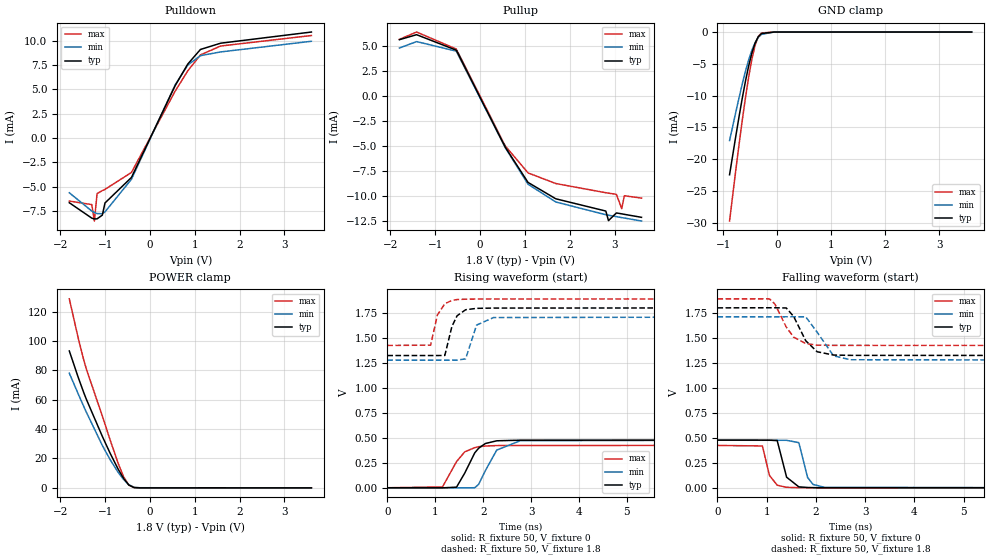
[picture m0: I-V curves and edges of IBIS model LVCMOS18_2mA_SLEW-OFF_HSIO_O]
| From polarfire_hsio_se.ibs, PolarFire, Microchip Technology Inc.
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|   Model LVCMOS18_2mA_SLEW-OFF_HSIO_O
[Model]   LVCMOS18_2mA_SLEW-OFF_HSIO_O
Model_type   Output
Polarity   Non-Inverting
Enable   Active-High
Vmeas =   0.9
Cref =   5p
Rref =   1M
|   typ   min   max
C_comp_pullup   1.335e-12   1.335e-12   1.380e-12
C_comp_pulldown  1.335e-12   1.335e-12   1.380e-12
[Temperature Range]  25C   100C   -40C
[Voltage Range]  1.8   1.71   1.89
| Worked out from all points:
|   slope of the pulldown table from 0 to 0.27 V, typ, clamps not added: 99.7 ohm
|   slope of the pullup table from 0 to 0.27 V, typ, clamps not added: 106 ohm
|   GND clamp passes 1 mA (typ) near -0.37 V on its own axis
|   POWER clamp passes 1 mA (typ) near -0.43 V on its own axis
|   rising waveform, R_fixture 50, V_fixture 0: 20-80 % time 313ps typ, 317ps min, 308ps max; typ from 0 V to 0.477 V
|   rising waveform, R_fixture 50, V_fixture 1.8: 20-80 % time 169ps typ, 176ps min, 162ps max; typ from 1.32 V to 1.8 V
|   falling waveform, R_fixture 50, V_fixture 0: 20-80 % time 145ps typ, 151ps min, 133ps max; typ from 0.477 V to 0 V
|   falling waveform, R_fixture 50, V_fixture 1.8: 20-80 % time 319ps typ, 303ps min, 311ps max; typ from 1.8 V to 1.32 V
[GND Clamp]
| Voltage   I(typ)   I(min)   I(max)
-885.9mV  -22.44mA   -17.06mA   -29.71mA
-767.8mV  -16.25mA   -12.52mA   -21.53mA
-708.7mV  -13.24mA   -10.28mA   -17.6mA
-649.7mV  -10.37mA   -8.138mA   -13.83mA
-590.6mV  -7.705mA   -6.148mA   -10.3mA
-531.6mV  -5.322mA   -4.371mA   -7.074mA
-472.5mV  -3.308mA   -2.865mA   -4.286mA
-413.4mV  -1.757mA   -1.684mA   -2.101mA
-354.4mV  -739.5uA   -855.1uA   -713.7uA
-295.3mV  -232.3uA   -363.2uA   -148.3uA
-59.06mV  -489.8nA   -2.616uA   -234.3nA
3.6V      0A         0A         0A
[POWER Clamp]
| Voltage   I(typ)   I(min)   I(max)
-1.8V     93.16mA    78.01mA    128.6mA
-1.595V   74.64mA    63.48mA    101.1mA
-1.477V   64.73mA    55.33mA    86.9mA
-1.417V   60.07mA    51.32mA    80.62mA
-1.063V   35.01mA    28.82mA    48.82mA
-885.9mV  23.32mA    19.01mA    32.31mA
-708.7mV  12.62mA    10.48mA    16.53mA
-590.6mV  6.476mA    5.751mA    7.626mA
-472.5mV  1.932mA    2.149mA    1.873mA
-354.4mV  154uA      351.2uA    209.6uA
-236.2mV  4.969uA    79.11uA    52.63uA
3.6V      0A         0A         0A
[Pullup]
| Voltage   I(typ)   I(min)   I(max)
-1.8V     5.675mA    4.838mA    5.71mA
-1.417V   6.176mA    5.485mA    6.443mA
-531.6mV  4.619mA    4.521mA    4.733mA
562.5mV   -5.136mA   -5.176mA   -5.006mA
1.069V    -8.657mA   -8.838mA   -7.701mA
1.688V    -10.3mA    -10.62mA   -8.767mA
2.804V    -11.53mA   -11.9mA    -9.691mA
2.863V    -12.49mA   -11.95mA   -9.732mA
3.04V     -11.72mA   -12.09mA   -9.855mA
3.158V    -11.81mA   -12.19mA   -11.29mA
3.217V    -11.86mA   -12.23mA   -9.994mA
3.6V      -12.16mA   -12.53mA   -10.23mA
[Pulldown]
| Voltage   I(typ)   I(min)   I(max)
-1.8V     -6.666mA   -5.639mA   -6.495mA
-1.299V   -8.251mA   -7.52mA    -6.857mA
-1.24V    -8.335mA   -7.673mA   -8.549mA
-1.181V   -8.326mA   -7.787mA   -5.727mA
-1.063V   -7.941mA   -7.79mA    -5.412mA
-1.004V   -6.69mA    -7.608mA   -5.288mA
-413.4mV  -4.058mA   -4.243mA   -3.547mA
562.5mV   5.408mA    5.494mA    4.84mA
843.8mV   7.63mA     7.525mA    6.932mA
1.125V    9.124mA    8.486mA    8.564mA
1.575V    9.769mA    8.87mA     9.478mA
3.6V      10.92mA    9.969mA    10.56mA
[Ramp]
dV/dt_r   0.286369/0.313004n  0.285848/0.317021n  0.254387/0.307782n
dV/dt_f   0.285972/0.318969n  0.259822/0.302939n  0.279803/0.310814n
R_load = 50
[Rising Waveform]
R_fixture = 50
V_fixture = 0
V_fixture_min = 0
V_fixture_max = 0
| Time   V(typ)   V(min)   V(max)
0s        3.09uV     3.497uV    6.32uV
1.152ns   -646.7uV   -643.3uV   8.588mV
1.444ns   5.878mV    -807.3uV   261.4mV
1.617ns   147.8mV    -904.4uV   359.8mV
1.825ns   349.4mV    452.6uV    401.6mV
1.906ns   395.7mV    34.22mV    410.8mV
2.046ns   442.7mV    170.9mV    417.5mV
2.284ns   469.9mV    377.5mV    422.1mV
2.779ns   476mV      471.3mV    423.2mV
10ns      477.3mV    476.4mV    424mV
[Rising Waveform]
R_fixture = 50
V_fixture = 1.8
V_fixture_min = 1.71
V_fixture_max = 1.89
| Time   V(typ)   V(min)   V(max)
0s        1.323V     1.277V     1.424V
904ps     1.323V     1.277V     1.427V
1.045ns   1.323V     1.277V     1.729V
1.2ns     1.324V     1.277V     1.841V
1.348ns   1.614V     1.277V     1.875V
1.456ns   1.721V     1.277V     1.883V
1.634ns   1.781V     1.29V      1.887V
1.863ns   1.795V     1.628V     1.888V
2.218ns   1.798V     1.703V     1.889V
10ns      1.8V       1.71V      1.89V
[Falling Waveform]
R_fixture = 50
V_fixture = 0
V_fixture_min = 0
V_fixture_max = 0
| Time   V(typ)   V(min)   V(max)
0s        477.3mV    476.4mV    424mV
913ps     476.9mV    475.8mV    418.9mV
1.057ns   476.8mV    475.7mV    123.5mV
1.214ns   472.7mV    475.6mV    26.48mV
1.405ns   106.4mV    475.5mV    5.314mV
1.653ns   10.03mV    452.1mV    1.813mV
1.832ns   3.488mV    103mV      904.7uV
1.942ns   2.057mV    34.14mV    804.2uV
2.177ns   1.116mV    5.153mV    781uV
10ns      4.458uV    5.254uV    6.631uV
[Falling Waveform]
R_fixture = 50
V_fixture = 1.8
V_fixture_min = 1.71
V_fixture_max = 1.89
| Time   V(typ)   V(min)   V(max)
0s        1.8V       1.71V      1.89V
1.056ns   1.801V     1.71V      1.89V
1.166ns   1.801V     1.71V      1.839V
1.398ns   1.799V     1.711V     1.608V
1.548ns   1.714V     1.711V     1.507V
1.794ns   1.471V     1.71V      1.443V
2.026ns   1.361V     1.556V     1.427V
2.36ns    1.328V     1.32V      1.425V
2.705ns   1.325V     1.281V     1.425V
10ns      1.323V     1.277V     1.424V
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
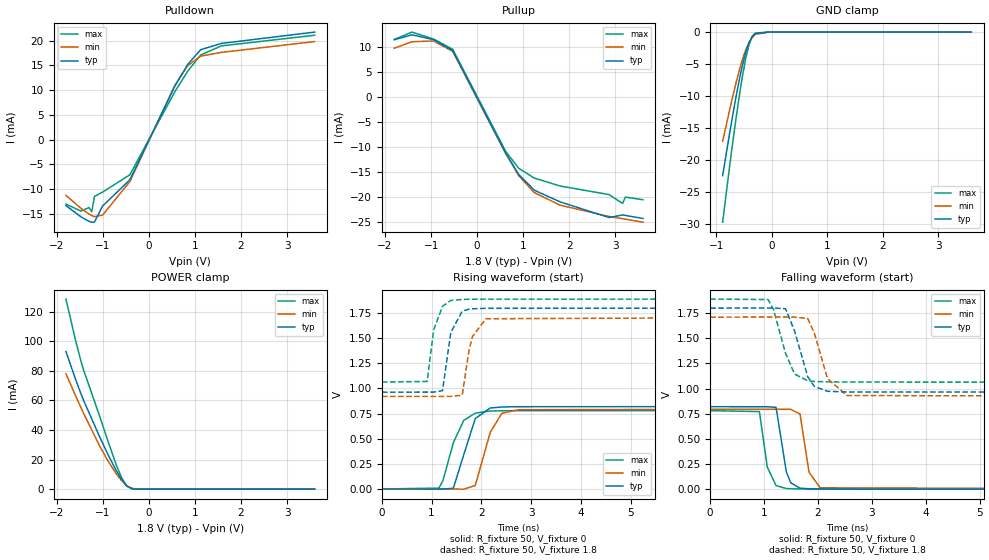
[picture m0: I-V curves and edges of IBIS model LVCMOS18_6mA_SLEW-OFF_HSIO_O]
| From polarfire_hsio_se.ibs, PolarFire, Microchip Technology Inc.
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|   Model LVCMOS18_6mA_SLEW-OFF_HSIO_O
[Model]   LVCMOS18_6mA_SLEW-OFF_HSIO_O
Model_type   Output
Polarity   Non-Inverting
Enable   Active-High
Vmeas =   0.9
Cref =   5p
Rref =   1M
|   typ   min   max
C_comp_pullup   1.335e-12   1.335e-12   1.380e-12
C_comp_pulldown  1.335e-12   1.335e-12   1.380e-12
[Temperature Range]  25C   100C   -40C
[Voltage Range]  1.8   1.71   1.89
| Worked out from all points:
|   slope of the pulldown table from 0 to 0.27 V, typ, clamps not added: 50 ohm
|   slope of the pullup table from 0 to 0.27 V, typ, clamps not added: 53.2 ohm
|   GND clamp passes 1 mA (typ) near -0.37 V on its own axis
|   POWER clamp passes 1 mA (typ) near -0.43 V on its own axis
|   rising waveform, R_fixture 50, V_fixture 0: 20-80 % time 275ps typ, 273ps min, 299ps max; typ from 0 V to 0.82 V
|   rising waveform, R_fixture 50, V_fixture 1.8: 20-80 % time 170ps typ, 177ps min, 165ps max; typ from 0.964 V to 1.8 V
|   falling waveform, R_fixture 50, V_fixture 0: 20-80 % time 139ps typ, 140ps min, 132ps max; typ from 0.82 V to 0 V
|   falling waveform, R_fixture 50, V_fixture 1.8: 20-80 % time 262ps typ, 265ps min, 271ps max; typ from 1.8 V to 0.964 V
[GND Clamp]
| Voltage   I(typ)   I(min)   I(max)
-885.9mV  -22.44mA   -17.06mA   -29.71mA
-767.8mV  -16.25mA   -12.52mA   -21.53mA
-708.7mV  -13.24mA   -10.28mA   -17.6mA
-649.7mV  -10.37mA   -8.138mA   -13.83mA
-590.6mV  -7.705mA   -6.148mA   -10.3mA
-531.6mV  -5.322mA   -4.371mA   -7.074mA
-472.5mV  -3.308mA   -2.865mA   -4.286mA
-413.4mV  -1.757mA   -1.684mA   -2.101mA
-354.4mV  -739.5uA   -855.1uA   -713.7uA
-295.3mV  -232.3uA   -363.2uA   -148.3uA
-59.06mV  -489.8nA   -2.616uA   -234.3nA
3.6V      0A         0A         0A
[POWER Clamp]
| Voltage   I(typ)   I(min)   I(max)
-1.8V     93.11mA    78.02mA    128.6mA
-1.595V   74.64mA    63.48mA    101.1mA
-1.477V   64.73mA    55.33mA    86.9mA
-1.417V   60.07mA    51.32mA    80.62mA
-1.063V   35.01mA    28.82mA    48.84mA
-885.9mV  23.32mA    19.01mA    32.31mA
-708.7mV  12.62mA    10.48mA    16.53mA
-590.6mV  6.476mA    5.751mA    7.626mA
-472.5mV  1.932mA    2.149mA    1.873mA
-354.4mV  154uA      469.9uA    209.6uA
-236.2mV  4.969uA    79.11uA    56.46uA
3.6V      0A         0A         0A
[Pullup]
| Voltage   I(typ)   I(min)   I(max)
-1.8V     11.37mA    9.67mA     11.42mA
-1.417V   12.35mA    10.97mA    12.89mA
-945mV    11.37mA    11.12mA    11.5mA
-531.6mV  9.235mA    9.041mA    9.465mA
618.8mV   -11.21mA   -11.31mA   -10.87mA
900mV     -15.45mA   -15.68mA   -14.23mA
1.238V    -18.6mA    -19.08mA   -16.19mA
1.8V      -20.94mA   -21.6mA    -17.78mA
2.863V    -24.06mA   -23.85mA   -19.49mA
3.158V    -23.55mA   -24.3mA    -21.25mA
3.217V    -23.64mA   -24.39mA   -19.99mA
3.6V      -24.24mA   -24.99mA   -20.52mA
[Pulldown]
| Voltage   I(typ)   I(min)   I(max)
-1.8V     -13.31mA   -11.25mA   -13mA
-1.477V   -15.56mA   -13.84mA   -14.41mA
-1.299V   -16.49mA   -15.02mA   -13.7mA
-1.24V    -16.66mA   -15.32mA   -14.55mA
-1.181V   -16.64mA   -15.55mA   -11.45mA
-1.004V   -13.38mA   -15.21mA   -10.58mA
-413.4mV  -8.105mA   -8.474mA   -7.089mA
562.5mV   10.79mA    10.96mA    9.671mA
843.8mV   15.22mA    15mA       13.85mA
1.125V    18.19mA    16.89mA    17.12mA
1.575V    19.46mA    17.65mA    18.96mA
3.6V      21.75mA    19.83mA    21.11mA
[Ramp]
dV/dt_r   0.492094/0.274729n  0.476674/0.272538n  0.468329/0.298524n
dV/dt_f   0.501814/0.262317n  0.473087/0.265403n  0.495773/0.27099n
R_load = 50
[Rising Waveform]
R_fixture = 50
V_fixture = 0
V_fixture_min = 0
V_fixture_max = 0
| Time   V(typ)   V(min)   V(max)
0s        2.644uV    2.881uV    5.267uV
1.146ns   -898.3uV   -670.8uV   8.607mV
1.229ns   -1.012mV   -719.5uV   84.63mV
1.438ns   7.438mV    -842.4uV   461.4mV
1.647ns   341.6mV    -1.898mV   682.9mV
1.878ns   701mV      34.49mV    754.4mV
2.178ns   805.9mV    561.5mV    775.8mV
2.412ns   815.7mV    753.4mV    778.5mV
2.75ns    818.8mV    789.1mV    779.5mV
10ns      820.2mV    794.5mV    780.6mV
[Rising Waveform]
R_fixture = 50
V_fixture = 1.8
V_fixture_min = 1.71
V_fixture_max = 1.89
| Time   V(typ)   V(min)   V(max)
0s        963.6mV    921.5mV    1.064V
910ps     964.1mV    921.4mV    1.07V
1.043ns   964.1mV    921.4mV    1.585V
1.22ns    978.5mV    921.4mV    1.818V
1.385ns   1.556V     921.4mV    1.876V
1.616ns   1.77V      932.9mV    1.886V
1.754ns   1.79V      1.386V     1.888V
1.82ns    1.793V     1.515V     1.888V
2.091ns   1.798V     1.694V     1.889V
10ns      1.8V       1.71V      1.89V
[Falling Waveform]
R_fixture = 50
V_fixture = 0
V_fixture_min = 0
V_fixture_max = 0
| Time   V(typ)   V(min)   V(max)
0s        820.2mV    794.5mV    780.6mV
913ps     819.5mV    794.1mV    771.1mV
1.06ns    819.4mV    794mV      218.8mV
1.222ns   813.6mV    793.9mV    35.61mV
1.413ns   172.3mV    793.9mV    6.375mV
1.494ns   63.29mV    793.8mV    4.187mV
1.667ns   9.845mV    747.2mV    2.101mV
1.833ns   4.288mV    169.4mV    1.487mV
2.039ns   1.889mV    13.54mV    970.2uV
10ns      4.001uV    4.73uV     5.853uV
[Falling Waveform]
R_fixture = 50
V_fixture = 1.8
V_fixture_min = 1.71
V_fixture_max = 1.89
| Time   V(typ)   V(min)   V(max)
0s        1.8V       1.71V      1.89V
1.075ns   1.801V     1.711V     1.885V
1.173ns   1.801V     1.711V     1.788V
1.397ns   1.794V     1.711V     1.352V
1.565ns   1.574V     1.711V     1.145V
1.81ns    1.117V     1.696V     1.077V
1.931ns   1.022V     1.553V     1.071V
2.176ns   972.7mV    1.099V     1.067V
2.537ns   966.2mV    931mV      1.065V
10ns      963.6mV    921.5mV    1.064V
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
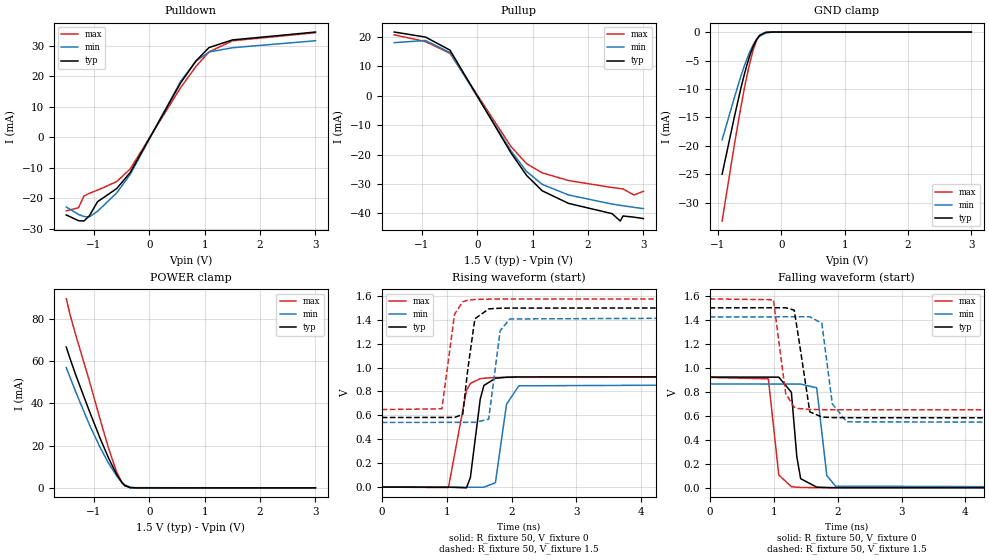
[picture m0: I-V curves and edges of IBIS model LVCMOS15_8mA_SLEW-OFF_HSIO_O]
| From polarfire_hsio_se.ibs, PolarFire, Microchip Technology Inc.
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|   Model LVCMOS15_8mA_SLEW-OFF_HSIO_O
[Model]   LVCMOS15_8mA_SLEW-OFF_HSIO_O
Model_type   Output
Polarity   Non-Inverting
Enable   Active-High
Vmeas =   0.75
Cref =   5p
Rref =   1M
|   typ   min   max
C_comp_pullup   1.335e-12   1.335e-12   1.380e-12
C_comp_pulldown  1.335e-12   1.335e-12   1.380e-12
[Temperature Range]  25C   100C   -40C
[Voltage Range]  1.5   1.425   1.575
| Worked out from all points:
|   slope of the pulldown table from 0 to 0.225 V, typ, clamps not added: 30.1 ohm
|   slope of the pullup table from 0 to 0.225 V, typ, clamps not added: 30.2 ohm
|   GND clamp passes 1 mA (typ) near -0.37 V on its own axis
|   POWER clamp passes 1 mA (typ) near -0.43 V on its own axis
|   rising waveform, R_fixture 50, V_fixture 0: 20-80 % time 126ps typ, 128ps min, 156ps max; typ from 0 V to 0.923 V
|   rising waveform, R_fixture 50, V_fixture 1.5: 20-80 % time 110ps typ, 110ps min, 122ps max; typ from 0.582 V to 1.5 V
|   falling waveform, R_fixture 50, V_fixture 0: 20-80 % time 91.1ps typ, 91.1ps min, 90.3ps max; typ from 0.923 V to 0 V
|   falling waveform, R_fixture 50, V_fixture 1.5: 20-80 % time 112ps typ, 119ps min, 114ps max; typ from 1.5 V to 0.582 V
[GND Clamp]
| Voltage   I(typ)   I(min)   I(max)
-935.2mV  -24.96mA   -18.92mA   -33.17mA
-738.3mV  -14.72mA   -11.38mA   -19.54mA
-639.8mV  -9.903mA   -7.788mA   -13.22mA
-590.6mV  -7.7mA     -6.143mA   -10.29mA
-541.4mV  -5.692mA   -4.645mA   -7.577mA
-492.2mV  -3.93mA    -3.33mA    -5.153mA
-443mV    -2.467mA   -2.229mA   -3.103mA
-393.7mV  -1.355mA   -1.366mA   -1.54mA
-344.5mV  -621.9uA   -750.5uA   -567.2uA
-246.1mV  -72.57uA   -154.2uA   -30.93uA
-147.7mV  -5.325uA   -20.63uA   -1.146uA
3V        0A         0A         0A
[POWER Clamp]
| Voltage   I(typ)   I(min)   I(max)
-1.5V     66.64mA    56.9mA     89.46mA
-1.427V   60.81mA    51.96mA    81.57mA
-1.329V   53.43mA    45.4mA     72.34mA
-1.083V   36.31mA    29.95mA    50.59mA
-885.9mV  23.26mA    18.98mA    32.15mA
-738.3mV  14.22mA    11.74mA    18.91mA
-590.6mV  6.331mA    5.649mA    7.47mA
-492.2mV  2.418mA    2.54mA     2.302mA
-443mV    1.134mA    1.422mA    896.4uA
-344.5mV  93.53uA    323uA      39.71uA
-246.1mV  3.484uA    76.21uA    1.361uA
3V        0A         0A         0A
[Pullup]
| Voltage   I(typ)   I(min)   I(max)
-1.5V     21.63mA    18.02mA    20.68mA
-935.2mV  19.92mA    18.75mA    18.37mA
-492.2mV  15.48mA    14.66mA    14.41mA
609.4mV   -19.45mA   -18.72mA   -17.29mA
890.6mV   -27.08mA   -25.75mA   -23.1mA
1.172V    -32.3mA    -30.13mA   -26.2mA
1.648V    -36.59mA   -33.73mA   -28.83mA
2.435V    -40.08mA   -36.83mA   -31.2mA
2.583V    -42.58mA   -37.25mA   -31.56mA
2.632V    -40.87mA   -37.39mA   -31.68mA
2.829V    -41.27mA   -37.93mA   -33.74mA
3V        -41.75mA   -38.38mA   -32.49mA
[Pulldown]
| Voltage   I(typ)   I(min)   I(max)
-1.5V     -25.45mA   -22.84mA   -24.12mA
-1.28V    -27.33mA   -25.27mA   -23.09mA
-1.181V   -27.44mA   -25.97mA   -19.25mA
-1.083V   -25.71mA   -26.08mA   -18.35mA
-935.2mV  -21.11mA   -24.24mA   -17.32mA
-590.6mV  -16.81mA   -18.24mA   -14.53mA
-344.5mV  -11.51mA   -12.11mA   -10.34mA
562.5mV   17.79mA    18.29mA    16.26mA
843.8mV   25.11mA    25.06mA    23.29mA
1.078V    29.46mA    28mA       28.04mA
1.5V      31.96mA    29.4mA     31.68mA
3V        34.55mA    31.69mA    34.33mA
[Ramp]
dV/dt_r   0.554086/0.1257n  0.51933/0.127747n  0.551931/0.156382n
dV/dt_f   0.550552/0.11238n  0.53034/0.11946n  0.55563/0.114456n
R_load = 50
[Rising Waveform]
R_fixture = 50
V_fixture = 0
V_fixture_min = 0
V_fixture_max = 0
| Time   V(typ)   V(min)   V(max)
0s        1.606uV    1.724uV    2.5uV
1.028ns   -809.7uV   -623.3uV   -4.196mV
1.305ns   -6.307mV   -791.7uV   807.4mV
1.366ns   79.83mV    -828.8uV   867.6mV
1.518ns   736.5mV    -921.2uV   907mV
1.574ns   850mV      -955.3uV   911mV
1.752ns   910.5mV    36.92mV    917.3mV
1.923ns   919.6mV    693.1mV    918.3mV
2.112ns   921.8mV    847.4mV    918.7mV
10ns      923.5mV    865.6mV    919.9mV
[Rising Waveform]
R_fixture = 50
V_fixture = 1.5
V_fixture_min = 1.425
V_fixture_max = 1.575
| Time   V(typ)   V(min)   V(max)
0s        582.4mV    541.1mV    648.9mV
927ps     582.9mV    541.5mV    655.1mV
1.122ns   583mV      541.6mV    1.446V
1.248ns   608.4mV    541.7mV    1.551V
1.326ns   985.1mV    541.7mV    1.564V
1.435ns   1.408V     541.8mV    1.57V
1.648ns   1.491V     567.8mV    1.573V
1.825ns   1.497V     1.309V     1.574V
1.975ns   1.498V     1.407V     1.574V
10ns      1.5V       1.425V     1.575V
[Falling Waveform]
R_fixture = 50
V_fixture = 0
V_fixture_min = 0
V_fixture_max = 0
| Time   V(typ)   V(min)   V(max)
0s        923.5mV    865.6mV    919.9mV
918ps     922.7mV    865.1mV    908.7mV
1.081ns   922.6mV    865mV      107.1mV
1.278ns   796.4mV    864.9mV    9.661mV
1.363ns   258.9mV    864.8mV    5.426mV
1.423ns   76.42mV    864.8mV    3.85mV
1.674ns   5.918mV    833.7mV    1.636mV
1.832ns   2.659mV    102.1mV    1.21mV
1.969ns   1.693mV    14mV       972.4uV
10ns      2.565uV    2.947uV    3.271uV
[Falling Waveform]
R_fixture = 50
V_fixture = 1.5
V_fixture_min = 1.425
V_fixture_max = 1.575
| Time   V(typ)   V(min)   V(max)
0s        1.5V       1.425V     1.575V
997ps     1.501V     1.425V     1.568V
1.188ns   1.501V     1.426V     787.1mV
1.322ns   1.481V     1.426V     671.7mV
1.388ns   1.261V     1.426V     661.4mV
1.566ns   633.2mV    1.426V     653.1mV
1.754ns   590.3mV    1.372V     651.6mV
1.918ns   585.7mV    699.7mV    650.8mV
2.143ns   584.5mV    550.2mV    650.1mV
10ns      582.4mV    541.1mV    648.9mV
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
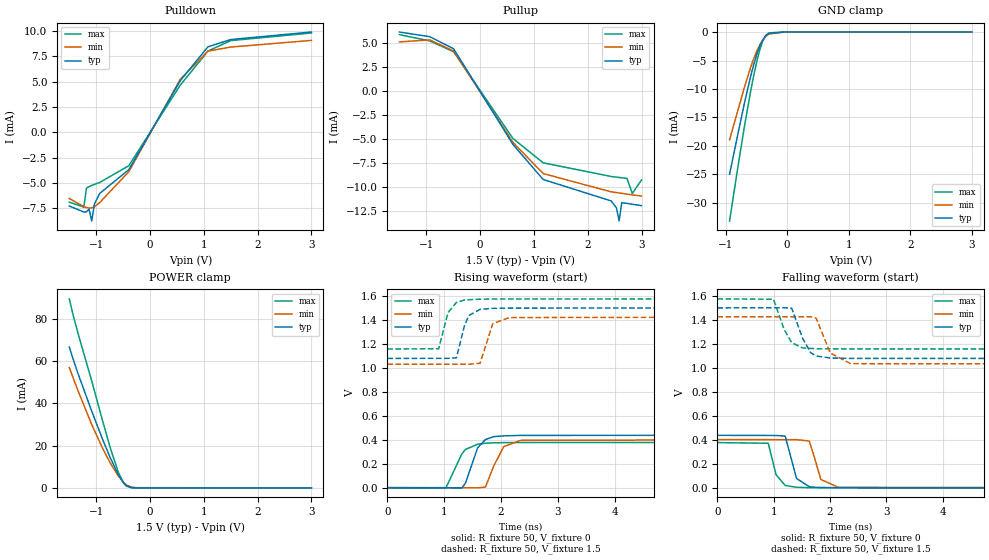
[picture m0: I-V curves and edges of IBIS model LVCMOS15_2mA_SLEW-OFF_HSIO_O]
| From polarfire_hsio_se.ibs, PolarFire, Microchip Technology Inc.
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|   Model LVCMOS15_2mA_SLEW-OFF_HSIO_O
[Model]   LVCMOS15_2mA_SLEW-OFF_HSIO_O
Model_type   Output
Polarity   Non-Inverting
Enable   Active-High
Vmeas =   0.75
Cref =   5p
Rref =   1M
|   typ   min   max
C_comp_pullup   1.335e-12   1.335e-12   1.380e-12
C_comp_pulldown  1.335e-12   1.335e-12   1.380e-12
[Temperature Range]  25C   100C   -40C
[Voltage Range]  1.5   1.425   1.575
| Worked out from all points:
|   slope of the pulldown table from 0 to 0.225 V, typ, clamps not added: 105 ohm
|   slope of the pullup table from 0 to 0.225 V, typ, clamps not added: 106 ohm
|   GND clamp passes 1 mA (typ) near -0.37 V on its own axis
|   POWER clamp passes 1 mA (typ) near -0.43 V on its own axis
|   rising waveform, R_fixture 50, V_fixture 0: 20-80 % time 207ps typ, 211ps min, 223ps max; typ from 0 V to 0.438 V
|   rising waveform, R_fixture 50, V_fixture 1.5: 20-80 % time 141ps typ, 143ps min, 142ps max; typ from 1.08 V to 1.5 V
|   falling waveform, R_fixture 50, V_fixture 0: 20-80 % time 127ps typ, 135ps min, 115ps max; typ from 0.438 V to 0 V
|   falling waveform, R_fixture 50, V_fixture 1.5: 20-80 % time 195ps typ, 206ps min, 191ps max; typ from 1.5 V to 1.08 V
[GND Clamp]
| Voltage   I(typ)   I(min)   I(max)
-935.2mV  -24.96mA   -18.92mA   -33.17mA
-787.5mV  -17.27mA   -13.27mA   -22.86mA
-689.1mV  -12.26mA   -9.546mA   -16.31mA
-590.6mV  -7.7mA     -6.143mA   -10.29mA
-541.4mV  -5.692mA   -4.645mA   -7.577mA
-492.2mV  -3.93mA    -3.33mA    -5.153mA
-443mV    -2.467mA   -2.229mA   -3.103mA
-393.7mV  -1.355mA   -1.366mA   -1.54mA
-344.5mV  -621.9uA   -750.5uA   -567.2uA
-295.3mV  -232uA     -362.9uA   -147.8uA
-49.22mV  -334.5nA   -1.943uA   -112.6nA
3V        0A         0A         0A
[POWER Clamp]
| Voltage   I(typ)   I(min)   I(max)
-1.5V     66.64mA    56.9mA     89.46mA
-1.427V   60.81mA    51.96mA    81.57mA
-1.329V   53.43mA    45.4mA     72.34mA
-1.083V   36.31mA    29.95mA    50.59mA
-885.9mV  23.26mA    18.98mA    32.15mA
-738.3mV  14.22mA    11.74mA    18.91mA
-590.6mV  6.331mA    5.649mA    7.47mA
-492.2mV  2.418mA    2.54mA     2.302mA
-443mV    1.134mA    1.422mA    896.4uA
-344.5mV  93.53uA    323uA      39.71uA
-246.1mV  3.484uA    76.21uA    1.361uA
3V        0A         0A         0A
[Pullup]
| Voltage   I(typ)   I(min)   I(max)
-1.5V     6.18mA     5.149mA    5.908mA
-935.2mV  5.694mA    5.357mA    5.249mA
-492.2mV  4.426mA    4.189mA    4.12mA
609.4mV   -5.56mA    -5.352mA   -4.942mA
1.172V    -9.231mA   -8.611mA   -7.489mA
2.435V    -11.47mA   -10.52mA   -8.914mA
2.534V    -12.19mA   -10.6mA    -8.983mA
2.583V    -13.57mA   -10.64mA   -9.017mA
2.632V    -11.66mA   -10.68mA   -9.051mA
2.73V     -11.73mA   -10.76mA   -9.119mA
2.829V    -11.82mA   -10.84mA   -10.69mA
3V        -11.96mA   -10.96mA   -9.281mA
[Pulldown]
| Voltage   I(typ)   I(min)   I(max)
-1.5V     -7.275mA   -6.528mA   -6.891mA
-1.23V    -7.866mA   -7.338mA   -7.385mA
-1.181V   -7.85mA    -7.425mA   -5.506mA
-1.132V   -7.585mA   -7.471mA   -5.363mA
-1.083V   -8.754mA   -7.457mA   -5.246mA
-1.034V   -7.088mA   -7.358mA   -5.143mA
-935.2mV  -6.034mA   -6.933mA   -4.952mA
-393.7mV  -3.684mA   -3.888mA   -3.295mA
562.5mV   5.099mA    5.238mA    4.655mA
1.078V    8.442mA    8.014mA    8.023mA
1.5V      9.156mA    8.415mA    9.05mA
3V        9.898mA    9.072mA    9.804mA
[Ramp]
dV/dt_r   0.262503/0.206641n  0.241393/0.211397n  0.22635/0.222743n
dV/dt_f   0.253149/0.195296n  0.23726/0.206113n  0.250884/0.191459n
R_load = 50
[Rising Waveform]
R_fixture = 50
V_fixture = 0
V_fixture_min = 0
V_fixture_max = 0
| Time   V(typ)   V(min)   V(max)
0s        1.828uV    2.241uV    2.956uV
1.032ns   -823.9uV   -448.1uV   21.93uV
1.314ns   -1.271mV   -571.2uV   284.6mV
1.376ns   39.81mV    -598.2uV   319.2mV
1.588ns   332.5mV    -690.7uV   362.3mV
1.725ns   401.6mV    4.507mV    371.1mV
1.87ns    425.8mV    179.5mV    374.3mV
2.046ns   432.3mV    342mV      375.9mV
2.342ns   436.2mV    395mV      376.7mV
10ns      437.5mV    402.3mV    377.3mV
[Rising Waveform]
R_fixture = 50
V_fixture = 1.5
V_fixture_min = 1.425
V_fixture_max = 1.575
| Time   V(typ)   V(min)   V(max)
0s        1.078V     1.03V      1.157V
903ps     1.079V     1.03V      1.159V
1.067ns   1.079V     1.03V      1.46V
1.216ns   1.083V     1.03V      1.546V
1.354ns   1.347V     1.03V      1.565V
1.432ns   1.436V     1.03V      1.568V
1.631ns   1.487V     1.038V     1.572V
1.855ns   1.496V     1.368V     1.574V
2.146ns   1.498V     1.419V     1.574V
10ns      1.5V       1.425V     1.575V
[Falling Waveform]
R_fixture = 50
V_fixture = 0
V_fixture_min = 0
V_fixture_max = 0
| Time   V(typ)   V(min)   V(max)
0s        437.5mV    402.3mV    377.2mV
902ps     436.7mV    401.9mV    371.6mV
1.04ns    436.6mV    401.8mV    109.5mV
1.203ns   431.2mV    401.8mV    19.88mV
1.404ns   78.46mV    401.7mV    4.632mV
1.63ns    9.522mV    390.2mV    1.655mV
1.72ns    4.849mV    256.8mV    1.184mV
1.835ns   3.018mV    70.03mV    767.1uV
2.146ns   1.086mV    4.334mV    738uV
10ns      3.065uV    3.216uV    2.098uV
[Falling Waveform]
R_fixture = 50
V_fixture = 1.5
V_fixture_min = 1.425
V_fixture_max = 1.575
| Time   V(typ)   V(min)   V(max)
0s        1.5V       1.425V     1.575V
995ps     1.501V     1.426V     1.572V
1.184ns   1.501V     1.426V     1.32V
1.318ns   1.497V     1.426V     1.21V
1.513ns   1.245V     1.426V     1.166V
1.654ns   1.127V     1.426V     1.162V
1.752ns   1.099V     1.414V     1.159V
2.003ns   1.082V     1.124V     1.158V
2.364ns   1.079V     1.035V     1.158V
10ns      1.078V     1.03V      1.157V
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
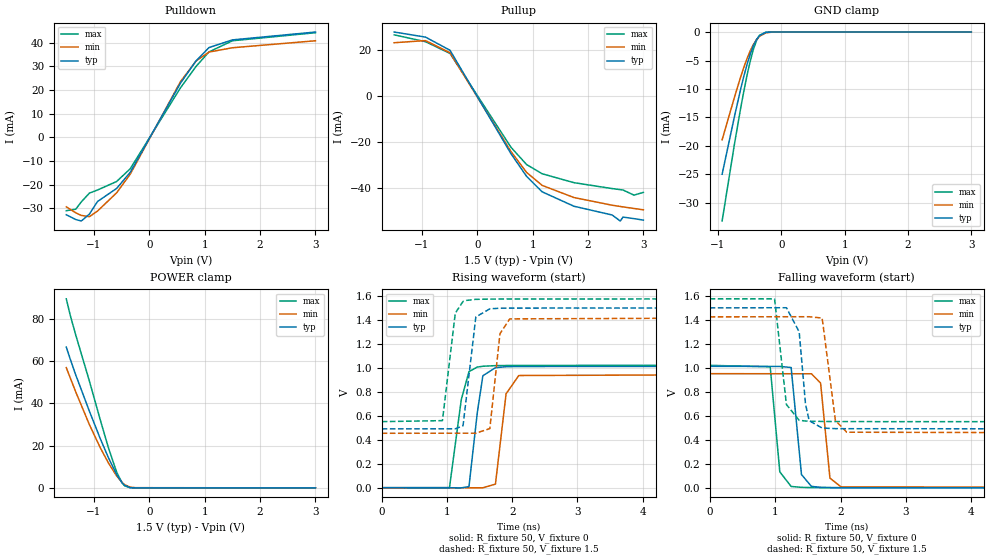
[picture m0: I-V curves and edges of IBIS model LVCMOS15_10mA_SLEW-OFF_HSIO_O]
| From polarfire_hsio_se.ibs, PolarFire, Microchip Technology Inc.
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|   Model LVCMOS15_10mA_SLEW-OFF_HSIO_O
[Model]   LVCMOS15_10mA_SLEW-OFF_HSIO_O
Model_type   Output
Polarity   Non-Inverting
Enable   Active-High
Vmeas =   0.75
Cref =   5p
Rref =   1M
|   typ   min   max
C_comp_pullup   1.335e-12   1.335e-12   1.380e-12
C_comp_pulldown  1.335e-12   1.335e-12   1.380e-12
[Temperature Range]  25C   100C   -40C
[Voltage Range]  1.5   1.425   1.575
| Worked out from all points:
|   slope of the pulldown table from 0 to 0.225 V, typ, clamps not added: 23.5 ohm
|   slope of the pullup table from 0 to 0.225 V, typ, clamps not added: 23.5 ohm
|   GND clamp passes 1 mA (typ) near -0.37 V on its own axis
|   POWER clamp passes 1 mA (typ) near -0.43 V on its own axis
|   rising waveform, R_fixture 50, V_fixture 0: 20-80 % time 110ps typ, 113ps min, 136ps max; typ from 0 V to 1.01 V
|   rising waveform, R_fixture 50, V_fixture 1.5: 20-80 % time 108ps typ, 102ps min, 118ps max; typ from 0.491 V to 1.5 V
|   falling waveform, R_fixture 50, V_fixture 0: 20-80 % time 79.6ps typ, 83.8ps min, 85.1ps max; typ from 1.01 V to 0 V
|   falling waveform, R_fixture 50, V_fixture 1.5: 20-80 % time 97.7ps typ, 105ps min, 101ps max; typ from 1.5 V to 0.491 V
[GND Clamp]
| Voltage   I(typ)   I(min)   I(max)
-935.2mV  -24.96mA   -18.92mA   -33.17mA
-738.3mV  -14.72mA   -11.38mA   -19.54mA
-639.8mV  -9.903mA   -7.788mA   -13.22mA
-590.6mV  -7.7mA     -6.143mA   -10.29mA
-541.4mV  -5.692mA   -4.645mA   -7.577mA
-492.2mV  -3.93mA    -3.33mA    -5.153mA
-443mV    -2.467mA   -2.229mA   -3.103mA
-393.7mV  -1.355mA   -1.366mA   -1.54mA
-344.5mV  -621.9uA   -750.5uA   -567.2uA
-246.1mV  -72.57uA   -154.2uA   -30.93uA
-147.7mV  -5.325uA   -20.63uA   -1.146uA
3V        0A         0A         0A
[POWER Clamp]
| Voltage   I(typ)   I(min)   I(max)
-1.5V     66.64mA    56.9mA     89.46mA
-1.427V   60.81mA    51.96mA    81.57mA
-1.329V   53.43mA    45.4mA     72.34mA
-1.083V   36.31mA    29.95mA    50.59mA
-885.9mV  23.26mA    18.98mA    32.15mA
-738.3mV  14.22mA    11.74mA    18.91mA
-590.6mV  6.331mA    5.649mA    7.47mA
-492.2mV  2.418mA    2.54mA     2.302mA
-443mV    1.134mA    1.422mA    896.4uA
-344.5mV  93.53uA    323uA      39.71uA
-246.1mV  3.484uA    76.21uA    1.361uA
3V        0A         0A         0A
[Pullup]
| Voltage   I(typ)   I(min)   I(max)
-1.5V     27.81mA    23.17mA    26.59mA
-935.2mV  25.61mA    24.1mA     23.62mA
-492.2mV  19.9mA     18.84mA    18.53mA
609.4mV   -25mA      -24.07mA   -22.22mA
890.6mV   -34.81mA   -33.11mA   -29.69mA
1.172V    -41.53mA   -38.74mA   -33.69mA
1.746V    -47.79mA   -44.01mA   -37.56mA
2.435V    -51.58mA   -47.34mA   -40.12mA
2.583V    -54.2mA    -47.89mA   -40.58mA
2.632V    -52.49mA   -48.07mA   -40.74mA
2.829V    -53.16mA   -48.76mA   -42.96mA
3V        -53.79mA   -49.33mA   -41.78mA
[Pulldown]
| Voltage   I(typ)   I(min)   I(max)
-1.5V     -32.73mA   -29.38mA   -31.03mA
-1.329V   -34.74mA   -31.9mA    -30.38mA
-1.23V    -35.37mA   -33.01mA   -27.33mA
-1.083V   -32.46mA   -33.53mA   -23.59mA
-935.2mV  -27.12mA   -31.15mA   -22.27mA
-590.6mV  -21.61mA   -23.45mA   -18.68mA
-344.5mV  -14.78mA   -15.56mA   -13.29mA
562.5mV   22.86mA    23.5mA     20.88mA
843.8mV   32.26mA    32.2mA     29.92mA
1.078V    37.88mA    35.98mA    36.04mA
1.5V      41.11mA    37.79mA    40.74mA
3V        44.43mA    40.74mA    44.14mA
[Ramp]
dV/dt_r   0.607763/0.110433n  0.570974/0.113237n  0.612526/0.135771n
dV/dt_f   0.605499/97.7243p  0.582664/0.105375n  0.614391/0.101442n
R_load = 50
[Rising Waveform]
R_fixture = 50
V_fixture = 0
V_fixture_min = 0
V_fixture_max = 0
| Time   V(typ)   V(min)   V(max)
0s        1.564uV    1.629uV    2.412uV
1.039ns   -786.9uV   -500uV     781.6uV
1.22ns    -1.266mV   -587.4uV   735.2mV
1.338ns   8.574mV    -644.3uV   968.2mV
1.465ns   623.7mV    -705.7uV   1.006V
1.551ns   933.8mV    -747.2uV   1.013V
1.744ns   1.001V     30.04mV    1.018V
1.907ns   1.009V     783mV      1.019V
2.102ns   1.011V     935.7mV    1.02V
10ns      1.013V     951.6mV    1.021V
[Rising Waveform]
R_fixture = 50
V_fixture = 1.5
V_fixture_min = 1.425
V_fixture_max = 1.575
| Time   V(typ)   V(min)   V(max)
0s        490.8mV    453.9mV    551mV
931ps     491.3mV    454.3mV    559.4mV
1.128ns   491.3mV    454.4mV    1.456V
1.247ns   516.4mV    454.5mV    1.554V
1.298ns   752.2mV    454.5mV    1.562V
1.443ns   1.424V     454.6mV    1.571V
1.658ns   1.492V     493mV      1.573V
1.813ns   1.497V     1.284V     1.574V
1.963ns   1.498V     1.408V     1.574V
10ns      1.5V       1.425V     1.575V
[Falling Waveform]
R_fixture = 50
V_fixture = 0
V_fixture_min = 0
V_fixture_max = 0
| Time   V(typ)   V(min)   V(max)
0s        1.013V     951.6mV    1.021V
925ps     1.012V     951.1mV    1.009V
1.072ns   1.012V     951mV      133.1mV
1.245ns   1.003V     950.9mV    11.53mV
1.403ns   110.7mV    950.8mV    4.188mV
1.555ns   12.18mV    950.7mV    2.064mV
1.695ns   4.474mV    873.1mV    1.46mV
1.838ns   2.335mV    81.11mV    1.231mV
2.006ns   1.419mV    8.528mV    961.8uV
10ns      2uV        2.71uV     2.693uV
[Falling Waveform]
R_fixture = 50
V_fixture = 1.5
V_fixture_min = 1.425
V_fixture_max = 1.575
| Time   V(typ)   V(min)   V(max)
0s        1.5V       1.425V     1.575V
992ps     1.501V     1.426V     1.575V
1.173ns   1.501V     1.426V     694.1mV
1.368ns   1.3V       1.426V     562.9mV
1.465ns   696.2mV    1.426V     556.8mV
1.521ns   559.1mV    1.426V     555.4mV
1.719ns   498.4mV    1.415V     553.5mV
1.921ns   493.6mV    562.2mV    552.6mV
2.094ns   492.8mV    463.7mV    552.1mV
10ns      490.8mV    453.9mV    551mV
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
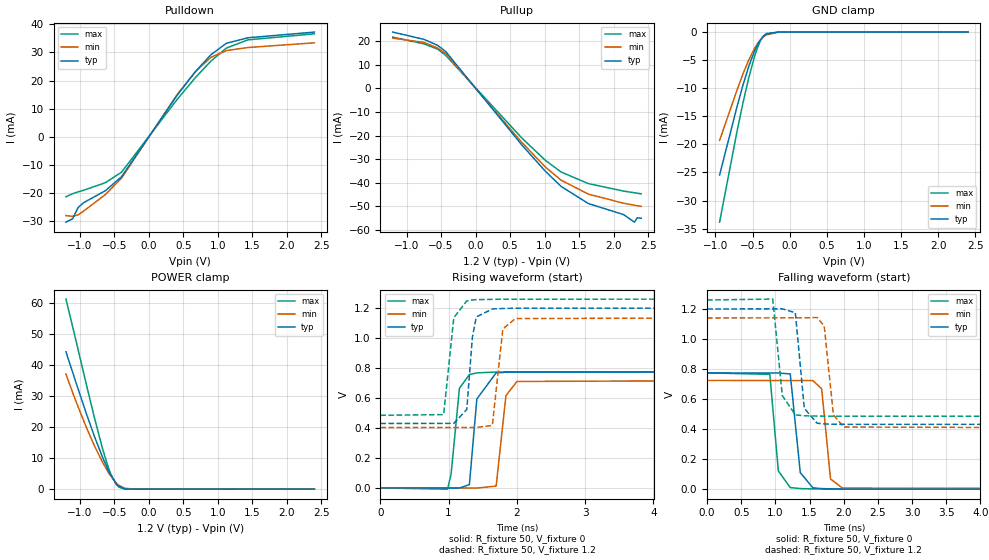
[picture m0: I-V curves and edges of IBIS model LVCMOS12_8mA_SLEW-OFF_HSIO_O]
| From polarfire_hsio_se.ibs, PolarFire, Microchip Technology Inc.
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|   Model LVCMOS12_8mA_SLEW-OFF_HSIO_O
[Model]   LVCMOS12_8mA_SLEW-OFF_HSIO_O
Model_type   Output
Polarity   Non-Inverting
Enable   Active-High
Vmeas =   0.6
Cref =   5p
Rref =   1M
|   typ   min   max
C_comp_pullup   1.335e-12   1.335e-12   1.380e-12
C_comp_pulldown  1.335e-12   1.335e-12   1.380e-12
[Temperature Range]  25C   100C   -40C
[Voltage Range]  1.2   1.14   1.26
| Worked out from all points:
|   slope of the pulldown table from 0 to 0.18 V, typ, clamps not added: 27.1 ohm
|   slope of the pullup table from 0 to 0.18 V, typ, clamps not added: 27.2 ohm
|   GND clamp passes 1 mA (typ) near -0.37 V on its own axis
|   POWER clamp passes 1 mA (typ) near -0.44 V on its own axis
|   rising waveform, R_fixture 50, V_fixture 0: 20-80 % time 82.1ps typ, 86.3ps min, 92.1ps max; typ from 0 V to 0.774 V
|   rising waveform, R_fixture 50, V_fixture 1.2: 20-80 % time 79.7ps typ, 78.7ps min, 90ps max; typ from 0.43 V to 1.2 V
|   falling waveform, R_fixture 50, V_fixture 0: 20-80 % time 72ps typ, 74.6ps min, 71.9ps max; typ from 0.774 V to 0 V
|   falling waveform, R_fixture 50, V_fixture 1.2: 20-80 % time 83ps typ, 87.9ps min, 82.3ps max; typ from 1.2 V to 0.43 V
[GND Clamp]
| Voltage   I(typ)   I(min)   I(max)
-945mV    -25.45mA   -19.29mA   -33.85mA
-708.7mV  -13.22mA   -10.27mA   -17.58mA
-630mV    -9.442mA   -7.443mA   -12.61mA
-551.3mV  -6.071mA   -4.927mA   -8.091mA
-472.5mV  -3.303mA   -2.86mA    -4.278mA
-433.1mV  -2.213mA   -2.035mA   -2.745mA
-393.7mV  -1.354mA   -1.365mA   -1.538mA
-354.4mV  -738.1uA   -853.7uA   -711.7uA
-315mV    -352.4uA   -492.8uA   -262uA
-157.5mV  -6.952uA   -25.53uA   -1.531uA
-39.38mV  -223.3nA   -1.393uA   -60.97nA
2.4V      0A         0A         0A
[POWER Clamp]
| Voltage   I(typ)   I(min)   I(max)
-1.2V     44.33mA    37.1mA     61.33mA
-1.063V   34.96mA    28.78mA    48.71mA
-905.6mV  24.47mA    19.99mA    33.89mA
-787.5mV  17.03mA    14mA       23.06mA
-669.4mV  10.26mA    8.667mA    13.03mA
-590.6mV  6.299mA    5.605mA    7.313mA
-551.3mV  4.569mA    4.255mA    4.935mA
-472.5mV  1.839mA    2.031mA    1.558mA
-433.1mV  941.2uA    1.22mA     654.9uA
-354.4mV  127.4uA    330.6uA    47.34uA
-236.2mV  2.462uA    44.69uA    773.7nA
2.4V      0A         0A         0A
[Pullup]
| Voltage   I(typ)   I(min)   I(max)
-1.2V     23.79mA    21.22mA    21.66mA
-748.1mV  20.71mA    19.42mA    18.81mA
-551.3mV  18.21mA    17.06mA    16.57mA
-433.1mV  15.57mA    14.67mA    13.96mA
675mV     -24.15mA   -23.08mA   -21.21mA
1.012V    -35.15mA   -33.37mA   -30.52mA
1.239V    -41.55mA   -38.91mA   -35.45mA
1.633V    -48.79mA   -44.8mA    -40.35mA
2.145V    -53.49mA   -48.68mA   -43.53mA
2.303V    -56.7mA    -49.52mA   -44.25mA
2.342V    -54.83mA   -49.72mA   -44.43mA
2.4V      -55.03mA   -50mA      -44.68mA
[Pulldown]
| Voltage   I(typ)   I(min)   I(max)
-1.2V     -30.46mA   -28.11mA   -21.4mA
-1.103V   -29.23mA   -28.4mA    -20.3mA
-1.024V   -25.27mA   -27.84mA   -19.66mA
-945mV    -23.52mA   -26.53mA   -19.08mA
-630mV    -19.27mA   -20.64mA   -16.4mA
-393.7mV  -14.25mA   -14.76mA   -12.62mA
412.5mV   14.8mA     15.05mA    13.31mA
675mV     23.16mA    23.13mA    21.04mA
900mV     29.19mA    28.28mA    26.92mA
1.125V    33.29mA    30.7mA     31.58mA
1.436V    35.24mA    31.77mA    34.5mA
2.4V      37.27mA    33.45mA    36.66mA
[Ramp]
dV/dt_r   0.464353/82.0884p  0.434421/86.3387p  0.464717/92.0904p
dV/dt_f   0.461868/83.0501p  0.442051/87.9178p  0.465169/82.2935p
R_load = 50
[Rising Waveform]
R_fixture = 50
V_fixture = 0
V_fixture_min = 0
V_fixture_max = 0
| Time   V(typ)   V(min)   V(max)
0s        1.22uV     1.337uV    1.793uV
985ps     -588.4uV   -415.3uV   -7.986mV
1.036ns   -618.9uV   -436.9uV   92.56mV
1.158ns   -691.9uV   -488.5uV   664.4mV
1.304ns   22.36mV    -550.2uV   756.4mV
1.413ns   593.5mV    -596.3uV   767.7mV
1.696ns   767.8mV    12.53mV    773.1mV
1.839ns   771.6mV    616.1mV    773.6mV
2.001ns   772.8mV    710.4mV    773.8mV
10ns      773.9mV    724mV      774.5mV
[Rising Waveform]
R_fixture = 50
V_fixture = 1.2
V_fixture_min = 1.14
V_fixture_max = 1.26
| Time   V(typ)   V(min)   V(max)
0s        430.2mV    403.2mV    484.7mV
927ps     430.7mV    403.5mV    489.3mV
1.076ns   430.8mV    403.5mV    1.136V
1.266ns   523.8mV    403.6mV    1.248V
1.348ns   1.007V     403.6mV    1.254V
1.406ns   1.141V     403.6mV    1.256V
1.64ns    1.194V     416.9mV    1.258V
1.794ns   1.197V     1.061V     1.259V
1.978ns   1.199V     1.13V      1.259V
10ns      1.2V       1.14V      1.26V
[Falling Waveform]
R_fixture = 50
V_fixture = 0
V_fixture_min = 0
V_fixture_max = 0
| Time   V(typ)   V(min)   V(max)
0s        773.9mV    724mV      774.5mV
917ps     773.5mV    723.5mV    764.6mV
1.042ns   773.4mV    723.5mV    121.7mV
1.216ns   767.4mV    723.4mV    10.62mV
1.363ns   110.6mV    723.3mV    4.09mV
1.547ns   8.856mV    723.2mV    1.72mV
1.676ns   3.886mV    668.7mV    1.326mV
1.806ns   2.074mV    67.99mV    1.125mV
1.98ns    1.126mV    7.391mV    857.7uV
10ns      1.896uV    2.354uV    2.572uV
[Falling Waveform]
R_fixture = 50
V_fixture = 1.2
V_fixture_min = 1.14
V_fixture_max = 1.26
| Time   V(typ)   V(min)   V(max)
0s        1.2V       1.14V      1.26V
960ps     1.201V     1.141V     1.266V
1.1ns     1.201V     1.141V     623mV
1.291ns   1.175V     1.141V     494.7mV
1.422ns   538.1mV    1.141V     488.7mV
1.61ns    439.1mV    1.143V     486.8mV
1.713ns   434.6mV    1.087V     486.3mV
1.848ns   432.5mV    494.4mV    486.1mV
2ns       431.9mV    413.8mV    485.9mV
10ns      430.2mV    403.2mV    484.7mV
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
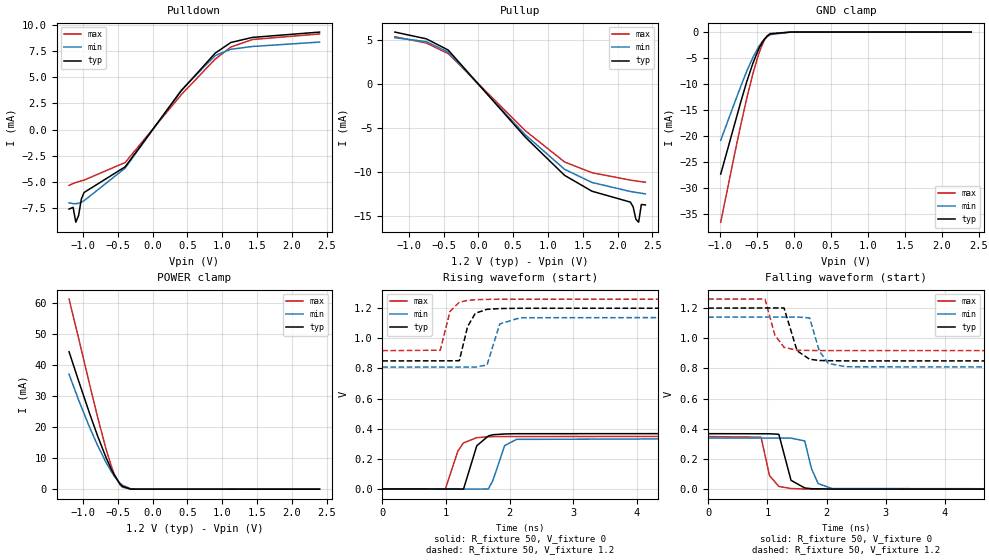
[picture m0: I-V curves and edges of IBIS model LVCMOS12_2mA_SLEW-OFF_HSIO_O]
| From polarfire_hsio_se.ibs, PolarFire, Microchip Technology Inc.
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|   Model LVCMOS12_2mA_SLEW-OFF_HSIO_O
[Model]   LVCMOS12_2mA_SLEW-OFF_HSIO_O
Model_type   Output
Polarity   Non-Inverting
Enable   Active-High
Vmeas =   0.6
Cref =   5p
Rref =   1M
|   typ   min   max
C_comp_pullup   1.335e-12   1.335e-12   1.380e-12
C_comp_pulldown  1.335e-12   1.335e-12   1.380e-12
[Temperature Range]  25C   100C   -40C
[Voltage Range]  1.2   1.14   1.26
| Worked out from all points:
|   slope of the pulldown table from 0 to 0.18 V, typ, clamps not added: 108 ohm
|   slope of the pullup table from 0 to 0.18 V, typ, clamps not added: 109 ohm
|   GND clamp passes 1 mA (typ) near -0.37 V on its own axis
|   POWER clamp passes 1 mA (typ) near -0.44 V on its own axis
|   rising waveform, R_fixture 50, V_fixture 0: 20-80 % time 144ps typ, 155ps min, 159ps max; typ from 0 V to 0.368 V
|   rising waveform, R_fixture 50, V_fixture 1.2: 20-80 % time 127ps typ, 128ps min, 129ps max; typ from 0.85 V to 1.2 V
|   falling waveform, R_fixture 50, V_fixture 0: 20-80 % time 118ps typ, 130ps min, 109ps max; typ from 0.368 V to 0 V
|   falling waveform, R_fixture 50, V_fixture 1.2: 20-80 % time 147ps typ, 158ps min, 142ps max; typ from 1.2 V to 0.85 V
[GND Clamp]
| Voltage   I(typ)   I(min)   I(max)
-984.4mV  -27.36mA   -20.85mA   -36.63mA
-787.5mV  -17.26mA   -13.26mA   -22.85mA
-708.7mV  -13.22mA   -10.27mA   -17.58mA
-630mV    -9.442mA   -7.443mA   -12.61mA
-551.3mV  -6.071mA   -4.927mA   -8.091mA
-472.5mV  -3.303mA   -2.86mA    -4.278mA
-433.1mV  -2.213mA   -2.035mA   -2.745mA
-393.7mV  -1.354mA   -1.365mA   -1.538mA
-354.4mV  -738.1uA   -853.7uA   -711.7uA
-315mV    -352.4uA   -492.8uA   -262uA
-39.38mV  -223.3nA   -1.393uA   -60.97nA
2.4V      0A         0A         0A
[POWER Clamp]
| Voltage   I(typ)   I(min)   I(max)
-1.2V     44.33mA    37.08mA    61.33mA
-1.063V   34.96mA    28.78mA    48.72mA
-905.6mV  24.47mA    19.99mA    33.89mA
-787.5mV  17.03mA    14mA       23.06mA
-669.4mV  10.26mA    8.667mA    13.03mA
-590.6mV  6.299mA    5.605mA    7.313mA
-551.3mV  4.569mA    4.255mA    4.935mA
-472.5mV  1.839mA    2.031mA    1.558mA
-433.1mV  941.2uA    1.284mA    654.9uA
-315mV    34.81uA    149.8uA    11.13uA
-236.2mV  2.462uA    44.69uA    773.7nA
2.4V      0A         0A         0A
[Pullup]
| Voltage   I(typ)   I(min)   I(max)
-1.2V     5.947mA    5.308mA    5.413mA
-748.1mV  5.179mA    4.857mA    4.701mA
-433.1mV  3.895mA    3.659mA    3.492mA
675mV     -6.042mA   -5.773mA   -5.304mA
1.239V    -10.39mA   -9.701mA   -8.866mA
1.633V    -12.2mA    -11.2mA    -10.09mA
2.184V    -13.44mA   -12.23mA   -10.93mA
2.224V    -13.98mA   -12.28mA   -10.98mA
2.263V    -15.39mA   -12.33mA   -11.02mA
2.303V    -15.73mA   -12.38mA   -11.07mA
2.342V    -13.71mA   -12.43mA   -11.11mA
2.4V      -13.76mA   -12.5mA    -11.17mA
[Pulldown]
| Voltage   I(typ)   I(min)   I(max)
-1.2V     -7.622mA   -7.03mA    -5.358mA
-1.142V   -7.458mA   -7.1mA     -5.173mA
-1.103V   -8.88mA    -7.106mA   -5.079mA
-1.063V   -8.243mA   -7.066mA   -4.996mA
-1.024V   -6.679mA   -6.969mA   -4.918mA
-984.4mV  -6.034mA   -6.821mA   -4.845mA
-393.7mV  -3.572mA   -3.698mA   -3.162mA
412.5mV   3.712mA    3.775mA    3.338mA
900mV     7.319mA    7.089mA    6.745mA
1.125V    8.342mA    7.691mA    7.905mA
1.436V    8.828mA    7.96mA     8.625mA
2.4V      9.338mA    8.381mA    9.161mA
[Ramp]
dV/dt_r   0.220678/0.144317n  0.203215/0.154976n  0.209235/0.15867n
dV/dt_f   0.210281/0.146668n  0.198927/0.158305n  0.205428/0.141867n
R_load = 50
[Rising Waveform]
R_fixture = 50
V_fixture = 0
V_fixture_min = 0
V_fixture_max = 0
| Time   V(typ)   V(min)   V(max)
0s        1.11uV     1.558uV    1.699uV
990ps     -545.6uV   -513uV     -1.495mV
1.188ns   -654.9uV   -616uV     251.8mV
1.276ns   -1.593mV   -661.7uV   305.3mV
1.485ns   286.6mV    -770.3uV   340.3mV
1.668ns   351.7mV    -271.3uV   346mV
1.738ns   359.6mV    56.07mV    346.7mV
1.923ns   364.7mV    287.3mV    347.8mV
2.111ns   366.5mV    328.9mV    347.8mV
10ns      367.8mV    338.7mV    348.7mV
[Rising Waveform]
R_fixture = 50
V_fixture = 1.2
V_fixture_min = 1.14
V_fixture_max = 1.26
| Time   V(typ)   V(min)   V(max)
0s        849.5mV    808.4mV    917.6mV
910ps     850.1mV    808.7mV    920.5mV
1.064ns   850.2mV    808.7mV    1.178V
1.21ns    851.1mV    808.8mV    1.239V
1.341ns   1.078V     808.8mV    1.251V
1.463ns   1.166V     808.8mV    1.256V
1.647ns   1.192V     822.8mV    1.258V
1.846ns   1.197V     1.095V     1.259V
2.167ns   1.199V     1.136V     1.259V
10ns      1.2V       1.14V      1.26V
[Falling Waveform]
R_fixture = 50
V_fixture = 0
V_fixture_min = 0
V_fixture_max = 0
| Time   V(typ)   V(min)   V(max)
0s        367.8mV    338.7mV    348.7mV
893ps     367.1mV    338.4mV    344.3mV
1.035ns   367mV      338.3mV    90.27mV
1.193ns   363.7mV    338.2mV    18.02mV
1.399ns   58.6mV     338.2mV    4.398mV
1.63ns    8.109mV    319.9mV    1.248mV
1.746ns   3.044mV    134.3mV    886.8uV
1.858ns   2.259mV    36.63mV    772.1uV
2.092ns   743.3uV    4.345mV    541.2uV
10ns      620.3nV    2.565uV    2.187uV
[Falling Waveform]
R_fixture = 50
V_fixture = 1.2
V_fixture_min = 1.14
V_fixture_max = 1.26
| Time   V(typ)   V(min)   V(max)
0s        1.2V       1.14V      1.26V
959ps     1.201V     1.141V     1.26V
1.126ns   1.201V     1.141V     1.021V
1.281ns   1.201V     1.141V     940.3mV
1.501ns   917.3mV    1.141V     920.8mV
1.713ns   861mV      1.135V     919.4mV
1.877ns   852.9mV    915mV      918.4mV
2.027ns   851.5mV    833.7mV    918.4mV
2.327ns   850.3mV    811mV      918.4mV
10ns      849.5mV    808.4mV    917.6mV
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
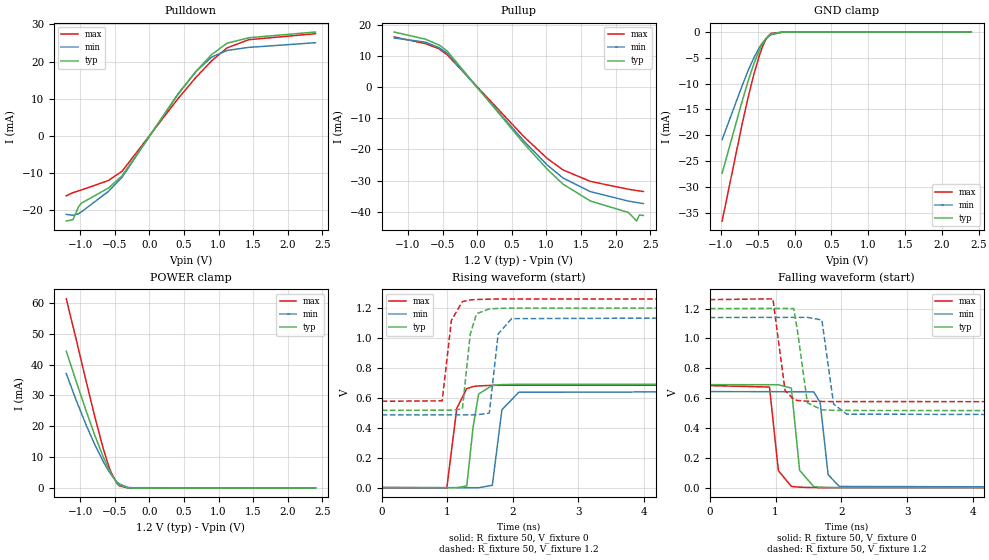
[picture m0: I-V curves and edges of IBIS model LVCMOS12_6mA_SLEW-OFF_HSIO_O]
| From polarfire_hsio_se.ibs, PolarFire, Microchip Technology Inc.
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|   Model LVCMOS12_6mA_SLEW-OFF_HSIO_O
[Model]   LVCMOS12_6mA_SLEW-OFF_HSIO_O
Model_type   Output
Polarity   Non-Inverting
Enable   Active-High
Vmeas =   0.6
Cref =   5p
Rref =   1M
|   typ   min   max
C_comp_pullup   1.335e-12   1.335e-12   1.380e-12
C_comp_pulldown  1.335e-12   1.335e-12   1.380e-12
[Temperature Range]  25C   100C   -40C
[Voltage Range]  1.2   1.14   1.26
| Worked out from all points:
|   slope of the pulldown table from 0 to 0.18 V, typ, clamps not added: 36.1 ohm
|   slope of the pullup table from 0 to 0.18 V, typ, clamps not added: 36.2 ohm
|   GND clamp passes 1 mA (typ) near -0.37 V on its own axis
|   POWER clamp passes 1 mA (typ) near -0.44 V on its own axis
|   rising waveform, R_fixture 50, V_fixture 0: 20-80 % time 94.4ps typ, 98.9ps min, 106ps max; typ from 0 V to 0.691 V
|   rising waveform, R_fixture 50, V_fixture 1.2: 20-80 % time 88.5ps typ, 85.1ps min, 95.6ps max; typ from 0.516 V to 1.2 V
|   falling waveform, R_fixture 50, V_fixture 0: 20-80 % time 81.3ps typ, 87.5ps min, 81.7ps max; typ from 0.691 V to 0 V
|   falling waveform, R_fixture 50, V_fixture 1.2: 20-80 % time 96.4ps typ, 103ps min, 95.4ps max; typ from 1.2 V to 0.516 V
[GND Clamp]
| Voltage   I(typ)   I(min)   I(max)
-984.4mV  -27.36mA   -20.85mA   -36.63mA
-708.7mV  -13.22mA   -10.27mA   -17.58mA
-630mV    -9.442mA   -7.443mA   -12.61mA
-551.3mV  -6.071mA   -4.927mA   -8.091mA
-472.5mV  -3.303mA   -2.86mA    -4.278mA
-433.1mV  -2.213mA   -2.035mA   -2.745mA
-393.7mV  -1.354mA   -1.365mA   -1.538mA
-354.4mV  -738.1uA   -853.7uA   -711.7uA
-315mV    -352.4uA   -492.8uA   -262uA
-157.5mV  -6.952uA   -25.53uA   -1.531uA
-39.38mV  -223.3nA   -1.393uA   -60.97nA
2.4V      0A         0A         0A
[POWER Clamp]
| Voltage   I(typ)   I(min)   I(max)
-1.2V     44.33mA    37.08mA    61.33mA
-1.063V   34.96mA    28.78mA    48.72mA
-905.6mV  24.47mA    19.99mA    33.89mA
-787.5mV  17.03mA    14mA       23.06mA
-669.4mV  10.26mA    8.667mA    13.03mA
-590.6mV  6.299mA    5.605mA    7.313mA
-551.3mV  4.569mA    4.255mA    4.935mA
-472.5mV  1.839mA    2.031mA    1.558mA
-433.1mV  941.2uA    1.284mA    654.9uA
-315mV    34.81uA    149.8uA    11.13uA
-236.2mV  2.462uA    44.69uA    773.7nA
2.4V      0A         0A         0A
[Pullup]
| Voltage   I(typ)   I(min)   I(max)
-1.2V     17.84mA    15.92mA    16.25mA
-748.1mV  15.53mA    14.57mA    14.11mA
-551.3mV  13.66mA    12.79mA    12.43mA
-433.1mV  11.68mA    10.97mA    10.48mA
675mV     -18.11mA   -17.31mA   -15.91mA
1.012V    -26.36mA   -25.03mA   -22.9mA
1.239V    -31.17mA   -29.19mA   -26.59mA
1.633V    -36.59mA   -33.58mA   -30.27mA
2.184V    -40.31mA   -36.64mA   -32.83mA
2.303V    -43.05mA   -37.09mA   -33.23mA
2.342V    -41.13mA   -37.23mA   -33.36mA
2.4V      -41.25mA   -37.44mA   -33.54mA
[Pulldown]
| Voltage   I(typ)   I(min)   I(max)
-1.2V     -22.85mA   -21.08mA   -16.06mA
-1.103V   -22.48mA   -21.3mA    -15.23mA
-1.024V   -19.08mA   -20.89mA   -14.75mA
-984.4mV  -18.09mA   -20.44mA   -14.53mA
-590.6mV  -13.98mA   -14.88mA   -11.96mA
-393.7mV  -10.69mA   -11.07mA   -9.471mA
412.5mV   11.11mA    11.29mA    9.993mA
675mV     17.38mA    17.35mA    15.79mA
900mV     21.9mA     21.2mA     20.2mA
1.125V    24.96mA    23mA       23.69mA
1.436V    26.41mA    23.81mA    25.88mA
2.4V      27.94mA    25.07mA    27.49mA
[Ramp]
dV/dt_r   0.414402/94.363p  0.386479/98.9102p  0.410553/0.105622n
dV/dt_f   0.410251/96.3675p  0.392703/0.103472n  0.41024/95.428p
R_load = 50
[Rising Waveform]
R_fixture = 50
V_fixture = 0
V_fixture_min = 0
V_fixture_max = 0
| Time   V(typ)   V(min)   V(max)
0s        1.197uV    1.382uV    1.773uV
994ps     -774.3uV   -607.4uV   -1.769mV
1.146ns   -892.9uV   -700.5uV   529.2mV
1.299ns   11.03mV    -794.3uV   660.9mV
1.394ns   400.6mV    -852.4uV   674.5mV
1.479ns   624.1mV    -904.5uV   679mV
1.689ns   682.5mV    15.17mV    682.7mV
1.835ns   687.6mV    519.4mV    683.1mV
2.093ns   689.5mV    636.5mV    683.4mV
10ns      690.7mV    644.1mV    684.3mV
[Rising Waveform]
R_fixture = 50
V_fixture = 1.2
V_fixture_min = 1.14
V_fixture_max = 1.26
| Time   V(typ)   V(min)   V(max)
0s        516.2mV    485.5mV    576.3mV
923ps     516.6mV    485.5mV    579.2mV
1.064ns   516.7mV    485.6mV    1.117V
1.232ns   525mV      485.6mV    1.242V
1.351ns   1.023V     485.6mV    1.253V
1.448ns   1.161V     485.6mV    1.256V
1.643ns   1.193V     497.4mV    1.258V
1.778ns   1.196V     1.026V     1.259V
1.984ns   1.198V     1.128V     1.259V
10ns      1.2V       1.14V      1.26V
[Falling Waveform]
R_fixture = 50
V_fixture = 0
V_fixture_min = 0
V_fixture_max = 0
| Time   V(typ)   V(min)   V(max)
0s        690.7mV    644.1mV    684.3mV
908ps     690.3mV    643.6mV    674.8mV
1.043ns   690.3mV    643.5mV    114.9mV
1.24ns    667.8mV    643.4mV    9.571mV
1.365ns   117.8mV    643.3mV    4.462mV
1.58ns    7.931mV    642mV      1.686mV
1.677ns   4.375mV    571.9mV    1.326mV
1.798ns   2.365mV    87.85mV    1.143mV
1.968ns   1.283mV    9.325mV    886.2uV
10ns      2.181uV    2.653uV    2.504uV
[Falling Waveform]
R_fixture = 50
V_fixture = 1.2
V_fixture_min = 1.14
V_fixture_max = 1.26
| Time   V(typ)   V(min)   V(max)
0s        1.2V       1.14V      1.26V
960ps     1.201V     1.141V     1.265V
1.144ns   1.201V     1.141V     652.5mV
1.277ns   1.2V       1.141V     591.4mV
1.337ns   1.037V     1.141V     584.7mV
1.483ns   569.5mV    1.141V     579.8mV
1.703ns   522.4mV    1.124V     578.2mV
1.881ns   518.6mV    561.1mV    577.6mV
2.08ns    517.9mV    493.3mV    577.3mV
10ns      516.2mV    485.5mV    576.3mV
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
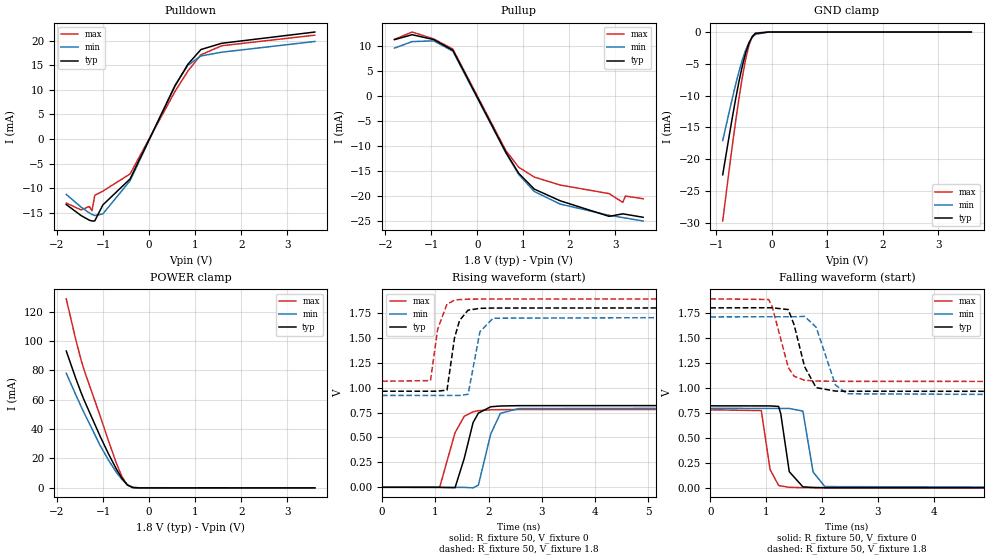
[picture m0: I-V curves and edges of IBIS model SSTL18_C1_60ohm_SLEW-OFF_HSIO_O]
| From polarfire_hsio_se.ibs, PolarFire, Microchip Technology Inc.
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|   Model SSTL18_C1_60ohm_SLEW-OFF_HSIO_O
[Model]   SSTL18_C1_60ohm_SLEW-OFF_HSIO_O
Model_type   Output
Polarity   Non-Inverting
Enable   Active-High
Vmeas =   0.9
Cref =   5p
Rref =   50
Vref =   0.9
|   typ   min   max
C_comp_pullup   1.335e-12   1.335e-12   1.380e-12
C_comp_pulldown  1.335e-12   1.335e-12   1.380e-12
[Temperature Range]  25C   100C   -40C
[Voltage Range]  1.8   1.71   1.89
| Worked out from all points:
|   slope of the pulldown table from 0 to 0.27 V, typ, clamps not added: 50 ohm
|   slope of the pullup table from 0 to 0.27 V, typ, clamps not added: 53.2 ohm
|   GND clamp passes 1 mA (typ) near -0.37 V on its own axis
|   POWER clamp passes 1 mA (typ) near -0.43 V on its own axis
|   rising waveform, R_fixture 50, V_fixture 0: 20-80 % time 221ps typ, 219ps min, 242ps max; typ from 0 V to 0.82 V
|   rising waveform, R_fixture 50, V_fixture 1.8: 20-80 % time 161ps typ, 163ps min, 157ps max; typ from 0.964 V to 1.8 V
|   falling waveform, R_fixture 50, V_fixture 0: 20-80 % time 132ps typ, 138ps min, 122ps max; typ from 0.82 V to 0 V
|   falling waveform, R_fixture 50, V_fixture 1.8: 20-80 % time 237ps typ, 271ps min, 224ps max; typ from 1.8 V to 0.964 V
[GND Clamp]
| Voltage   I(typ)   I(min)   I(max)
-885.9mV  -22.44mA   -17.06mA   -29.71mA
-767.8mV  -16.25mA   -12.52mA   -21.53mA
-708.7mV  -13.24mA   -10.28mA   -17.6mA
-649.7mV  -10.37mA   -8.138mA   -13.83mA
-590.6mV  -7.705mA   -6.148mA   -10.3mA
-531.6mV  -5.322mA   -4.371mA   -7.074mA
-472.5mV  -3.308mA   -2.865mA   -4.286mA
-413.4mV  -1.757mA   -1.684mA   -2.101mA
-354.4mV  -739.5uA   -855.1uA   -713.7uA
-295.3mV  -232.3uA   -363.2uA   -148.3uA
-59.06mV  -489.8nA   -2.616uA   -234.3nA
3.6V      0A         0A         0A
[POWER Clamp]
| Voltage   I(typ)   I(min)   I(max)
-1.8V     93.11mA    78.02mA    128.6mA
-1.595V   74.64mA    63.48mA    101.1mA
-1.477V   64.73mA    55.33mA    86.9mA
-1.417V   60.07mA    51.32mA    80.62mA
-1.063V   35.01mA    28.82mA    48.84mA
-885.9mV  23.32mA    19.01mA    32.31mA
-708.7mV  12.62mA    10.48mA    16.53mA
-590.6mV  6.476mA    5.751mA    7.626mA
-472.5mV  1.932mA    2.149mA    1.873mA
-354.4mV  154uA      469.9uA    209.6uA
-236.2mV  4.969uA    79.11uA    56.46uA
3.6V      0A         0A         0A
[Pullup]
| Voltage   I(typ)   I(min)   I(max)
-1.8V     11.37mA    9.671mA    11.42mA
-1.417V   12.35mA    10.97mA    12.89mA
-945mV    11.37mA    11.12mA    11.5mA
-531.6mV  9.235mA    9.041mA    9.465mA
618.8mV   -11.21mA   -11.31mA   -10.87mA
900mV     -15.45mA   -15.68mA   -14.23mA
1.238V    -18.6mA    -19.08mA   -16.19mA
1.8V      -20.94mA   -21.6mA    -17.78mA
2.863V    -24.06mA   -23.85mA   -19.5mA
3.158V    -23.55mA   -24.3mA    -21.25mA
3.217V    -23.64mA   -24.39mA   -19.99mA
3.6V      -24.24mA   -24.99mA   -20.52mA
[Pulldown]
| Voltage   I(typ)   I(min)   I(max)
-1.8V     -13.31mA   -11.25mA   -13mA
-1.477V   -15.56mA   -13.84mA   -14.41mA
-1.299V   -16.49mA   -15.02mA   -13.7mA
-1.24V    -16.66mA   -15.32mA   -14.55mA
-1.181V   -16.64mA   -15.55mA   -11.45mA
-1.004V   -13.38mA   -15.21mA   -10.58mA
-413.4mV  -8.105mA   -8.474mA   -7.089mA
562.5mV   10.79mA    10.96mA    9.671mA
843.8mV   15.22mA    15mA       13.85mA
1.125V    18.19mA    16.89mA    17.12mA
1.575V    19.46mA    17.65mA    18.96mA
3.6V      21.75mA    19.83mA    21.11mA
[Ramp]
dV/dt_r   0.492097/0.221385n  0.476682/0.219249n  0.468339/0.242188n
dV/dt_f   0.501817/0.237243n  0.473088/0.270699n  0.49578/0.224186n
R_load = 50
[Rising Waveform]
R_fixture = 50
V_fixture = 0
V_fixture_min = 0
V_fixture_max = 0
| Time   V(typ)   V(min)   V(max)
0s        2.644uV    2.881uV    5.267uV
1.083ns   -843.9uV   -642.5uV   2.086mV
1.371ns   -4.033mV   -814.2uV   547.9mV
1.544ns   290.7mV    -917.3uV   711.9mV
1.71ns    649.9mV    -5.556mV   757.8mV
1.809ns   744.2mV    21.31mV    768.5mV
2.042ns   807.9mV    536mV      777.4mV
2.223ns   815.4mV    742.2mV    778.7mV
2.568ns   818.8mV    789.6mV    779.6mV
10ns      820.2mV    794.5mV    780.6mV
[Rising Waveform]
R_fixture = 50
V_fixture = 1.8
V_fixture_min = 1.71
V_fixture_max = 1.89
| Time   V(typ)   V(min)   V(max)
0s        963.6mV    921.5mV    1.064V
910ps     963.8mV    921.4mV    1.07V
1.044ns   963.8mV    921.4mV    1.586V
1.22ns    974.7mV    921.4mV    1.837V
1.361ns   1.499V     921.4mV    1.877V
1.456ns   1.674V     921.4mV    1.883V
1.616ns   1.777V     932.9mV    1.887V
1.838ns   1.795V     1.56V      1.888V
2.085ns   1.798V     1.696V     1.889V
10ns      1.8V       1.71V      1.89V
[Falling Waveform]
R_fixture = 50
V_fixture = 0
V_fixture_min = 0
V_fixture_max = 0
| Time   V(typ)   V(min)   V(max)
0s        820.2mV    794.5mV    780.6mV
913ps     819.5mV    794.1mV    772.7mV
1.07ns    819.4mV    794mV      184.2mV
1.223ns   814.4mV    794mV      24.3mV
1.262ns   739.8mV    794mV      18.81mV
1.414ns   161.6mV    793.9mV    5.498mV
1.658ns   9.883mV    767.7mV    2.031mV
1.84ns    3.913mV    158.7mV    1.414mV
2.052ns   1.851mV    12.59mV    930.4uV
10ns      3.992uV    4.515uV    5.559uV
[Falling Waveform]
R_fixture = 50
V_fixture = 1.8
V_fixture_min = 1.71
V_fixture_max = 1.89
| Time   V(typ)   V(min)   V(max)
0s        1.8V       1.71V      1.89V
1.046ns   1.801V     1.711V     1.884V
1.11ns    1.801V     1.711V     1.809V
1.396ns   1.783V     1.711V     1.204V
1.501ns   1.63V      1.711V     1.116V
1.688ns   1.212V     1.715V     1.076V
1.895ns   1.002V     1.607V     1.068V
2.239ns   968mV      1.03V      1.066V
2.448ns   966.2mV    940.9mV    1.065V
10ns      963.6mV    921.5mV    1.064V
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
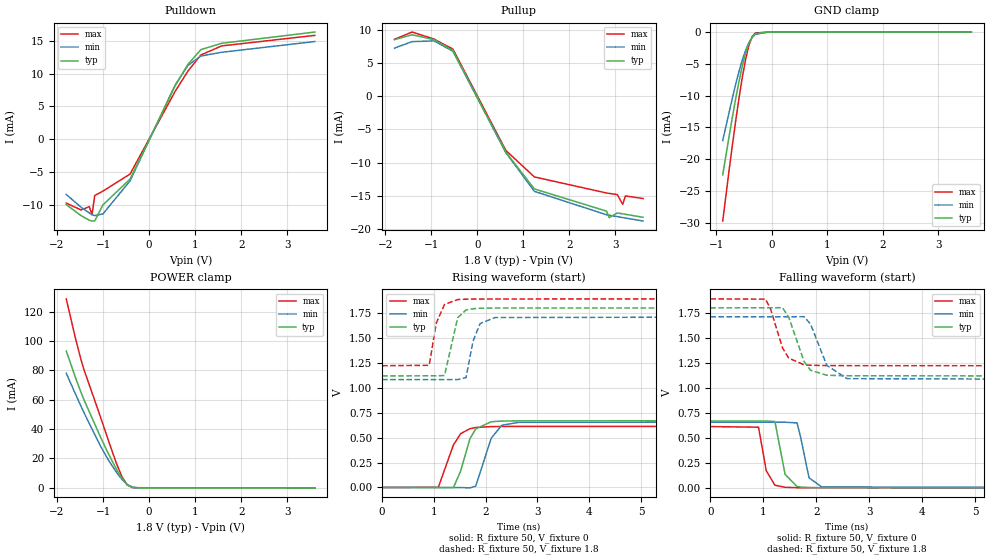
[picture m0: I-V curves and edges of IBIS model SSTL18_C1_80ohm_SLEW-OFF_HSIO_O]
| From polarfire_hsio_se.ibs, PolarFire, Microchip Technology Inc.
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|   Model SSTL18_C1_80ohm_SLEW-OFF_HSIO_O
[Model]   SSTL18_C1_80ohm_SLEW-OFF_HSIO_O
Model_type   Output
Polarity   Non-Inverting
Enable   Active-High
Vmeas =   0.9
Cref =   5p
Rref =   50
Vref =   0.9
|   typ   min   max
C_comp_pullup   1.335e-12   1.335e-12   1.380e-12
C_comp_pulldown  1.335e-12   1.335e-12   1.380e-12
[Temperature Range]  25C   100C   -40C
[Voltage Range]  1.8   1.71   1.89
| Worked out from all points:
|   slope of the pulldown table from 0 to 0.27 V, typ, clamps not added: 66.5 ohm
|   slope of the pullup table from 0 to 0.27 V, typ, clamps not added: 70.9 ohm
|   GND clamp passes 1 mA (typ) near -0.37 V on its own axis
|   POWER clamp passes 1 mA (typ) near -0.43 V on its own axis
|   rising waveform, R_fixture 50, V_fixture 0: 20-80 % time 244ps typ, 238ps min, 246ps max; typ from 0 V to 0.669 V
|   rising waveform, R_fixture 50, V_fixture 1.8: 20-80 % time 162ps typ, 167ps min, 158ps max; typ from 1.12 V to 1.8 V
|   falling waveform, R_fixture 50, V_fixture 0: 20-80 % time 136ps typ, 142ps min, 125ps max; typ from 0.669 V to 0 V
|   falling waveform, R_fixture 50, V_fixture 1.8: 20-80 % time 269ps typ, 289ps min, 254ps max; typ from 1.8 V to 1.12 V
[GND Clamp]
| Voltage   I(typ)   I(min)   I(max)
-885.9mV  -22.44mA   -17.06mA   -29.71mA
-767.8mV  -16.25mA   -12.52mA   -21.53mA
-708.7mV  -13.24mA   -10.28mA   -17.6mA
-649.7mV  -10.37mA   -8.138mA   -13.83mA
-590.6mV  -7.705mA   -6.148mA   -10.3mA
-531.6mV  -5.322mA   -4.371mA   -7.074mA
-472.5mV  -3.308mA   -2.865mA   -4.286mA
-413.4mV  -1.757mA   -1.684mA   -2.101mA
-354.4mV  -739.5uA   -855.1uA   -713.7uA
-295.3mV  -232.3uA   -363.2uA   -148.3uA
-59.06mV  -489.8nA   -2.616uA   -234.3nA
3.6V      0A         0A         0A
[POWER Clamp]
| Voltage   I(typ)   I(min)   I(max)
-1.8V     93.11mA    78.02mA    128.6mA
-1.595V   74.64mA    63.48mA    101.1mA
-1.477V   64.73mA    55.33mA    86.9mA
-1.417V   60.07mA    51.32mA    80.62mA
-1.063V   35.01mA    28.82mA    48.84mA
-885.9mV  23.32mA    19.01mA    32.31mA
-708.7mV  12.62mA    10.48mA    16.53mA
-590.6mV  6.476mA    5.751mA    7.626mA
-472.5mV  1.932mA    2.149mA    1.873mA
-354.4mV  154uA      469.9uA    209.6uA
-236.2mV  4.969uA    79.11uA    56.46uA
3.6V      0A         0A         0A
[Pullup]
| Voltage   I(typ)   I(min)   I(max)
-1.8V     8.524mA    7.253mA    8.567mA
-1.417V   9.262mA    8.226mA    9.67mA
-945mV    8.531mA    8.34mA     8.623mA
-531.6mV  6.927mA    6.782mA    7.101mA
618.8mV   -8.411mA   -8.484mA   -8.154mA
1.238V    -13.95mA   -14.31mA   -12.14mA
2.804V    -17.29mA   -17.84mA   -14.56mA
2.863V    -18.28mA   -17.91mA   -14.62mA
3.04V     -17.57mA   -18.12mA   -14.81mA
3.158V    -17.7mA    -18.26mA   -16.27mA
3.217V    -17.77mA   -18.33mA   -15mA
3.6V      -18.22mA   -18.78mA   -15.4mA
[Pulldown]
| Voltage   I(typ)   I(min)   I(max)
-1.8V     -9.988mA   -8.44mA    -9.755mA
-1.477V   -11.68mA   -10.39mA   -10.81mA
-1.299V   -12.37mA   -11.27mA   -10.29mA
-1.24V    -12.49mA   -11.5mA    -11.55mA
-1.181V   -12.47mA   -11.67mA   -8.591mA
-1.004V   -10.04mA   -11.41mA   -7.934mA
-413.4mV  -6.086mA   -6.361mA   -5.319mA
562.5mV   8.107mA    8.227mA    7.257mA
843.8mV   11.43mA    11.26mA    10.4mA
1.125V    13.67mA    12.69mA    12.85mA
1.575V    14.63mA    13.26mA    14.23mA
3.6V      16.35mA    14.9mA     15.84mA
[Ramp]
dV/dt_r   0.401415/0.24428n  0.394221/0.237764n  0.367631/0.245973n
dV/dt_f   0.408955/0.26874n  0.377254/0.289355n  0.401771/0.254323n
R_load = 50
[Rising Waveform]
R_fixture = 50
V_fixture = 0
V_fixture_min = 0
V_fixture_max = 0
| Time   V(typ)   V(min)   V(max)
0s        2.834uV    3.143uV    5.722uV
1.086ns   -849.3uV   -623.8uV   1.657mV
1.377ns   -2.273mV   -791.8uV   425.7mV
1.516ns   163.9mV    -872uV     538.9mV
1.697ns   489.5mV    -3.829mV   589.2mV
1.808ns   586.3mV    12.98mV    601.1mV
2.107ns   658.8mV    494mV      610.2mV
2.311ns   665.3mV    623.2mV    611.4mV
2.639ns   667.6mV    652.8mV    611.9mV
10ns      669mV      657mV      612.7mV
[Rising Waveform]
R_fixture = 50
V_fixture = 1.8
V_fixture_min = 1.71
V_fixture_max = 1.89
| Time   V(typ)   V(min)   V(max)
0s        1.118V     1.081V     1.22V
910ps     1.119V     1.081V     1.224V
1.046ns   1.119V     1.081V     1.647V
1.205ns   1.122V     1.081V     1.834V
1.46ns    1.701V     1.081V     1.883V
1.62ns    1.778V     1.101V     1.887V
1.757ns   1.791V     1.467V     1.888V
1.891ns   1.796V     1.642V     1.888V
2.177ns   1.798V     1.703V     1.889V
10ns      1.8V       1.71V      1.89V
[Falling Waveform]
R_fixture = 50
V_fixture = 0
V_fixture_min = 0
V_fixture_max = 0
| Time   V(typ)   V(min)   V(max)
0s        669mV      657mV      612.7mV
911ps     668.3mV    656.6mV    606.6mV
1.057ns   668.2mV    656.5mV    171.1mV
1.22ns    663.3mV    656.4mV    26.6mV
1.413ns   134.3mV    656.3mV    5.579mV
1.639ns   12.9mV     649.4mV    1.923mV
1.705ns   7.35mV     508.8mV    1.677mV
1.864ns   3.065mV    101.2mV    1.09mV
2.101ns   1.401mV    9.529mV    931.5uV
10ns      4.04uV     5.024uV    6.29uV
[Falling Waveform]
R_fixture = 50
V_fixture = 1.8
V_fixture_min = 1.71
V_fixture_max = 1.89
| Time   V(typ)   V(min)   V(max)
0s        1.8V       1.71V      1.89V
1.043ns   1.801V     1.711V     1.887V
1.137ns   1.801V     1.711V     1.79V
1.363ns   1.802V     1.711V     1.4V
1.481ns   1.708V     1.711V     1.298V
1.771ns   1.263V     1.712V     1.23V
1.893ns   1.176V     1.638V     1.226V
2.2ns     1.126V     1.225V     1.223V
2.582ns   1.121V     1.092V     1.222V
10ns      1.118V     1.081V     1.22V
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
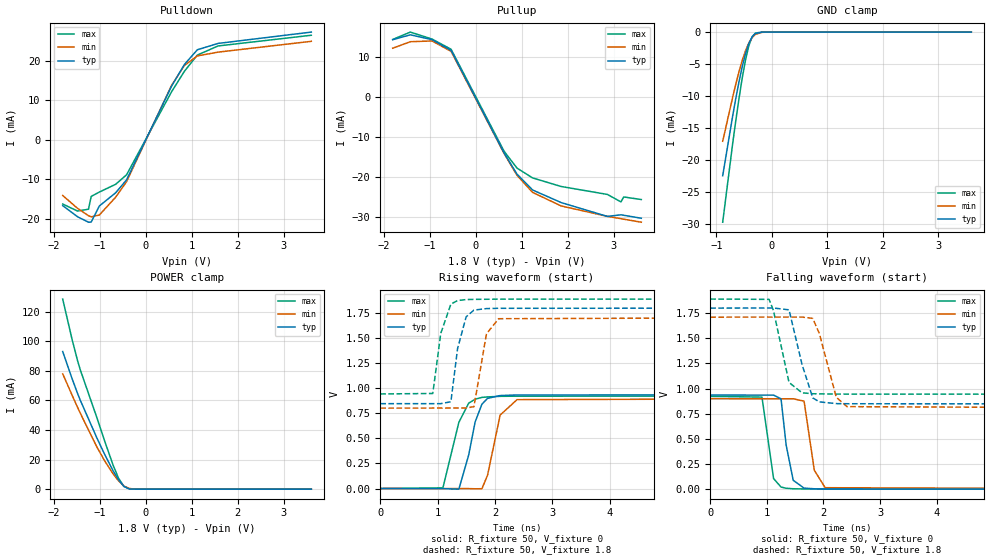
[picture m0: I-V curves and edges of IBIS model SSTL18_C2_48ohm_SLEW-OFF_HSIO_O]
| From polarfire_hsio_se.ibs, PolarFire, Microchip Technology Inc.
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|   Model SSTL18_C2_48ohm_SLEW-OFF_HSIO_O
[Model]   SSTL18_C2_48ohm_SLEW-OFF_HSIO_O
Model_type   Output
Polarity   Non-Inverting
Enable   Active-High
Vmeas =   0.9
Cref =   5p
Rref =   50
Vref =   0.9
|   typ   min   max
C_comp_pullup   1.335e-12   1.335e-12   1.380e-12
C_comp_pulldown  1.335e-12   1.335e-12   1.380e-12
[Temperature Range]  25C   100C   -40C
[Voltage Range]  1.8   1.71   1.89
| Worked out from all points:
|   slope of the pulldown table from 0 to 0.27 V, typ, clamps not added: 40 ohm
|   slope of the pullup table from 0 to 0.27 V, typ, clamps not added: 42.5 ohm
|   GND clamp passes 1 mA (typ) near -0.37 V on its own axis
|   POWER clamp passes 1 mA (typ) near -0.43 V on its own axis
|   rising waveform, R_fixture 50, V_fixture 0: 20-80 % time 208ps typ, 196ps min, 230ps max; typ from 0 V to 0.936 V
|   rising waveform, R_fixture 50, V_fixture 1.8: 20-80 % time 159ps typ, 157ps min, 154ps max; typ from 0.847 V to 1.8 V
|   falling waveform, R_fixture 50, V_fixture 0: 20-80 % time 131ps typ, 139ps min, 120ps max; typ from 0.936 V to 0 V
|   falling waveform, R_fixture 50, V_fixture 1.8: 20-80 % time 216ps typ, 245ps min, 202ps max; typ from 1.8 V to 0.847 V
[GND Clamp]
| Voltage   I(typ)   I(min)   I(max)
-885.9mV  -22.44mA   -17.06mA   -29.71mA
-708.7mV  -13.24mA   -10.28mA   -17.6mA
-649.7mV  -10.37mA   -8.138mA   -13.83mA
-590.6mV  -7.705mA   -6.148mA   -10.3mA
-531.6mV  -5.322mA   -4.371mA   -7.074mA
-472.5mV  -3.308mA   -2.865mA   -4.286mA
-413.4mV  -1.757mA   -1.684mA   -2.101mA
-354.4mV  -739.5uA   -855.1uA   -713.7uA
-295.3mV  -232.3uA   -363.2uA   -148.3uA
-177.2mV  -12.01uA   -39.02uA   -3.177uA
-59.06mV  -489.8nA   -2.616uA   -234.3nA
3.6V      0A         0A         0A
[POWER Clamp]
| Voltage   I(typ)   I(min)   I(max)
-1.8V     93.11mA    78.02mA    128.6mA
-1.595V   74.64mA    63.48mA    101.1mA
-1.477V   64.73mA    55.33mA    86.9mA
-1.417V   60.07mA    51.32mA    80.62mA
-1.063V   35.01mA    28.82mA    48.84mA
-885.9mV  23.32mA    19.01mA    32.31mA
-708.7mV  12.62mA    10.48mA    16.53mA
-590.6mV  6.476mA    5.751mA    7.626mA
-472.5mV  1.932mA    2.149mA    1.873mA
-354.4mV  154uA      469.9uA    209.6uA
-236.2mV  4.969uA    79.11uA    56.46uA
3.6V      0A         0A         0A
[Pullup]
| Voltage   I(typ)   I(min)   I(max)
-1.8V     14.21mA    12.09mA    14.28mA
-1.417V   15.43mA    13.71mA    16.11mA
-945mV    14.22mA    13.9mA     14.37mA
-531.6mV  11.54mA    11.3mA     11.83mA
618.8mV   -14.01mA   -14.14mA   -13.59mA
900mV     -19.31mA   -19.6mA    -17.8mA
1.238V    -23.25mA   -23.85mA   -20.24mA
1.859V    -26.39mA   -27.23mA   -22.38mA
2.863V    -29.84mA   -29.83mA   -24.36mA
3.158V    -29.44mA   -30.41mA   -26.23mA
3.217V    -29.55mA   -30.53mA   -24.99mA
3.6V      -30.3mA    -31.28mA   -25.63mA
[Pulldown]
| Voltage   I(typ)   I(min)   I(max)
-1.8V     -16.63mA   -14.08mA   -16.23mA
-1.477V   -19.45mA   -17.33mA   -18.01mA
-1.24V    -20.82mA   -19.18mA   -17.54mA
-1.181V   -20.79mA   -19.46mA   -14.31mA
-1.004V   -16.72mA   -19.01mA   -13.21mA
-649.7mV  -13.39mA   -14.5mA    -11.25mA
-413.4mV  -10.13mA   -10.59mA   -8.855mA
562.5mV   13.49mA    13.7mA     12.08mA
843.8mV   19.02mA    18.77mA    17.3mA
1.125V    22.73mA    21.17mA    21.39mA
1.575V    24.33mA    22.13mA    23.69mA
3.6V      27.19mA    24.86mA    26.39mA
[Ramp]
dV/dt_r   0.561322/0.207829n  0.539654/0.195923n  0.553608/0.230033n
dV/dt_f   0.571986/0.216238n  0.544568/0.244508n  0.567803/0.201607n
R_load = 50
[Rising Waveform]
R_fixture = 50
V_fixture = 0
V_fixture_min = 0
V_fixture_max = 0
| Time   V(typ)   V(min)   V(max)
0s        2.497uV    2.678uV    4.909uV
1.091ns   -653.5uV   -501.3uV   7.052mV
1.369ns   -6.137mV   -629.7uV   660.5mV
1.54ns    334.1mV    -708.7uV   851.6mV
1.652ns   663.4mV    -2.232mV   891mV
1.771ns   841.8mV    -1.702mV   909.2mV
1.869ns   899.8mV    133.6mV    914.1mV
2.088ns   927.7mV    732.9mV    919.9mV
2.382ns   933.4mV    886.8mV    921.3mV
10ns      935.5mV    899.4mV    922.7mV
[Rising Waveform]
R_fixture = 50
V_fixture = 1.8
V_fixture_min = 1.71
V_fixture_max = 1.89
| Time   V(typ)   V(min)   V(max)
0s        846.7mV    802.3mV    943.6mV
915ps     846.8mV    802.8mV    948.3mV
1.054ns   846.8mV    802.9mV    1.548V
1.23ns    865.8mV    803mV      1.84V
1.347ns   1.397V     803.1mV    1.875V
1.496ns   1.713V     803.1mV    1.885V
1.632ns   1.78V      817.2mV    1.887V
1.85ns    1.795V     1.544V     1.888V
2.062ns   1.798V     1.694V     1.889V
10ns      1.8V       1.71V      1.89V
[Falling Waveform]
R_fixture = 50
V_fixture = 0
V_fixture_min = 0
V_fixture_max = 0
| Time   V(typ)   V(min)   V(max)
0s        935.6mV    899.5mV    922.7mV
914ps     935.1mV    899mV      915.4mV
1.119ns   935mV      898.8mV    105.3mV
1.251ns   897.7mV    898.8mV    20.85mV
1.341ns   439mV      898.7mV    9.362mV
1.466ns   88.26mV    898.6mV    4.176mV
1.658ns   10.31mV    875.1mV    2.185mV
1.839ns   3.756mV    188mV      1.423mV
2.031ns   1.809mV    14.49mV    1.059mV
10ns      3.234uV    4.05uV     5.508uV
[Falling Waveform]
R_fixture = 50
V_fixture = 1.8
V_fixture_min = 1.71
V_fixture_max = 1.89
| Time   V(typ)   V(min)   V(max)
0s        1.8V       1.71V      1.89V
1.04ns    1.801V     1.711V     1.887V
1.116ns   1.801V     1.711V     1.778V
1.392ns   1.783V     1.711V     1.061V
1.623ns   1.238V     1.711V     957.7mV
1.811ns   907.9mV    1.698V     948.8mV
1.927ns   868mV      1.549V     947.5mV
2.227ns   850.6mV    913.6mV    945.6mV
2.417ns   849.3mV    820.4mV    944.9mV
10ns      846.7mV    802.4mV    943.6mV
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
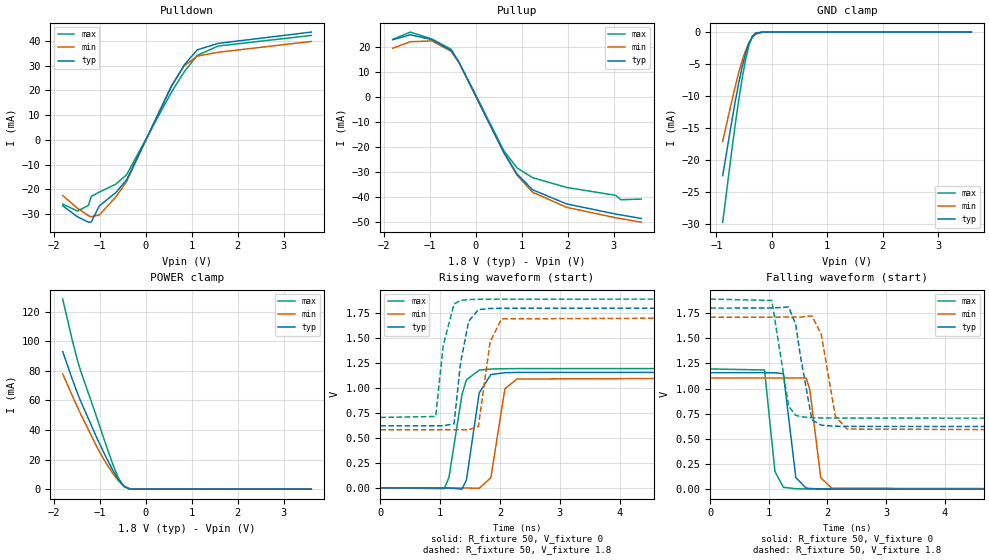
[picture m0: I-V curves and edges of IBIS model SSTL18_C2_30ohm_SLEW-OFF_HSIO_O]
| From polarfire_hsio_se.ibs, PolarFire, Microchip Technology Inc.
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|   Model SSTL18_C2_30ohm_SLEW-OFF_HSIO_O
[Model]   SSTL18_C2_30ohm_SLEW-OFF_HSIO_O
Model_type   Output
Polarity   Non-Inverting
Enable   Active-High
Vmeas =   0.9
Cref =   5p
Rref =   50
Vref =   0.9
|   typ   min   max
C_comp_pullup   1.335e-12   1.335e-12   1.380e-12
C_comp_pulldown  1.335e-12   1.335e-12   1.380e-12
[Temperature Range]  25C   100C   -40C
[Voltage Range]  1.8   1.71   1.89
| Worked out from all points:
|   slope of the pulldown table from 0 to 0.27 V, typ, clamps not added: 25 ohm
|   slope of the pullup table from 0 to 0.27 V, typ, clamps not added: 26.6 ohm
|   GND clamp passes 1 mA (typ) near -0.37 V on its own axis
|   POWER clamp passes 1 mA (typ) near -0.43 V on its own axis
|   rising waveform, R_fixture 50, V_fixture 0: 20-80 % time 160ps typ, 156ps min, 187ps max; typ from 0 V to 1.16 V
|   rising waveform, R_fixture 50, V_fixture 1.8: 20-80 % time 157ps typ, 158ps min, 152ps max; typ from 0.622 V to 1.8 V
|   falling waveform, R_fixture 50, V_fixture 0: 20-80 % time 121ps typ, 130ps min, 115ps max; typ from 1.16 V to 0 V
|   falling waveform, R_fixture 50, V_fixture 1.8: 20-80 % time 170ps typ, 193ps min, 160ps max; typ from 1.8 V to 0.622 V
[GND Clamp]
| Voltage   I(typ)   I(min)   I(max)
-885.9mV  -22.44mA   -17.06mA   -29.71mA
-708.7mV  -13.24mA   -10.28mA   -17.6mA
-649.7mV  -10.37mA   -8.138mA   -13.83mA
-590.6mV  -7.705mA   -6.148mA   -10.3mA
-531.6mV  -5.322mA   -4.371mA   -7.074mA
-472.5mV  -3.308mA   -2.865mA   -4.286mA
-413.4mV  -1.757mA   -1.684mA   -2.101mA
-354.4mV  -739.5uA   -855.1uA   -713.7uA
-295.3mV  -232.3uA   -363.2uA   -148.3uA
-177.2mV  -12.01uA   -39.02uA   -3.177uA
-59.06mV  -489.8nA   -2.616uA   -234.3nA
3.6V      0A         0A         0A
[POWER Clamp]
| Voltage   I(typ)   I(min)   I(max)
-1.8V     93.11mA    78.02mA    128.6mA
-1.595V   74.64mA    63.48mA    101.1mA
-1.477V   64.73mA    55.33mA    86.9mA
-1.417V   60.07mA    51.32mA    80.62mA
-1.063V   35.01mA    28.82mA    48.84mA
-885.9mV  23.32mA    19.01mA    32.31mA
-708.7mV  12.62mA    10.48mA    16.53mA
-590.6mV  6.476mA    5.751mA    7.626mA
-472.5mV  1.932mA    2.149mA    1.873mA
-354.4mV  154uA      469.9uA    209.6uA
-236.2mV  4.969uA    79.11uA    56.46uA
3.6V      0A         0A         0A
[Pullup]
| Voltage   I(typ)   I(min)   I(max)
-1.8V     22.73mA    19.34mA    22.85mA
-1.417V   24.7mA     21.94mA    25.78mA
-945mV    22.75mA    22.24mA    22.99mA
-531.6mV  18.47mA    18.08mA    18.92mA
-354.4mV  13.52mA    13.37mA    13.55mA
618.8mV   -22.42mA   -22.61mA   -21.73mA
900mV     -30.89mA   -31.35mA   -28.46mA
1.238V    -37.19mA   -38.16mA   -32.37mA
1.977V    -42.84mA   -44.21mA   -36.26mA
3.04V     -46.88mA   -48.37mA   -39.41mA
3.158V    -47.25mA   -48.74mA   -41.17mA
3.6V      -48.65mA   -50.14mA   -40.92mA
[Pulldown]
| Voltage   I(typ)   I(min)   I(max)
-1.8V     -26.65mA   -22.54mA   -26mA
-1.477V   -31.16mA   -27.74mA   -28.83mA
-1.24V    -33.33mA   -30.69mA   -26.51mA
-1.181V   -33.27mA   -31.14mA   -22.88mA
-1.004V   -26.72mA   -30.4mA    -21.14mA
-649.7mV  -21.41mA   -23.19mA   -17.99mA
-413.4mV  -16.19mA   -16.93mA   -14.15mA
562.5mV   21.56mA    21.92mA    19.3mA
843.8mV   30.43mA    30.03mA    27.65mA
1.125V    36.41mA    33.87mA    34.2mA
1.575V    39mA       35.41mA    37.92mA
3.6V      43.57mA    39.78mA    42.22mA
[Ramp]
dV/dt_r   0.694973/0.159529n  0.663489/0.15617n  0.717217/0.187014n
dV/dt_f   0.707019/0.170343n  0.676824/0.193436n  0.710765/0.159985n
R_load = 50
[Rising Waveform]
R_fixture = 50
V_fixture = 0
V_fixture_min = 0
V_fixture_max = 0
| Time   V(typ)   V(min)   V(max)
0s        2.204uV    2.277uV    4.182uV
1.069ns   -861.4uV   -411.5uV   -7.216mV
1.148ns   -925.2uV   -442uV     105.6mV
1.365ns   -12.28mV   -526uV     933.8mV
1.44ns    79.9mV     -555.1uV   1.082V
1.653ns   950.3mV    -3.482mV   1.179V
1.848ns   1.135V     102.8mV    1.19V
2.083ns   1.153V     993.5mV    1.193V
2.285ns   1.156V     1.09V      1.194V
10ns      1.158V     1.106V     1.195V
[Rising Waveform]
R_fixture = 50
V_fixture = 1.8
V_fixture_min = 1.71
V_fixture_max = 1.89
| Time   V(typ)   V(min)   V(max)
0s        621.6mV    581.9mV    705.4mV
926ps     622mV      582.4mV    715.3mV
1.052ns   622mV      582.5mV    1.428V
1.233ns   641.3mV    582.6mV    1.841V
1.342ns   1.257V     582.7mV    1.877V
1.478ns   1.668V     582.7mV    1.885V
1.639ns   1.784V     613.4mV    1.888V
1.836ns   1.796V     1.464V     1.888V
2.028ns   1.798V     1.692V     1.889V
10ns      1.8V       1.71V      1.89V
[Falling Waveform]
R_fixture = 50
V_fixture = 0
V_fixture_min = 0
V_fixture_max = 0
| Time   V(typ)   V(min)   V(max)
0s        1.158V     1.106V     1.195V
926ps     1.158V     1.105V     1.185V
1.104ns   1.157V     1.105V     174.6mV
1.248ns   1.148V     1.105V     18.4mV
1.46ns    114.8mV    1.105V     4.397mV
1.637ns   10.54mV    1.104V     2.295mV
1.698ns   6.996mV    994.7mV    1.855mV
1.886ns   2.703mV    113.3mV    1.408mV
2.074ns   1.625mV    9.351mV    1.058mV
10ns      3.149uV    3.415uV    4.527uV
[Falling Waveform]
R_fixture = 50
V_fixture = 1.8
V_fixture_min = 1.71
V_fixture_max = 1.89
| Time   V(typ)   V(min)   V(max)
0s        1.8V       1.71V      1.89V
1.05ns    1.801V     1.71V      1.876V
1.338ns   1.811V     1.711V     823.7mV
1.457ns   1.641V     1.711V     735.3mV
1.538ns   1.327V     1.711V     720.6mV
1.735ns   687.7mV    1.723V     710.6mV
1.893ns   636.4mV    1.543V     708.2mV
2.136ns   625.6mV    722.5mV    706.9mV
2.334ns   623.8mV    597.4mV    706.6mV
10ns      621.6mV    581.9mV    705.4mV
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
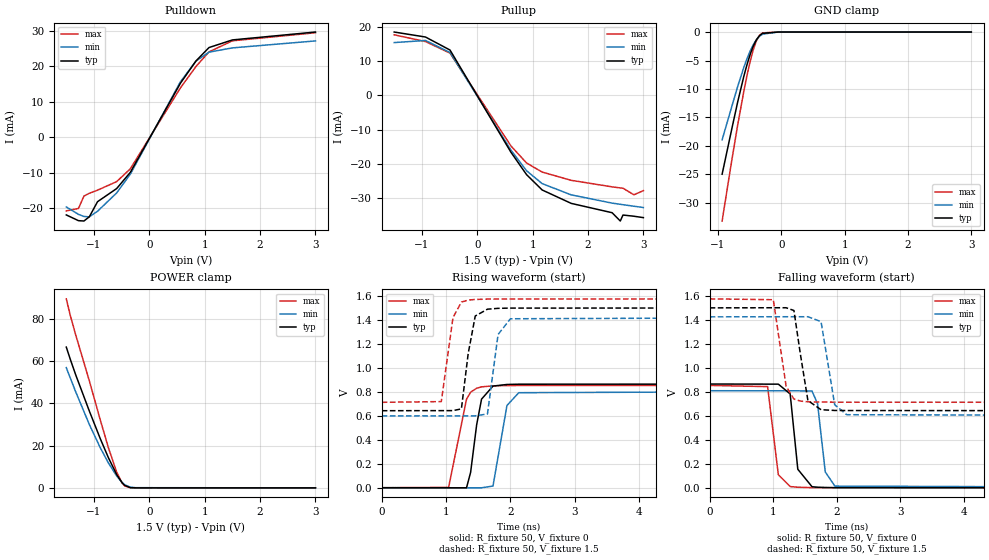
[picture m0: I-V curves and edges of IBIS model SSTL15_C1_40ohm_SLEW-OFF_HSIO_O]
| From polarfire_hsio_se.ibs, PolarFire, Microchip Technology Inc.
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|   Model SSTL15_C1_40ohm_SLEW-OFF_HSIO_O
[Model]   SSTL15_C1_40ohm_SLEW-OFF_HSIO_O
Model_type   Output
Polarity   Non-Inverting
Enable   Active-High
Vmeas =   0.75
Cref =   5p
Rref =   50
Vref =   0.75
|   typ   min   max
C_comp_pullup   1.335e-12   1.335e-12   1.380e-12
C_comp_pulldown  1.335e-12   1.335e-12   1.380e-12
[Temperature Range]  25C   100C   -40C
[Voltage Range]  1.5   1.425   1.575
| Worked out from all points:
|   slope of the pulldown table from 0 to 0.225 V, typ, clamps not added: 35.2 ohm
|   slope of the pullup table from 0 to 0.225 V, typ, clamps not added: 35.2 ohm
|   GND clamp passes 1 mA (typ) near -0.37 V on its own axis
|   POWER clamp passes 1 mA (typ) near -0.43 V on its own axis
|   rising waveform, R_fixture 50, V_fixture 0: 20-80 % time 136ps typ, 140ps min, 169ps max; typ from 0 V to 0.865 V
|   rising waveform, R_fixture 50, V_fixture 1.5: 20-80 % time 113ps typ, 108ps min, 124ps max; typ from 0.642 V to 1.5 V
|   falling waveform, R_fixture 50, V_fixture 0: 20-80 % time 96ps typ, 99.2ps min, 95.7ps max; typ from 0.865 V to 0 V
|   falling waveform, R_fixture 50, V_fixture 1.5: 20-80 % time 123ps typ, 131ps min, 124ps max; typ from 1.5 V to 0.642 V
[GND Clamp]
| Voltage   I(typ)   I(min)   I(max)
-935.2mV  -24.96mA   -18.92mA   -33.17mA
-787.5mV  -17.27mA   -13.27mA   -22.86mA
-689.1mV  -12.26mA   -9.546mA   -16.31mA
-590.6mV  -7.7mA     -6.143mA   -10.29mA
-541.4mV  -5.692mA   -4.645mA   -7.577mA
-492.2mV  -3.93mA    -3.33mA    -5.153mA
-443mV    -2.467mA   -2.229mA   -3.103mA
-393.7mV  -1.355mA   -1.366mA   -1.54mA
-344.5mV  -621.9uA   -750.5uA   -567.2uA
-295.3mV  -232uA     -362.9uA   -147.8uA
-49.22mV  -334.5nA   -1.943uA   -112.6nA
3V        0A         0A         0A
[POWER Clamp]
| Voltage   I(typ)   I(min)   I(max)
-1.5V     66.64mA    56.9mA     89.46mA
-1.427V   60.81mA    51.96mA    81.57mA
-1.329V   53.43mA    45.4mA     72.34mA
-1.083V   36.31mA    29.95mA    50.59mA
-885.9mV  23.26mA    18.98mA    32.15mA
-738.3mV  14.22mA    11.74mA    18.91mA
-590.6mV  6.331mA    5.649mA    7.47mA
-492.2mV  2.418mA    2.54mA     2.302mA
-443mV    1.134mA    1.422mA    896.4uA
-344.5mV  93.53uA    323uA      39.71uA
-246.1mV  3.484uA    76.21uA    1.361uA
3V        0A         0A         0A
[Pullup]
| Voltage   I(typ)   I(min)   I(max)
-1.5V     18.54mA    15.45mA    17.73mA
-935.2mV  17.08mA    16.07mA    15.75mA
-492.2mV  13.27mA    12.56mA    12.36mA
609.4mV   -16.67mA   -16.05mA   -14.82mA
890.6mV   -23.21mA   -22.07mA   -19.8mA
1.172V    -27.69mA   -25.83mA   -22.46mA
1.697V    -31.62mA   -29.13mA   -24.87mA
2.435V    -34.35mA   -31.54mA   -26.78mA
2.583V    -36.78mA   -31.88mA   -27.09mA
2.632V    -35.03mA   -32mA      -27.19mA
2.829V    -35.38mA   -32.45mA   -29.11mA
3V        -35.79mA   -32.83mA   -27.89mA
[Pulldown]
| Voltage   I(typ)   I(min)   I(max)
-1.5V     -21.82mA   -19.57mA   -20.69mA
-1.28V    -23.43mA   -21.65mA   -20mA
-1.181V   -23.53mA   -22.26mA   -16.51mA
-1.083V   -22.32mA   -22.35mA   -15.73mA
-935.2mV  -18.09mA   -20.78mA   -14.85mA
-590.6mV  -14.41mA   -15.64mA   -12.46mA
-344.5mV  -9.863mA   -10.38mA   -8.868mA
562.5mV   15.25mA    15.67mA    13.94mA
843.8mV   21.52mA    21.46mA    19.96mA
1.078V    25.26mA    23.96mA    24.04mA
1.5V      27.4mA     25.16mA    27.15mA
3V        29.62mA    27.12mA    29.42mA
[Ramp]
dV/dt_r   0.519086/0.136291n  0.485702/0.140477n  0.512107/0.169181n
dV/dt_f   0.514683/0.12276n  0.495681/0.130969n  0.517618/0.124207n
R_load = 50
[Rising Waveform]
R_fixture = 50
V_fixture = 0
V_fixture_min = 0
V_fixture_max = 0
| Time   V(typ)   V(min)   V(max)
0s        1.633uV    1.785uV    2.557uV
1.04ns    -644.7uV   -393.8uV   2.66mV
1.318ns   -1.07mV    -499.5uV   737.5mV
1.382ns   128.1mV    -523.9uV   796.5mV
1.476ns   525.3mV    -559.6uV   829.8mV
1.552ns   738.9mV    -588.5uV   841.2mV
1.73ns    847.7mV    14.06mV    849.4mV
1.947ns   861.1mV    685.6mV    852mV
2.131ns   863.3mV    792.5mV    852.4mV
10ns      865.1mV    809.5mV    853.5mV
[Rising Waveform]
R_fixture = 50
V_fixture = 1.5
V_fixture_min = 1.425
V_fixture_max = 1.575
| Time   V(typ)   V(min)   V(max)
0s        642.2mV    598.8mV    712.3mV
926ps     642.9mV    599.2mV    718.2mV
1.108ns   643mV      599.2mV    1.419V
1.239ns   657.7mV    599.3mV    1.548V
1.344ns   1.118V     599.3mV    1.565V
1.454ns   1.432V     599.3mV    1.57V
1.644ns   1.489V     615.3mV    1.573V
1.809ns   1.496V     1.278V     1.573V
2.001ns   1.498V     1.409V     1.574V
10ns      1.5V       1.425V     1.575V
[Falling Waveform]
R_fixture = 50
V_fixture = 0
V_fixture_min = 0
V_fixture_max = 0
| Time   V(typ)   V(min)   V(max)
0s        865.2mV    809.5mV    853.5mV
911ps     864.4mV    809mV      843.7mV
1.08ns    864.3mV    808.9mV    109.1mV
1.266ns   782.7mV    808.8mV    10.73mV
1.386ns   155mV      808.7mV    5.07mV
1.61ns    9.166mV    806.6mV    1.853mV
1.697ns   5.246mV    700.1mV    1.572mV
1.818ns   2.775mV    132.3mV    1.228mV
1.97ns    1.76mV     14.33mV    978.8uV
10ns      2.632uV    3.044uV    3.271uV
[Falling Waveform]
R_fixture = 50
V_fixture = 1.5
V_fixture_min = 1.425
V_fixture_max = 1.575
| Time   V(typ)   V(min)   V(max)
0s        1.5V       1.425V     1.575V
1.001ns   1.501V     1.426V     1.568V
1.202ns   1.501V     1.426V     847.1mV
1.325ns   1.478V     1.426V     740.1mV
1.427ns   1.113V     1.426V     723.1mV
1.545ns   727.4mV    1.426V     717.3mV
1.752ns   651.1mV    1.385V     715mV
1.966ns   645.1mV    692.6mV    714.2mV
2.155ns   644.3mV    609.6mV    713.7mV
10ns      642.2mV    598.8mV    712.3mV
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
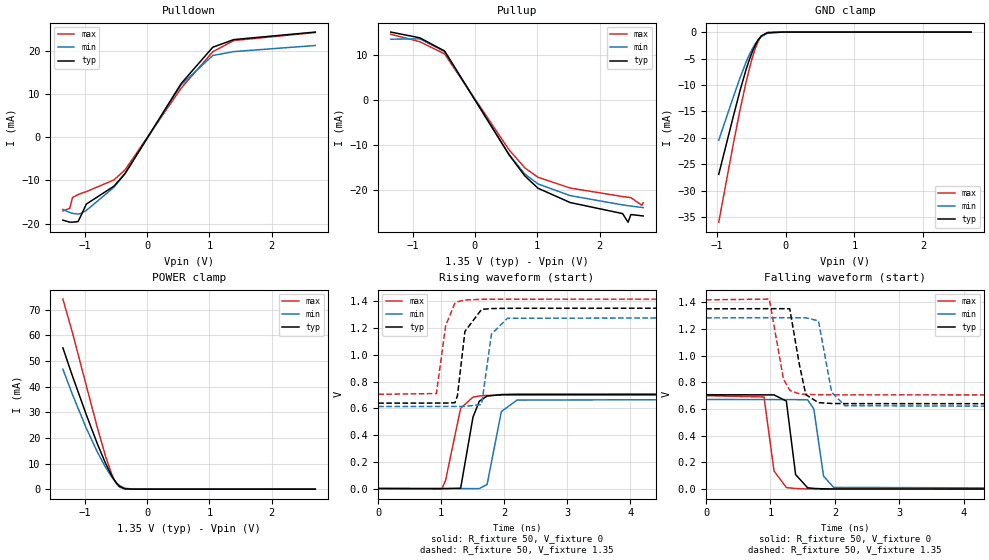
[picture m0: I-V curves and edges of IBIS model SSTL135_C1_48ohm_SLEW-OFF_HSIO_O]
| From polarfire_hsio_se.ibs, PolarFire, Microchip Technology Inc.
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|   Model SSTL135_C1_48ohm_SLEW-OFF_HSIO_O
[Model]   SSTL135_C1_48ohm_SLEW-OFF_HSIO_O
Model_type   Output
Polarity   Non-Inverting
Enable   Active-High
Vmeas =   0.675
Cref =   5p
Rref =   50
Vref =   0.675
|   typ   min   max
C_comp_pullup   1.335e-12   1.335e-12   1.380e-12
C_comp_pulldown  1.335e-12   1.335e-12   1.380e-12
[Temperature Range]  25C   100C   -40C
[Voltage Range]  1.35   1.2825   1.4175
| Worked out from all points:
|   slope of the pulldown table from 0 to 0.203 V, typ, clamps not added: 42 ohm
|   slope of the pullup table from 0 to 0.203 V, typ, clamps not added: 42.9 ohm
|   GND clamp passes 1 mA (typ) near -0.37 V on its own axis
|   POWER clamp passes 1 mA (typ) near -0.43 V on its own axis
|   rising waveform, R_fixture 50, V_fixture 0: 20-80 % time 147ps typ, 156ps min, 172ps max; typ from 0 V to 0.706 V
|   rising waveform, R_fixture 50, V_fixture 1.35: 20-80 % time 108ps typ, 104ps min, 122ps max; typ from 0.638 V to 1.35 V
|   falling waveform, R_fixture 50, V_fixture 0: 20-80 % time 103ps typ, 112ps min, 102ps max; typ from 0.706 V to 0 V
|   falling waveform, R_fixture 50, V_fixture 1.35: 20-80 % time 125ps typ, 138ps min, 128ps max; typ from 1.35 V to 0.638 V
[GND Clamp]
| Voltage   I(typ)   I(min)   I(max)
-974.5mV  -26.9mA    -20.45mA   -35.95mA
-753mV    -15.48mA   -11.94mA   -20.52mA
-664.5mV  -11.06mA   -8.652mA   -14.74mA
-575.9mV  -7.072mA   -5.674mA   -9.445mA
-531.6mV  -5.316mA   -4.365mA   -7.064mA
-487.3mV  -3.767mA   -3.209mA   -4.927mA
-443mV    -2.466mA   -2.228mA   -3.102mA
-398.7mV  -1.449mA   -1.441mA   -1.67mA
-354.4mV  -738.4uA   -854uA     -712.2uA
-265.8mV  -117.5uA   -220.3uA   -58.64uA
-44.3mV   -274.4nA   -1.655uA   -83.21nA
2.7V      0A         0A         0A
[POWER Clamp]
| Voltage   I(typ)   I(min)   I(max)
-1.35V    55.07mA    46.77mA    74.1mA
-1.196V   44.05mA    36.84mA    60.94mA
-974.5mV  29.03mA    23.74mA    40.36mA
-797.3mV  17.68mA    14.49mA    24.04mA
-664.5mV  10.01mA    8.483mA    12.73mA
-575.9mV  5.63mA     5.093mA    6.421mA
-531.6mV  3.786mA    3.641mA    3.935mA
-487.3mV  2.262mA    2.398mA    2.056mA
-443mV    1.133mA    1.41mA     851.4uA
-354.4mV  127.5uA    344.8uA    50.77uA
-221.5mV  1.715uA    33.09uA    747.7nA
2.7V      0A         0A         0A
[Pullup]
| Voltage   I(typ)   I(min)   I(max)
-1.35V    15.04mA    13.46mA    14.55mA
-885.9mV  13.77mA    13.54mA    12.9mA
-487.3mV  10.84mA    10.71mA    10.19mA
548.4mV   -12.25mA   -12.21mA   -11.15mA
801.6mV   -16.95mA   -16.53mA   -15.16mA
1.012V    -19.67mA   -18.72mA   -17.24mA
1.527V    -22.85mA   -21.31mA   -19.63mA
2.369V    -25.31mA   -23.38mA   -21.52mA
2.457V    -27.22mA   -23.55mA   -21.68mA
2.502V    -25.52mA   -23.63mA   -21.76mA
2.679V    -25.8mA    -23.94mA   -23.47mA
2.7V      -25.84mA   -23.98mA   -22.88mA
[Pulldown]
| Voltage   I(typ)   I(min)   I(max)
-1.35V    -19.17mA   -16.7mA    -17.04mA
-1.24V    -19.63mA   -17.39mA   -16.44mA
-1.196V   -19.64mA   -17.6mA    -13.94mA
-1.107V   -19.5mA    -17.76mA   -13.25mA
-1.063V   -18.23mA   -17.65mA   -13.01mA
-974.5mV  -15.46mA   -16.93mA   -12.57mA
-531.6mV  -11.32mA   -11.57mA   -9.881mA
-354.4mV  -8.43mA    -8.44mA    -7.575mA
548.4mV   12.43mA    12.16mA    11.36mA
1.055V    20.81mA    18.9mA     19.76mA
1.394V    22.58mA    19.8mA     22.36mA
2.7V      24.31mA    21.21mA    24.22mA
[Ramp]
dV/dt_r   0.423838/0.146932n  0.40264/0.156329n  0.41976/0.172462n
dV/dt_f   0.426897/0.125151n  0.401385/0.138104n  0.427747/0.127648n
R_load = 50
[Rising Waveform]
R_fixture = 50
V_fixture = 0
V_fixture_min = 0
V_fixture_max = 0
| Time   V(typ)   V(min)   V(max)
0s        1.388uV    1.613uV    2.127uV
1.008ns   -579.9uV   -374.4uV   -4.912mV
1.069ns   -615.1uV   -397.1uV   60.16mV
1.309ns   1.649mV    -486.7uV   600.1mV
1.505ns   533.7mV    -559.8uV   683.3mV
1.605ns   652.7mV    -597.1uV   692.1mV
1.729ns   691.1mV    30.12mV    696.2mV
1.955ns   702.8mV    575.3mV    698.3mV
2.204ns   705.1mV    661.4mV    698.6mV
10ns      706.4mV    671.1mV    699.6mV
[Rising Waveform]
R_fixture = 50
V_fixture = 1.35
V_fixture_min = 1.2825
V_fixture_max = 1.4175
| Time   V(typ)   V(min)   V(max)
0s        638.5mV    613.5mV    704.6mV
924ps     639.1mV    613.7mV    710.2mV
1.071ns   639.2mV    613.8mV    1.218V
1.218ns   641.3mV    613.8mV    1.386V
1.258ns   693.4mV    613.8mV    1.397V
1.377ns   1.175V     613.9mV    1.41V
1.642ns   1.34V      628.3mV    1.415V
1.798ns   1.346V     1.155V     1.416V
2.052ns   1.348V     1.273V     1.416V
10ns      1.35V      1.282V     1.417V
[Falling Waveform]
R_fixture = 50
V_fixture = 0
V_fixture_min = 0
V_fixture_max = 0
| Time   V(typ)   V(min)   V(max)
0s        706.4mV    671.1mV    699.6mV
899ps     705.8mV    670.6mV    690.2mV
1.055ns   705.7mV    670.5mV    135.9mV
1.246ns   659.5mV    670.4mV    12.01mV
1.39ns    109.1mV    670.3mV    4.804mV
1.577ns   10.33mV    668.6mV    1.773mV
1.673ns   5.613mV    600.2mV    1.44mV
1.824ns   2.352mV    97.37mV    1.128mV
1.981ns   1.495mV    13.35mV    831.9uV
10ns      2.419uV    3.318uV    3.941uV
[Falling Waveform]
R_fixture = 50
V_fixture = 1.35
V_fixture_min = 1.2825
V_fixture_max = 1.4175
| Time   V(typ)   V(min)   V(max)
0s        1.35V      1.282V     1.417V
982ps     1.351V     1.283V     1.423V
1.201ns   1.351V     1.283V     824.3mV
1.299ns   1.35V      1.283V     739.5mV
1.447ns   936.4mV    1.283V     713.2mV
1.549ns   707.3mV    1.283V     709.3mV
1.745ns   647.7mV    1.26V      706.9mV
1.95ns    641.4mV    724.9mV    706.2mV
2.156ns   640.4mV    624.5mV    705.9mV
10ns      638.5mV    613.5mV    704.6mV
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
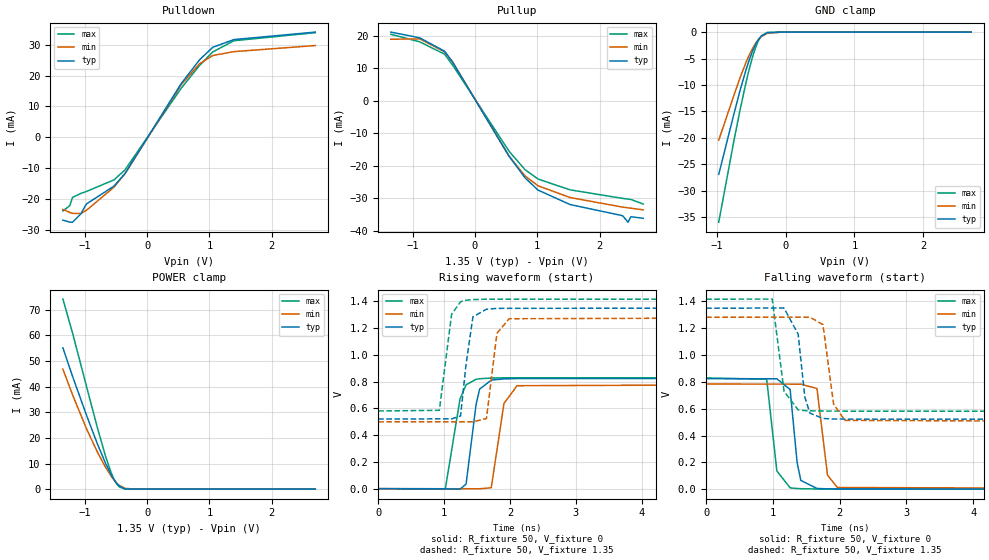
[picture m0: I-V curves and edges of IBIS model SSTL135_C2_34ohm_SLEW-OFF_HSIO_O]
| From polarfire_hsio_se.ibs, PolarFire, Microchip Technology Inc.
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|   Model SSTL135_C2_34ohm_SLEW-OFF_HSIO_O
[Model]   SSTL135_C2_34ohm_SLEW-OFF_HSIO_O
Model_type   Output
Polarity   Non-Inverting
Enable   Active-High
Vmeas =   0.675
Cref =   5p
Rref =   50
Vref =   0.675
|   typ   min   max
C_comp_pullup   1.335e-12   1.335e-12   1.380e-12
C_comp_pulldown  1.335e-12   1.335e-12   1.380e-12
[Temperature Range]  25C   100C   -40C
[Voltage Range]  1.35   1.2825   1.4175
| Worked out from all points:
|   slope of the pulldown table from 0 to 0.203 V, typ, clamps not added: 30.1 ohm
|   slope of the pullup table from 0 to 0.203 V, typ, clamps not added: 30.7 ohm
|   GND clamp passes 1 mA (typ) near -0.37 V on its own axis
|   POWER clamp passes 1 mA (typ) near -0.43 V on its own axis
|   rising waveform, R_fixture 50, V_fixture 0: 20-80 % time 121ps typ, 128ps min, 145ps max; typ from 0 V to 0.824 V
|   rising waveform, R_fixture 50, V_fixture 1.35: 20-80 % time 97.1ps typ, 103ps min, 111ps max; typ from 0.521 V to 1.35 V
|   falling waveform, R_fixture 50, V_fixture 0: 20-80 % time 96.5ps typ, 95.6ps min, 93.3ps max; typ from 0.824 V to 0 V
|   falling waveform, R_fixture 50, V_fixture 1.35: 20-80 % time 107ps typ, 117ps min, 108ps max; typ from 1.35 V to 0.521 V
[GND Clamp]
| Voltage   I(typ)   I(min)   I(max)
-974.5mV  -26.9mA    -20.45mA   -35.95mA
-753mV    -15.48mA   -11.94mA   -20.52mA
-664.5mV  -11.06mA   -8.652mA   -14.74mA
-575.9mV  -7.072mA   -5.674mA   -9.445mA
-531.6mV  -5.316mA   -4.365mA   -7.064mA
-487.3mV  -3.767mA   -3.209mA   -4.927mA
-443mV    -2.466mA   -2.228mA   -3.102mA
-398.7mV  -1.449mA   -1.441mA   -1.67mA
-354.4mV  -738.4uA   -854uA     -712.2uA
-265.8mV  -117.5uA   -220.3uA   -58.64uA
-44.3mV   -274.4nA   -1.655uA   -83.21nA
2.7V      0A         0A         0A
[POWER Clamp]
| Voltage   I(typ)   I(min)   I(max)
-1.35V    55.07mA    46.77mA    74.1mA
-1.196V   44.05mA    36.84mA    60.94mA
-974.5mV  29.03mA    23.74mA    40.36mA
-797.3mV  17.68mA    14.49mA    24.04mA
-664.5mV  10.01mA    8.483mA    12.73mA
-575.9mV  5.63mA     5.093mA    6.421mA
-531.6mV  3.786mA    3.641mA    3.935mA
-487.3mV  2.262mA    2.398mA    2.056mA
-443mV    1.133mA    1.41mA     851.4uA
-354.4mV  127.5uA    344.8uA    50.77uA
-221.5mV  1.715uA    33.09uA    747.7nA
2.7V      0A         0A         0A
[Pullup]
| Voltage   I(typ)   I(min)   I(max)
-1.35V    21.05mA    18.85mA    20.37mA
-885.9mV  19.28mA    18.96mA    18.06mA
-487.3mV  15.17mA    14.99mA    14.26mA
-354.4mV  11.71mA    11.72mA    10.79mA
548.4mV   -17.15mA   -17.1mA    -15.61mA
801.6mV   -23.72mA   -23.14mA   -21.22mA
1.012V    -27.54mA   -26.21mA   -24.14mA
1.527V    -31.99mA   -29.83mA   -27.47mA
2.369V    -35.41mA   -32.77mA   -30.09mA
2.457V    -37.41mA   -33mA      -30.31mA
2.502V    -35.73mA   -33.12mA   -30.42mA
2.7V      -36.2mA    -33.61mA   -31.82mA
[Pulldown]
| Voltage   I(typ)   I(min)   I(max)
-1.35V    -26.85mA   -23.38mA   -23.85mA
-1.24V    -27.49mA   -24.35mA   -22.19mA
-1.196V   -27.51mA   -24.64mA   -19.49mA
-1.063V   -24.84mA   -24.71mA   -18.2mA
-974.5mV  -21.63mA   -23.69mA   -17.58mA
-531.6mV  -15.84mA   -16.19mA   -13.82mA
-354.4mV  -11.79mA   -11.81mA   -10.59mA
548.4mV   17.39mA    17.02mA    15.88mA
843.8mV   25.11mA    23.84mA    23.29mA
1.055V    29.14mA    26.48mA    27.64mA
1.394V    31.64mA    27.74mA    31.27mA
2.7V      34.07mA    29.71mA    33.88mA
[Ramp]
dV/dt_r   0.494545/0.121231n  0.470492/0.128409n  0.497789/0.1448n
dV/dt_f   0.497519/0.106713n  0.46994/0.117427n  0.502084/0.107541n
R_load = 50
[Rising Waveform]
R_fixture = 50
V_fixture = 0
V_fixture_min = 0
V_fixture_max = 0
| Time   V(typ)   V(min)   V(max)
0s        1.379uV    1.523uV    2.089uV
1.019ns   -831.4uV   -608.8uV   -2.296mV
1.242ns   -3.799mV   -742.4uV   670.9mV
1.334ns   34.32mV    -797.5uV   776.1mV
1.485ns   627.3mV    -887.9uV   817.5mV
1.539ns   743.6mV    -920.3uV   821.4mV
1.716ns   811.3mV    6.735mV    826.8mV
1.909ns   820.7mV    636.4mV    828.3mV
2.107ns   822.7mV    769.4mV    828.6mV
10ns      824.2mV    784.2mV    829.6mV
[Rising Waveform]
R_fixture = 50
V_fixture = 1.35
V_fixture_min = 1.2825
V_fixture_max = 1.4175
| Time   V(typ)   V(min)   V(max)
0s        520.8mV    499.2mV    580.7mV
928ps     521.4mV    499.6mV    585.4mV
1.114ns   521.5mV    499.7mV    1.303V
1.25ns    543.3mV    499.7mV    1.397V
1.333ns   927.8mV    499.8mV    1.408V
1.438ns   1.284V     499.8mV    1.413V
1.643ns   1.341V     523.6mV    1.416V
1.802ns   1.347V     1.161V     1.416V
1.988ns   1.348V     1.27V      1.416V
10ns      1.35V      1.282V     1.417V
[Falling Waveform]
R_fixture = 50
V_fixture = 0
V_fixture_min = 0
V_fixture_max = 0
| Time   V(typ)   V(min)   V(max)
0s        824.2mV    784.2mV    829.7mV
908ps     823.6mV    783.6mV    819.7mV
1.06ns    823.4mV    783.5mV    136mV
1.259ns   743.6mV    783.4mV    9.63mV
1.364ns   196.8mV    783.3mV    4.952mV
1.419ns   65.41mV    783.3mV    3.575mV
1.661ns   5.389mV    750.8mV    1.495mV
1.819ns   2.199mV    104.2mV    1.177mV
1.967ns   1.57mV     12.43mV    878.6uV
10ns      2.102uV    2.728uV    2.93uV
[Falling Waveform]
R_fixture = 50
V_fixture = 1.35
V_fixture_min = 1.2825
V_fixture_max = 1.4175
| Time   V(typ)   V(min)   V(max)
0s        1.35V      1.282V     1.417V
991ps     1.351V     1.283V     1.418V
1.168ns   1.351V     1.283V     729.8mV
1.379ns   1.156V     1.283V     591.4mV
1.479ns   686.9mV    1.283V     586.1mV
1.555ns   567.2mV    1.283V     584.3mV
1.751ns   527.3mV    1.227V     582.8mV
1.91ns    523.6mV    634.2mV    582.4mV
2.08ns    522.5mV    512.8mV    582mV
10ns      520.8mV    499.2mV    580.7mV
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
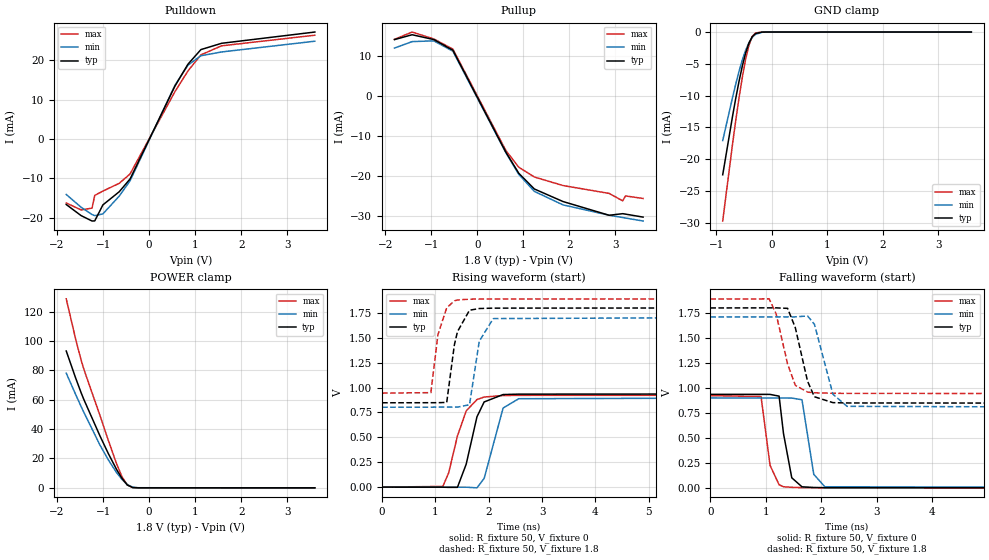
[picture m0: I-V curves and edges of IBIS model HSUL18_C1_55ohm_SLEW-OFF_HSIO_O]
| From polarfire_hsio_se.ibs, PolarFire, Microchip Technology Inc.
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|   Model HSUL18_C1_55ohm_SLEW-OFF_HSIO_O
[Model]   HSUL18_C1_55ohm_SLEW-OFF_HSIO_O
Model_type   Output
Polarity   Non-Inverting
Enable   Active-High
Vmeas =   0.9
Cref =   5p
Rref =   50
Vref =   0.9
|   typ   min   max
C_comp_pullup   1.335e-12   1.335e-12   1.380e-12
C_comp_pulldown  1.335e-12   1.335e-12   1.380e-12
[Temperature Range]  25C   100C   -40C
[Voltage Range]  1.8   1.71   1.89
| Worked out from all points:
|   slope of the pulldown table from 0 to 0.27 V, typ, clamps not added: 40 ohm
|   slope of the pullup table from 0 to 0.27 V, typ, clamps not added: 42.5 ohm
|   GND clamp passes 1 mA (typ) near -0.37 V on its own axis
|   POWER clamp passes 1 mA (typ) near -0.43 V on its own axis
|   rising waveform, R_fixture 50, V_fixture 0: 20-80 % time 253ps typ, 250ps min, 287ps max; typ from 0 V to 0.936 V
|   rising waveform, R_fixture 50, V_fixture 1.8: 20-80 % time 170ps typ, 175ps min, 163ps max; typ from 0.847 V to 1.8 V
|   falling waveform, R_fixture 50, V_fixture 0: 20-80 % time 137ps typ, 141ps min, 132ps max; typ from 0.936 V to 0 V
|   falling waveform, R_fixture 50, V_fixture 1.8: 20-80 % time 241ps typ, 245ps min, 243ps max; typ from 1.8 V to 0.847 V
[GND Clamp]
| Voltage   I(typ)   I(min)   I(max)
-885.9mV  -22.44mA   -17.06mA   -29.71mA
-708.7mV  -13.24mA   -10.28mA   -17.6mA
-649.7mV  -10.37mA   -8.138mA   -13.83mA
-590.6mV  -7.705mA   -6.148mA   -10.3mA
-531.6mV  -5.322mA   -4.371mA   -7.074mA
-472.5mV  -3.308mA   -2.865mA   -4.286mA
-413.4mV  -1.757mA   -1.684mA   -2.101mA
-354.4mV  -739.5uA   -855.1uA   -713.7uA
-295.3mV  -232.3uA   -363.2uA   -148.3uA
-177.2mV  -12.01uA   -39.02uA   -3.177uA
-59.06mV  -489.8nA   -2.616uA   -234.3nA
3.6V      0A         0A         0A
[POWER Clamp]
| Voltage   I(typ)   I(min)   I(max)
-1.8V     93.11mA    78.02mA    128.6mA
-1.595V   74.64mA    63.48mA    101.1mA
-1.477V   64.73mA    55.33mA    86.9mA
-1.417V   60.07mA    51.32mA    80.62mA
-1.063V   35.01mA    28.82mA    48.84mA
-885.9mV  23.32mA    19.01mA    32.31mA
-708.7mV  12.62mA    10.48mA    16.53mA
-590.6mV  6.476mA    5.751mA    7.626mA
-472.5mV  1.932mA    2.149mA    1.873mA
-354.4mV  154uA      469.9uA    209.6uA
-236.2mV  4.969uA    79.11uA    56.46uA
3.6V      0A         0A         0A
[Pullup]
| Voltage   I(typ)   I(min)   I(max)
-1.8V     14.21mA    12.09mA    14.28mA
-1.417V   15.43mA    13.71mA    16.11mA
-945mV    14.22mA    13.9mA     14.37mA
-531.6mV  11.54mA    11.3mA     11.83mA
618.8mV   -14.01mA   -14.14mA   -13.59mA
900mV     -19.31mA   -19.59mA   -17.8mA
1.238V    -23.25mA   -23.85mA   -20.24mA
1.859V    -26.39mA   -27.23mA   -22.38mA
2.863V    -29.84mA   -29.83mA   -24.36mA
3.158V    -29.44mA   -30.41mA   -26.23mA
3.217V    -29.55mA   -30.53mA   -24.99mA
3.6V      -30.3mA    -31.28mA   -25.63mA
[Pulldown]
| Voltage   I(typ)   I(min)   I(max)
-1.8V     -16.63mA   -14.08mA   -16.23mA
-1.477V   -19.45mA   -17.33mA   -18.01mA
-1.24V    -20.82mA   -19.18mA   -17.54mA
-1.181V   -20.79mA   -19.46mA   -14.31mA
-1.004V   -16.72mA   -19.01mA   -13.21mA
-649.7mV  -13.39mA   -14.5mA    -11.25mA
-413.4mV  -10.13mA   -10.59mA   -8.855mA
562.5mV   13.49mA    13.7mA     12.08mA
843.8mV   19.02mA    18.77mA    17.3mA
1.125V    22.73mA    21.17mA    21.39mA
1.575V    24.33mA    22.13mA    23.69mA
3.6V      27.19mA    24.86mA    26.38mA
[Ramp]
dV/dt_r   0.561316/0.252913n  0.539654/0.25025n  0.553599/0.287206n
dV/dt_f   0.571987/0.241065n  0.54457/0.245252n  0.567798/0.2427n
R_load = 50
[Rising Waveform]
R_fixture = 50
V_fixture = 0
V_fixture_min = 0
V_fixture_max = 0
| Time   V(typ)   V(min)   V(max)
0s        2.497uV    2.678uV    4.909uV
1.139ns   -703.8uV   -486.2uV   7.035mV
1.249ns   -2.44mV    -533.4uV   143.9mV
1.413ns   -2.078mV   -603.8uV   513.4mV
1.577ns   230.1mV    -674.2uV   765.2mV
1.779ns   706.1mV    -7.32mV    878.9mV
1.914ns   855.2mV    87.42mV    904.6mV
2.269ns   929.4mV    793.9mV    919.6mV
2.563ns   933.5mV    887.6mV    921.3mV
10ns      935.5mV    899.4mV    922.7mV
[Rising Waveform]
R_fixture = 50
V_fixture = 1.8
V_fixture_min = 1.71
V_fixture_max = 1.89
| Time   V(typ)   V(min)   V(max)
0s        846.7mV    802.3mV    943.7mV
915ps     847.4mV    802.8mV    948.4mV
1.048ns   847.5mV    802.9mV    1.532V
1.212ns   850.2mV    803mV      1.8V
1.356ns   1.43V      803.1mV    1.87V
1.414ns   1.561V     803.1mV    1.879V
1.639ns   1.776V     826.7mV    1.887V
1.822ns   1.793V     1.465V     1.888V
2.085ns   1.797V     1.692V     1.889V
10ns      1.8V       1.71V      1.89V
[Falling Waveform]
R_fixture = 50
V_fixture = 0
V_fixture_min = 0
V_fixture_max = 0
| Time   V(typ)   V(min)   V(max)
0s        935.6mV    899.5mV    922.7mV
914ps     935.1mV    898.9mV    913.7mV
1.076ns   935mV      898.8mV    225.1mV
1.239ns   917.7mV    898.7mV    30.9mV
1.318ns   543.6mV    898.7mV    10.88mV
1.467ns   100.7mV    898.6mV    5.176mV
1.651ns   10.29mV    881.4mV    2.226mV
1.863ns   3.53mV     135.4mV    1.454mV
2.063ns   1.761mV    10.56mV    1.059mV
10ns      4.439uV    3.97uV     4.931uV
[Falling Waveform]
R_fixture = 50
V_fixture = 1.8
V_fixture_min = 1.71
V_fixture_max = 1.89
| Time   V(typ)   V(min)   V(max)
0s        1.8V       1.71V      1.89V
1.06ns    1.801V     1.711V     1.891V
1.184ns   1.801V     1.711V     1.744V
1.392ns   1.796V     1.711V     1.239V
1.531ns   1.603V     1.711V     1.026V
1.751ns   1.067V     1.72V      958mV
1.875ns   911.4mV    1.637V     951.1mV
2.208ns   852.6mV    936.9mV    946.3mV
2.462ns   849.4mV    815.6mV    945mV
10ns      846.7mV    802.3mV    943.6mV
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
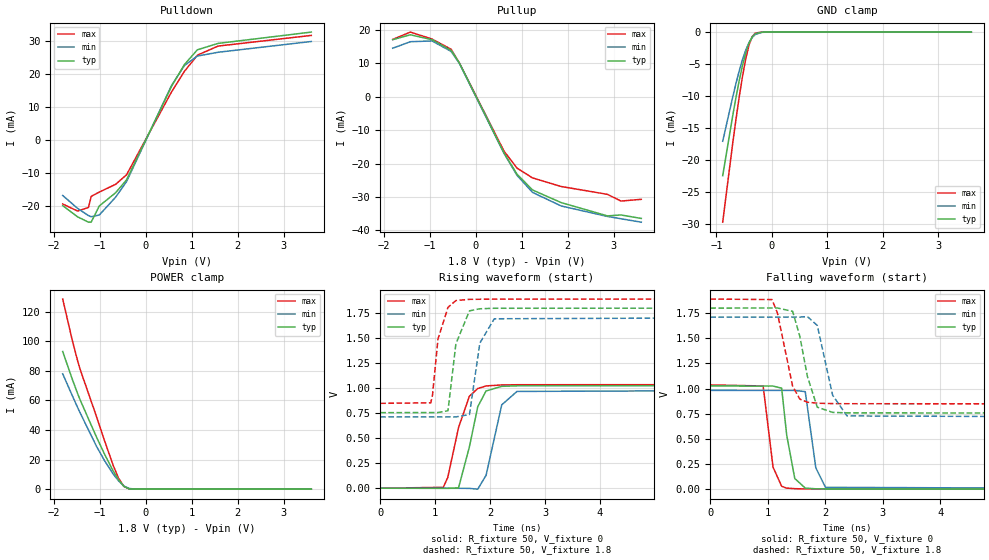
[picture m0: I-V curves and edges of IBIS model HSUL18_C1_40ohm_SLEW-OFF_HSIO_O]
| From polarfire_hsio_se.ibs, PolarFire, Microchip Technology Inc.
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|   Model HSUL18_C1_40ohm_SLEW-OFF_HSIO_O
[Model]   HSUL18_C1_40ohm_SLEW-OFF_HSIO_O
Model_type   Output
Polarity   Non-Inverting
Enable   Active-High
Vmeas =   0.9
Cref =   5p
Rref =   50
Vref =   0.9
|   typ   min   max
C_comp_pullup   1.335e-12   1.335e-12   1.380e-12
C_comp_pulldown  1.335e-12   1.335e-12   1.380e-12
[Temperature Range]  25C   100C   -40C
[Voltage Range]  1.8   1.71   1.89
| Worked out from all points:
|   slope of the pulldown table from 0 to 0.27 V, typ, clamps not added: 33.3 ohm
|   slope of the pullup table from 0 to 0.27 V, typ, clamps not added: 35.4 ohm
|   GND clamp passes 1 mA (typ) near -0.37 V on its own axis
|   POWER clamp passes 1 mA (typ) near -0.43 V on its own axis
|   rising waveform, R_fixture 50, V_fixture 0: 20-80 % time 230ps typ, 231ps min, 269ps max; typ from 0 V to 1.03 V
|   rising waveform, R_fixture 50, V_fixture 1.8: 20-80 % time 169ps typ, 177ps min, 162ps max; typ from 0.755 V to 1.8 V
|   falling waveform, R_fixture 50, V_fixture 0: 20-80 % time 138ps typ, 134ps min, 129ps max; typ from 1.03 V to 0 V
|   falling waveform, R_fixture 50, V_fixture 1.8: 20-80 % time 221ps typ, 224ps min, 221ps max; typ from 1.8 V to 0.755 V
[GND Clamp]
| Voltage   I(typ)   I(min)   I(max)
-885.9mV  -22.44mA   -17.06mA   -29.71mA
-708.7mV  -13.24mA   -10.28mA   -17.6mA
-649.7mV  -10.37mA   -8.138mA   -13.83mA
-590.6mV  -7.705mA   -6.148mA   -10.3mA
-531.6mV  -5.322mA   -4.371mA   -7.074mA
-472.5mV  -3.308mA   -2.865mA   -4.286mA
-413.4mV  -1.757mA   -1.684mA   -2.101mA
-354.4mV  -739.5uA   -855.1uA   -713.7uA
-295.3mV  -232.3uA   -363.2uA   -148.3uA
-177.2mV  -12.01uA   -39.02uA   -3.177uA
-59.06mV  -489.8nA   -2.616uA   -234.3nA
3.6V      0A         0A         0A
[POWER Clamp]
| Voltage   I(typ)   I(min)   I(max)
-1.8V     93.11mA    78.02mA    128.6mA
-1.595V   74.64mA    63.48mA    101.1mA
-1.477V   64.73mA    55.33mA    86.9mA
-1.417V   60.07mA    51.32mA    80.62mA
-1.063V   35.01mA    28.82mA    48.84mA
-885.9mV  23.32mA    19.01mA    32.31mA
-708.7mV  12.62mA    10.48mA    16.53mA
-590.6mV  6.476mA    5.751mA    7.626mA
-472.5mV  1.932mA    2.149mA    1.873mA
-354.4mV  154uA      469.9uA    209.6uA
-236.2mV  4.969uA    79.11uA    56.46uA
3.6V      0A         0A         0A
[Pullup]
| Voltage   I(typ)   I(min)   I(max)
-1.8V     17.05mA    14.51mA    17.13mA
-1.417V   18.52mA    16.45mA    19.33mA
-945mV    17.06mA    16.68mA    17.24mA
-531.6mV  13.85mA    13.56mA    14.2mA
-354.4mV  10.14mA    10.03mA    10.16mA
618.8mV   -16.82mA   -16.96mA   -16.3mA
900mV     -23.17mA   -23.51mA   -21.35mA
1.238V    -27.89mA   -28.62mA   -24.28mA
1.859V    -31.66mA   -32.67mA   -26.85mA
2.863V    -35.64mA   -35.8mA    -29.19mA
3.158V    -35.36mA   -36.49mA   -31.2mA
3.6V      -36.4mA    -37.52mA   -30.68mA
[Pulldown]
| Voltage   I(typ)   I(min)   I(max)
-1.8V     -19.98mA   -16.9mA    -19.48mA
-1.477V   -23.37mA   -20.8mA    -21.61mA
-1.24V    -25mA      -23.01mA   -20.53mA
-1.181V   -24.96mA   -23.35mA   -17.16mA
-1.004V   -20.05mA   -22.8mA    -15.86mA
-649.7mV  -16.06mA   -17.4mA    -13.5mA
-413.4mV  -12.15mA   -12.7mA    -10.62mA
562.5mV   16.17mA    16.44mA    14.49mA
843.8mV   22.82mA    22.52mA    20.76mA
1.125V    27.3mA     25.4mA     25.66mA
1.575V    29.24mA    26.55mA    28.43mA
3.6V      32.67mA    29.82mA    31.66mA
[Ramp]
dV/dt_r   0.615373/0.229559n  0.58945/0.230908n  0.621697/0.26859n
dV/dt_f   0.626727/0.220526n  0.598701/0.223683n  0.625115/0.220695n
R_load = 50
[Rising Waveform]
R_fixture = 50
V_fixture = 0
V_fixture_min = 0
V_fixture_max = 0
| Time   V(typ)   V(min)   V(max)
0s        2.38uV     2.517uV    4.62uV
1.147ns   -785.2uV   -450.1uV   9.157mV
1.229ns   -1.258mV   -482.5uV   107.6mV
1.425ns   3.307mV    -559.9uV   605.5mV
1.623ns   413.6mV    -1.483mV   919.6mV
1.775ns   814.1mV    -9.359mV   996mV
1.926ns   971.6mV    128.2mV    1.022V
2.212ns   1.018V     833.3mV    1.032V
2.49ns    1.023V     967.2mV    1.034V
10ns      1.026V     982.4mV    1.036V
[Rising Waveform]
R_fixture = 50
V_fixture = 1.8
V_fixture_min = 1.71
V_fixture_max = 1.89
| Time   V(typ)   V(min)   V(max)
0s        755.4mV    712.1mV    848.1mV
919ps     756.1mV    712.2mV    853.5mV
951ps     756.1mV    712.2mV    930.1mV
1.051ns   756.2mV    712.2mV    1.491V
1.233ns   774.4mV    712.2mV    1.807V
1.377ns   1.443V     712.2mV    1.875V
1.624ns   1.772V     736.6mV    1.887V
1.813ns   1.793V     1.45V      1.888V
2.076ns   1.798V     1.693V     1.889V
10ns      1.8V       1.71V      1.89V
[Falling Waveform]
R_fixture = 50
V_fixture = 0
V_fixture_min = 0
V_fixture_max = 0
| Time   V(typ)   V(min)   V(max)
0s        1.026V     982.4mV    1.036V
919ps     1.025V     982mV      1.026V
1.091ns   1.025V     981.9mV    219.4mV
1.241ns   1.004V     981.8mV    28.67mV
1.328ns   539.5mV    981.8mV    10.31mV
1.469ns   106mV      981.7mV    5.018mV
1.651ns   10.6mV     969.6mV    2.333mV
1.835ns   3.575mV    211.8mV    1.625mV
2.003ns   2.006mV    18.3mV     1.193mV
10ns      3.582uV    3.869uV    4.873uV
[Falling Waveform]
R_fixture = 50
V_fixture = 1.8
V_fixture_min = 1.71
V_fixture_max = 1.89
| Time   V(typ)   V(min)   V(max)
0s        1.8V       1.71V      1.89V
1.073ns   1.801V     1.71V      1.885V
1.166ns   1.801V     1.71V      1.755V
1.431ns   1.768V     1.711V     1.025V
1.556ns   1.522V     1.711V     895.6mV
1.688ns   1.122V     1.716V     864.7mV
1.86ns    815mV      1.628V     854.8mV
2.127ns   763.4mV    933.7mV    850.7mV
2.377ns   758.5mV    728.1mV    849.4mV
10ns      755.4mV    712.1mV    848.1mV
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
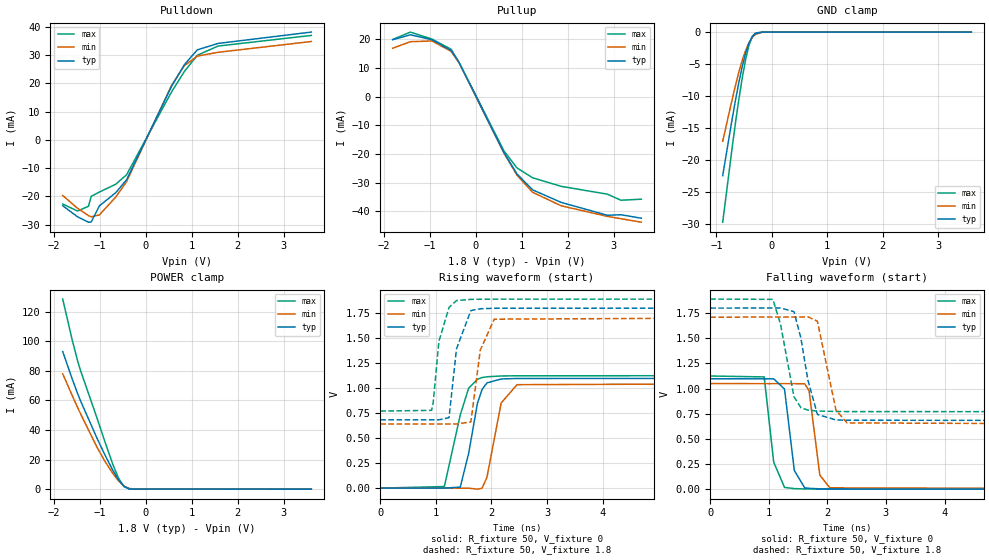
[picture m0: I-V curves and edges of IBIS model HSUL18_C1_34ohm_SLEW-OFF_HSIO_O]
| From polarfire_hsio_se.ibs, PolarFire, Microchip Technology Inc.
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|   Model HSUL18_C1_34ohm_SLEW-OFF_HSIO_O
[Model]   HSUL18_C1_34ohm_SLEW-OFF_HSIO_O
Model_type   Output
Polarity   Non-Inverting
Enable   Active-High
Vmeas =   0.9
Cref =   5p
Rref =   50
Vref =   0.9
|   typ   min   max
C_comp_pullup   1.335e-12   1.335e-12   1.380e-12
C_comp_pulldown  1.335e-12   1.335e-12   1.380e-12
[Temperature Range]  25C   100C   -40C
[Voltage Range]  1.8   1.71   1.89
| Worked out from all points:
|   slope of the pulldown table from 0 to 0.27 V, typ, clamps not added: 28.6 ohm
|   slope of the pullup table from 0 to 0.27 V, typ, clamps not added: 30.4 ohm
|   GND clamp passes 1 mA (typ) near -0.37 V on its own axis
|   POWER clamp passes 1 mA (typ) near -0.43 V on its own axis
|   rising waveform, R_fixture 50, V_fixture 0: 20-80 % time 214ps typ, 211ps min, 251ps max; typ from 0 V to 1.1 V
|   rising waveform, R_fixture 50, V_fixture 1.8: 20-80 % time 168ps typ, 177ps min, 162ps max; typ from 0.682 V to 1.8 V
|   falling waveform, R_fixture 50, V_fixture 0: 20-80 % time 136ps typ, 132ps min, 129ps max; typ from 1.1 V to 0 V
|   falling waveform, R_fixture 50, V_fixture 1.8: 20-80 % time 204ps typ, 205ps min, 205ps max; typ from 1.8 V to 0.682 V
[GND Clamp]
| Voltage   I(typ)   I(min)   I(max)
-885.9mV  -22.44mA   -17.06mA   -29.71mA
-708.7mV  -13.24mA   -10.28mA   -17.6mA
-649.7mV  -10.37mA   -8.138mA   -13.83mA
-590.6mV  -7.705mA   -6.148mA   -10.3mA
-531.6mV  -5.322mA   -4.371mA   -7.074mA
-472.5mV  -3.308mA   -2.865mA   -4.286mA
-413.4mV  -1.757mA   -1.684mA   -2.101mA
-354.4mV  -739.5uA   -855.1uA   -713.7uA
-295.3mV  -232.3uA   -363.2uA   -148.3uA
-177.2mV  -12.01uA   -39.02uA   -3.177uA
-59.06mV  -489.8nA   -2.616uA   -234.3nA
3.6V      0A         0A         0A
[POWER Clamp]
| Voltage   I(typ)   I(min)   I(max)
-1.8V     93.11mA    78.02mA    128.6mA
-1.595V   74.64mA    63.48mA    101.1mA
-1.477V   64.73mA    55.33mA    86.9mA
-1.417V   60.07mA    51.32mA    80.62mA
-1.063V   35.01mA    28.82mA    48.84mA
-885.9mV  23.32mA    19.01mA    32.31mA
-708.7mV  12.62mA    10.48mA    16.53mA
-590.6mV  6.476mA    5.751mA    7.626mA
-472.5mV  1.932mA    2.149mA    1.873mA
-354.4mV  154uA      469.9uA    209.6uA
-236.2mV  4.969uA    79.11uA    56.46uA
3.6V      0A         0A         0A
[Pullup]
| Voltage   I(typ)   I(min)   I(max)
-1.8V     19.89mA    16.92mA    19.99mA
-1.417V   21.61mA    19.2mA     22.56mA
-945mV    19.9mA     19.46mA    20.11mA
-531.6mV  16.16mA    15.82mA    16.56mA
-354.4mV  11.83mA    11.7mA     11.85mA
618.8mV   -19.62mA   -19.79mA   -19.02mA
900mV     -27.03mA   -27.43mA   -24.91mA
1.238V    -32.54mA   -33.39mA   -28.33mA
1.859V    -36.94mA   -38.12mA   -31.33mA
2.863V    -41.43mA   -41.82mA   -34.06mA
3.158V    -41.25mA   -42.64mA   -36.18mA
3.6V      -42.46mA   -43.85mA   -35.81mA
[Pulldown]
| Voltage   I(typ)   I(min)   I(max)
-1.8V     -23.31mA   -19.71mA   -22.73mA
-1.477V   -27.26mA   -24.26mA   -25.21mA
-1.24V    -29.16mA   -26.84mA   -23.53mA
-1.181V   -29.1mA    -27.24mA   -20.02mA
-1.004V   -23.39mA   -26.59mA   -18.5mA
-649.7mV  -18.74mA   -20.29mA   -15.74mA
-413.4mV  -14.17mA   -14.81mA   -12.39mA
562.5mV   18.87mA    19.17mA    16.9mA
843.8mV   26.62mA    26.26mA    24.21mA
1.125V    31.84mA    29.62mA    29.93mA
1.575V    34.1mA     30.96mA    33.17mA
3.6V      38.11mA    34.78mA    36.93mA
[Ramp]
dV/dt_r   0.658922/0.213813n  0.629948/0.211142n  0.674863/0.251344n
dV/dt_f   0.670748/0.204446n  0.641569/0.204555n  0.671997/0.204831n
R_load = 50
[Rising Waveform]
R_fixture = 50
V_fixture = 0
V_fixture_min = 0
V_fixture_max = 0
| Time   V(typ)   V(min)   V(max)
0s        2.283uV    2.387uV    4.381uV
1.153ns   -453.2uV   -579uV     15.76mV
1.439ns   10.04mV    -723.2uV   732.1mV
1.59ns    347.4mV    -799.3uV   998.4mV
1.747ns   845.3mV    -10.65mV   1.088V
1.83ns    985.4mV    -1.535mV   1.105V
1.919ns   1.052V     107.8mV    1.113V
2.175ns   1.091V     851.3mV    1.121V
2.46ns    1.096V     1.034V     1.123V
10ns      1.098V     1.05V      1.125V
[Rising Waveform]
R_fixture = 50
V_fixture = 1.8
V_fixture_min = 1.71
V_fixture_max = 1.89
| Time   V(typ)   V(min)   V(max)
0s        682.1mV    640.7mV    770mV
922ps     682.7mV    641.2mV    777.3mV
952ps     682.7mV    641.2mV    851.7mV
1.054ns   682.8mV    641.3mV    1.466V
1.237ns   704.6mV    641.4mV    1.806V
1.371ns   1.392V     641.5mV    1.875V
1.63ns    1.775V     660.8mV    1.887V
1.799ns   1.793V     1.379V     1.888V
2.05ns    1.798V     1.689V     1.889V
10ns      1.8V       1.71V      1.89V
[Falling Waveform]
R_fixture = 50
V_fixture = 0
V_fixture_min = 0
V_fixture_max = 0
| Time   V(typ)   V(min)   V(max)
0s        1.098V     1.05V      1.125V
921ps     1.097V     1.049V     1.116V
1.083ns   1.097V     1.049V     268.4mV
1.268ns   995.2mV    1.049V     17.34mV
1.435ns   186mV      1.049V     5.449mV
1.613ns   12.84mV    1.048V     2.546mV
1.687ns   8.71mV     977.7mV    2.145mV
1.871ns   3.11mV     139.3mV    1.477mV
2.042ns   1.863mV    13.13mV    1.148mV
10ns      3.433uV    3.981uV    4.802uV
[Falling Waveform]
R_fixture = 50
V_fixture = 1.8
V_fixture_min = 1.71
V_fixture_max = 1.89
| Time   V(typ)   V(min)   V(max)
0s        1.8V       1.71V      1.89V
1.069ns   1.801V     1.711V     1.887V
1.2ns     1.801V     1.711V     1.639V
1.429ns   1.765V     1.711V     918.7mV
1.547ns   1.503V     1.711V     810.8mV
1.666ns   1.087V     1.714V     786.2mV
1.829ns   743.2mV    1.67V      776.8mV
2.146ns   688.3mV    787mV      772.2mV
2.335ns   685.2mV    658.9mV    771.3mV
10ns      682.1mV    640.7mV    770mV
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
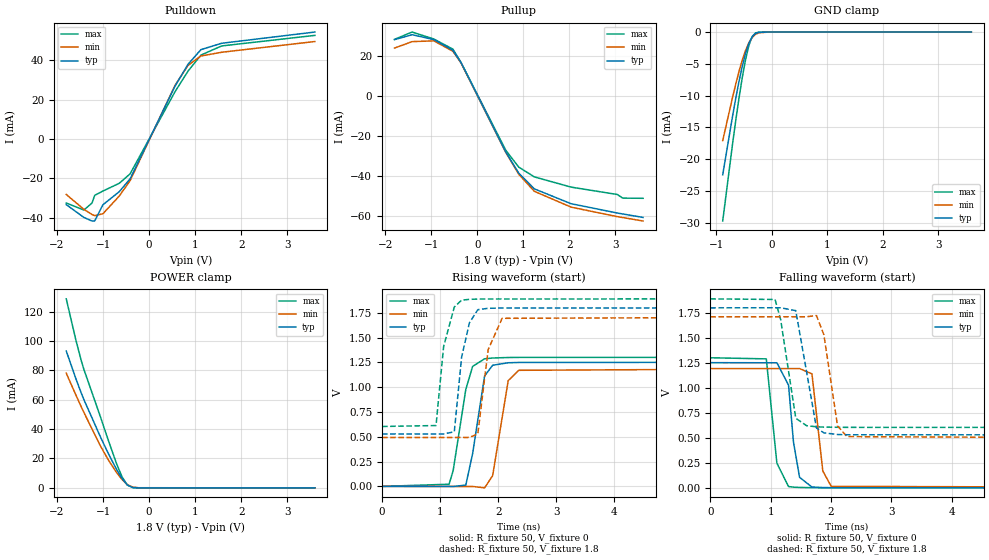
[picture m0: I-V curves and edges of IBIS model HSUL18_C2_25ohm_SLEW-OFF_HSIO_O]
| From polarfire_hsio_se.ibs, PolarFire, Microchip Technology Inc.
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|   Model HSUL18_C2_25ohm_SLEW-OFF_HSIO_O
[Model]   HSUL18_C2_25ohm_SLEW-OFF_HSIO_O
Model_type   Output
Polarity   Non-Inverting
Enable   Active-High
Vmeas =   0.9
Cref =   5p
Rref =   50
Vref =   0.9
|   typ   min   max
C_comp_pullup   1.335e-12   1.335e-12   1.380e-12
C_comp_pulldown  1.335e-12   1.335e-12   1.380e-12
[Temperature Range]  25C   100C   -40C
[Voltage Range]  1.8   1.71   1.89
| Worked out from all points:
|   slope of the pulldown table from 0 to 0.27 V, typ, clamps not added: 20 ohm
|   slope of the pullup table from 0 to 0.27 V, typ, clamps not added: 21.3 ohm
|   GND clamp passes 1 mA (typ) near -0.37 V on its own axis
|   POWER clamp passes 1 mA (typ) near -0.43 V on its own axis
|   rising waveform, R_fixture 50, V_fixture 0: 20-80 % time 179ps typ, 185ps min, 211ps max; typ from 0 V to 1.25 V
|   rising waveform, R_fixture 50, V_fixture 1.8: 20-80 % time 166ps typ, 173ps min, 160ps max; typ from 0.528 V to 1.8 V
|   falling waveform, R_fixture 50, V_fixture 0: 20-80 % time 131ps typ, 127ps min, 127ps max; typ from 1.25 V to 0 V
|   falling waveform, R_fixture 50, V_fixture 1.8: 20-80 % time 170ps typ, 170ps min, 172ps max; typ from 1.8 V to 0.528 V
[GND Clamp]
| Voltage   I(typ)   I(min)   I(max)
-885.9mV  -22.44mA   -17.06mA   -29.71mA
-708.7mV  -13.24mA   -10.28mA   -17.6mA
-649.7mV  -10.37mA   -8.138mA   -13.83mA
-590.6mV  -7.705mA   -6.148mA   -10.3mA
-531.6mV  -5.322mA   -4.371mA   -7.074mA
-472.5mV  -3.308mA   -2.865mA   -4.286mA
-413.4mV  -1.757mA   -1.684mA   -2.101mA
-354.4mV  -739.5uA   -855.1uA   -713.7uA
-295.3mV  -232.3uA   -363.2uA   -148.3uA
-236.2mV  -56.73uA   -128.2uA   -22.51uA
-59.06mV  -489.8nA   -2.616uA   -234.3nA
3.6V      0A         0A         0A
[POWER Clamp]
| Voltage   I(typ)   I(min)   I(max)
-1.8V     93.11mA    78.02mA    128.6mA
-1.595V   74.64mA    63.48mA    101.1mA
-1.477V   64.73mA    55.33mA    86.9mA
-1.417V   60.07mA    51.32mA    80.62mA
-1.063V   35.01mA    28.82mA    48.84mA
-885.9mV  23.32mA    19.01mA    32.31mA
-708.7mV  12.62mA    10.48mA    16.53mA
-590.6mV  6.476mA    5.751mA    7.626mA
-472.5mV  1.932mA    2.149mA    1.873mA
-354.4mV  154uA      469.9uA    209.6uA
-236.2mV  4.969uA    79.11uA    56.46uA
3.6V      0A         0A         0A
[Pullup]
| Voltage   I(typ)   I(min)   I(max)
-1.8V     28.42mA    24.18mA    28.56mA
-1.417V   30.88mA    27.42mA    32.23mA
-945mV    28.44mA    27.8mA     28.73mA
-531.6mV  23.08mA    22.6mA     23.65mA
-354.4mV  16.9mA     16.71mA    16.93mA
618.8mV   -28.02mA   -28.26mA   -27.16mA
900mV     -38.61mA   -39.18mA   -35.58mA
1.238V    -46.48mA   -47.69mA   -40.46mA
2.036V    -53.91mA   -55.64mA   -45.59mA
3.04V     -58.6mA    -60.4mA    -49.29mA
3.158V    -59.06mA   -60.86mA   -51.12mA
3.6V      -60.81mA   -62.6mA    -51.2mA
[Pulldown]
| Voltage   I(typ)   I(min)   I(max)
-1.8V     -33.33mA   -28.16mA   -32.5mA
-1.417V   -39.84mA   -35.72mA   -36.08mA
-1.24V    -41.66mA   -38.35mA   -32.48mA
-1.181V   -41.58mA   -38.91mA   -28.58mA
-1.004V   -33.4mA    -37.98mA   -26.42mA
-649.7mV  -26.76mA   -28.98mA   -22.48mA
-413.4mV  -20.23mA   -21.14mA   -17.68mA
562.5mV   26.94mA    27.35mA    24.11mA
843.8mV   38.03mA    37.48mA    34.55mA
1.125V    45.52mA    42.28mA    42.74mA
1.575V    48.76mA    44.19mA    47.4mA
3.6V      54.48mA    49.65mA    52.77mA
[Ramp]
dV/dt_r   0.751089/0.178842n  0.716047/0.184666n  0.780714/0.21113n
dV/dt_f   0.763086/0.169686n  0.730314/0.170067n  0.771702/0.172428n
R_load = 50
[Rising Waveform]
R_fixture = 50
V_fixture = 0
V_fixture_min = 0
V_fixture_max = 0
| Time   V(typ)   V(min)   V(max)
0s        2.078uV    2.108uV    3.864uV
1.154ns   -426.7uV   -497.3uV   22.07mV
1.224ns   -1.249mV   -527.5uV   158.6mV
1.442ns   13.41mV    -621.9uV   978mV
1.559ns   329.5mV    -672.5uV   1.209V
1.765ns   1.113V     -14.6mV    1.286V
1.904ns   1.221V     108mV      1.294V
2.172ns   1.246V     1.066V     1.299V
2.354ns   1.249V     1.17V      1.3V
10ns      1.252V     1.193V     1.301V
[Rising Waveform]
R_fixture = 50
V_fixture = 1.8
V_fixture_min = 1.71
V_fixture_max = 1.89
| Time   V(typ)   V(min)   V(max)
0s        528.2mV    492.8mV    603.8mV
929ps     528.5mV    493.1mV    613.4mV
1.06ns    528.6mV    493.2mV    1.41V
1.244ns   550.7mV    493.2mV    1.808V
1.369ns   1.3V       493.3mV    1.877V
1.504ns   1.648V     493.3mV    1.885V
1.649ns   1.781V     529.6mV    1.888V
1.827ns   1.795V     1.379V     1.889V
2.067ns   1.798V     1.694V     1.889V
10ns      1.8V       1.71V      1.89V
[Falling Waveform]
R_fixture = 50
V_fixture = 0
V_fixture_min = 0
V_fixture_max = 0
| Time   V(typ)   V(min)   V(max)
0s        1.252V     1.193V     1.301V
928ps     1.251V     1.193V     1.29V
1.103ns   1.251V     1.193V     247.1mV
1.296ns   1.028V     1.193V     13.11mV
1.378ns   458mV      1.193V     6.777mV
1.479ns   105mV      1.193V     4.095mV
1.684ns   8.019mV    1.14V      1.877mV
1.864ns   2.601mV    168.4mV    1.332mV
2.003ns   1.797mV    15.17mV    1.046mV
10ns      2.882uV    3.046uV    4.01uV
[Falling Waveform]
R_fixture = 50
V_fixture = 1.8
V_fixture_min = 1.71
V_fixture_max = 1.89
| Time   V(typ)   V(min)   V(max)
0s        1.8V       1.71V      1.89V
1.073ns   1.801V     1.711V     1.884V
1.165ns   1.801V     1.711V     1.685V
1.416ns   1.772V     1.711V     695.9mV
1.595ns   1.161V     1.711V     621.6mV
1.759ns   598.5mV    1.723V     610.6mV
1.882ns   549.9mV    1.53V      607.7mV
2.108ns   533.4mV    618.6mV    605.6mV
2.265ns   530.9mV    512.2mV    605mV
10ns      528.2mV    492.8mV    603.8mV
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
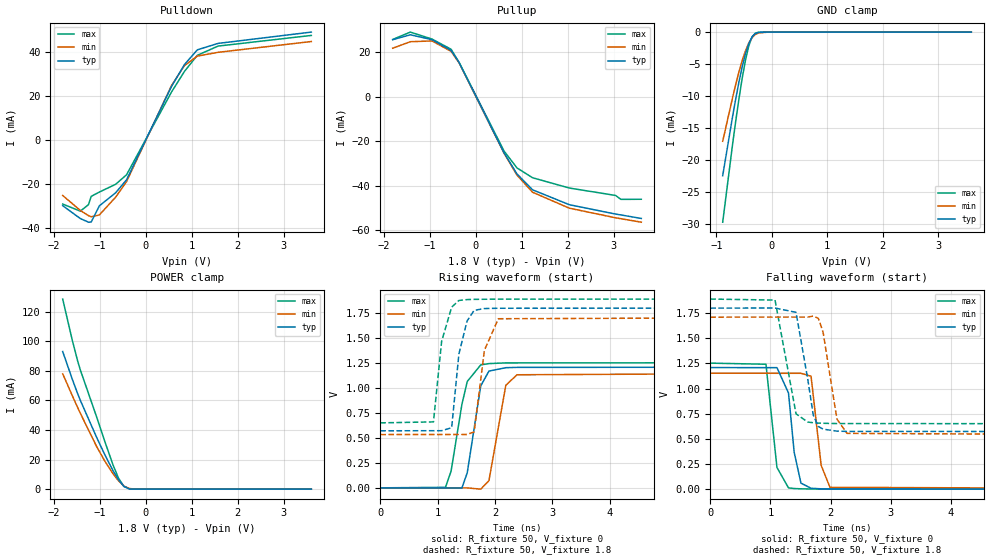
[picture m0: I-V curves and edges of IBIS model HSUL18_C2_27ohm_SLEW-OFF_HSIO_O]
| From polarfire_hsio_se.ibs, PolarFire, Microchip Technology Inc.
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|   Model HSUL18_C2_27ohm_SLEW-OFF_HSIO_O
[Model]   HSUL18_C2_27ohm_SLEW-OFF_HSIO_O
Model_type   Output
Polarity   Non-Inverting
Enable   Active-High
Vmeas =   0.9
Cref =   5p
Rref =   50
Vref =   0.9
|   typ   min   max
C_comp_pullup   1.335e-12   1.335e-12   1.380e-12
C_comp_pulldown  1.335e-12   1.335e-12   1.380e-12
[Temperature Range]  25C   100C   -40C
[Voltage Range]  1.8   1.71   1.89
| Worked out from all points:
|   slope of the pulldown table from 0 to 0.27 V, typ, clamps not added: 22.2 ohm
|   slope of the pullup table from 0 to 0.27 V, typ, clamps not added: 23.6 ohm
|   GND clamp passes 1 mA (typ) near -0.37 V on its own axis
|   POWER clamp passes 1 mA (typ) near -0.43 V on its own axis
|   rising waveform, R_fixture 50, V_fixture 0: 20-80 % time 191ps typ, 191ps min, 222ps max; typ from 0 V to 1.21 V
|   rising waveform, R_fixture 50, V_fixture 1.8: 20-80 % time 168ps typ, 176ps min, 161ps max; typ from 0.571 V to 1.8 V
|   falling waveform, R_fixture 50, V_fixture 0: 20-80 % time 130ps typ, 126ps min, 128ps max; typ from 1.21 V to 0 V
|   falling waveform, R_fixture 50, V_fixture 1.8: 20-80 % time 182ps typ, 182ps min, 182ps max; typ from 1.8 V to 0.571 V
[GND Clamp]
| Voltage   I(typ)   I(min)   I(max)
-885.9mV  -22.44mA   -17.06mA   -29.71mA
-708.7mV  -13.24mA   -10.28mA   -17.6mA
-649.7mV  -10.37mA   -8.138mA   -13.83mA
-590.6mV  -7.705mA   -6.148mA   -10.3mA
-531.6mV  -5.322mA   -4.371mA   -7.074mA
-472.5mV  -3.308mA   -2.865mA   -4.286mA
-413.4mV  -1.757mA   -1.684mA   -2.101mA
-354.4mV  -739.5uA   -855.1uA   -713.7uA
-295.3mV  -232.3uA   -363.2uA   -148.3uA
-236.2mV  -56.73uA   -128.2uA   -22.51uA
-59.06mV  -489.8nA   -2.616uA   -234.3nA
3.6V      0A         0A         0A
[POWER Clamp]
| Voltage   I(typ)   I(min)   I(max)
-1.8V     93.11mA    78.02mA    128.6mA
-1.595V   74.64mA    63.48mA    101.1mA
-1.477V   64.73mA    55.33mA    86.9mA
-1.417V   60.07mA    51.32mA    80.62mA
-1.063V   35.01mA    28.82mA    48.84mA
-885.9mV  23.32mA    19.01mA    32.31mA
-708.7mV  12.62mA    10.48mA    16.53mA
-590.6mV  6.476mA    5.751mA    7.626mA
-472.5mV  1.932mA    2.149mA    1.873mA
-354.4mV  154uA      469.9uA    209.6uA
-236.2mV  4.969uA    79.11uA    56.46uA
3.6V      0A         0A         0A
[Pullup]
| Voltage   I(typ)   I(min)   I(max)
-1.8V     25.58mA    21.76mA    25.7mA
-1.417V   27.79mA    24.68mA    29mA
-945mV    25.59mA    25.02mA    25.86mA
-531.6mV  20.77mA    20.34mA    21.29mA
-354.4mV  15.21mA    15.04mA    15.24mA
618.8mV   -25.22mA   -25.44mA   -24.45mA
900mV     -34.75mA   -35.26mA   -32.02mA
1.238V    -41.84mA   -42.93mA   -36.42mA
2.036V    -48.52mA   -50.08mA   -41.04mA
3.04V     -52.73mA   -54.4mA    -44.36mA
3.158V    -53.13mA   -54.82mA   -46.14mA
3.6V      -54.7mA    -56.38mA   -46.08mA
[Pulldown]
| Voltage   I(typ)   I(min)   I(max)
-1.8V     -29.98mA   -25.35mA   -29.24mA
-1.417V   -35.84mA   -32.15mA   -32.47mA
-1.24V    -37.49mA   -34.52mA   -29.5mA
-1.181V   -37.41mA   -35.02mA   -25.73mA
-1.004V   -30.06mA   -34.19mA   -23.78mA
-649.7mV  -24.08mA   -26.09mA   -20.24mA
-413.4mV  -18.21mA   -19.04mA   -15.92mA
562.5mV   24.25mA    24.64mA    21.71mA
843.8mV   34.22mA    33.75mA    31.1mA
1.125V    40.95mA    38.08mA    38.46mA
1.575V    43.86mA    39.81mA    42.64mA
3.6V      49.01mA    44.72mA    47.49mA
[Ramp]
dV/dt_r   0.725257/0.191401n  0.6918/0.191399n  0.751828/0.222201n
dV/dt_f   0.737266/0.181623n  0.705854/0.182377n  0.74361/0.181656n
R_load = 50
[Rising Waveform]
R_fixture = 50
V_fixture = 0
V_fixture_min = 0
V_fixture_max = 0
| Time   V(typ)   V(min)   V(max)
0s        2.136uV    2.186uV    4.012uV
1.136ns   -520.3uV   -437.1uV   5.13mV
1.234ns   -2.085mV   -475uV     167.1mV
1.422ns   -1.925mV   -547.7uV   833.6mV
1.516ns   151.8mV    -584.1uV   1.065V
1.751ns   1.021V     -13.3mV    1.231V
1.894ns   1.169V     72.26mV    1.244V
2.188ns   1.203V     1.027V     1.251V
2.383ns   1.206V     1.132V     1.251V
10ns      1.209V     1.153V     1.253V
[Rising Waveform]
R_fixture = 50
V_fixture = 1.8
V_fixture_min = 1.71
V_fixture_max = 1.89
| Time   V(typ)   V(min)   V(max)
0s        571.2mV    533.5mV    650.6mV
927ps     571.9mV    533.9mV    660.2mV
1.069ns   572mV      533.9mV    1.466V
1.244ns   601.8mV    534mV      1.809V
1.37ns    1.339V     534mV      1.876V
1.512ns   1.67V      534.1mV    1.885V
1.636ns   1.777V     560mV      1.887V
1.815ns   1.795V     1.378V     1.888V
2.058ns   1.798V     1.693V     1.889V
10ns      1.8V       1.71V      1.89V
[Falling Waveform]
R_fixture = 50
V_fixture = 0
V_fixture_min = 0
V_fixture_max = 0
| Time   V(typ)   V(min)   V(max)
0s        1.209V     1.153V     1.253V
926ps     1.208V     1.153V     1.242V
1.109ns   1.208V     1.152V     215.5mV
1.301ns   955.8mV    1.152V     13.05mV
1.395ns   367.7mV    1.152V     6.49mV
1.508ns   60.27mV    1.152V     3.544mV
1.676ns   8.96mV     1.123V     2.026mV
1.844ns   3.339mV    236.6mV    1.471mV
1.99ns    1.926mV    18.38mV    1.123mV
10ns      2.882uV    3.381uV    4.408uV
[Falling Waveform]
R_fixture = 50
V_fixture = 1.8
V_fixture_min = 1.71
V_fixture_max = 1.89
| Time   V(typ)   V(min)   V(max)
0s        1.8V       1.71V      1.89V
1.077ns   1.801V     1.711V     1.88V
1.426ns   1.758V     1.711V     749.2mV
1.62ns    1.097V     1.711V     667.4mV
1.713ns   735.7mV    1.721V     660.3mV
1.797ns   624mV      1.699V     657mV
1.876ns   596.6mV    1.561V     655mV
2.106ns   577mV      697.5mV    652.3mV
2.274ns   574.2mV    554.5mV    652mV
10ns      571.2mV    533.6mV    650.6mV
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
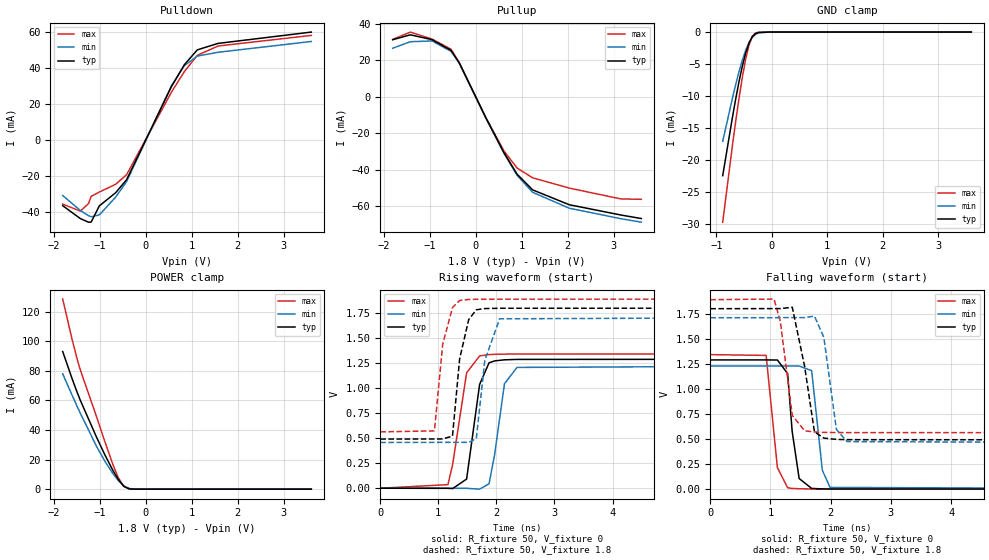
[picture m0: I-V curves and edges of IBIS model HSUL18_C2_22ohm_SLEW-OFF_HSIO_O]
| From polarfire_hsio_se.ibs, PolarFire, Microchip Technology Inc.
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|   Model HSUL18_C2_22ohm_SLEW-OFF_HSIO_O
[Model]   HSUL18_C2_22ohm_SLEW-OFF_HSIO_O
Model_type   Output
Polarity   Non-Inverting
Enable   Active-High
Vmeas =   0.9
Cref =   5p
Rref =   50
Vref =   0.9
|   typ   min   max
C_comp_pullup   1.335e-12   1.335e-12   1.380e-12
C_comp_pulldown  1.335e-12   1.335e-12   1.380e-12
[Temperature Range]  25C   100C   -40C
[Voltage Range]  1.8   1.71   1.89
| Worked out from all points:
|   slope of the pulldown table from 0 to 0.27 V, typ, clamps not added: 18.2 ohm
|   slope of the pullup table from 0 to 0.27 V, typ, clamps not added: 19.3 ohm
|   GND clamp passes 1 mA (typ) near -0.37 V on its own axis
|   POWER clamp passes 1 mA (typ) near -0.43 V on its own axis
|   rising waveform, R_fixture 50, V_fixture 0: 20-80 % time 172ps typ, 177ps min, 200ps max; typ from 0 V to 1.29 V
|   rising waveform, R_fixture 50, V_fixture 1.8: 20-80 % time 166ps typ, 172ps min, 160ps max; typ from 0.491 V to 1.8 V
|   falling waveform, R_fixture 50, V_fixture 0: 20-80 % time 128ps typ, 125ps min, 126ps max; typ from 1.29 V to 0 V
|   falling waveform, R_fixture 50, V_fixture 1.8: 20-80 % time 163ps typ, 163ps min, 163ps max; typ from 1.8 V to 0.491 V
[GND Clamp]
| Voltage   I(typ)   I(min)   I(max)
-885.9mV  -22.44mA   -17.06mA   -29.71mA
-708.7mV  -13.24mA   -10.28mA   -17.6mA
-649.7mV  -10.37mA   -8.138mA   -13.83mA
-590.6mV  -7.705mA   -6.148mA   -10.3mA
-531.6mV  -5.322mA   -4.371mA   -7.074mA
-472.5mV  -3.308mA   -2.865mA   -4.286mA
-413.4mV  -1.757mA   -1.684mA   -2.101mA
-354.4mV  -739.5uA   -855.1uA   -713.7uA
-295.3mV  -232.3uA   -363.2uA   -148.3uA
-236.2mV  -56.73uA   -128.2uA   -22.51uA
-59.06mV  -489.8nA   -2.616uA   -234.3nA
3.6V      0A         0A         0A
[POWER Clamp]
| Voltage   I(typ)   I(min)   I(max)
-1.8V     93.11mA    78.02mA    128.6mA
-1.595V   74.64mA    63.48mA    101.1mA
-1.477V   64.73mA    55.33mA    86.9mA
-1.417V   60.07mA    51.32mA    80.62mA
-1.063V   35.01mA    28.82mA    48.84mA
-885.9mV  23.32mA    19.01mA    32.31mA
-708.7mV  12.62mA    10.48mA    16.53mA
-590.6mV  6.476mA    5.751mA    7.626mA
-472.5mV  1.932mA    2.149mA    1.873mA
-354.4mV  154uA      469.9uA    209.6uA
-236.2mV  4.969uA    79.11uA    56.46uA
3.6V      0A         0A         0A
[Pullup]
| Voltage   I(typ)   I(min)   I(max)
-1.8V     31.26mA    26.6mA     31.42mA
-1.417V   33.96mA    30.17mA    35.45mA
-945mV    31.28mA    30.58mA    31.61mA
-531.6mV  25.39mA    24.86mA    26.02mA
-354.4mV  18.59mA    18.38mA    18.62mA
225mV     -11.68mA   -11.74mA   -11.6mA
618.8mV   -30.82mA   -31.09mA   -29.87mA
900mV     -42.47mA   -43.09mA   -39.13mA
1.238V    -51.13mA   -52.46mA   -44.51mA
2.036V    -59.3mA    -61.21mA   -50.16mA
3.158V    -64.94mA   -66.97mA   -56.11mA
3.6V      -66.86mA   -68.87mA   -56.31mA
[Pulldown]
| Voltage   I(typ)   I(min)   I(max)
-1.8V     -36.65mA   -31mA      -35.75mA
-1.417V   -43.81mA   -39.31mA   -39.68mA
-1.24V    -45.82mA   -42.2mA    -35.47mA
-1.181V   -45.72mA   -42.82mA   -31.44mA
-1.004V   -36.73mA   -41.77mA   -29.06mA
-649.7mV  -29.43mA   -31.87mA   -24.73mA
-413.4mV  -22.25mA   -23.26mA   -19.45mA
562.5mV   29.62mA    30.1mA     26.52mA
843.8mV   41.81mA    41.25mA    38mA
1.125V    50.03mA    46.55mA    47.01mA
1.575V    53.6mA     48.67mA    52.14mA
3.6V      59.89mA    54.67mA    58.05mA
[Ramp]
dV/dt_r   0.77347/0.172325n  0.736991/0.177327n  0.805464/0.200246n
dV/dt_f   0.785211/0.16326n  0.7515/0.16287n  0.796186/0.16341n
R_load = 50
[Rising Waveform]
R_fixture = 50
V_fixture = 0
V_fixture_min = 0
V_fixture_max = 0
| Time   V(typ)   V(min)   V(max)
0s        2.028uV    2.04uV     3.736uV
1.165ns   -642.1uV   -707.6uV   35.89mV
1.246ns   -3.73mV    -757uV     235.9mV
1.487ns   91.6mV     -903.8uV   1.153V
1.711ns   1.037V     -9.385mV   1.322V
1.873ns   1.253V     44.42mV    1.335V
1.967ns   1.272V     327mV      1.338V
2.139ns   1.283V     1.044V     1.34V
2.355ns   1.287V     1.207V     1.341V
10ns      1.289V     1.228V     1.342V
[Rising Waveform]
R_fixture = 50
V_fixture = 1.8
V_fixture_min = 1.71
V_fixture_max = 1.89
| Time   V(typ)   V(min)   V(max)
0s        491.3mV    457.5mV    563mV
933ps     492mV      458mV      573.1mV
1.075ns   492.1mV    458.1mV    1.439V
1.244ns   521.7mV    458.2mV    1.805V
1.367ns   1.293V     458.2mV    1.876V
1.523ns   1.685V     458.3mV    1.886V
1.654ns   1.783V     495.7mV    1.888V
1.801ns   1.795V     1.28V      1.888V
2.056ns   1.798V     1.693V     1.889V
10ns      1.8V       1.71V      1.89V
[Falling Waveform]
R_fixture = 50
V_fixture = 0
V_fixture_min = 0
V_fixture_max = 0
| Time   V(typ)   V(min)   V(max)
0s        1.289V     1.228V     1.342V
928ps     1.289V     1.228V     1.334V
1.115ns   1.288V     1.228V     215mV
1.285ns   1.153V     1.228V     13.82mV
1.36ns    576.6mV    1.228V     7.45mV
1.476ns   106.1mV    1.228V     3.97mV
1.684ns   7.496mV    1.182V     1.92mV
1.861ns   2.693mV    188.7mV    1.299mV
1.989ns   1.771mV    17.38mV    1.121mV
10ns      2.765uV    2.863uV    3.998uV
[Falling Waveform]
R_fixture = 50
V_fixture = 1.8
V_fixture_min = 1.71
V_fixture_max = 1.89
| Time   V(typ)   V(min)   V(max)
0s        1.8V       1.71V      1.89V
1.059ns   1.801V     1.71V      1.896V
1.164ns   1.801V     1.711V     1.671V
1.362ns   1.814V     1.711V     735.2mV
1.567ns   1.224V     1.711V     582.4mV
1.73ns    571.8mV    1.726V     570.2mV
1.886ns   509.3mV    1.514V     566.5mV
2.095ns   496.3mV    595.2mV    564.6mV
2.271ns   493.7mV    474.5mV    564.1mV
10ns      491.3mV    457.5mV    563mV
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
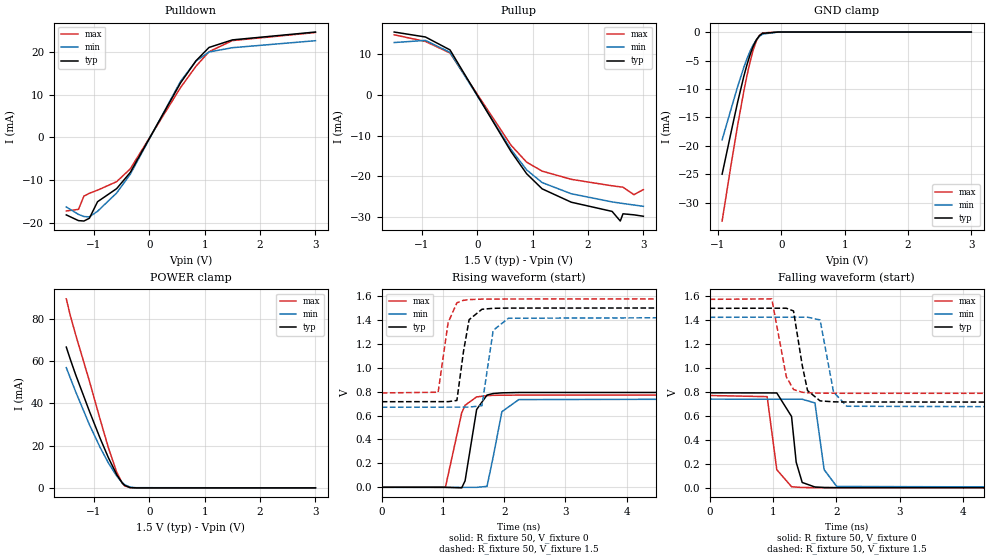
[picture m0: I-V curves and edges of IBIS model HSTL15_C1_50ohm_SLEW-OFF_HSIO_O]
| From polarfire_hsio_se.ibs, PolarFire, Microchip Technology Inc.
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|   Model HSTL15_C1_50ohm_SLEW-OFF_HSIO_O
[Model]   HSTL15_C1_50ohm_SLEW-OFF_HSIO_O
Model_type   Output
Polarity   Non-Inverting
Enable   Active-High
Vmeas =   0.75
Cref =   5p
Rref =   50
Vref =   0.75
|   typ   min   max
C_comp_pullup   1.335e-12   1.335e-12   1.380e-12
C_comp_pulldown  1.335e-12   1.335e-12   1.380e-12
[Temperature Range]  25C   100C   -40C
[Voltage Range]  1.5   1.425   1.575
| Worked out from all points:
|   slope of the pulldown table from 0 to 0.225 V, typ, clamps not added: 42.2 ohm
|   slope of the pullup table from 0 to 0.225 V, typ, clamps not added: 42.2 ohm
|   GND clamp passes 1 mA (typ) near -0.37 V on its own axis
|   POWER clamp passes 1 mA (typ) near -0.43 V on its own axis
|   rising waveform, R_fixture 50, V_fixture 0: 20-80 % time 147ps typ, 154ps min, 183ps max; typ from 0 V to 0.794 V
|   rising waveform, R_fixture 50, V_fixture 1.5: 20-80 % time 120ps typ, 112ps min, 131ps max; typ from 0.715 V to 1.5 V
|   falling waveform, R_fixture 50, V_fixture 0: 20-80 % time 97.4ps typ, 105ps min, 99.6ps max; typ from 0.794 V to 0 V
|   falling waveform, R_fixture 50, V_fixture 1.5: 20-80 % time 133ps typ, 145ps min, 135ps max; typ from 1.5 V to 0.715 V
[GND Clamp]
| Voltage   I(typ)   I(min)   I(max)
-935.2mV  -24.96mA   -18.92mA   -33.17mA
-787.5mV  -17.27mA   -13.27mA   -22.86mA
-689.1mV  -12.26mA   -9.546mA   -16.31mA
-590.6mV  -7.7mA     -6.143mA   -10.29mA
-541.4mV  -5.692mA   -4.645mA   -7.577mA
-492.2mV  -3.93mA    -3.33mA    -5.153mA
-443mV    -2.467mA   -2.229mA   -3.103mA
-393.7mV  -1.355mA   -1.366mA   -1.54mA
-344.5mV  -621.9uA   -750.5uA   -567.2uA
-295.3mV  -232uA     -362.9uA   -147.8uA
-49.22mV  -334.5nA   -1.943uA   -112.6nA
3V        0A         0A         0A
[POWER Clamp]
| Voltage   I(typ)   I(min)   I(max)
-1.5V     66.64mA    56.9mA     89.46mA
-1.427V   60.81mA    51.96mA    81.57mA
-1.329V   53.43mA    45.4mA     72.34mA
-1.083V   36.31mA    29.95mA    50.59mA
-885.9mV  23.26mA    18.98mA    32.15mA
-738.3mV  14.22mA    11.74mA    18.91mA
-590.6mV  6.331mA    5.649mA    7.47mA
-492.2mV  2.418mA    2.54mA     2.302mA
-443mV    1.134mA    1.422mA    896.4uA
-344.5mV  93.53uA    323uA      39.71uA
-246.1mV  3.484uA    76.21uA    1.361uA
3V        0A         0A         0A
[Pullup]
| Voltage   I(typ)   I(min)   I(max)
-1.5V     15.45mA    12.87mA    14.77mA
-935.2mV  14.23mA    13.39mA    13.13mA
-492.2mV  11.06mA    10.47mA    10.3mA
609.4mV   -13.89mA   -13.38mA   -12.35mA
890.6mV   -19.34mA   -18.4mA    -16.5mA
1.172V    -23.07mA   -21.53mA   -18.72mA
1.697V    -26.35mA   -24.27mA   -20.73mA
2.435V    -28.61mA   -26.28mA   -22.32mA
2.583V    -30.97mA   -26.57mA   -22.58mA
2.632V    -29.2mA    -26.67mA   -22.66mA
2.829V    -29.45mA   -27.04mA   -24.5mA
3V        -29.8mA    -27.36mA   -23.25mA
[Pulldown]
| Voltage   I(typ)   I(min)   I(max)
-1.5V     -18.17mA   -16.31mA   -17.24mA
-1.28V    -19.51mA   -18.05mA   -16.87mA
-1.181V   -19.6mA    -18.55mA   -13.76mA
-1.083V   -18.95mA   -18.63mA   -13.11mA
-935.2mV  -15.08mA   -17.32mA   -12.38mA
-590.6mV  -12.02mA   -13.04mA   -10.39mA
-344.5mV  -8.226mA   -8.653mA   -7.397mA
562.5mV   12.72mA    13.07mA    11.63mA
843.8mV   17.94mA    17.89mA    16.66mA
1.078V    21.04mA    19.98mA    20.05mA
1.5V      22.81mA    20.98mA    22.65mA
3V        24.65mA    22.62mA    24.54mA
[Ramp]
dV/dt_r   0.476308/0.146527n  0.444746/0.15399n  0.462895/0.182546n
dV/dt_f   0.470826/0.133009n  0.453282/0.144843n  0.471812/0.134824n
R_load = 50
[Rising Waveform]
R_fixture = 50
V_fixture = 0
V_fixture_min = 0
V_fixture_max = 0
| Time   V(typ)   V(min)   V(max)
0s        1.665uV    1.861uV    2.625uV
1.041ns   -579.8uV   -428.7uV   2.228mV
1.306ns   -4.646mV   -538.3uV   622mV
1.361ns   54.26mV    -561.1uV   685.7mV
1.55ns    650.5mV    -639.2uV   755.4mV
1.719ns   770.8mV    7.595mV    766.2mV
1.816ns   783.7mV    243.7mV    768.8mV
1.962ns   789.5mV    631.9mV    769.8mV
2.238ns   792.4mV    733.1mV    770.4mV
10ns      793.8mV    741.2mV    771.5mV
[Rising Waveform]
R_fixture = 50
V_fixture = 1.5
V_fixture_min = 1.425
V_fixture_max = 1.575
| Time   V(typ)   V(min)   V(max)
0s        715.3mV    669.5mV    788.6mV
921ps     715.9mV    669.9mV    794.6mV
1.084ns   716mV      670mV      1.376V
1.227ns   725.7mV    670.1mV    1.542V
1.335ns   1.135V     670.1mV    1.563V
1.427ns   1.401V     670.1mV    1.569V
1.636ns   1.488V     682mV      1.573V
1.82ns    1.496V     1.312V     1.573V
2.069ns   1.498V     1.413V     1.574V
10ns      1.5V       1.425V     1.575V
[Falling Waveform]
R_fixture = 50
V_fixture = 0
V_fixture_min = 0
V_fixture_max = 0
| Time   V(typ)   V(min)   V(max)
0s        793.9mV    741.3mV    771.5mV
907ps     793.2mV    740.8mV    762.1mV
1.059ns   793mV      740.7mV    152mV
1.292ns   596.3mV    740.6mV    9.43mV
1.365ns   214.4mV    740.5mV    6.523mV
1.46ns    44.93mV    740.5mV    3mV
1.661ns   7.127mV    709.3mV    1.652mV
1.806ns   3.203mV    151.9mV    1.264mV
2.005ns   1.743mV    11.52mV    937.7uV
10ns      2.881uV    5.936uV    2.893uV
[Falling Waveform]
R_fixture = 50
V_fixture = 1.5
V_fixture_min = 1.425
V_fixture_max = 1.575
| Time   V(typ)   V(min)   V(max)
0s        1.5V       1.425V     1.575V
980ps     1.501V     1.426V     1.579V
1.209ns   1.501V     1.426V     928.4mV
1.323ns   1.478V     1.426V     821.7mV
1.46ns    1.025V     1.426V     798.4mV
1.544ns   812.7mV    1.426V     794.5mV
1.742ns   726.7mV    1.403V     791.4mV
1.954ns   718.7mV    801mV      790.6mV
2.162ns   717.3mV    681.8mV    790.1mV
10ns      715.3mV    669.5mV    788.6mV
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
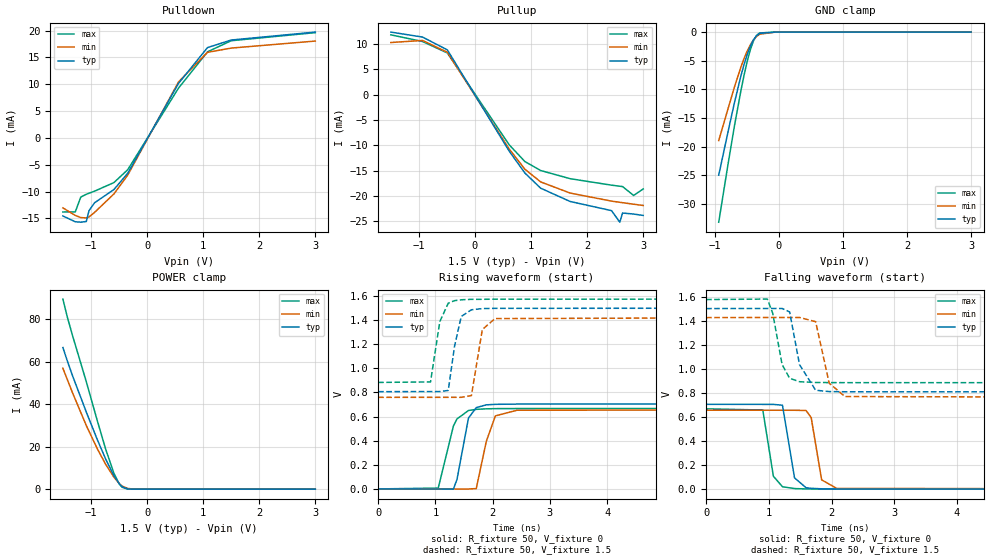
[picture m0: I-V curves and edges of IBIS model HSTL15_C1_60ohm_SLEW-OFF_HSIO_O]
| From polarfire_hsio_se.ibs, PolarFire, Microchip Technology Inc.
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|   Model HSTL15_C1_60ohm_SLEW-OFF_HSIO_O
[Model]   HSTL15_C1_60ohm_SLEW-OFF_HSIO_O
Model_type   Output
Polarity   Non-Inverting
Enable   Active-High
Vmeas =   0.75
Cref =   5p
Rref =   50
Vref =   0.75
|   typ   min   max
C_comp_pullup   1.335e-12   1.335e-12   1.380e-12
C_comp_pulldown  1.335e-12   1.335e-12   1.380e-12
[Temperature Range]  25C   100C   -40C
[Voltage Range]  1.5   1.425   1.575
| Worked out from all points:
|   slope of the pulldown table from 0 to 0.225 V, typ, clamps not added: 52.7 ohm
|   slope of the pullup table from 0 to 0.225 V, typ, clamps not added: 52.8 ohm
|   GND clamp passes 1 mA (typ) near -0.37 V on its own axis
|   POWER clamp passes 1 mA (typ) near -0.43 V on its own axis
|   rising waveform, R_fixture 50, V_fixture 0: 20-80 % time 164ps typ, 170ps min, 200ps max; typ from 0 V to 0.705 V
|   rising waveform, R_fixture 50, V_fixture 1.5: 20-80 % time 125ps typ, 123ps min, 135ps max; typ from 0.807 V to 1.5 V
|   falling waveform, R_fixture 50, V_fixture 0: 20-80 % time 107ps typ, 110ps min, 106ps max; typ from 0.705 V to 0 V
|   falling waveform, R_fixture 50, V_fixture 1.5: 20-80 % time 151ps typ, 160ps min, 151ps max; typ from 1.5 V to 0.807 V
[GND Clamp]
| Voltage   I(typ)   I(min)   I(max)
-935.2mV  -24.96mA   -18.92mA   -33.17mA
-787.5mV  -17.27mA   -13.27mA   -22.86mA
-689.1mV  -12.26mA   -9.546mA   -16.31mA
-590.6mV  -7.7mA     -6.143mA   -10.29mA
-541.4mV  -5.692mA   -4.645mA   -7.577mA
-492.2mV  -3.93mA    -3.33mA    -5.153mA
-443mV    -2.467mA   -2.229mA   -3.103mA
-393.7mV  -1.355mA   -1.366mA   -1.54mA
-344.5mV  -621.9uA   -750.5uA   -567.2uA
-295.3mV  -232uA     -362.9uA   -147.8uA
-49.22mV  -334.5nA   -1.943uA   -112.6nA
3V        0A         0A         0A
[POWER Clamp]
| Voltage   I(typ)   I(min)   I(max)
-1.5V     66.64mA    56.9mA     89.46mA
-1.427V   60.81mA    51.96mA    81.57mA
-1.329V   53.43mA    45.4mA     72.34mA
-1.083V   36.31mA    29.95mA    50.59mA
-885.9mV  23.26mA    18.98mA    32.15mA
-738.3mV  14.22mA    11.74mA    18.91mA
-590.6mV  6.331mA    5.649mA    7.47mA
-492.2mV  2.418mA    2.54mA     2.302mA
-443mV    1.134mA    1.422mA    896.4uA
-344.5mV  93.53uA    323uA      39.71uA
-246.1mV  3.484uA    76.21uA    1.361uA
3V        0A         0A         0A
[Pullup]
| Voltage   I(typ)   I(min)   I(max)
-1.5V     12.36mA    10.3mA     11.82mA
-935.2mV  11.38mA    10.71mA    10.5mA
-492.2mV  8.849mA    8.377mA    8.238mA
609.4mV   -11.12mA   -10.7mA    -9.878mA
890.6mV   -15.47mA   -14.72mA   -13.2mA
1.172V    -18.46mA   -17.22mA   -14.97mA
1.697V    -21.08mA   -19.42mA   -16.58mA
2.435V    -22.89mA   -21.01mA   -17.86mA
2.583V    -25.17mA   -21.24mA   -18.07mA
2.632V    -23.36mA   -21.32mA   -18.14mA
2.829V    -23.56mA   -21.62mA   -19.89mA
3V        -23.84mA   -21.87mA   -18.61mA
[Pulldown]
| Voltage   I(typ)   I(min)   I(max)
-1.5V     -14.53mA   -13.03mA   -13.79mA
-1.28V    -15.61mA   -14.42mA   -13.78mA
-1.181V   -15.69mA   -14.83mA   -11.01mA
-1.083V   -15.56mA   -14.9mA    -10.49mA
-1.034V   -13.54mA   -14.71mA   -10.29mA
-935.2mV  -12.07mA   -13.86mA   -9.906mA
-590.6mV  -9.614mA   -10.43mA   -8.312mA
-344.5mV  -6.581mA   -6.924mA   -5.919mA
562.5mV   10.18mA    10.45mA    9.302mA
1.078V    16.83mA    15.95mA    16.04mA
1.5V      18.24mA    16.74mA    18.11mA
3V        19.72mA    18.05mA    19.62mA
[Ramp]
dV/dt_r   0.422899/0.163829n  0.393682/0.170047n  0.400437/0.200043n
dV/dt_f   0.41579/0.151302n  0.399215/0.160006n  0.414956/0.150809n
R_load = 50
[Rising Waveform]
R_fixture = 50
V_fixture = 0
V_fixture_min = 0
V_fixture_max = 0
| Time   V(typ)   V(min)   V(max)
0s        1.706uV    1.956uV    2.709uV
1.049ns   -645.6uV   -505.6uV   6.83mV
1.313ns   -2.092mV   -633.4uV   520mV
1.376ns   77.69mV    -663.9uV   580.3mV
1.577ns   587.7mV    -761.1uV   650.5mV
1.713ns   674.5mV    2.936mV    660mV
1.889ns   697.4mV    395.3mV    664.4mV
2.048ns   701.7mV    606mV      666mV
2.425ns   703.7mV    652.8mV    666.6mV
10ns      704.8mV    656.1mV    667.4mV
[Rising Waveform]
R_fixture = 50
V_fixture = 1.5
V_fixture_min = 1.425
V_fixture_max = 1.575
| Time   V(typ)   V(min)   V(max)
0s        807mV      759.6mV    883.4mV
914ps     807.6mV    759.8mV    887.6mV
1.077ns   807.7mV    759.9mV    1.389V
1.224ns   817mV      759.9mV    1.541V
1.334ns   1.185V     759.9mV    1.562V
1.451ns   1.431V     759.9mV    1.569V
1.628ns   1.486V     774mV      1.573V
1.819ns   1.496V     1.322V     1.573V
2.039ns   1.498V     1.413V     1.574V
10ns      1.5V       1.425V     1.575V
[Falling Waveform]
R_fixture = 50
V_fixture = 0
V_fixture_min = 0
V_fixture_max = 0
| Time   V(typ)   V(min)   V(max)
0s        704.8mV    656.1mV    667.4mV
904ps     704.2mV    655.6mV    657.4mV
1.073ns   704.1mV    655.6mV    107.5mV
1.218ns   697.3mV    655.5mV    20.16mV
1.41ns    94mV       655.4mV    4.944mV
1.594ns   11.97mV    653.4mV    2.031mV
1.676ns   6.988mV    594.5mV    1.595mV
1.842ns   3.034mV    77.53mV    1.195mV
2.081ns   1.446mV    6.463mV    777.8uV
10ns      2.863uV    4.104uV    3.701uV
[Falling Waveform]
R_fixture = 50
V_fixture = 1.5
V_fixture_min = 1.425
V_fixture_max = 1.575
| Time   V(typ)   V(min)   V(max)
0s        1.5V       1.425V     1.575V
977ps     1.501V     1.426V     1.579V
1.062ns   1.501V     1.426V     1.462V
1.212ns   1.501V     1.426V     1.035V
1.332ns   1.472V     1.426V     921.1mV
1.49ns    1.034V     1.426V     892.4mV
1.747ns   821.8mV    1.391V     886.2mV
1.963ns   810.6mV    880.6mV    885.2mV
2.214ns   809mV      769.2mV    884.8mV
10ns      807mV      759.6mV    883.4mV
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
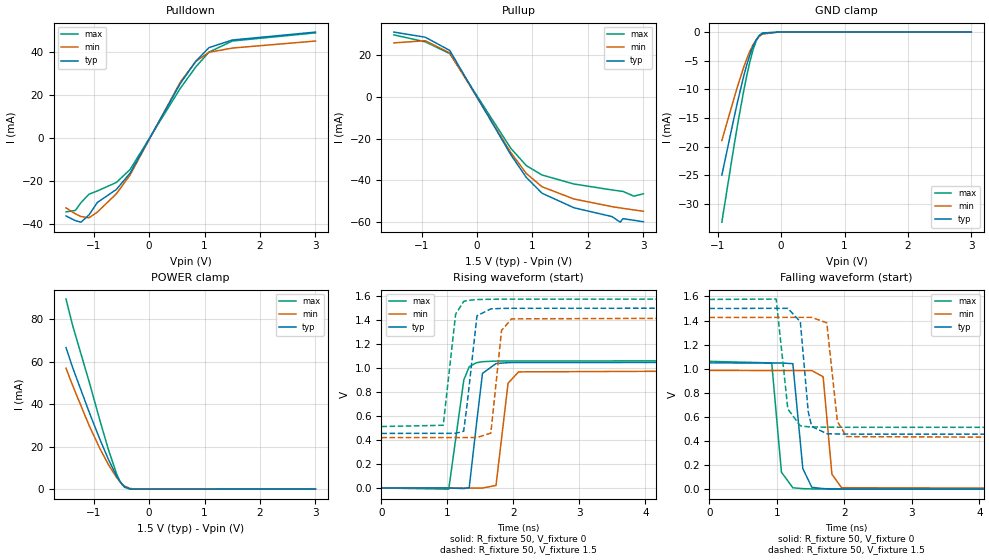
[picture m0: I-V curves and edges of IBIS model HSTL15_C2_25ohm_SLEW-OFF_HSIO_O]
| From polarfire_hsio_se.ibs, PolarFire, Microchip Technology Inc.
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|   Model HSTL15_C2_25ohm_SLEW-OFF_HSIO_O
[Model]   HSTL15_C2_25ohm_SLEW-OFF_HSIO_O
Model_type   Output
Polarity   Non-Inverting
Enable   Active-High
Vmeas =   0.75
Cref =   5p
Rref =   50
Vref =   0.75
|   typ   min   max
C_comp_pullup   1.335e-12   1.335e-12   1.380e-12
C_comp_pulldown  1.335e-12   1.335e-12   1.380e-12
[Temperature Range]  25C   100C   -40C
[Voltage Range]  1.5   1.425   1.575
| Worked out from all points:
|   slope of the pulldown table from 0 to 0.225 V, typ, clamps not added: 21.1 ohm
|   slope of the pullup table from 0 to 0.225 V, typ, clamps not added: 21.1 ohm
|   GND clamp passes 1 mA (typ) near -0.37 V on its own axis
|   POWER clamp passes 1 mA (typ) near -0.43 V on its own axis
|   rising waveform, R_fixture 50, V_fixture 0: 20-80 % time 104ps typ, 106ps min, 128ps max; typ from 0 V to 1.05 V
|   rising waveform, R_fixture 50, V_fixture 1.5: 20-80 % time 102ps typ, 97.5ps min, 113ps max; typ from 0.455 V to 1.5 V
|   falling waveform, R_fixture 50, V_fixture 0: 20-80 % time 79.1ps typ, 79.6ps min, 83.8ps max; typ from 1.05 V to 0 V
|   falling waveform, R_fixture 50, V_fixture 1.5: 20-80 % time 94.7ps typ, 99.7ps min, 96.3ps max; typ from 1.5 V to 0.455 V
[GND Clamp]
| Voltage   I(typ)   I(min)   I(max)
-935.2mV  -24.96mA   -18.92mA   -33.17mA
-738.3mV  -14.72mA   -11.38mA   -19.54mA
-689.1mV  -12.26mA   -9.546mA   -16.31mA
-590.6mV  -7.7mA     -6.143mA   -10.29mA
-541.4mV  -5.692mA   -4.645mA   -7.577mA
-492.2mV  -3.93mA    -3.33mA    -5.153mA
-443mV    -2.467mA   -2.229mA   -3.103mA
-393.7mV  -1.355mA   -1.366mA   -1.54mA
-344.5mV  -621.9uA   -750.5uA   -567.2uA
-295.3mV  -232uA     -362.9uA   -147.8uA
-49.22mV  -334.5nA   -1.943uA   -112.6nA
3V        0A         0A         0A
[POWER Clamp]
| Voltage   I(typ)   I(min)   I(max)
-1.5V     66.64mA    56.92mA    89.46mA
-1.378V   57.06mA    48.66mA    76.82mA
-1.083V   36.31mA    29.95mA    50.59mA
-885.9mV  23.26mA    18.98mA    32.15mA
-738.3mV  14.22mA    11.74mA    18.91mA
-590.6mV  6.331mA    5.649mA    7.47mA
-541.4mV  4.184mA    3.97mA     4.53mA
-492.2mV  2.418mA    2.54mA     2.302mA
-443mV    1.134mA    1.422mA    896.4uA
-344.5mV  93.53uA    323uA      39.71uA
-246.1mV  3.484uA    76.21uA    1.361uA
3V        0A         0A         0A
[Pullup]
| Voltage   I(typ)   I(min)   I(max)
-1.5V     30.9mA     25.73mA    29.55mA
-935.2mV  28.46mA    26.78mA    26.25mA
-492.2mV  22.12mA    20.94mA    20.59mA
609.4mV   -27.78mA   -26.74mA   -24.69mA
890.6mV   -38.67mA   -36.78mA   -32.99mA
1.172V    -46.14mA   -43.05mA   -37.43mA
1.746V    -53.09mA   -48.9mA    -41.73mA
2.435V    -57.32mA   -52.58mA   -44.59mA
2.583V    -60mA      -53.18mA   -45.11mA
2.632V    -58.31mA   -53.38mA   -45.28mA
2.829V    -59.08mA   -54.14mA   -47.55mA
3V        -59.79mA   -54.77mA   -46.44mA
[Pulldown]
| Voltage   I(typ)   I(min)   I(max)
-1.5V     -36.38mA   -32.63mA   -34.49mA
-1.329V   -38.61mA   -35.43mA   -33.78mA
-1.23V    -39.31mA   -36.67mA   -30.18mA
-1.083V   -35.84mA   -37.25mA   -26.21mA
-935.2mV  -30.13mA   -34.61mA   -24.74mA
-590.6mV  -24.01mA   -26.05mA   -20.75mA
-344.5mV  -16.42mA   -17.28mA   -14.75mA
562.5mV   25.41mA    26.09mA    23.18mA
843.8mV   35.86mA    35.75mA    33.22mA
1.078V    42.11mA    39.95mA    40.01mA
1.5V      45.7mA     41.95mA    45.24mA
3V        49.4mA     45.22mA    49.03mA
[Ramp]
dV/dt_r   0.628807/0.104295n  0.591222/0.106072n  0.636412/0.12806n
dV/dt_f   0.627018/94.7273p  0.602955/99.7211p  0.637517/96.2703p
R_load = 50
[Rising Waveform]
R_fixture = 50
V_fixture = 0
V_fixture_min = 0
V_fixture_max = 0
| Time   V(typ)   V(min)   V(max)
0s        1.548uV    1.592uV    2.377uV
1.02ns    -726.5uV   -357.8uV   -9.828mV
1.248ns   -4.862mV   -438.1uV   900.4mV
1.33ns    2.681mV    -467uV     1.011V
1.439ns   528.8mV    -505.4uV   1.044V
1.531ns   955.6mV    -537.8uV   1.053V
1.736ns   1.037V     20.87mV    1.058V
1.919ns   1.045V     873.6mV    1.059V
2.079ns   1.046V     968.2mV    1.059V
10ns      1.048V     985.4mV    1.061V
[Rising Waveform]
R_fixture = 50
V_fixture = 1.5
V_fixture_min = 1.425
V_fixture_max = 1.575
| Time   V(typ)   V(min)   V(max)
0s        455mV      420.1mV    512.5mV
936ps     455.5mV    420.4mV    522.7mV
1.124ns   455.6mV    420.5mV    1.449V
1.246ns   473.4mV    420.6mV    1.555V
1.297ns   690.9mV    420.6mV    1.563V
1.448ns   1.436V     420.7mV    1.571V
1.658ns   1.493V     457.6mV    1.573V
1.82ns    1.497V     1.313V     1.574V
1.972ns   1.498V     1.41V      1.574V
10ns      1.5V       1.425V     1.575V
[Falling Waveform]
R_fixture = 50
V_fixture = 0
V_fixture_min = 0
V_fixture_max = 0
| Time   V(typ)   V(min)   V(max)
0s        1.048V     985.4mV    1.061V
924ps     1.047V     984.9mV    1.048V
1.068ns   1.047V     984.8mV    141.1mV
1.237ns   1.042V     984.8mV    11.54mV
1.385ns   170.6mV    984.7mV    4.363mV
1.518ns   15.81mV    984.6mV    2.202mV
1.686ns   4.665mV    933.2mV    1.485mV
1.816ns   2.244mV    124.1mV    1.252mV
1.959ns   1.411mV    11.96mV    996.3uV
10ns      2.281uV    2.798uV    2.944uV
[Falling Waveform]
R_fixture = 50
V_fixture = 1.5
V_fixture_min = 1.425
V_fixture_max = 1.575
| Time   V(typ)   V(min)   V(max)
0s        1.5V       1.425V     1.575V
990ps     1.501V     1.426V     1.578V
1.163ns   1.501V     1.426V     665.5mV
1.348ns   1.39V      1.426V     525.2mV
1.465ns   643.8mV    1.426V     517.8mV
1.516ns   520.5mV    1.426V     516.7mV
1.74ns    461mV      1.381V     514.6mV
1.897ns   457.8mV    561.7mV    513.9mV
2.033ns   457mV      436.1mV    513.7mV
10ns      455mV      420.1mV    512.5mV
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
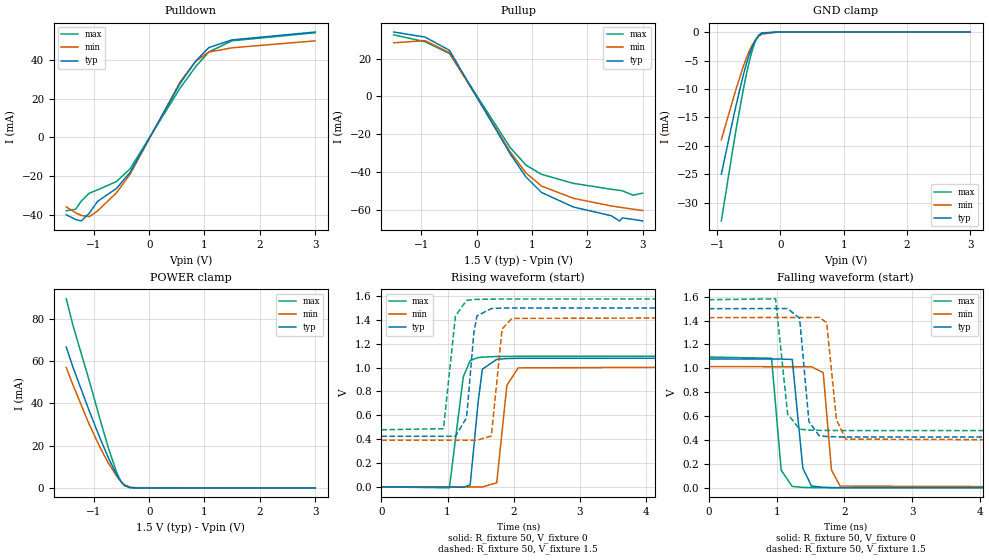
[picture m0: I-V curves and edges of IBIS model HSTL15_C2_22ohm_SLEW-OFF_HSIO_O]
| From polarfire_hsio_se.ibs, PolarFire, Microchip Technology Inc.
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|   Model HSTL15_C2_22ohm_SLEW-OFF_HSIO_O
[Model]   HSTL15_C2_22ohm_SLEW-OFF_HSIO_O
Model_type   Output
Polarity   Non-Inverting
Enable   Active-High
Vmeas =   0.75
Cref =   5p
Rref =   50
Vref =   0.75
|   typ   min   max
C_comp_pullup   1.335e-12   1.335e-12   1.380e-12
C_comp_pulldown  1.335e-12   1.335e-12   1.380e-12
[Temperature Range]  25C   100C   -40C
[Voltage Range]  1.5   1.425   1.575
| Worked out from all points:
|   slope of the pulldown table from 0 to 0.225 V, typ, clamps not added: 19.2 ohm
|   slope of the pullup table from 0 to 0.225 V, typ, clamps not added: 19.2 ohm
|   GND clamp passes 1 mA (typ) near -0.37 V on its own axis
|   POWER clamp passes 1 mA (typ) near -0.43 V on its own axis
|   rising waveform, R_fixture 50, V_fixture 0: 20-80 % time 99.5ps typ, 104ps min, 121ps max; typ from 0 V to 1.08 V
|   rising waveform, R_fixture 50, V_fixture 1.5: 20-80 % time 99.7ps typ, 93.4ps min, 110ps max; typ from 0.424 V to 1.5 V
|   falling waveform, R_fixture 50, V_fixture 0: 20-80 % time 76.7ps typ, 78.8ps min, 81.4ps max; typ from 1.08 V to 0 V
|   falling waveform, R_fixture 50, V_fixture 1.5: 20-80 % time 88.6ps typ, 96ps min, 90.2ps max; typ from 1.5 V to 0.424 V
[GND Clamp]
| Voltage   I(typ)   I(min)   I(max)
-935.2mV  -24.96mA   -18.92mA   -33.17mA
-738.3mV  -14.72mA   -11.38mA   -19.54mA
-689.1mV  -12.26mA   -9.546mA   -16.31mA
-590.6mV  -7.7mA     -6.143mA   -10.29mA
-541.4mV  -5.692mA   -4.645mA   -7.577mA
-492.2mV  -3.93mA    -3.33mA    -5.153mA
-443mV    -2.467mA   -2.229mA   -3.103mA
-393.7mV  -1.355mA   -1.366mA   -1.54mA
-344.5mV  -621.9uA   -750.5uA   -567.2uA
-295.3mV  -232uA     -362.9uA   -147.8uA
-49.22mV  -334.5nA   -1.943uA   -113nA
3V        0A         0A         0A
[POWER Clamp]
| Voltage   I(typ)   I(min)   I(max)
-1.5V     66.64mA    56.92mA    89.46mA
-1.378V   57.06mA    48.66mA    76.82mA
-1.083V   36.31mA    29.95mA    50.59mA
-885.9mV  23.26mA    18.98mA    32.15mA
-738.3mV  14.22mA    11.74mA    18.91mA
-590.6mV  6.331mA    5.649mA    7.47mA
-541.4mV  4.184mA    3.97mA     4.53mA
-492.2mV  2.418mA    2.54mA     2.302mA
-443mV    1.134mA    1.422mA    896.4uA
-344.5mV  93.53uA    323uA      39.71uA
-246.1mV  3.484uA    76.21uA    1.36uA
3V        0A         0A         0A
[Pullup]
| Voltage   I(typ)   I(min)   I(max)
-1.5V     33.99mA    28.3mA     32.51mA
-935.2mV  31.31mA    29.46mA    28.87mA
-492.2mV  24.33mA    23.03mA    22.64mA
609.4mV   -30.56mA   -29.42mA   -27.15mA
890.6mV   -42.54mA   -40.46mA   -36.29mA
1.172V    -50.75mA   -47.35mA   -41.17mA
1.746V    -58.4mA    -53.79mA   -45.9mA
2.435V    -63.04mA   -57.85mA   -49.06mA
2.583V    -65.81mA   -58.51mA   -49.63mA
2.632V    -64.15mA   -58.72mA   -49.82mA
2.829V    -64.97mA   -59.56mA   -52.16mA
3V        -65.74mA   -60.26mA   -51.1mA
[Pulldown]
| Voltage   I(typ)   I(min)   I(max)
-1.5V     -40.02mA   -35.91mA   -37.93mA
-1.329V   -42.47mA   -38.99mA   -37.13mA
-1.23V    -43.24mA   -40.35mA   -33.02mA
-1.083V   -39.22mA   -40.97mA   -28.82mA
-935.2mV  -33.14mA   -38.06mA   -27.21mA
-590.6mV  -26.4mA    -28.65mA   -22.83mA
-344.5mV  -18.06mA   -19mA      -16.23mA
562.5mV   27.94mA    28.7mA     25.51mA
843.8mV   39.43mA    39.33mA    36.56mA
1.078V    46.3mA     43.96mA    44.04mA
1.5V      50.26mA    46.17mA    49.8mA
3V        54.32mA    49.77mA    53.96mA
[Ramp]
dV/dt_r   0.647117/99.5141p  0.608901/0.10372n  0.656901/0.121114n
dV/dt_f   0.645607/88.6439p  0.620468/96.0118p  0.657854/90.2201p
R_load = 50
[Rising Waveform]
R_fixture = 50
V_fixture = 0
V_fixture_min = 0
V_fixture_max = 0
| Time   V(typ)   V(min)   V(max)
0s        1.534uV    1.559uV    2.345uV
1.027ns   -520.1uV   -386.8uV   -8.012mV
1.237ns   -3.605mV   -466.2uV   920.9mV
1.341ns   16.71mV    -505.5uV   1.058V
1.462ns   714.6mV    -551.2uV   1.083V
1.525ns   986.5mV    -575.1uV   1.087V
1.742ns   1.068V     34.57mV    1.092V
1.895ns   1.075V     850.3mV    1.093V
2.066ns   1.077V     996.9mV    1.094V
10ns      1.079V     1.015V     1.095V
[Rising Waveform]
R_fixture = 50
V_fixture = 1.5
V_fixture_min = 1.425
V_fixture_max = 1.575
| Time   V(typ)   V(min)   V(max)
0s        424mV      390.9mV    478.6mV
938ps     424.5mV    391.1mV    487.4mV
1.119ns   424.6mV    391.2mV    1.432V
1.287ns   580.1mV    391.2mV    1.563V
1.398ns   1.299V     391.3mV    1.57V
1.444ns   1.433V     391.3mV    1.571V
1.661ns   1.494V     426.3mV    1.573V
1.823ns   1.498V     1.323V     1.574V
1.972ns   1.498V     1.411V     1.574V
10ns      1.5V       1.425V     1.575V
[Falling Waveform]
R_fixture = 50
V_fixture = 0
V_fixture_min = 0
V_fixture_max = 0
| Time   V(typ)   V(min)   V(max)
0s        1.079V     1.015V     1.095V
925ps     1.078V     1.014V     1.085V
1.067ns   1.078V     1.014V     147.8mV
1.23ns    1.075V     1.014V     11.76mV
1.386ns   165.9mV    1.014V     3.872mV
1.513ns   15.66mV    1.014V     2.226mV
1.687ns   4.343mV    965mV      1.482mV
1.809ns   2.321mV    149.5mV    1.238mV
1.936ns   1.465mV    14.41mV    984uV
10ns      2.269uV    3.072uV    2.861uV
[Falling Waveform]
R_fixture = 50
V_fixture = 1.5
V_fixture_min = 1.425
V_fixture_max = 1.575
| Time   V(typ)   V(min)   V(max)
0s        1.5V       1.425V     1.575V
984ps     1.501V     1.426V     1.582V
1.162ns   1.501V     1.426V     618.5mV
1.339ns   1.419V     1.426V     491.1mV
1.476ns   555.4mV    1.426V     483.3mV
1.626ns   437.6mV    1.427V     481.3mV
1.738ns   429.5mV    1.384V     480.5mV
1.882ns   426.8mV    570.1mV    480mV
2.019ns   426mV      407.9mV    479.6mV
10ns      424mV      390.9mV    478.6mV
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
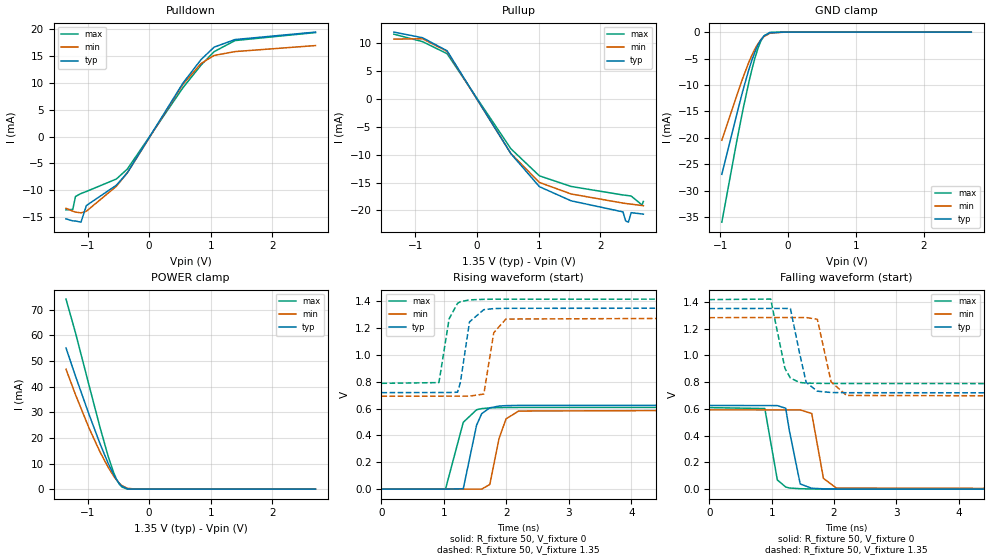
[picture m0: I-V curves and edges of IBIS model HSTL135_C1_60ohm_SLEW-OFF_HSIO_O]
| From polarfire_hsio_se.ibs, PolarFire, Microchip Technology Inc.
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|   Model HSTL135_C1_60ohm_SLEW-OFF_HSIO_O
[Model]   HSTL135_C1_60ohm_SLEW-OFF_HSIO_O
Model_type   Output
Polarity   Non-Inverting
Enable   Active-High
Vmeas =   0.675
Cref =   5p
Rref =   50
Vref =   0.675
|   typ   min   max
C_comp_pullup   1.335e-12   1.335e-12   1.380e-12
C_comp_pulldown  1.335e-12   1.335e-12   1.380e-12
[Temperature Range]  25C   100C   -40C
[Voltage Range]  1.35   1.2825   1.4175
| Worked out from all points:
|   slope of the pulldown table from 0 to 0.203 V, typ, clamps not added: 52.6 ohm
|   slope of the pullup table from 0 to 0.203 V, typ, clamps not added: 53.7 ohm
|   GND clamp passes 1 mA (typ) near -0.37 V on its own axis
|   POWER clamp passes 1 mA (typ) near -0.43 V on its own axis
|   rising waveform, R_fixture 50, V_fixture 0: 20-80 % time 162ps typ, 171ps min, 192ps max; typ from 0 V to 0.625 V
|   rising waveform, R_fixture 50, V_fixture 1.35: 20-80 % time 115ps typ, 113ps min, 127ps max; typ from 0.719 V to 1.35 V
|   falling waveform, R_fixture 50, V_fixture 0: 20-80 % time 111ps typ, 118ps min, 109ps max; typ from 0.625 V to 0 V
|   falling waveform, R_fixture 50, V_fixture 1.35: 20-80 % time 141ps typ, 151ps min, 140ps max; typ from 1.35 V to 0.719 V
[GND Clamp]
| Voltage   I(typ)   I(min)   I(max)
-974.5mV  -26.9mA    -20.45mA   -35.95mA
-753mV    -15.48mA   -11.94mA   -20.52mA
-664.5mV  -11.06mA   -8.652mA   -14.74mA
-575.9mV  -7.072mA   -5.674mA   -9.445mA
-531.6mV  -5.316mA   -4.365mA   -7.064mA
-487.3mV  -3.767mA   -3.209mA   -4.927mA
-443mV    -2.466mA   -2.228mA   -3.102mA
-398.7mV  -1.449mA   -1.441mA   -1.67mA
-354.4mV  -738.4uA   -854uA     -712.2uA
-265.8mV  -117.5uA   -220.3uA   -58.64uA
-44.3mV   -274.4nA   -1.655uA   -83.21nA
2.7V      0A         0A         0A
[POWER Clamp]
| Voltage   I(typ)   I(min)   I(max)
-1.35V    55.07mA    46.77mA    74.1mA
-1.196V   44.05mA    36.84mA    60.94mA
-974.5mV  29.03mA    23.74mA    40.36mA
-797.3mV  17.68mA    14.49mA    24.04mA
-664.5mV  10.01mA    8.483mA    12.73mA
-575.9mV  5.63mA     5.093mA    6.421mA
-531.6mV  3.786mA    3.641mA    3.935mA
-487.3mV  2.262mA    2.398mA    2.056mA
-443mV    1.133mA    1.41mA     851.4uA
-354.4mV  127.5uA    344.8uA    50.77uA
-221.5mV  1.715uA    33.09uA    747.7nA
2.7V      0A         0A         0A
[Pullup]
| Voltage   I(typ)   I(min)   I(max)
-1.35V    12.03mA    10.77mA    11.65mA
-885.9mV  11.02mA    10.83mA    10.32mA
-487.3mV  8.673mA    8.567mA    8.153mA
548.4mV   -9.801mA   -9.772mA   -8.921mA
1.012V    -15.74mA   -14.98mA   -13.79mA
1.527V    -18.28mA   -17.05mA   -15.7mA
2.369V    -20.27mA   -18.69mA   -17.23mA
2.413V    -21.9mA    -18.76mA   -17.29mA
2.457V    -22.12mA   -18.82mA   -17.35mA
2.502V    -20.41mA   -18.88mA   -17.42mA
2.679V    -20.64mA   -19.13mA   -19.03mA
2.7V      -20.67mA   -19.16mA   -18.4mA
[Pulldown]
| Voltage   I(typ)   I(min)   I(max)
-1.35V    -15.33mA   -13.35mA   -13.65mA
-1.24V    -15.71mA   -13.9mA    -13.57mA
-1.196V   -15.72mA   -14.07mA   -11.17mA
-1.107V   -15.95mA   -14.21mA   -10.61mA
-1.019V   -12.85mA   -13.9mA    -10.23mA
-531.6mV  -9.056mA   -9.26mA    -7.906mA
-354.4mV  -6.744mA   -6.752mA   -6.062mA
548.4mV   9.945mA    9.727mA    9.086mA
843.8mV   14.35mA    13.61mA    13.32mA
1.055V    16.65mA    15.1mA     15.81mA
1.394V    18.06mA    15.82mA    17.87mA
2.7V      19.45mA    16.94mA    19.36mA
[Ramp]
dV/dt_r   0.375216/0.161936n  0.355772/0.171159n  0.365785/0.192264n
dV/dt_f   0.378451/0.141165n  0.354075/0.150814n  0.377392/0.139959n
R_load = 50
[Rising Waveform]
R_fixture = 50
V_fixture = 0
V_fixture_min = 0
V_fixture_max = 0
| Time   V(typ)   V(min)   V(max)
0s        1.395uV    1.675uV    2.154uV
1.025ns   -816.7uV   -466.7uV   -343.3uV
1.309ns   2.219mV    -596.4uV   497.7mV
1.522ns   476.2mV    -693.7uV   591.4mV
1.604ns   562.1mV    -731.2uV   600mV
1.734ns   605.8mV    34.49mV    605.3mV
1.882ns   619.2mV    378.2mV    607.5mV
1.994ns   622.2mV    523.6mV    608.1mV
2.195ns   624mV      581.9mV    608.7mV
10ns      625.4mV    593mV      609.6mV
[Rising Waveform]
R_fixture = 50
V_fixture = 1.35
V_fixture_min = 1.2825
V_fixture_max = 1.4175
| Time   V(typ)   V(min)   V(max)
0s        719.2mV    692.3mV    788.5mV
920ps     719.9mV    692.7mV    794mV
1.083ns   720mV      692.8mV    1.27V
1.217ns   722.3mV    692.8mV    1.385V
1.263ns   794.3mV    692.9mV    1.397V
1.409ns   1.247V     692.9mV    1.411V
1.638ns   1.338V     708.7mV    1.415V
1.797ns   1.346V     1.166V     1.416V
1.991ns   1.348V     1.268V     1.416V
10ns      1.35V      1.282V     1.417V
[Falling Waveform]
R_fixture = 50
V_fixture = 0
V_fixture_min = 0
V_fixture_max = 0
| Time   V(typ)   V(min)   V(max)
0s        625.4mV    592.9mV    609.6mV
890ps     624.9mV    592.5mV    602.7mV
1.091ns   624.8mV    592.5mV    68.96mV
1.225ns   604.9mV    592.4mV    16.24mV
1.286ns   433.6mV    592.4mV    8.692mV
1.458ns   38.99mV    592.3mV    3.405mV
1.643ns   6.902mV    565.8mV    1.604mV
1.831ns   2.605mV    80.51mV    1.018mV
2.037ns   1.491mV    8.669mV    758.2uV
10ns      2.484uV    3.404uV    3.069uV
[Falling Waveform]
R_fixture = 50
V_fixture = 1.35
V_fixture_min = 1.2825
V_fixture_max = 1.4175
| Time   V(typ)   V(min)   V(max)
0s        1.35V      1.282V     1.417V
984ps     1.351V     1.283V     1.421V
1.213ns   1.351V     1.283V     902.8mV
1.301ns   1.35V      1.283V     830.7mV
1.446ns   1.021V     1.283V     797.7mV
1.554ns   797.6mV    1.283V     793.2mV
1.733ns   732.5mV    1.27V      790.9mV
1.954ns   722.4mV    801.7mV    790.2mV
2.202ns   721mV      700.5mV    789.6mV
10ns      719.2mV    692.3mV    788.5mV
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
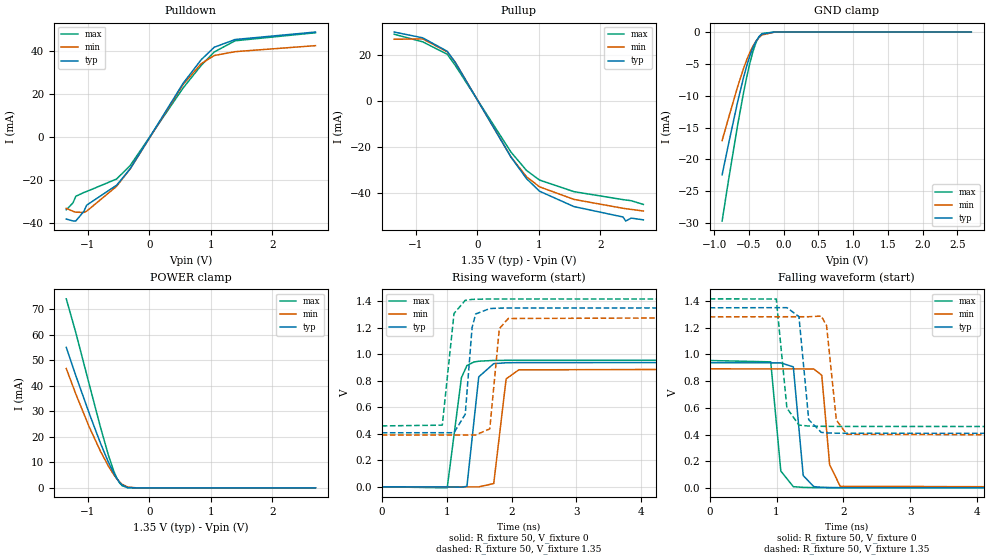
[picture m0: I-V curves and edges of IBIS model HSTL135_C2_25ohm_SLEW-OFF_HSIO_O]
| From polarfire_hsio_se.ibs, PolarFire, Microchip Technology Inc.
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|   Model HSTL135_C2_25ohm_SLEW-OFF_HSIO_O
[Model]   HSTL135_C2_25ohm_SLEW-OFF_HSIO_O
Model_type   Output
Polarity   Non-Inverting
Enable   Active-High
Vmeas =   0.675
Cref =   5p
Rref =   50
Vref =   0.675
|   typ   min   max
C_comp_pullup   1.335e-12   1.335e-12   1.380e-12
C_comp_pulldown  1.335e-12   1.335e-12   1.380e-12
[Temperature Range]  25C   100C   -40C
[Voltage Range]  1.35   1.2825   1.4175
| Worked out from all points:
|   slope of the pulldown table from 0 to 0.203 V, typ, clamps not added: 21.1 ohm
|   slope of the pullup table from 0 to 0.203 V, typ, clamps not added: 21.5 ohm
|   GND clamp passes 1 mA (typ) near -0.37 V on its own axis
|   POWER clamp passes 1 mA (typ) near -0.43 V on its own axis
|   rising waveform, R_fixture 50, V_fixture 0: 20-80 % time 101ps typ, 107ps min, 121ps max; typ from 0 V to 0.938 V
|   rising waveform, R_fixture 50, V_fixture 1.35: 20-80 % time 88.9ps typ, 88.1ps min, 101ps max; typ from 0.407 V to 1.35 V
|   falling waveform, R_fixture 50, V_fixture 0: 20-80 % time 82.7ps typ, 83.9ps min, 86.8ps max; typ from 0.938 V to 0 V
|   falling waveform, R_fixture 50, V_fixture 1.35: 20-80 % time 90.5ps typ, 96.7ps min, 91.1ps max; typ from 1.35 V to 0.407 V
[GND Clamp]
| Voltage   I(typ)   I(min)   I(max)
-885.9mV  -22.43mA   -17.05mA   -29.69mA
-797.3mV  -17.78mA   -13.65mA   -23.53mA
-664.5mV  -11.06mA   -8.652mA   -14.74mA
-575.9mV  -7.072mA   -5.674mA   -9.445mA
-531.6mV  -5.316mA   -4.365mA   -7.064mA
-487.3mV  -3.767mA   -3.209mA   -4.927mA
-443mV    -2.466mA   -2.228mA   -3.102mA
-398.7mV  -1.449mA   -1.441mA   -1.67mA
-354.4mV  -738.4uA   -854uA     -712.2uA
-310.1mV  -318.4uA   -457.5uA   -228.1uA
-132.9mV  -3.522uA   -14.87uA   -692.4nA
2.7V      0A         0A         0A
[POWER Clamp]
| Voltage   I(typ)   I(min)   I(max)
-1.35V    55.07mA    46.77mA    74.1mA
-1.196V   44.05mA    36.84mA    60.94mA
-974.5mV  29.03mA    23.74mA    40.36mA
-797.3mV  17.68mA    14.49mA    24.04mA
-664.5mV  10.01mA    8.483mA    12.73mA
-575.9mV  5.63mA     5.093mA    6.421mA
-531.6mV  3.786mA    3.641mA    3.935mA
-487.3mV  2.262mA    2.398mA    2.056mA
-443mV    1.133mA    1.41mA     851.4uA
-354.4mV  127.5uA    344.8uA    50.77uA
-221.5mV  1.715uA    33.09uA    747.7nA
2.7V      0A         0A         0A
[Pullup]
| Voltage   I(typ)   I(min)   I(max)
-1.35V    30.08mA    26.93mA    29.11mA
-885.9mV  27.55mA    27.08mA    25.8mA
-487.3mV  21.68mA    21.41mA    20.38mA
-354.4mV  16.72mA    16.73mA    15.41mA
548.4mV   -24.49mA   -24.42mA   -22.29mA
801.6mV   -33.88mA   -33.05mA   -30.31mA
1.012V    -39.34mA   -37.44mA   -34.47mA
1.571V    -46.04mA   -42.91mA   -39.53mA
2.369V    -50.59mA   -46.79mA   -43.01mA
2.413V    -52.34mA   -46.95mA   -43.16mA
2.502V    -51.08mA   -47.27mA   -43.48mA
2.7V      -51.83mA   -47.98mA   -45.11mA
[Pulldown]
| Voltage   I(typ)   I(min)   I(max)
-1.35V    -38.38mA   -33.4mA    -34.09mA
-1.24V    -39.28mA   -34.78mA   -30.81mA
-1.196V   -39.3mA    -35.19mA   -27.8mA
-1.063V   -34.74mA   -35.29mA   -26mA
-1.019V   -31.93mA   -34.72mA   -25.55mA
-531.6mV  -22.61mA   -23.12mA   -19.73mA
-310.1mV  -14.93mA   -14.94mA   -13.42mA
548.4mV   24.83mA    24.29mA    22.64mA
843.8mV   35.86mA    34.01mA    33.22mA
1.055V    41.64mA    37.78mA    39.43mA
1.394V    45.24mA    39.58mA    44.65mA
2.7V      48.72mA    42.38mA    48.38mA
[Ramp]
dV/dt_r   0.562621/0.100554n  0.535422/0.107469n  0.572893/0.121379n
dV/dt_f   0.565503/90.481p  0.535497/96.7384p  0.574956/91.0848p
R_load = 50
[Rising Waveform]
R_fixture = 50
V_fixture = 0
V_fixture_min = 0
V_fixture_max = 0
| Time   V(typ)   V(min)   V(max)
0s        1.369uV    1.436uV    2.049uV
1.009ns   -498.7uV   -366.3uV   -7.785mV
1.228ns   -2.795mV   -446.1uV   822.7mV
1.313ns   3.624mV    -477.1uV   914.4mV
1.421ns   494.1mV    -516.4uV   941.1mV
1.495ns   829.1mV    -543.4uV   947mV
1.726ns   928.7mV    24.72mV    952.9mV
1.917ns   935.1mV    813.5mV    953.7mV
2.112ns   936.3mV    881.8mV    953.9mV
10ns      937.7mV    892.4mV    954.8mV
[Rising Waveform]
R_fixture = 50
V_fixture = 1.35
V_fixture_min = 1.2825
V_fixture_max = 1.4175
| Time   V(typ)   V(min)   V(max)
0s        407.5mV    390mV      459.2mV
933ps     407.9mV    390.5mV    464.8mV
1.114ns   408mV      390.6mV    1.307V
1.287ns   547.6mV    390.7mV    1.406V
1.392ns   1.2V       390.8mV    1.413V
1.447ns   1.303V     390.8mV    1.414V
1.665ns   1.344V     436.9mV    1.416V
1.812ns   1.347V     1.192V     1.416V
1.949ns   1.348V     1.269V     1.416V
10ns      1.35V      1.282V     1.417V
[Falling Waveform]
R_fixture = 50
V_fixture = 0
V_fixture_min = 0
V_fixture_max = 0
| Time   V(typ)   V(min)   V(max)
0s        937.7mV    892.4mV    954.8mV
913ps     937.1mV    891.8mV    944.7mV
1.064ns   937mV      891.7mV    125.9mV
1.251ns   907mV      891.6mV    8.763mV
1.399ns   92.04mV    891.5mV    3.491mV
1.557ns   9.229mV    891.4mV    1.769mV
1.676ns   4.213mV    844.3mV    1.286mV
1.794ns   2.233mV    172.9mV    1.042mV
1.952ns   1.362mV    11.66mV    896.8uV
10ns      2.123uV    2.432uV    2.476uV
[Falling Waveform]
R_fixture = 50
V_fixture = 1.35
V_fixture_min = 1.2825
V_fixture_max = 1.4175
| Time   V(typ)   V(min)   V(max)
0s        1.35V      1.282V     1.417V
996ps     1.351V     1.283V     1.416V
1.155ns   1.351V     1.283V     598mV
1.335ns   1.284V     1.283V     470.7mV
1.481ns   510.8mV    1.283V     463.3mV
1.669ns   416mV      1.288V     461.5mV
1.748ns   412.3mV    1.216V     461.2mV
1.894ns   409.9mV    508.6mV    460.6mV
2.049ns   409.2mV    401.5mV    460.3mV
10ns      407.5mV    390mV      459.2mV
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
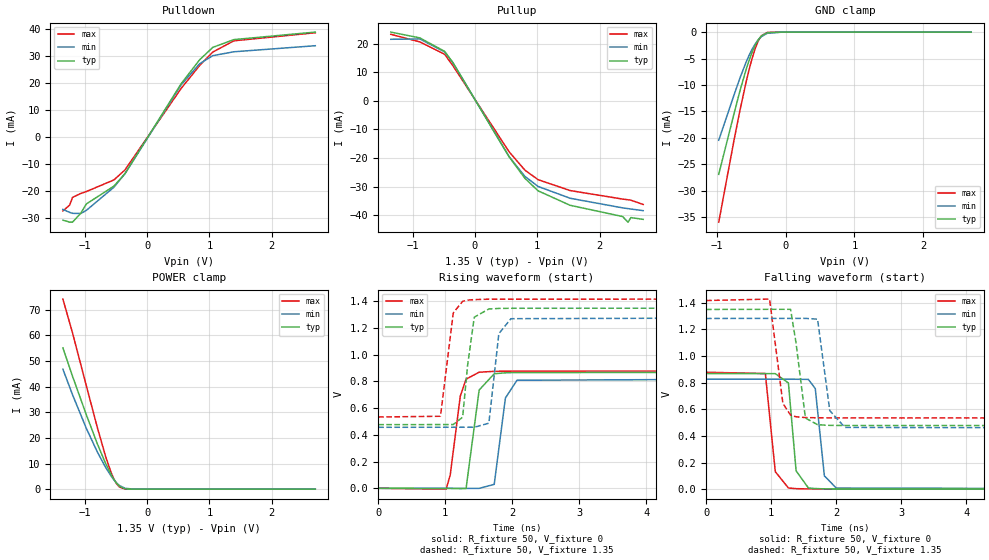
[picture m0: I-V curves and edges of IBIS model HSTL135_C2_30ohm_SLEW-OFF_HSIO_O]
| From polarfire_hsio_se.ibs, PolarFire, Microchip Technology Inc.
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|   Model HSTL135_C2_30ohm_SLEW-OFF_HSIO_O
[Model]   HSTL135_C2_30ohm_SLEW-OFF_HSIO_O
Model_type   Output
Polarity   Non-Inverting
Enable   Active-High
Vmeas =   0.675
Cref =   5p
Rref =   50
Vref =   0.675
|   typ   min   max
C_comp_pullup   1.335e-12   1.335e-12   1.380e-12
C_comp_pulldown  1.335e-12   1.335e-12   1.380e-12
[Temperature Range]  25C   100C   -40C
[Voltage Range]  1.35   1.2825   1.4175
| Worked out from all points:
|   slope of the pulldown table from 0 to 0.203 V, typ, clamps not added: 26.3 ohm
|   slope of the pullup table from 0 to 0.203 V, typ, clamps not added: 26.8 ohm
|   GND clamp passes 1 mA (typ) near -0.37 V on its own axis
|   POWER clamp passes 1 mA (typ) near -0.43 V on its own axis
|   rising waveform, R_fixture 50, V_fixture 0: 20-80 % time 113ps typ, 120ps min, 136ps max; typ from 0 V to 0.868 V
|   rising waveform, R_fixture 50, V_fixture 1.35: 20-80 % time 98.7ps typ, 96.7ps min, 110ps max; typ from 0.477 V to 1.35 V
|   falling waveform, R_fixture 50, V_fixture 0: 20-80 % time 87.2ps typ, 91.6ps min, 91.3ps max; typ from 0.868 V to 0 V
|   falling waveform, R_fixture 50, V_fixture 1.35: 20-80 % time 101ps typ, 108ps min, 101ps max; typ from 1.35 V to 0.477 V
[GND Clamp]
| Voltage   I(typ)   I(min)   I(max)
-974.5mV  -26.9mA    -20.45mA   -35.95mA
-753mV    -15.48mA   -11.94mA   -20.52mA
-664.5mV  -11.06mA   -8.652mA   -14.74mA
-575.9mV  -7.072mA   -5.674mA   -9.445mA
-531.6mV  -5.316mA   -4.365mA   -7.064mA
-487.3mV  -3.767mA   -3.209mA   -4.927mA
-443mV    -2.466mA   -2.228mA   -3.102mA
-398.7mV  -1.449mA   -1.441mA   -1.67mA
-354.4mV  -738.4uA   -854uA     -712.2uA
-265.8mV  -117.5uA   -220.3uA   -58.64uA
-44.3mV   -274.4nA   -1.655uA   -83.21nA
2.7V      0A         0A         0A
[POWER Clamp]
| Voltage   I(typ)   I(min)   I(max)
-1.35V    55.07mA    46.77mA    74.1mA
-1.196V   44.05mA    36.84mA    60.94mA
-974.5mV  29.03mA    23.74mA    40.36mA
-797.3mV  17.68mA    14.49mA    24.04mA
-664.5mV  10.01mA    8.483mA    12.73mA
-575.9mV  5.63mA     5.093mA    6.421mA
-531.6mV  3.786mA    3.641mA    3.935mA
-487.3mV  2.262mA    2.398mA    2.056mA
-443mV    1.133mA    1.41mA     851.4uA
-354.4mV  127.5uA    344.8uA    50.77uA
-221.5mV  1.715uA    33.09uA    747.7nA
2.7V      0A         0A         0A
[Pullup]
| Voltage   I(typ)   I(min)   I(max)
-1.35V    24.06mA    21.54mA    23.28mA
-885.9mV  22.04mA    21.67mA    20.64mA
-487.3mV  17.34mA    17.13mA    16.3mA
-354.4mV  13.38mA    13.39mA    12.33mA
548.4mV   -19.59mA   -19.54mA   -17.84mA
801.6mV   -27.11mA   -26.44mA   -24.25mA
1.012V    -31.48mA   -29.95mA   -27.58mA
1.527V    -36.56mA   -34.09mA   -31.4mA
2.369V    -40.49mA   -37.46mA   -34.38mA
2.457V    -42.47mA   -37.72mA   -34.63mA
2.502V    -40.86mA   -37.86mA   -34.76mA
2.7V      -41.47mA   -38.43mA   -36.27mA
[Pulldown]
| Voltage   I(typ)   I(min)   I(max)
-1.35V    -30.69mA   -26.72mA   -27.28mA
-1.24V    -31.42mA   -27.82mA   -25.07mA
-1.196V   -31.44mA   -28.15mA   -22.26mA
-1.063V   -28.13mA   -28.23mA   -20.8mA
-974.5mV  -24.7mA    -27.07mA   -20.1mA
-531.6mV  -18.09mA   -18.5mA    -15.79mA
-354.4mV  -13.47mA   -13.49mA   -12.09mA
548.4mV   19.87mA    19.44mA    18.13mA
843.8mV   28.69mA    27.22mA    26.59mA
1.055V    33.3mA     30.23mA    31.56mA
1.394V    36.18mA    31.67mA    35.73mA
2.7V      38.96mA    33.91mA    38.71mA
[Ramp]
dV/dt_r   0.521067/0.112898n  0.49582/0.119542n  0.526904/0.136176n
dV/dt_f   0.523964/0.100501n  0.49542/0.108398n  0.530164/0.100644n
R_load = 50
[Rising Waveform]
R_fixture = 50
V_fixture = 0
V_fixture_min = 0
V_fixture_max = 0
| Time   V(typ)   V(min)   V(max)
0s        1.375uV    1.489uV    2.073uV
1.014ns   -830.7uV   -413.9uV   -6.483mV
1.075ns   -880.8uV   -438.9uV   100.5mV
1.225ns   -2.173mV   -500.3uV   690.7mV
1.311ns   -1.471mV   -535.6uV   817mV
1.506ns   735.8mV    -615.4uV   869.3mV
1.731ns   857.6mV    29.54mV    875.9mV
1.898ns   864.8mV    676.5mV    876.8mV
2.071ns   866.7mV    809.1mV    877.1mV
10ns      868.4mV    826.4mV    878.2mV
[Rising Waveform]
R_fixture = 50
V_fixture = 1.35
V_fixture_min = 1.2825
V_fixture_max = 1.4175
| Time   V(typ)   V(min)   V(max)
0s        476.7mV    456.8mV    533.9mV
929ps     477.2mV    457.1mV    539.5mV
1.12ns    477.3mV    457.1mV    1.313V
1.26ns    532.8mV    457.2mV    1.4V
1.333ns   917.1mV    457.2mV    1.409V
1.433ns   1.281V     457.2mV    1.413V
1.651ns   1.343V     487.5mV    1.416V
1.8ns     1.347V     1.158V     1.416V
1.98ns    1.348V     1.27V      1.416V
10ns      1.35V      1.282V     1.417V
[Falling Waveform]
R_fixture = 50
V_fixture = 0
V_fixture_min = 0
V_fixture_max = 0
| Time   V(typ)   V(min)   V(max)
0s        868.5mV    826.4mV    878.2mV
911ps     867.9mV    825.9mV    868.6mV
1.064ns   867.8mV    825.8mV    130.9mV
1.266ns   797.5mV    825.7mV    8.885mV
1.384ns   137.9mV    825.6mV    3.859mV
1.573ns   9.225mV    824.8mV    1.803mV
1.679ns   4.662mV    755.6mV    1.515mV
1.819ns   2.293mV    99.77mV    1.135mV
2.002ns   1.424mV    8.583mV    787.1uV
10ns      2.191uV    2.479uV    2.696uV
[Falling Waveform]
R_fixture = 50
V_fixture = 1.35
V_fixture_min = 1.2825
V_fixture_max = 1.4175
| Time   V(typ)   V(min)   V(max)
0s        1.35V      1.282V     1.417V
976ps     1.351V     1.283V     1.428V
1.181ns   1.351V     1.283V     643.8mV
1.299ns   1.351V     1.283V     556.1mV
1.382ns   1.102V     1.283V     543.7mV
1.527ns   534.5mV    1.283V     537.7mV
1.714ns   484.2mV    1.277V     536.2mV
1.902ns   479.4mV    589.9mV    535.5mV
2.135ns   478.4mV    463.8mV    535mV
10ns      476.7mV    456.8mV    533.9mV
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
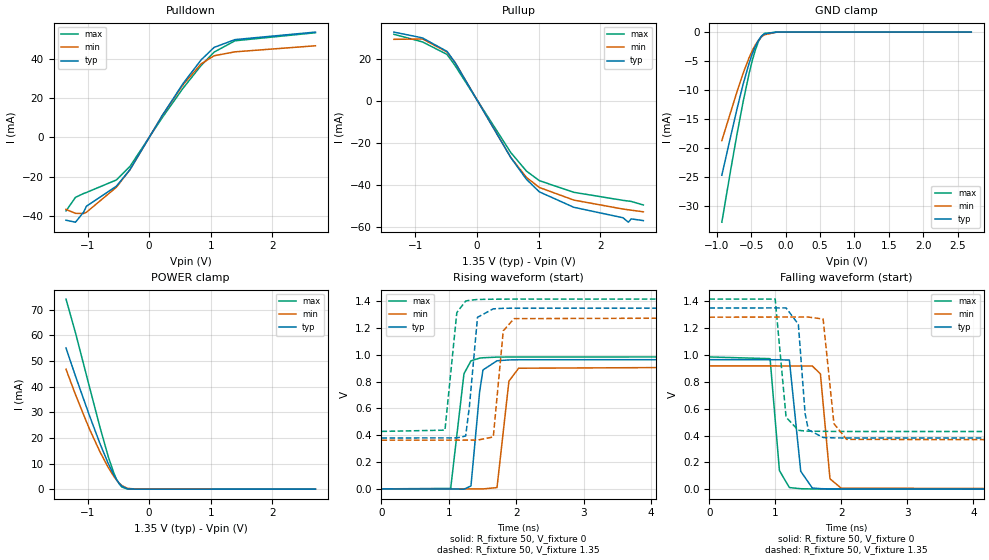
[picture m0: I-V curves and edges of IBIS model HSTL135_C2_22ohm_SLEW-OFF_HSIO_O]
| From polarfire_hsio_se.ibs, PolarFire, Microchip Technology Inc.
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|   Model HSTL135_C2_22ohm_SLEW-OFF_HSIO_O
[Model]   HSTL135_C2_22ohm_SLEW-OFF_HSIO_O
Model_type   Output
Polarity   Non-Inverting
Enable   Active-High
Vmeas =   0.675
Cref =   5p
Rref =   50
Vref =   0.675
|   typ   min   max
C_comp_pullup   1.335e-12   1.335e-12   1.380e-12
C_comp_pulldown  1.335e-12   1.335e-12   1.380e-12
[Temperature Range]  25C   100C   -40C
[Voltage Range]  1.35   1.2825   1.4175
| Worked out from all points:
|   slope of the pulldown table from 0 to 0.203 V, typ, clamps not added: 19.1 ohm
|   slope of the pullup table from 0 to 0.203 V, typ, clamps not added: 19.5 ohm
|   GND clamp passes 1 mA (typ) near -0.37 V on its own axis
|   POWER clamp passes 1 mA (typ) near -0.43 V on its own axis
|   rising waveform, R_fixture 50, V_fixture 0: 20-80 % time 96.8ps typ, 102ps min, 115ps max; typ from 0 V to 0.966 V
|   rising waveform, R_fixture 50, V_fixture 1.35: 20-80 % time 85.4ps typ, 82.6ps min, 97.6ps max; typ from 0.38 V to 1.35 V
|   falling waveform, R_fixture 50, V_fixture 0: 20-80 % time 80.9ps typ, 81.9ps min, 84.2ps max; typ from 0.966 V to 0 V
|   falling waveform, R_fixture 50, V_fixture 1.35: 20-80 % time 85.3ps typ, 92.4ps min, 86.3ps max; typ from 1.35 V to 0.38 V
[GND Clamp]
| Voltage   I(typ)   I(min)   I(max)
-930.2mV  -24.71mA   -18.73mA   -32.82mA
-797.3mV  -17.78mA   -13.65mA   -23.53mA
-708.7mV  -13.23mA   -10.27mA   -17.58mA
-620.2mV  -8.998mA   -7.111mA   -12.02mA
-531.6mV  -5.316mA   -4.365mA   -7.064mA
-487.3mV  -3.767mA   -3.209mA   -4.927mA
-443mV    -2.466mA   -2.228mA   -3.102mA
-398.7mV  -1.449mA   -1.441mA   -1.67mA
-354.4mV  -738.4uA   -854uA     -712.2uA
-310.1mV  -318.4uA   -457.5uA   -228.1uA
-132.9mV  -3.522uA   -14.87uA   -692.5nA
2.7V      0A         0A         0A
[POWER Clamp]
| Voltage   I(typ)   I(min)   I(max)
-1.35V    55.07mA    46.77mA    74.1mA
-1.196V   44.05mA    36.84mA    60.94mA
-974.5mV  29.03mA    23.74mA    40.36mA
-797.3mV  17.68mA    14.49mA    24.04mA
-664.5mV  10.01mA    8.483mA    12.73mA
-575.9mV  5.63mA     5.093mA    6.421mA
-531.6mV  3.786mA    3.641mA    3.935mA
-487.3mV  2.262mA    2.398mA    2.056mA
-443mV    1.133mA    1.41mA     851.4uA
-354.4mV  127.5uA    344.8uA    50.77uA
-221.5mV  1.715uA    33.09uA    747.7nA
2.7V      0A         0A         0A
[Pullup]
| Voltage   I(typ)   I(min)   I(max)
-1.35V    33.08mA    29.62mA    32.02mA
-885.9mV  30.3mA     29.79mA    28.38mA
-487.3mV  23.84mA    23.55mA    22.41mA
-354.4mV  18.39mA    18.41mA    16.95mA
548.4mV   -26.94mA   -26.86mA   -24.52mA
801.6mV   -37.27mA   -36.35mA   -33.34mA
1.012V    -43.28mA   -41.18mA   -37.92mA
1.571V    -50.64mA   -47.2mA    -43.48mA
2.369V    -55.64mA   -51.48mA   -47.32mA
2.457V    -57.76mA   -51.84mA   -47.66mA
2.502V    -56.18mA   -52.01mA   -47.83mA
2.7V      -57mA      -52.8mA    -49.54mA
[Pulldown]
| Voltage   I(typ)   I(min)   I(max)
-1.35V    -42.21mA   -36.74mA   -37.48mA
-1.196V   -43.22mA   -38.71mA   -30.57mA
-1.063V   -38.04mA   -38.81mA   -28.59mA
-1.019V   -35.11mA   -38.18mA   -28.1mA
-531.6mV  -24.87mA   -25.42mA   -21.71mA
-310.1mV  -16.42mA   -16.43mA   -14.76mA
210.9mV   11.01mA    10.95mA    9.947mA
548.4mV   27.31mA    26.7mA     24.92mA
843.8mV   39.43mA    37.4mA     36.56mA
1.055V    45.79mA    41.54mA    43.4mA
1.394V    49.76mA    43.53mA    49.15mA
2.7V      53.58mA    46.61mA    53.25mA
[Ramp]
dV/dt_r   0.579308/96.7533p  0.551339/0.101796n  0.591354/0.115297n
dV/dt_f   0.582031/85.2881p  0.551457/92.3893p  0.593141/86.3439p
R_load = 50
[Rising Waveform]
R_fixture = 50
V_fixture = 0
V_fixture_min = 0
V_fixture_max = 0
| Time   V(typ)   V(min)   V(max)
0s        1.367uV    1.414uV    2.039uV
1.027ns   -733.2uV   -364.6uV   3.324mV
1.224ns   -2.273mV   -434.8uV   859.3mV
1.328ns   21.65mV    -471.8uV   955.9mV
1.456ns   723.1mV    -517.5uV   976mV
1.506ns   887.7mV    -535.3uV   978.8mV
1.714ns   956.2mV    9.385mV    983.6mV
1.891ns   962.6mV    803.9mV    984.4mV
2.035ns   963.9mV    900.7mV    984.5mV
10ns      965.5mV    918.9mV    985.6mV
[Rising Waveform]
R_fixture = 50
V_fixture = 1.35
V_fixture_min = 1.2825
V_fixture_max = 1.4175
| Time   V(typ)   V(min)   V(max)
0s        379.9mV    363.4mV    428.9mV
942ps     380.4mV    363.8mV    438.3mV
1.118ns   380.5mV    363.9mV    1.316V
1.249ns   394.4mV    363.9mV    1.402V
1.304ns   611.7mV    364mV      1.408V
1.425ns   1.281V     364mV      1.414V
1.659ns   1.344V     387.4mV    1.416V
1.807ns   1.348V     1.18V      1.416V
1.967ns   1.349V     1.271V     1.417V
10ns      1.35V      1.282V     1.417V
[Falling Waveform]
R_fixture = 50
V_fixture = 0
V_fixture_min = 0
V_fixture_max = 0
| Time   V(typ)   V(min)   V(max)
0s        965.5mV    918.9mV    985.6mV
920ps     964.8mV    918.5mV    972.8mV
1.061ns   964.7mV    918.4mV    138.6mV
1.212ns   962.1mV    918.3mV    12.02mV
1.384ns   133.4mV    918.3mV    3.342mV
1.559ns   8.8mV      918.2mV    1.597mV
1.682ns   3.777mV    859.5mV    1.341mV
1.827ns   1.914mV    77.06mV    1.04mV
1.997ns   1.311mV    7.26mV     718uV
10ns      2.053uV    2.436uV    2.522uV
[Falling Waveform]
R_fixture = 50
V_fixture = 1.35
V_fixture_min = 1.2825
V_fixture_max = 1.4175
| Time   V(typ)   V(min)   V(max)
0s        1.35V      1.282V     1.417V
997ps     1.351V     1.283V     1.417V
1.162ns   1.351V     1.283V     536.5mV
1.348ns   1.229V     1.283V     438.8mV
1.45ns    564.5mV    1.283V     433.6mV
1.499ns   442.8mV    1.283V     432.5mV
1.723ns   385.1mV    1.268V     430.9mV
1.887ns   382.3mV    488.5mV    430.3mV
2.078ns   381.5mV    371.2mV    430mV
10ns      379.9mV    363.4mV    428.9mV
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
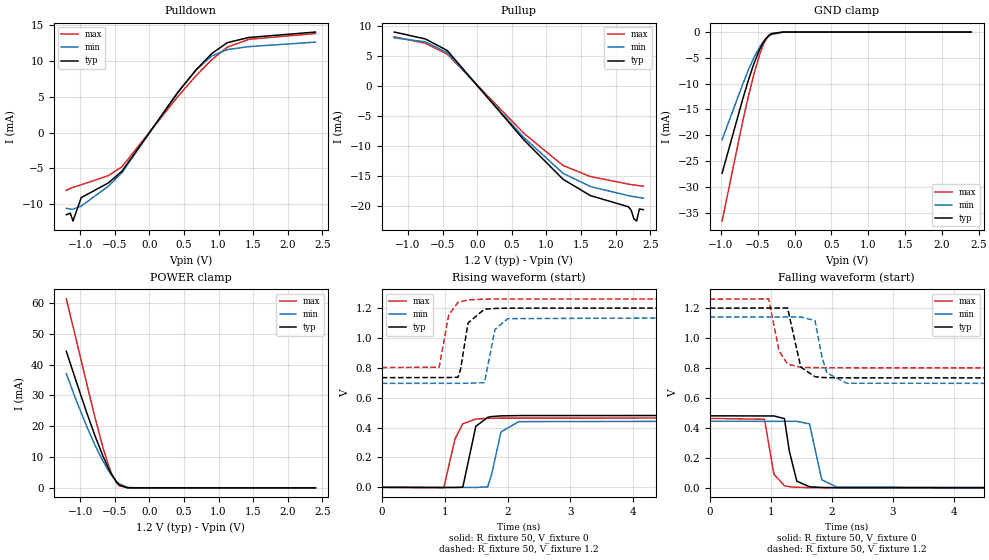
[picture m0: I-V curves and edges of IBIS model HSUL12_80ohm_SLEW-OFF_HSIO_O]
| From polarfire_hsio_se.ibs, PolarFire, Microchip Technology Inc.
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|   Model HSUL12_80ohm_SLEW-OFF_HSIO_O
[Model]   HSUL12_80ohm_SLEW-OFF_HSIO_O
Model_type   Output
Polarity   Non-Inverting
Enable   Active-High
Vmeas =   0.6
Cref =   5p
Rref =   50
Vref =   0.6
|   typ   min   max
C_comp_pullup   1.335e-12   1.335e-12   1.380e-12
C_comp_pulldown  1.335e-12   1.335e-12   1.380e-12
[Temperature Range]  25C   100C   -40C
[Voltage Range]  1.2   1.14   1.26
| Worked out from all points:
|   slope of the pulldown table from 0 to 0.18 V, typ, clamps not added: 72 ohm
|   slope of the pullup table from 0 to 0.18 V, typ, clamps not added: 72.4 ohm
|   GND clamp passes 1 mA (typ) near -0.37 V on its own axis
|   POWER clamp passes 1 mA (typ) near -0.44 V on its own axis
|   rising waveform, R_fixture 50, V_fixture 0: 20-80 % time 129ps typ, 136ps min, 141ps max; typ from 0 V to 0.481 V
|   rising waveform, R_fixture 50, V_fixture 1.2: 20-80 % time 113ps typ, 113ps min, 120ps max; typ from 0.733 V to 1.2 V
|   falling waveform, R_fixture 50, V_fixture 0: 20-80 % time 105ps typ, 114ps min, 99.9ps max; typ from 0.481 V to 0 V
|   falling waveform, R_fixture 50, V_fixture 1.2: 20-80 % time 132ps typ, 140ps min, 129ps max; typ from 1.2 V to 0.733 V
[GND Clamp]
| Voltage   I(typ)   I(min)   I(max)
-984.4mV  -27.36mA   -20.85mA   -36.63mA
-708.7mV  -13.22mA   -10.27mA   -17.58mA
-630mV    -9.442mA   -7.443mA   -12.61mA
-551.3mV  -6.071mA   -4.927mA   -8.091mA
-472.5mV  -3.303mA   -2.86mA    -4.278mA
-433.1mV  -2.213mA   -2.035mA   -2.745mA
-393.7mV  -1.354mA   -1.365mA   -1.538mA
-354.4mV  -738.1uA   -853.7uA   -711.7uA
-315mV    -352.4uA   -492.8uA   -262uA
-157.5mV  -6.952uA   -25.53uA   -1.531uA
-39.38mV  -223.3nA   -1.393uA   -60.97nA
2.4V      0A         0A         0A
[POWER Clamp]
| Voltage   I(typ)   I(min)   I(max)
-1.2V     44.33mA    37.08mA    61.33mA
-1.063V   34.96mA    28.78mA    48.72mA
-905.6mV  24.47mA    19.99mA    33.89mA
-787.5mV  17.03mA    14mA       23.06mA
-669.4mV  10.26mA    8.667mA    13.03mA
-590.6mV  6.299mA    5.605mA    7.313mA
-551.3mV  4.569mA    4.255mA    4.935mA
-472.5mV  1.839mA    2.031mA    1.558mA
-433.1mV  941.2uA    1.284mA    654.9uA
-315mV    34.81uA    149.8uA    11.13uA
-236.2mV  2.462uA    44.69uA    773.7nA
2.4V      0A         0A         0A
[Pullup]
| Voltage   I(typ)   I(min)   I(max)
-1.2V     8.924mA    7.961mA    8.122mA
-748.1mV  7.769mA    7.284mA    7.052mA
-433.1mV  5.841mA    5.488mA    5.24mA
675mV     -9.059mA   -8.659mA   -7.958mA
1.239V    -15.59mA   -14.6mA    -13.3mA
1.633V    -18.31mA   -16.8mA    -15.14mA
2.184V    -20.18mA   -18.33mA   -16.41mA
2.224V    -20.75mA   -18.41mA   -16.48mA
2.263V    -22.18mA   -18.49mA   -16.54mA
2.303V    -22.55mA   -18.56mA   -16.61mA
2.342V    -20.56mA   -18.64mA   -16.67mA
2.4V      -20.66mA   -18.74mA   -16.77mA
[Pulldown]
| Voltage   I(typ)   I(min)   I(max)
-1.2V     -11.43mA   -10.54mA   -8.036mA
-1.142V   -11.2mA    -10.65mA   -7.761mA
-1.103V   -12.3mA    -10.66mA   -7.621mA
-984.4mV  -9.054mA   -10.23mA   -7.269mA
-590.6mV  -6.995mA   -7.449mA   -5.985mA
-393.7mV  -5.356mA   -5.547mA   -4.741mA
412.5mV   5.564mA    5.662mA    5.003mA
675mV     8.704mA    8.696mA    7.907mA
900mV     10.96mA    10.63mA    10.11mA
1.125V    12.49mA    11.53mA    11.86mA
1.436V    13.21mA    11.94mA    12.95mA
2.4V      13.97mA    12.57mA    13.76mA
[Ramp]
dV/dt_r   0.288514/0.12946n  0.266934/0.135955n  0.278173/0.140818n
dV/dt_f   0.280002/0.131721n  0.26692/0.140237n  0.275407/0.12947n
R_load = 50
[Rising Waveform]
R_fixture = 50
V_fixture = 0
V_fixture_min = 0
V_fixture_max = 0
| Time   V(typ)   V(min)   V(max)
0s        1.141uV    1.496uV    1.724uV
986ps     -719.6uV   -571.5uV   -3.324mV
1.164ns   -849.7uV   -674.9uV   322.7mV
1.289ns   1.167mV    -747.6uV   425.4mV
1.496ns   408.2mV    -867.9uV   456.1mV
1.685ns   467.9mV    3.793mV    461.4mV
1.743ns   473.1mV    78.73mV    461.9mV
1.896ns   477.7mV    370.6mV    462.6mV
2.179ns   479.8mV    439.4mV    462.8mV
10ns      480.9mV    444.9mV    463.6mV
[Rising Waveform]
R_fixture = 50
V_fixture = 1.2
V_fixture_min = 1.14
V_fixture_max = 1.26
| Time   V(typ)   V(min)   V(max)
0s        733.3mV    695.1mV    801mV
913ps     734mV      695.4mV    803mV
1.065ns   734.1mV    695.5mV    1.152V
1.213ns   736.2mV    695.6mV    1.236V
1.254ns   791.4mV    695.6mV    1.241V
1.372ns   1.099V     695.6mV    1.253V
1.633ns   1.191V     700.4mV    1.258V
1.801ns   1.196V     1.056V     1.259V
2.003ns   1.198V     1.128V     1.259V
10ns      1.2V       1.14V      1.26V
[Falling Waveform]
R_fixture = 50
V_fixture = 0
V_fixture_min = 0
V_fixture_max = 0
| Time   V(typ)   V(min)   V(max)
0s        480.9mV    444.9mV    463.6mV
897ps     480.1mV    444.3mV    458.2mV
1.053ns   480mV      444.2mV    89.99mV
1.224ns   462.3mV    444.1mV    14.24mV
1.303ns   247.2mV    444.1mV    7.114mV
1.426ns   44.61mV    444mV      3.853mV
1.634ns   7.198mV    427.5mV    1.488mV
1.835ns   2.491mV    53.48mV    850uV
2.08ns    1.142mV    4.907mV    740.8uV
10ns      2.079uV    3.313uV    2.738uV
[Falling Waveform]
R_fixture = 50
V_fixture = 1.2
V_fixture_min = 1.14
V_fixture_max = 1.26
| Time   V(typ)   V(min)   V(max)
0s        1.2V       1.14V      1.26V
966ps     1.201V     1.141V     1.262V
1.136ns   1.201V     1.141V     913.9mV
1.275ns   1.201V     1.141V     826.2mV
1.491ns   806.8mV    1.141V     804.9mV
1.724ns   742.1mV    1.117V     802.7mV
1.842ns   737.2mV    866.2mV    802.4mV
1.919ns   736mV      767.5mV    802.3mV
2.243ns   734.6mV    698.9mV    801.8mV
10ns      733.3mV    695.1mV    801mV
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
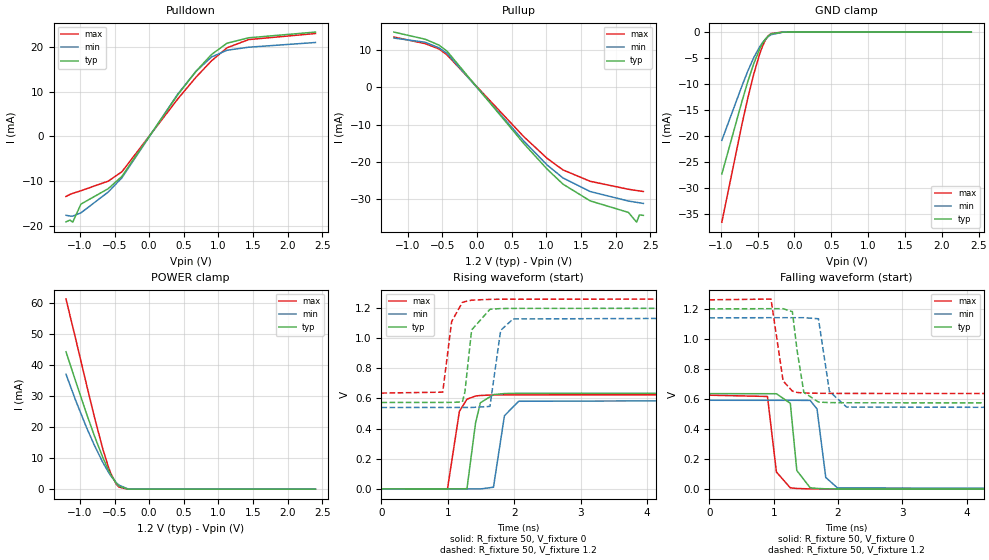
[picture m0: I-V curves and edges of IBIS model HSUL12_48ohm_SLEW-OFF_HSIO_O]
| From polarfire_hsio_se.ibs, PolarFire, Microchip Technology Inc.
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|   Model HSUL12_48ohm_SLEW-OFF_HSIO_O
[Model]   HSUL12_48ohm_SLEW-OFF_HSIO_O
Model_type   Output
Polarity   Non-Inverting
Enable   Active-High
Vmeas =   0.6
Cref =   5p
Rref =   50
Vref =   0.6
|   typ   min   max
C_comp_pullup   1.335e-12   1.335e-12   1.380e-12
C_comp_pulldown  1.335e-12   1.335e-12   1.380e-12
[Temperature Range]  25C   100C   -40C
[Voltage Range]  1.2   1.14   1.26
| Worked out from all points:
|   slope of the pulldown table from 0 to 0.18 V, typ, clamps not added: 43.3 ohm
|   slope of the pullup table from 0 to 0.18 V, typ, clamps not added: 43.4 ohm
|   GND clamp passes 1 mA (typ) near -0.37 V on its own axis
|   POWER clamp passes 1 mA (typ) near -0.44 V on its own axis
|   rising waveform, R_fixture 50, V_fixture 0: 20-80 % time 102ps typ, 109ps min, 114ps max; typ from 0 V to 0.636 V
|   rising waveform, R_fixture 50, V_fixture 1.2: 20-80 % time 97.3ps typ, 94.2ps min, 104ps max; typ from 0.573 V to 1.2 V
|   falling waveform, R_fixture 50, V_fixture 0: 20-80 % time 84.1ps typ, 92.2ps min, 86.9ps max; typ from 0.636 V to 0 V
|   falling waveform, R_fixture 50, V_fixture 1.2: 20-80 % time 103ps typ, 112ps min, 106ps max; typ from 1.2 V to 0.573 V
[GND Clamp]
| Voltage   I(typ)   I(min)   I(max)
-984.4mV  -27.36mA   -20.85mA   -36.63mA
-708.7mV  -13.22mA   -10.27mA   -17.58mA
-630mV    -9.442mA   -7.443mA   -12.61mA
-551.3mV  -6.071mA   -4.927mA   -8.091mA
-472.5mV  -3.303mA   -2.86mA    -4.278mA
-433.1mV  -2.213mA   -2.035mA   -2.745mA
-393.7mV  -1.354mA   -1.365mA   -1.538mA
-354.4mV  -738.1uA   -853.7uA   -711.7uA
-315mV    -352.4uA   -492.8uA   -262uA
-157.5mV  -6.952uA   -25.53uA   -1.531uA
-39.38mV  -223.3nA   -1.393uA   -60.97nA
2.4V      0A         0A         0A
[POWER Clamp]
| Voltage   I(typ)   I(min)   I(max)
-1.2V     44.33mA    37.08mA    61.33mA
-1.063V   34.96mA    28.78mA    48.72mA
-905.6mV  24.47mA    19.99mA    33.89mA
-787.5mV  17.03mA    14mA       23.06mA
-669.4mV  10.26mA    8.667mA    13.03mA
-590.6mV  6.299mA    5.605mA    7.313mA
-551.3mV  4.569mA    4.255mA    4.935mA
-472.5mV  1.839mA    2.031mA    1.558mA
-433.1mV  941.2uA    1.284mA    654.9uA
-315mV    34.81uA    149.8uA    11.13uA
-236.2mV  2.462uA    44.69uA    773.7nA
2.4V      0A         0A         0A
[Pullup]
| Voltage   I(typ)   I(min)   I(max)
-1.2V     14.87mA    13.27mA    13.54mA
-748.1mV  12.95mA    12.14mA    11.76mA
-551.3mV  11.39mA    10.66mA    10.36mA
-433.1mV  9.734mA    9.145mA    8.728mA
675mV     -15.1mA    -14.43mA   -13.25mA
1.012V    -21.97mA   -20.86mA   -19.08mA
1.239V    -25.98mA   -24.32mA   -22.16mA
1.633V    -30.5mA    -27.98mA   -25.23mA
2.184V    -33.59mA   -30.53mA   -27.37mA
2.303V    -36.22mA   -30.89mA   -27.71mA
2.342V    -34.27mA   -31.01mA   -27.81mA
2.4V      -34.38mA   -31.18mA   -27.97mA
[Pulldown]
| Voltage   I(typ)   I(min)   I(max)
-1.2V     -19.04mA   -17.57mA   -13.39mA
-1.142V   -18.65mA   -17.75mA   -12.93mA
-1.103V   -19.12mA   -17.76mA   -12.7mA
-984.4mV  -15.09mA   -17.04mA   -12.11mA
-590.6mV  -11.65mA   -12.4mA    -9.971mA
-393.7mV  -8.917mA   -9.233mA   -7.897mA
412.5mV   9.257mA    9.42mA     8.333mA
675mV     14.48mA    14.47mA    13.17mA
900mV     18.24mA    17.69mA    16.84mA
1.125V    20.77mA    19.2mA     19.75mA
1.436V    21.97mA    19.87mA    21.57mA
2.4V      23.24mA    20.92mA    22.92mA
[Ramp]
dV/dt_r   0.381439/0.102304n  0.354985/0.10917n  0.375185/0.113907n
dV/dt_f   0.37603/0.103114n  0.359933/0.111595n  0.374415/0.10609n
R_load = 50
[Rising Waveform]
R_fixture = 50
V_fixture = 0
V_fixture_min = 0
V_fixture_max = 0
| Time   V(typ)   V(min)   V(max)
0s        1.182uV    1.411uV    1.76uV
994ps     -549.8uV   -455.3uV   -2.041mV
1.174ns   -649.6uV   -538uV     515mV
1.288ns   1.259mV    -590.4uV   595mV
1.417ns   436.8mV    -649.6uV   616.2mV
1.49ns    571.6mV    -683.2uV   619.9mV
1.687ns   625.8mV    10.87mV    623.4mV
1.852ns   632.7mV    485.3mV    624.3mV
2.066ns   634.4mV    581.5mV    624.4mV
10ns      635.7mV    591.6mV    625.3mV
[Rising Waveform]
R_fixture = 50
V_fixture = 1.2
V_fixture_min = 1.14
V_fixture_max = 1.26
| Time   V(typ)   V(min)   V(max)
0s        573.3mV    540.1mV    636mV
923ps     573.9mV    540.2mV    641.9mV
1.057ns   574mV      540.2mV    1.111V
1.219ns   577.3mV    540.3mV    1.238V
1.257ns   643.9mV    540.3mV    1.243V
1.358ns   1.055V     540.3mV    1.253V
1.634ns   1.192V     547.4mV    1.258V
1.795ns   1.197V     1.052V     1.259V
1.982ns   1.198V     1.128V     1.259V
10ns      1.2V       1.14V      1.26V
[Falling Waveform]
R_fixture = 50
V_fixture = 0
V_fixture_min = 0
V_fixture_max = 0
| Time   V(typ)   V(min)   V(max)
0s        635.7mV    591.6mV    625.3mV
903ps     635.1mV    591.3mV    616.9mV
1.042ns   635mV      591.3mV    114.2mV
1.258ns   571.5mV    591.2mV    8.722mV
1.359ns   124.4mV    591.2mV    4.621mV
1.566ns   9.509mV    590.6mV    1.778mV
1.673ns   4.824mV    533.8mV    1.305mV
1.809ns   2.347mV    77.88mV    1.046mV
1.99ns    1.327mV    8.693mV    752.8uV
10ns      3.159uV    2.328uV    2.657uV
[Falling Waveform]
R_fixture = 50
V_fixture = 1.2
V_fixture_min = 1.14
V_fixture_max = 1.26
| Time   V(typ)   V(min)   V(max)
0s        1.2V       1.14V      1.26V
958ps     1.201V     1.141V     1.265V
1.146ns   1.201V     1.141V     720.1mV
1.29ns    1.181V     1.141V     652.4mV
1.364ns   920.7mV    1.141V     643.4mV
1.468ns   644.3mV    1.141V     640.1mV
1.695ns   579.8mV    1.134V     637.9mV
1.866ns   576mV      650.6mV    637.5mV
2.132ns   574.8mV    546.4mV    636.9mV
10ns      573.3mV    540.1mV    636mV
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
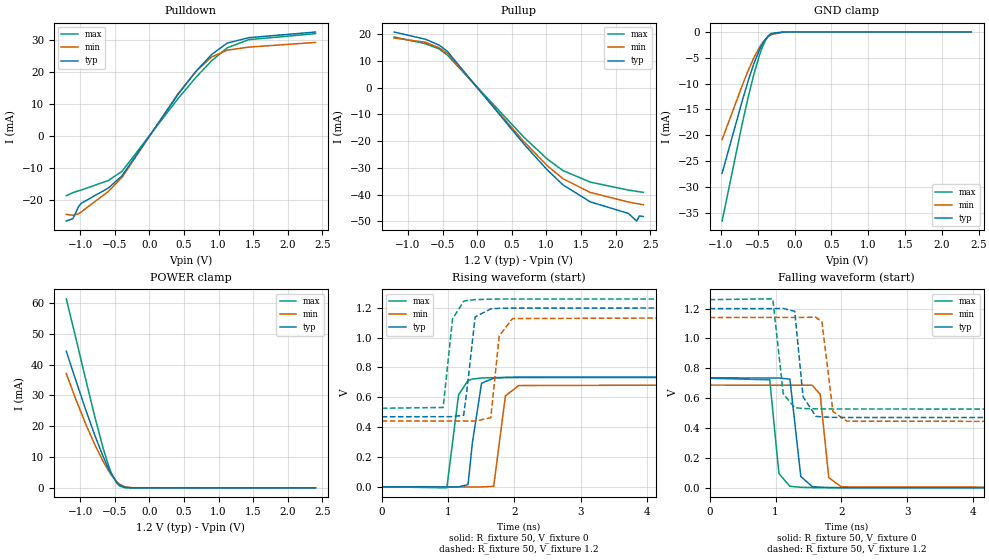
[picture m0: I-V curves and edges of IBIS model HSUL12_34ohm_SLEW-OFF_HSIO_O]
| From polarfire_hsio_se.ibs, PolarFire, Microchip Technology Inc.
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|   Model HSUL12_34ohm_SLEW-OFF_HSIO_O
[Model]   HSUL12_34ohm_SLEW-OFF_HSIO_O
Model_type   Output
Polarity   Non-Inverting
Enable   Active-High
Vmeas =   0.6
Cref =   5p
Rref =   50
Vref =   0.6
|   typ   min   max
C_comp_pullup   1.335e-12   1.335e-12   1.380e-12
C_comp_pulldown  1.335e-12   1.335e-12   1.380e-12
[Temperature Range]  25C   100C   -40C
[Voltage Range]  1.2   1.14   1.26
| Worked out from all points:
|   slope of the pulldown table from 0 to 0.18 V, typ, clamps not added: 30.9 ohm
|   slope of the pullup table from 0 to 0.18 V, typ, clamps not added: 31 ohm
|   GND clamp passes 1 mA (typ) near -0.37 V on its own axis
|   POWER clamp passes 1 mA (typ) near -0.44 V on its own axis
|   rising waveform, R_fixture 50, V_fixture 0: 20-80 % time 86.8ps typ, 91.7ps min, 97.9ps max; typ from 0 V to 0.736 V
|   rising waveform, R_fixture 50, V_fixture 1.2: 20-80 % time 83.7ps typ, 85.2ps min, 91.8ps max; typ from 0.469 V to 1.2 V
|   falling waveform, R_fixture 50, V_fixture 0: 20-80 % time 76ps typ, 77.4ps min, 75.9ps max; typ from 0.736 V to 0 V
|   falling waveform, R_fixture 50, V_fixture 1.2: 20-80 % time 88.5ps typ, 94ps min, 89.2ps max; typ from 1.2 V to 0.469 V
[GND Clamp]
| Voltage   I(typ)   I(min)   I(max)
-984.4mV  -27.36mA   -20.85mA   -36.63mA
-708.7mV  -13.22mA   -10.27mA   -17.58mA
-630mV    -9.442mA   -7.443mA   -12.61mA
-551.3mV  -6.071mA   -4.927mA   -8.091mA
-472.5mV  -3.303mA   -2.86mA    -4.278mA
-433.1mV  -2.213mA   -2.035mA   -2.745mA
-393.7mV  -1.354mA   -1.365mA   -1.538mA
-354.4mV  -738.1uA   -853.7uA   -711.7uA
-315mV    -352.4uA   -492.8uA   -262uA
-157.5mV  -6.952uA   -25.53uA   -1.531uA
-39.38mV  -223.3nA   -1.393uA   -60.97nA
2.4V      0A         0A         0A
[POWER Clamp]
| Voltage   I(typ)   I(min)   I(max)
-1.2V     44.33mA    37.1mA     61.33mA
-1.063V   34.96mA    28.78mA    48.71mA
-905.6mV  24.47mA    19.99mA    33.89mA
-787.5mV  17.03mA    14mA       23.06mA
-669.4mV  10.26mA    8.667mA    13.03mA
-590.6mV  6.299mA    5.605mA    7.313mA
-551.3mV  4.569mA    4.255mA    4.935mA
-472.5mV  1.839mA    2.031mA    1.558mA
-433.1mV  941.2uA    1.22mA     654.9uA
-354.4mV  127.4uA    330.6uA    47.34uA
-236.2mV  2.462uA    44.69uA    773.7nA
2.4V      0A         0A         0A
[Pullup]
| Voltage   I(typ)   I(min)   I(max)
-1.2V     20.82mA    18.57mA    18.95mA
-748.1mV  18.12mA    17mA       16.46mA
-551.3mV  15.94mA    14.92mA    14.5mA
-433.1mV  13.63mA    12.84mA    12.22mA
675mV     -21.13mA   -20.2mA    -18.56mA
1.012V    -30.76mA   -29.2mA    -26.71mA
1.239V    -36.36mA   -34.05mA   -31.02mA
1.633V    -42.7mA    -39.2mA    -35.32mA
2.184V    -47.04mA   -42.79mA   -38.3mA
2.303V    -49.87mA   -43.34mA   -38.77mA
2.342V    -47.98mA   -43.51mA   -38.92mA
2.4V      -48.16mA   -43.76mA   -39.14mA
[Pulldown]
| Voltage   I(typ)   I(min)   I(max)
-1.2V     -26.66mA   -24.6mA    -18.73mA
-1.103V   -25.88mA   -24.86mA   -17.76mA
-1.024V   -22.18mA   -24.37mA   -17.2mA
-984.4mV  -21.11mA   -23.84mA   -16.95mA
-590.6mV  -16.3mA    -17.35mA   -13.95mA
-393.7mV  -12.47mA   -12.92mA   -11.05mA
412.5mV   12.95mA    13.18mA    11.65mA
675mV     20.26mA    20.26mA    18.42mA
900mV     25.53mA    24.77mA    23.56mA
1.125V    29.1mA     26.89mA    27.63mA
1.436V    30.8mA     27.84mA    30.18mA
2.4V      32.57mA    29.31mA    32.06mA
[Ramp]
dV/dt_r   0.441644/86.7812p  0.412599/91.6908p  0.439979/97.9235p
dV/dt_f   0.438311/88.4934p  0.41975/94.0339p  0.440023/89.152p
R_load = 50
[Rising Waveform]
R_fixture = 50
V_fixture = 0
V_fixture_min = 0
V_fixture_max = 0
| Time   V(typ)   V(min)   V(max)
0s        1.209uV    1.357uV    1.785uV
981ps     -686.2uV   -542.2uV   -7.156mV
1.158ns   -810.3uV   -640.3uV   616.7mV
1.301ns   14.68mV    -719.5uV   712.3mV
1.366ns   293.2mV    -755.5uV   722.2mV
1.504ns   694.3mV    -832uV     729.5mV
1.688ns   728.3mV    3.479mV    732mV
1.864ns   733.7mV    609.3mV    732.2mV
2.066ns   734.9mV    678.9mV    732.4mV
10ns      736.1mV    687.7mV    733.3mV
[Rising Waveform]
R_fixture = 50
V_fixture = 1.2
V_fixture_min = 1.14
V_fixture_max = 1.26
| Time   V(typ)   V(min)   V(max)
0s        469.5mV    440.4mV    526.6mV
926ps     470mV      440.6mV    531.8mV
1.067ns   470mV      440.6mV    1.125V
1.235ns   479.8mV    440.7mV    1.244V
1.284ns   645.7mV    440.7mV    1.249V
1.408ns   1.139V     440.7mV    1.255V
1.644ns   1.193V     463mV      1.258V
1.771ns   1.197V     1.012V     1.259V
1.971ns   1.198V     1.128V     1.259V
10ns      1.2V       1.14V      1.26V
[Falling Waveform]
R_fixture = 50
V_fixture = 0
V_fixture_min = 0
V_fixture_max = 0
| Time   V(typ)   V(min)   V(max)
0s        736.1mV    687.7mV    733.3mV
912ps     735.5mV    687.3mV    723.2mV
1.051ns   735.4mV    687.2mV    95.68mV
1.218ns   727.6mV    687.1mV    10.48mV
1.383ns   76.43mV    687.1mV    3.564mV
1.557ns   8.582mV    687mV      1.783mV
1.677ns   4.106mV    626.1mV    1.262mV
1.808ns   2.193mV    68.56mV    1.122mV
1.996ns   1.222mV    6.785mV    921.1uV
10ns      2.227uV    2.539uV    2.589uV
[Falling Waveform]
R_fixture = 50
V_fixture = 1.2
V_fixture_min = 1.14
V_fixture_max = 1.26
| Time   V(typ)   V(min)   V(max)
0s        1.2V       1.14V      1.26V
958ps     1.2V       1.141V     1.265V
1.117ns   1.201V     1.141V     629mV
1.291ns   1.182V     1.141V     537mV
1.417ns   610mV      1.141V     531.1mV
1.612ns   479mV      1.142V     528.8mV
1.704ns   474.6mV    1.111V     528.4mV
1.871ns   471.8mV    510.7mV    528mV
2.08ns    471mV      446.7mV    527.7mV
10ns      469.5mV    440.4mV    526.6mV
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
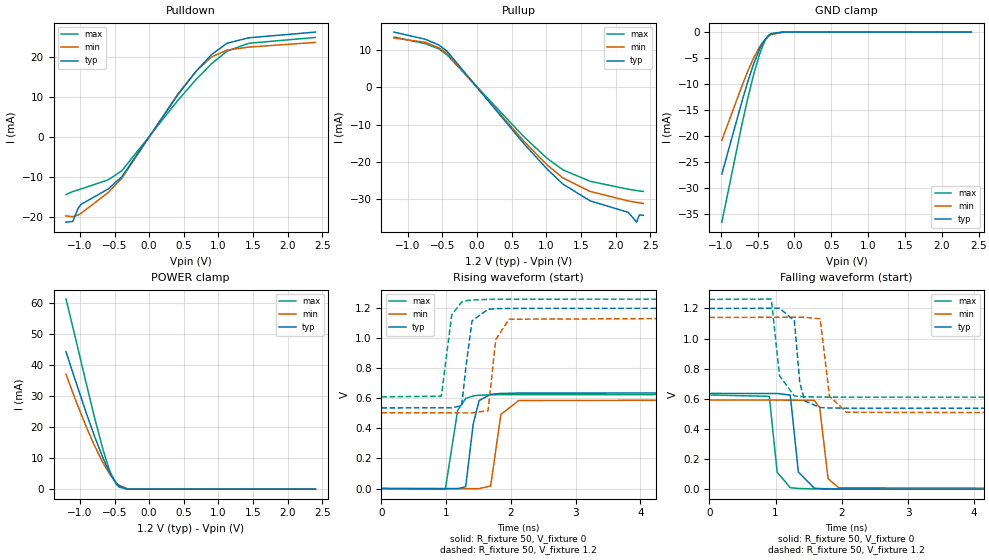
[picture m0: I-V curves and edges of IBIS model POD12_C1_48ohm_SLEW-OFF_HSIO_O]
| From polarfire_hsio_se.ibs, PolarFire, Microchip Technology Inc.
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|   Model POD12_C1_48ohm_SLEW-OFF_HSIO_O
[Model]   POD12_C1_48ohm_SLEW-OFF_HSIO_O
Model_type   Output
Polarity   Non-Inverting
Enable   Active-High
Vmeas =   0.84
Cref =   5p
Rref =   50
Vref =   0.84
|   typ   min   max
C_comp_pullup   1.335e-12   1.335e-12   1.380e-12
C_comp_pulldown  1.335e-12   1.335e-12   1.380e-12
[Temperature Range]  25C   100C   -40C
[Voltage Range]  1.2   1.14   1.26
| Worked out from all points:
|   slope of the pulldown table from 0 to 0.18 V, typ, clamps not added: 38.5 ohm
|   slope of the pullup table from 0 to 0.18 V, typ, clamps not added: 43.4 ohm
|   GND clamp passes 1 mA (typ) near -0.37 V on its own axis
|   POWER clamp passes 1 mA (typ) near -0.44 V on its own axis
|   rising waveform, R_fixture 50, V_fixture 0: 20-80 % time 104ps typ, 106ps min, 114ps max; typ from 0 V to 0.636 V
|   rising waveform, R_fixture 50, V_fixture 1.2: 20-80 % time 93.9ps typ, 90.2ps min, 101ps max; typ from 0.536 V to 1.2 V
|   falling waveform, R_fixture 50, V_fixture 0: 20-80 % time 71.8ps typ, 79.4ps min, 71.2ps max; typ from 0.636 V to 0 V
|   falling waveform, R_fixture 50, V_fixture 1.2: 20-80 % time 87.3ps typ, 95ps min, 86.4ps max; typ from 1.2 V to 0.536 V
[GND Clamp]
| Voltage   I(typ)   I(min)   I(max)
-984.4mV  -27.36mA   -20.85mA   -36.63mA
-708.7mV  -13.22mA   -10.27mA   -17.58mA
-630mV    -9.442mA   -7.443mA   -12.61mA
-551.3mV  -6.071mA   -4.927mA   -8.091mA
-472.5mV  -3.303mA   -2.86mA    -4.278mA
-433.1mV  -2.213mA   -2.035mA   -2.745mA
-393.7mV  -1.354mA   -1.365mA   -1.538mA
-354.4mV  -738.1uA   -853.7uA   -711.7uA
-315mV    -352.4uA   -492.8uA   -262uA
-157.5mV  -6.952uA   -25.53uA   -1.531uA
-39.38mV  -223.3nA   -1.393uA   -60.97nA
2.4V      0A         0A         0A
[POWER Clamp]
| Voltage   I(typ)   I(min)   I(max)
-1.2V     44.33mA    37.08mA    61.33mA
-1.063V   34.96mA    28.78mA    48.72mA
-905.6mV  24.47mA    19.99mA    33.89mA
-787.5mV  17.03mA    14mA       23.06mA
-669.4mV  10.26mA    8.667mA    13.03mA
-590.6mV  6.299mA    5.605mA    7.313mA
-551.3mV  4.569mA    4.255mA    4.935mA
-472.5mV  1.839mA    2.031mA    1.558mA
-433.1mV  941.2uA    1.284mA    654.9uA
-315mV    34.81uA    149.8uA    11.13uA
-236.2mV  2.462uA    44.69uA    773.7nA
2.4V      0A         0A         0A
[Pullup]
| Voltage   I(typ)   I(min)   I(max)
-1.2V     14.87mA    13.27mA    13.54mA
-748.1mV  12.95mA    12.14mA    11.76mA
-551.3mV  11.39mA    10.66mA    10.36mA
-433.1mV  9.734mA    9.145mA    8.728mA
675mV     -15.1mA    -14.43mA   -13.25mA
1.012V    -21.97mA   -20.86mA   -19.08mA
1.239V    -25.98mA   -24.32mA   -22.16mA
1.633V    -30.5mA    -27.98mA   -25.23mA
2.184V    -33.59mA   -30.53mA   -27.37mA
2.303V    -36.22mA   -30.89mA   -27.71mA
2.342V    -34.27mA   -31.01mA   -27.81mA
2.4V      -34.38mA   -31.18mA   -27.97mA
[Pulldown]
| Voltage   I(typ)   I(min)   I(max)
-1.2V     -21.42mA   -19.83mA   -14.5mA
-1.103V   -21.23mA   -20.03mA   -13.75mA
-1.024V   -17.93mA   -19.64mA   -13.32mA
-984.4mV  -16.97mA   -19.22mA   -13.12mA
-590.6mV  -13.11mA   -13.99mA   -10.8mA
-393.7mV  -10.03mA   -10.41mA   -8.552mA
412.5mV   10.41mA    10.62mA    9.025mA
675mV     16.29mA    16.32mA    14.26mA
900mV     20.52mA    19.95mA    18.24mA
1.125V    23.38mA    21.65mA    21.39mA
1.436V    24.73mA    22.4mA     23.36mA
2.4V      26.16mA    23.59mA    24.82mA
[Ramp]
dV/dt_r   0.381439/0.10407n  0.354986/0.105567n  0.375185/0.113944n
dV/dt_f   0.398258/87.2498p  0.381665/95.0046p  0.390144/86.4271p
R_load = 50
[Rising Waveform]
R_fixture = 50
V_fixture = 0
V_fixture_min = 0
V_fixture_max = 0
| Time   V(typ)   V(min)   V(max)
0s        1.192uV    1.392uV    1.766uV
987ps     -787.6uV   -478uV     -4.285mV
1.177ns   -939.4uV   -570.3uV   520mV
1.301ns   11.87mV    -630.5uV   599mV
1.417ns   428.7mV    -686.8uV   615.9mV
1.509ns   585mV      -731.5uV   620.5mV
1.686ns   626mV      17.01mV    623.5mV
1.845ns   632.6mV    492.7mV    624.3mV
2.119ns   634.7mV    585.2mV    624.4mV
10ns      635.7mV    591.6mV    625.3mV
[Rising Waveform]
R_fixture = 50
V_fixture = 1.2
V_fixture_min = 1.14
V_fixture_max = 1.26
| Time   V(typ)   V(min)   V(max)
0s        536.2mV    503.9mV    609.8mV
925ps     536.8mV    503.3mV    613.9mV
1.085ns   536.9mV    503.2mV    1.154V
1.239ns   551.1mV    503.1mV    1.241V
1.307ns   816mV      503mV      1.249V
1.399ns   1.115V     503mV      1.254V
1.647ns   1.192V     517.5mV    1.258V
1.766ns   1.196V     990.9mV    1.259V
1.97ns    1.198V     1.126V     1.259V
10ns      1.2V       1.14V      1.26V
[Falling Waveform]
R_fixture = 50
V_fixture = 0
V_fixture_min = 0
V_fixture_max = 0
| Time   V(typ)   V(min)   V(max)
0s        635.7mV    591.6mV    625.3mV
905ps     635.2mV    591.1mV    616.2mV
1.024ns   635.1mV    591.1mV    112.7mV
1.222ns   624.4mV    591mV      9.826mV
1.344ns   113.8mV    590.9mV    4.557mV
1.583ns   6.861mV    589.3mV    1.544mV
1.666ns   4.297mV    543.1mV    1.226mV
1.793ns   2.27mV     69.25mV    1.01mV
1.955ns   1.293mV    9.449mV    736.1uV
10ns      2.225uV    2.73uV     2.421uV
[Falling Waveform]
R_fixture = 50
V_fixture = 1.2
V_fixture_min = 1.14
V_fixture_max = 1.26
| Time   V(typ)   V(min)   V(max)
0s        1.2V       1.14V      1.26V
936ps     1.201V     1.141V     1.262V
1.06ns    1.201V     1.141V     752.2mV
1.284ns   1.118V     1.141V     619mV
1.366ns   707mV      1.141V     615.4mV
1.439ns   586.8mV    1.141V     613.2mV
1.673ns   541.8mV    1.131V     611.5mV
1.814ns   538.9mV    618.1mV    611.3mV
2.072ns   537.6mV    510.2mV    610.8mV
10ns      536.2mV    503.9mV    609.8mV
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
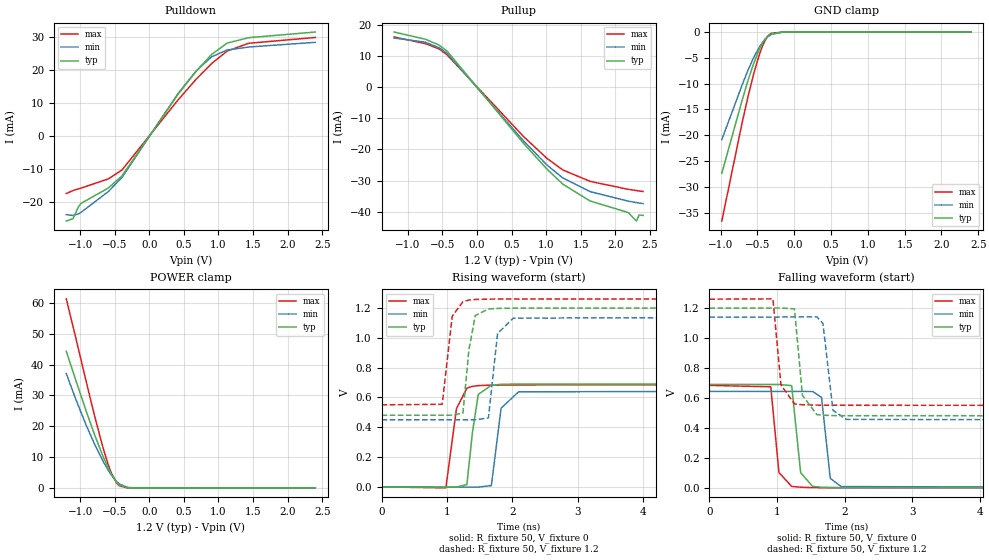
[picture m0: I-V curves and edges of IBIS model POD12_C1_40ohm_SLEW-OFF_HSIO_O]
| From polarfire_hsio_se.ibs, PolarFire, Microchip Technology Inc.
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|   Model POD12_C1_40ohm_SLEW-OFF_HSIO_O
[Model]   POD12_C1_40ohm_SLEW-OFF_HSIO_O
Model_type   Output
Polarity   Non-Inverting
Enable   Active-High
Vmeas =   0.84
Cref =   5p
Rref =   50
Vref =   0.84
|   typ   min   max
C_comp_pullup   1.335e-12   1.335e-12   1.380e-12
C_comp_pulldown  1.335e-12   1.335e-12   1.380e-12
[Temperature Range]  25C   100C   -40C
[Voltage Range]  1.2   1.14   1.26
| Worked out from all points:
|   slope of the pulldown table from 0 to 0.18 V, typ, clamps not added: 32.1 ohm
|   slope of the pullup table from 0 to 0.18 V, typ, clamps not added: 36.2 ohm
|   GND clamp passes 1 mA (typ) near -0.37 V on its own axis
|   POWER clamp passes 1 mA (typ) near -0.44 V on its own axis
|   rising waveform, R_fixture 50, V_fixture 0: 20-80 % time 94.8ps typ, 95.9ps min, 106ps max; typ from 0 V to 0.691 V
|   rising waveform, R_fixture 50, V_fixture 1.2: 20-80 % time 88.1ps typ, 85.1ps min, 95ps max; typ from 0.48 V to 1.2 V
|   falling waveform, R_fixture 50, V_fixture 0: 20-80 % time 66.1ps typ, 72.7ps min, 66.2ps max; typ from 0.691 V to 0 V
|   falling waveform, R_fixture 50, V_fixture 1.2: 20-80 % time 78.1ps typ, 85.3ps min, 77.2ps max; typ from 1.2 V to 0.48 V
[GND Clamp]
| Voltage   I(typ)   I(min)   I(max)
-984.4mV  -27.36mA   -20.85mA   -36.63mA
-708.7mV  -13.22mA   -10.27mA   -17.58mA
-630mV    -9.442mA   -7.443mA   -12.61mA
-551.3mV  -6.071mA   -4.927mA   -8.091mA
-472.5mV  -3.303mA   -2.86mA    -4.278mA
-433.1mV  -2.213mA   -2.035mA   -2.745mA
-393.7mV  -1.354mA   -1.365mA   -1.538mA
-354.4mV  -738.1uA   -853.7uA   -711.7uA
-315mV    -352.4uA   -492.8uA   -262uA
-157.5mV  -6.952uA   -25.53uA   -1.531uA
-39.38mV  -223.3nA   -1.393uA   -60.97nA
2.4V      0A         0A         0A
[POWER Clamp]
| Voltage   I(typ)   I(min)   I(max)
-1.2V     44.33mA    37.08mA    61.33mA
-1.063V   34.96mA    28.78mA    48.72mA
-905.6mV  24.47mA    19.99mA    33.89mA
-787.5mV  17.03mA    14mA       23.06mA
-669.4mV  10.26mA    8.667mA    13.03mA
-590.6mV  6.299mA    5.605mA    7.313mA
-551.3mV  4.569mA    4.255mA    4.935mA
-472.5mV  1.839mA    2.031mA    1.558mA
-433.1mV  941.2uA    1.284mA    654.9uA
-315mV    34.81uA    149.8uA    11.13uA
-236.2mV  2.462uA    44.69uA    773.7nA
2.4V      0A         0A         0A
[Pullup]
| Voltage   I(typ)   I(min)   I(max)
-1.2V     17.84mA    15.92mA    16.25mA
-748.1mV  15.53mA    14.57mA    14.11mA
-551.3mV  13.66mA    12.79mA    12.43mA
-433.1mV  11.68mA    10.97mA    10.48mA
675mV     -18.11mA   -17.31mA   -15.91mA
1.012V    -26.36mA   -25.03mA   -22.9mA
1.239V    -31.17mA   -29.19mA   -26.59mA
1.633V    -36.59mA   -33.58mA   -30.27mA
2.184V    -40.31mA   -36.64mA   -32.83mA
2.303V    -43.05mA   -37.09mA   -33.23mA
2.342V    -41.13mA   -37.23mA   -33.36mA
2.4V      -41.25mA   -37.44mA   -33.54mA
[Pulldown]
| Voltage   I(typ)   I(min)   I(max)
-1.2V     -25.71mA   -23.79mA   -17.39mA
-1.103V   -25.01mA   -24.04mA   -16.5mA
-1.024V   -21.4mA    -23.56mA   -15.98mA
-984.4mV  -20.35mA   -23.06mA   -15.74mA
-590.6mV  -15.72mA   -16.78mA   -12.96mA
-393.7mV  -12.03mA   -12.49mA   -10.26mA
412.5mV   12.49mA    12.74mA    10.82mA
675mV     19.54mA    19.58mA    17.11mA
900mV     24.63mA    23.94mA    21.88mA
1.125V    28.08mA    25.99mA    25.66mA
1.436V    29.72mA    26.9mA     28.03mA
2.4V      31.43mA    28.32mA    29.78mA
[Ramp]
dV/dt_r   0.414403/94.7878p  0.386481/95.939p  0.410553/0.105657n
dV/dt_f   0.431775/78.0534p  0.4139/85.3276p  0.425802/77.1715p
R_load = 50
[Rising Waveform]
R_fixture = 50
V_fixture = 0
V_fixture_min = 0
V_fixture_max = 0
| Time   V(typ)   V(min)   V(max)
0s        1.206uV    1.362uV    1.779uV
982ps     -625.3uV   -545uV     -5.917mV
1.144ns   -728.6uV   -635.2uV   525mV
1.303ns   15.8mV     -723.6uV   661.6mV
1.388ns   364.9mV    -770.9uV   674mV
1.477ns   620.1mV    -820.4uV   678.9mV
1.677ns   681.2mV    9.029mV    682.6mV
1.826ns   687.4mV    527.8mV    683.1mV
2.093ns   689.6mV    637.4mV    683.5mV
10ns      690.7mV    644.1mV    684.3mV
[Rising Waveform]
R_fixture = 50
V_fixture = 1.2
V_fixture_min = 1.14
V_fixture_max = 1.26
| Time   V(typ)   V(min)   V(max)
0s        480.4mV    450.1mV    550.3mV
926ps     480.7mV    450.2mV    553.8mV
1.079ns   480.8mV    450.2mV    1.143V
1.243ns   495.2mV    450.2mV    1.242V
1.334ns   918.4mV    450.2mV    1.252V
1.431ns   1.148V     450.2mV    1.256V
1.632ns   1.192V     462.1mV    1.258V
1.772ns   1.196V     1.028V     1.259V
2.012ns   1.198V     1.131V     1.259V
10ns      1.2V       1.14V      1.26V
[Falling Waveform]
R_fixture = 50
V_fixture = 0
V_fixture_min = 0
V_fixture_max = 0
| Time   V(typ)   V(min)   V(max)
0s        690.7mV    644.1mV    684.3mV
908ps     690.3mV    643.7mV    674.9mV
1.029ns   690.2mV    643.7mV    102.2mV
1.217ns   682.7mV    643.6mV    9.656mV
1.35ns    101.2mV    643.6mV    4.232mV
1.527ns   9.647mV    643.5mV    1.762mV
1.659ns   4.068mV    603.7mV    1.233mV
1.788ns   2.215mV    63.09mV    990.4uV
1.95ns    1.351mV    8.463mV    778.8uV
10ns      -1.008uV   2.532uV    2.459uV
[Falling Waveform]
R_fixture = 50
V_fixture = 1.2
V_fixture_min = 1.14
V_fixture_max = 1.26
| Time   V(typ)   V(min)   V(max)
0s        1.2V       1.14V      1.26V
940ps     1.201V     1.14V      1.262V
1.059ns   1.201V     1.141V     687.3mV
1.259ns   1.195V     1.141V     560.5mV
1.376ns   618.3mV    1.141V     555mV
1.59ns    488.8mV    1.142V     552.5mV
1.68ns    485mV      1.097V     552mV
1.828ns   482.7mV    517.3mV    551.6mV
2.026ns   482mV      457.1mV    551.4mV
10ns      480.4mV    450.1mV    550.3mV
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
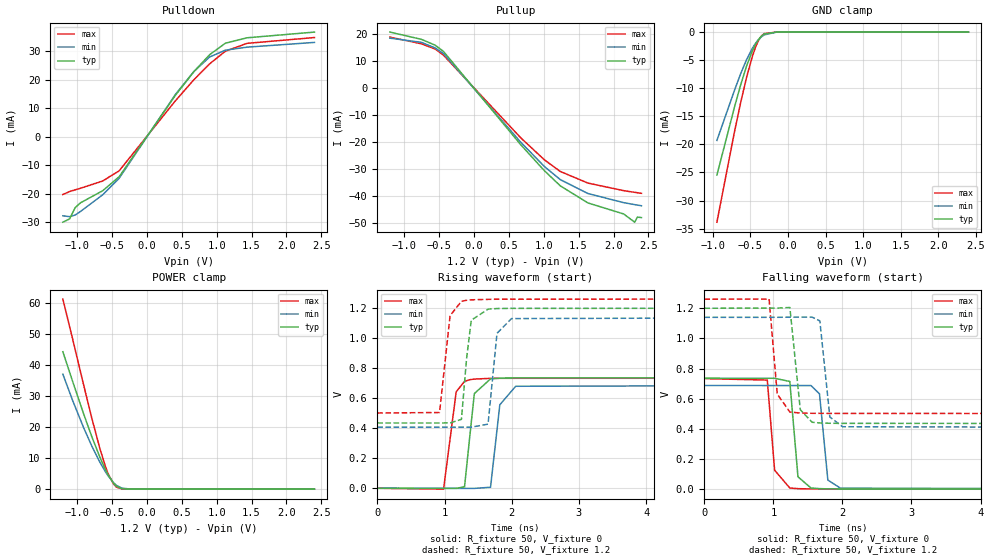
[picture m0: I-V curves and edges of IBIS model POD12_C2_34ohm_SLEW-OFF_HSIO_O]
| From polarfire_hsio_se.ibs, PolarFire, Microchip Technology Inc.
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|   Model POD12_C2_34ohm_SLEW-OFF_HSIO_O
[Model]   POD12_C2_34ohm_SLEW-OFF_HSIO_O
Model_type   Output
Polarity   Non-Inverting
Enable   Active-High
Vmeas =   0.84
Cref =   5p
Rref =   50
Vref =   0.84
|   typ   min   max
C_comp_pullup   1.335e-12   1.335e-12   1.380e-12
C_comp_pulldown  1.335e-12   1.335e-12   1.380e-12
[Temperature Range]  25C   100C   -40C
[Voltage Range]  1.2   1.14   1.26
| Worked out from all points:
|   slope of the pulldown table from 0 to 0.18 V, typ, clamps not added: 27.5 ohm
|   slope of the pullup table from 0 to 0.18 V, typ, clamps not added: 31 ohm
|   GND clamp passes 1 mA (typ) near -0.37 V on its own axis
|   POWER clamp passes 1 mA (typ) near -0.44 V on its own axis
|   rising waveform, R_fixture 50, V_fixture 0: 20-80 % time 88.1ps typ, 87.7ps min, 97.8ps max; typ from 0 V to 0.736 V
|   rising waveform, R_fixture 50, V_fixture 1.2: 20-80 % time 79.7ps typ, 79.5ps min, 90.4ps max; typ from 0.435 V to 1.2 V
|   falling waveform, R_fixture 50, V_fixture 0: 20-80 % time 61.7ps typ, 68.1ps min, 60.3ps max; typ from 0.736 V to 0 V
|   falling waveform, R_fixture 50, V_fixture 1.2: 20-80 % time 71.9ps typ, 79.5ps min, 71.7ps max; typ from 1.2 V to 0.435 V
[GND Clamp]
| Voltage   I(typ)   I(min)   I(max)
-945mV    -25.45mA   -19.29mA   -33.85mA
-708.7mV  -13.22mA   -10.27mA   -17.58mA
-630mV    -9.442mA   -7.443mA   -12.61mA
-551.3mV  -6.071mA   -4.927mA   -8.091mA
-472.5mV  -3.303mA   -2.86mA    -4.278mA
-433.1mV  -2.213mA   -2.035mA   -2.745mA
-393.7mV  -1.354mA   -1.365mA   -1.538mA
-354.4mV  -738.1uA   -853.7uA   -711.7uA
-315mV    -352.4uA   -492.8uA   -262uA
-157.5mV  -6.952uA   -25.53uA   -1.531uA
-39.38mV  -223.3nA   -1.393uA   -60.97nA
2.4V      0A         0A         0A
[POWER Clamp]
| Voltage   I(typ)   I(min)   I(max)
-1.2V     44.33mA    37.1mA     61.33mA
-1.063V   34.96mA    28.78mA    48.71mA
-905.6mV  24.47mA    19.99mA    33.89mA
-787.5mV  17.03mA    14mA       23.06mA
-669.4mV  10.26mA    8.667mA    13.03mA
-590.6mV  6.299mA    5.605mA    7.313mA
-551.3mV  4.569mA    4.255mA    4.935mA
-472.5mV  1.839mA    2.031mA    1.558mA
-433.1mV  941.2uA    1.22mA     654.9uA
-354.4mV  127.4uA    330.6uA    47.34uA
-236.2mV  2.462uA    44.69uA    773.7nA
2.4V      0A         0A         0A
[Pullup]
| Voltage   I(typ)   I(min)   I(max)
-1.2V     20.82mA    18.57mA    18.95mA
-748.1mV  18.12mA    17mA       16.46mA
-551.3mV  15.94mA    14.92mA    14.5mA
-433.1mV  13.63mA    12.84mA    12.22mA
675mV     -21.13mA   -20.2mA    -18.56mA
1.012V    -30.76mA   -29.2mA    -26.71mA
1.239V    -36.36mA   -34.05mA   -31.02mA
1.633V    -42.7mA    -39.2mA    -35.32mA
2.145V    -46.81mA   -42.6mA    -38.14mA
2.303V    -49.87mA   -43.34mA   -38.77mA
2.342V    -47.98mA   -43.51mA   -38.92mA
2.4V      -48.16mA   -43.76mA   -39.14mA
[Pulldown]
| Voltage   I(typ)   I(min)   I(max)
-1.2V     -29.99mA   -27.75mA   -20.29mA
-1.103V   -28.83mA   -28.04mA   -19.25mA
-1.024V   -24.89mA   -27.49mA   -18.64mA
-945mV    -23.16mA   -26.19mA   -18.09mA
-630mV    -18.97mA   -20.38mA   -15.54mA
-393.7mV  -14.03mA   -14.57mA   -11.97mA
412.5mV   14.56mA    14.86mA    12.63mA
675mV     22.79mA    22.83mA    19.95mA
900mV     28.72mA    27.92mA    25.52mA
1.125V    32.74mA    30.31mA    29.94mA
1.436V    34.65mA    31.37mA    32.7mA
2.4V      36.65mA    33.03mA    34.74mA
[Ramp]
dV/dt_r   0.441646/88.149p  0.412599/87.744p  0.439979/97.8146p
dV/dt_f   0.459061/71.9289p  0.439931/79.4875p  0.455281/71.7347p
R_load = 50
[Rising Waveform]
R_fixture = 50
V_fixture = 0
V_fixture_min = 0
V_fixture_max = 0
| Time   V(typ)   V(min)   V(max)
0s        1.218uV    1.339uV    1.79uV
986ps     -475.8uV   -567.5uV   -5.957mV
1.174ns   -566.8uV   -675.9uV   642.6mV
1.298ns   9.89mV     -747.4uV   711.7mV
1.372ns   327.4mV    -790.1uV   722.5mV
1.444ns   630.4mV    -831.7uV   727.2mV
1.685ns   728.4mV    6.789mV    732mV
1.823ns   733.2mV    556.1mV    732.1mV
2.059ns   734.9mV    679.3mV    732.4mV
10ns      736.1mV    687.7mV    733.3mV
[Rising Waveform]
R_fixture = 50
V_fixture = 1.2
V_fixture_min = 1.14
V_fixture_max = 1.26
| Time   V(typ)   V(min)   V(max)
0s        434.9mV    406.8mV    501.2mV
926ps     435mV      406.9mV    504.5mV
1.083ns   435mV      406.9mV    1.15V
1.252ns   458.8mV    406.9mV    1.245V
1.328ns   862.3mV    406.9mV    1.252V
1.398ns   1.119V     406.9mV    1.255V
1.648ns   1.193V     427mV      1.258V
1.781ns   1.197V     1.032V     1.259V
1.997ns   1.198V     1.13V      1.259V
10ns      1.2V       1.14V      1.26V
[Falling Waveform]
R_fixture = 50
V_fixture = 0
V_fixture_min = 0
V_fixture_max = 0
| Time   V(typ)   V(min)   V(max)
0s        736.1mV    687.7mV    733.3mV
912ps     735.6mV    687.4mV    723.7mV
1.018ns   735.5mV    687.4mV    125.6mV
1.238ns   714.4mV    687.3mV    7.597mV
1.356ns   81.95mV    687.3mV    3.365mV
1.545ns   7.558mV    687.3mV    1.561mV
1.668ns   3.517mV    632.2mV    1.233mV
1.789ns   2.094mV    60.13mV    1.078mV
1.972ns   1.197mV    6.599mV    844.6uV
10ns      1.248uV    2.426uV    2.598uV
[Falling Waveform]
R_fixture = 50
V_fixture = 1.2
V_fixture_min = 1.14
V_fixture_max = 1.26
| Time   V(typ)   V(min)   V(max)
0s        1.2V       1.14V      1.26V
938ps     1.201V     1.14V      1.261V
1.056ns   1.201V     1.14V      630.3mV
1.239ns   1.205V     1.141V     511.9mV
1.39ns    526.9mV    1.141V     505.1mV
1.562ns   443.7mV    1.141V     503.3mV
1.673ns   439.2mV    1.116V     502.9mV
1.818ns   437.1mV    478.5mV    502.6mV
2.004ns   436.5mV    414mV      502.3mV
10ns      434.9mV    406.8mV    501.2mV
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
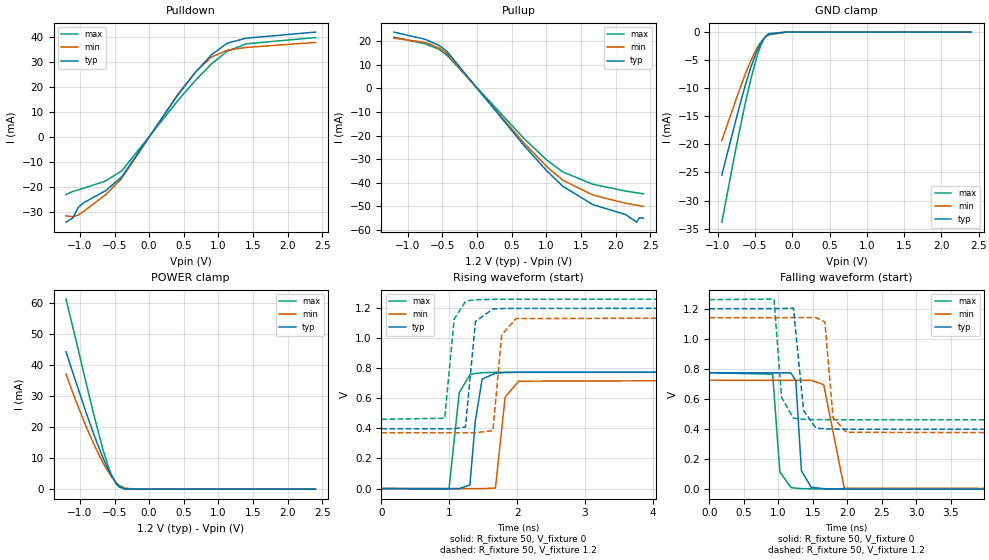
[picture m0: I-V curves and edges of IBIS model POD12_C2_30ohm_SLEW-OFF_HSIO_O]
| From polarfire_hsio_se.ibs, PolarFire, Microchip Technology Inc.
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|   Model POD12_C2_30ohm_SLEW-OFF_HSIO_O
[Model]   POD12_C2_30ohm_SLEW-OFF_HSIO_O
Model_type   Output
Polarity   Non-Inverting
Enable   Active-High
Vmeas =   0.84
Cref =   5p
Rref =   50
Vref =   0.84
|   typ   min   max
C_comp_pullup   1.335e-12   1.335e-12   1.380e-12
C_comp_pulldown  1.335e-12   1.335e-12   1.380e-12
[Temperature Range]  25C   100C   -40C
[Voltage Range]  1.2   1.14   1.26
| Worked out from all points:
|   slope of the pulldown table from 0 to 0.18 V, typ, clamps not added: 24.1 ohm
|   slope of the pullup table from 0 to 0.18 V, typ, clamps not added: 27.2 ohm
|   GND clamp passes 1 mA (typ) near -0.37 V on its own axis
|   POWER clamp passes 1 mA (typ) near -0.44 V on its own axis
|   rising waveform, R_fixture 50, V_fixture 0: 20-80 % time 81.6ps typ, 82.9ps min, 91.1ps max; typ from 0 V to 0.774 V
|   rising waveform, R_fixture 50, V_fixture 1.2: 20-80 % time 78.3ps typ, 74.8ps min, 87.6ps max; typ from 0.397 V to 1.2 V
|   falling waveform, R_fixture 50, V_fixture 0: 20-80 % time 57.3ps typ, 63.8ps min, 56.8ps max; typ from 0.774 V to 0 V
|   falling waveform, R_fixture 50, V_fixture 1.2: 20-80 % time 67.4ps typ, 74.5ps min, 66.4ps max; typ from 1.2 V to 0.397 V
[GND Clamp]
| Voltage   I(typ)   I(min)   I(max)
-945mV    -25.45mA   -19.29mA   -33.85mA
-787.5mV  -17.26mA   -13.26mA   -22.85mA
-708.7mV  -13.22mA   -10.27mA   -17.58mA
-630mV    -9.442mA   -7.443mA   -12.61mA
-551.3mV  -6.071mA   -4.927mA   -8.091mA
-472.5mV  -3.303mA   -2.86mA    -4.278mA
-433.1mV  -2.213mA   -2.035mA   -2.745mA
-393.7mV  -1.354mA   -1.365mA   -1.538mA
-354.4mV  -738.1uA   -853.7uA   -711.7uA
-315mV    -352.4uA   -492.8uA   -262uA
-78.75mV  -756.1nA   -4.234uA   -137.7nA
2.4V      0A         0A         0A
[POWER Clamp]
| Voltage   I(typ)   I(min)   I(max)
-1.2V     44.33mA    37.1mA     61.33mA
-1.063V   34.96mA    28.78mA    48.71mA
-905.6mV  24.47mA    19.99mA    33.89mA
-787.5mV  17.03mA    14mA       23.06mA
-669.4mV  10.26mA    8.667mA    13.03mA
-590.6mV  6.299mA    5.605mA    7.313mA
-551.3mV  4.569mA    4.255mA    4.935mA
-472.5mV  1.839mA    2.031mA    1.558mA
-433.1mV  941.2uA    1.22mA     654.9uA
-354.4mV  127.4uA    354.9uA    47.34uA
-196.9mV  963.6nA    14.11uA    668.3nA
2.4V      0A         0A         0A
[Pullup]
| Voltage   I(typ)   I(min)   I(max)
-1.2V     23.79mA    21.22mA    21.66mA
-748.1mV  20.71mA    19.42mA    18.81mA
-551.3mV  18.21mA    17.06mA    16.57mA
-433.1mV  15.57mA    14.67mA    13.96mA
675mV     -24.15mA   -23.08mA   -21.21mA
1.012V    -35.15mA   -33.37mA   -30.52mA
1.239V    -41.55mA   -38.96mA   -35.45mA
1.673V    -49.28mA   -45.19mA   -40.66mA
2.145V    -53.49mA   -48.68mA   -43.53mA
2.303V    -56.7mA    -49.52mA   -44.25mA
2.342V    -54.83mA   -49.72mA   -44.43mA
2.4V      -55.03mA   -50mA      -44.68mA
[Pulldown]
| Voltage   I(typ)   I(min)   I(max)
-1.2V     -34.26mA   -31.72mA   -23.18mA
-1.103V   -32.62mA   -32.05mA   -21.99mA
-1.024V   -28.36mA   -31.41mA   -21.3mA
-945mV    -26.45mA   -29.93mA   -20.67mA
-630mV    -21.68mA   -23.29mA   -17.76mA
-393.7mV  -16.03mA   -16.65mA   -13.67mA
412.5mV   16.64mA    16.98mA    14.42mA
675mV     26.04mA    26.1mA     22.79mA
900mV     32.82mA    31.92mA    29.15mA
1.125V    37.43mA    34.65mA    34.2mA
1.397V    39.46mA    35.75mA    37.18mA
2.4V      41.91mA    37.76mA    39.72mA
[Ramp]
dV/dt_r   0.464353/81.5672p  0.434421/82.9089p  0.464717/91.1164p
dV/dt_f   0.481633/67.3724p  0.461539/74.5372p  0.479762/66.3988p
R_load = 50
[Rising Waveform]
R_fixture = 50
V_fixture = 0
V_fixture_min = 0
V_fixture_max = 0
| Time   V(typ)   V(min)   V(max)
0s        1.228uV    1.319uV    1.798uV
996ps     -660.8uV   -426.3uV   -4.253mV
1.147ns   -761.2uV   -491.1uV   637.4mV
1.304ns   23.53mV    -558.5uV   755.7mV
1.385ns   452.3mV    -593.2uV   765.8mV
1.486ns   728.5mV    -636.6uV   770.3mV
1.681ns   766.9mV    3.032mV    773mV
1.824ns   771.3mV    608.3mV    773.6mV
2.023ns   772.9mV    713.9mV    773.9mV
10ns      773.9mV    724mV      774.5mV
[Rising Waveform]
R_fixture = 50
V_fixture = 1.2
V_fixture_min = 1.14
V_fixture_max = 1.26
| Time   V(typ)   V(min)   V(max)
0s        397.3mV    370.7mV    460.4mV
933ps     397.6mV    371mV      467.3mV
1.072ns   397.7mV    371mV      1.126V
1.239ns   409.7mV    371.1mV    1.244V
1.312ns   758.7mV    371.1mV    1.252V
1.386ns   1.111V     371.1mV    1.255V
1.643ns   1.194V     385.1mV    1.258V
1.774ns   1.197V     1.022V     1.259V
1.984ns   1.198V     1.13V      1.259V
10ns      1.2V       1.14V      1.26V
[Falling Waveform]
R_fixture = 50
V_fixture = 0
V_fixture_min = 0
V_fixture_max = 0
| Time   V(typ)   V(min)   V(max)
0s        773.9mV    724mV      774.5mV
918ps     773.2mV    723.7mV    764.3mV
1.022ns   773.1mV    723.7mV    114.8mV
1.182ns   773mV      723.6mV    11.35mV
1.253ns   721.6mV    723.6mV    6.546mV
1.335ns   120.8mV    723.6mV    3.786mV
1.479ns   11.79mV    723.5mV    1.999mV
1.658ns   3.472mV    694.8mV    1.255mV
1.955ns   1.153mV    6.909mV    723uV
10ns      330.5nV    2.486uV    2.49uV
[Falling Waveform]
R_fixture = 50
V_fixture = 1.2
V_fixture_min = 1.14
V_fixture_max = 1.26
| Time   V(typ)   V(min)   V(max)
0s        1.2V       1.14V      1.26V
937ps     1.201V     1.14V      1.264V
1.047ns   1.201V     1.14V      610.9mV
1.219ns   1.204V     1.141V     471.9mV
1.366ns   522.7mV    1.141V     464.5mV
1.544ns   406.6mV    1.141V     462.4mV
1.674ns   401.1mV    1.112V     462.1mV
1.793ns   399.5mV    475.4mV    461.9mV
1.989ns   398.7mV    378.1mV    461.4mV
10ns      397.3mV    370.7mV    460.4mV
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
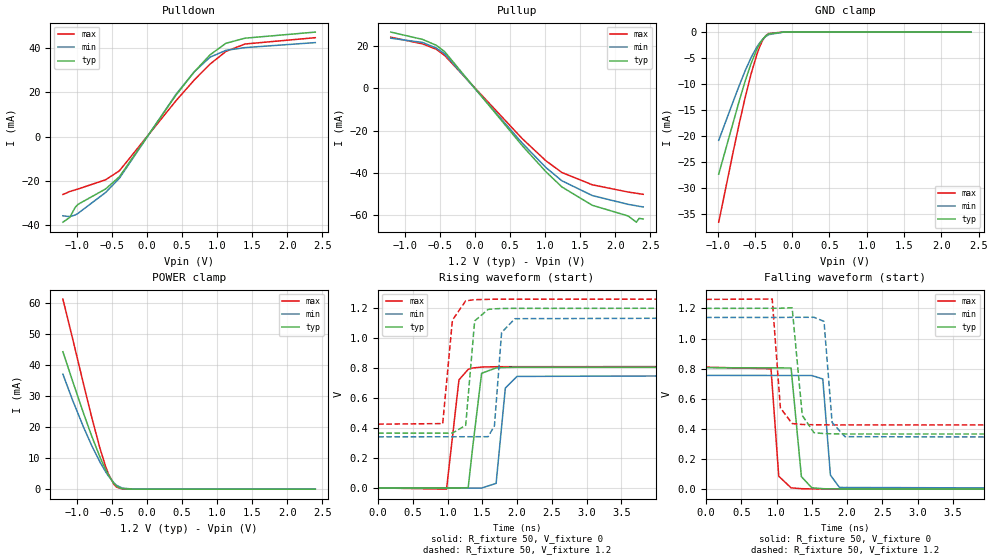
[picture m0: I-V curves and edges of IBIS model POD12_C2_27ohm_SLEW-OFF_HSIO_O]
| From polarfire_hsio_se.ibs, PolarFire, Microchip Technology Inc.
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|   Model POD12_C2_27ohm_SLEW-OFF_HSIO_O
[Model]   POD12_C2_27ohm_SLEW-OFF_HSIO_O
Model_type   Output
Polarity   Non-Inverting
Enable   Active-High
Vmeas =   0.84
Cref =   5p
Rref =   50
Vref =   0.84
|   typ   min   max
C_comp_pullup   1.335e-12   1.335e-12   1.380e-12
C_comp_pulldown  1.335e-12   1.335e-12   1.380e-12
[Temperature Range]  25C   100C   -40C
[Voltage Range]  1.2   1.14   1.26
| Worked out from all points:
|   slope of the pulldown table from 0 to 0.18 V, typ, clamps not added: 21.4 ohm
|   slope of the pullup table from 0 to 0.18 V, typ, clamps not added: 24.1 ohm
|   GND clamp passes 1 mA (typ) near -0.37 V on its own axis
|   POWER clamp passes 1 mA (typ) near -0.44 V on its own axis
|   rising waveform, R_fixture 50, V_fixture 0: 20-80 % time 76.6ps typ, 77.1ps min, 85.8ps max; typ from 0 V to 0.806 V
|   rising waveform, R_fixture 50, V_fixture 1.2: 20-80 % time 76.7ps typ, 68.9ps min, 83.6ps max; typ from 0.365 V to 1.2 V
|   falling waveform, R_fixture 50, V_fixture 0: 20-80 % time 53.4ps typ, 60.7ps min, 52.2ps max; typ from 0.806 V to 0 V
|   falling waveform, R_fixture 50, V_fixture 1.2: 20-80 % time 63.3ps typ, 68.6ps min, 62.5ps max; typ from 1.2 V to 0.365 V
[GND Clamp]
| Voltage   I(typ)   I(min)   I(max)
-984.4mV  -27.36mA   -20.85mA   -36.63mA
-787.5mV  -17.26mA   -13.26mA   -22.85mA
-708.7mV  -13.22mA   -10.27mA   -17.58mA
-630mV    -9.442mA   -7.443mA   -12.61mA
-551.3mV  -6.071mA   -4.927mA   -8.091mA
-472.5mV  -3.303mA   -2.86mA    -4.278mA
-433.1mV  -2.213mA   -2.035mA   -2.745mA
-393.7mV  -1.354mA   -1.365mA   -1.538mA
-354.4mV  -738.1uA   -853.7uA   -711.7uA
-315mV    -352.4uA   -492.8uA   -262uA
-118.1mV  -2.32uA    -10.66uA   -418.9nA
2.4V      0A         0A         0A
[POWER Clamp]
| Voltage   I(typ)   I(min)   I(max)
-1.2V     44.33mA    37.1mA     61.33mA
-1.063V   34.96mA    28.78mA    48.71mA
-905.6mV  24.47mA    19.99mA    33.89mA
-787.5mV  17.03mA    14mA       23.06mA
-669.4mV  10.26mA    8.667mA    13.03mA
-590.6mV  6.299mA    5.605mA    7.313mA
-551.3mV  4.569mA    4.255mA    4.935mA
-472.5mV  1.839mA    2.031mA    1.558mA
-433.1mV  941.2uA    1.22mA     654.9uA
-354.4mV  127.4uA    354.9uA    47.34uA
-196.9mV  963.6nA    14.11uA    668.3nA
2.4V      0A         0A         0A
[Pullup]
| Voltage   I(typ)   I(min)   I(max)
-1.2V     26.77mA    23.87mA    24.36mA
-748.1mV  23.3mA     21.85mA    21.16mA
-551.3mV  20.49mA    19.19mA    18.64mA
-433.1mV  17.52mA    16.5mA     15.71mA
675mV     -27.17mA   -25.96mA   -23.85mA
1.012V    -39.54mA   -37.54mA   -34.33mA
1.239V    -46.74mA   -43.82mA   -39.88mA
1.673V    -55.47mA   -50.84mA   -45.74mA
2.184V    -60.54mA   -55.02mA   -49.17mA
2.303V    -63.5mA    -55.72mA   -49.77mA
2.342V    -61.68mA   -55.95mA   -49.97mA
2.4V      -62mA      -56.26mA   -50.25mA
[Pulldown]
| Voltage   I(typ)   I(min)   I(max)
-1.2V     -38.56mA   -35.68mA   -26.07mA
-1.103V   -36.42mA   -36.05mA   -24.74mA
-1.024V   -31.85mA   -35.33mA   -23.96mA
-984.4mV  -30.51mA   -34.57mA   -23.6mA
-590.6mV  -23.57mA   -25.16mA   -19.42mA
-393.7mV  -18.03mA   -18.72mA   -15.37mA
412.5mV   18.73mA    19.1mA     16.21mA
675mV     29.31mA    29.34mA    25.63mA
900mV     36.95mA    35.89mA    32.79mA
1.125V    42.14mA    38.95mA    38.47mA
1.397V    44.44mA    40.19mA    41.81mA
2.4V      47.19mA    42.45mA    44.67mA
[Ramp]
dV/dt_r   0.483708/76.5964p  0.453064/77.0505p  0.485937/85.8294p
dV/dt_f   0.500829/63.301p  0.47947/68.5917p  0.500773/62.5235p
R_load = 50
[Rising Waveform]
R_fixture = 50
V_fixture = 0
V_fixture_min = 0
V_fixture_max = 0
| Time   V(typ)   V(min)   V(max)
0s        1.236uV    1.303uV    1.806uV
984ps     -589.5uV   -494.8uV   -8.281mV
1.163ns   -696.9uV   -585uV     721mV
1.296ns   1.911mV    -652.1uV   791.4mV
1.355ns   248.6mV    -681.8uV   799.7mV
1.489ns   764.9mV    -749.4uV   806.5mV
1.698ns   800.5mV    30.45mV    808.7mV
1.831ns   803.9mV    666.8mV    808.8mV
1.999ns   805.1mV    744mV      809mV
10ns      806.2mV    755.1mV    809.9mV
[Rising Waveform]
R_fixture = 50
V_fixture = 1.2
V_fixture_min = 1.14
V_fixture_max = 1.26
| Time   V(typ)   V(min)   V(max)
0s        365.3mV    340.9mV    425.4mV
929ps     365.6mV    341.3mV    429.2mV
1.069ns   365.7mV    341.4mV    1.12V
1.26ns    417.8mV    341.5mV    1.248V
1.389ns   1.114V     341.6mV    1.256V
1.583ns   1.191V     341.7mV    1.258V
1.674ns   1.195V     415mV      1.259V
1.777ns   1.197V     1.037V     1.259V
1.969ns   1.198V     1.129V     1.259V
10ns      1.2V       1.14V      1.26V
[Falling Waveform]
R_fixture = 50
V_fixture = 0
V_fixture_min = 0
V_fixture_max = 0
| Time   V(typ)   V(min)   V(max)
0s        806.2mV    755.1mV    809.9mV
921ps     805.5mV    754.7mV    799.3mV
1.031ns   805.4mV    754.7mV    85.76mV
1.206ns   803.8mV    754.6mV    8.616mV
1.352ns   83.3mV     754.5mV    3.21mV
1.499ns   9.631mV    754.5mV    1.684mV
1.656ns   3.091mV    731.5mV    1.108mV
1.764ns   1.999mV    93.19mV    930.6uV
1.893ns   1.299mV    11.27mV    749.7uV
10ns      1.913uV    8.784uV    2.439uV
[Falling Waveform]
R_fixture = 50
V_fixture = 1.2
V_fixture_min = 1.14
V_fixture_max = 1.26
| Time   V(typ)   V(min)   V(max)
0s        1.2V       1.14V      1.26V
938ps     1.201V     1.14V      1.262V
1.054ns   1.201V     1.14V      539.4mV
1.221ns   1.204V     1.141V     435.7mV
1.365ns   489.1mV    1.141V     429.3mV
1.531ns   374.9mV    1.141V     427.6mV
1.673ns   368.8mV    1.114V     427mV
1.788ns   367.5mV    443mV      426.8mV
1.97ns    366.6mV    348.4mV    426.4mV
10ns      365.3mV    340.9mV    425.4mV
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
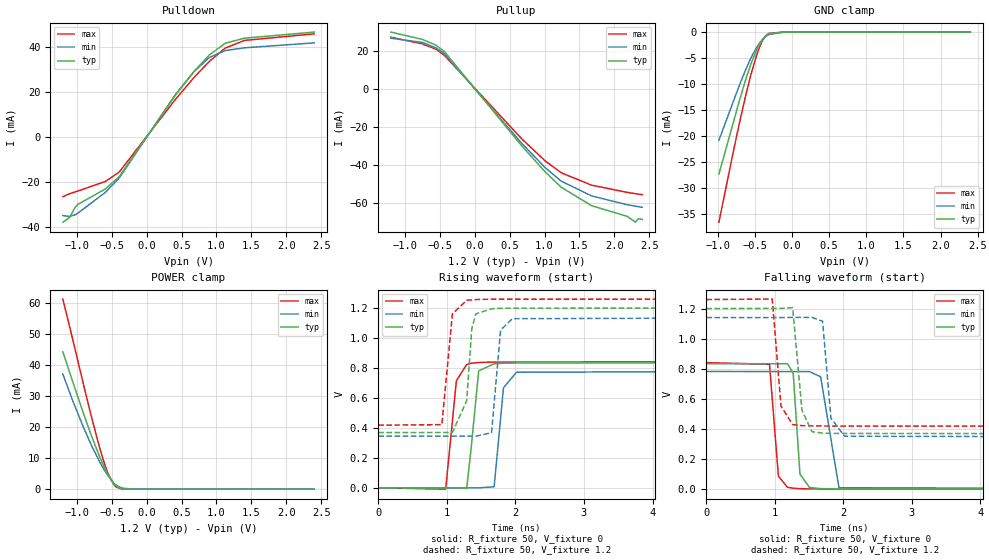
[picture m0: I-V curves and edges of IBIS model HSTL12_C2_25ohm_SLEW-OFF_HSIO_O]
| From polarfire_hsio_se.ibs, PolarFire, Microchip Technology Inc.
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|   Model HSTL12_C2_25ohm_SLEW-OFF_HSIO_O
[Model]   HSTL12_C2_25ohm_SLEW-OFF_HSIO_O
Model_type   Output
Polarity   Non-Inverting
Enable   Active-High
Vmeas =   0.6
Cref =   5p
Rref =   50
Vref =   0.6
|   typ   min   max
C_comp_pullup   1.335e-12   1.335e-12   1.380e-12
C_comp_pulldown  1.335e-12   1.335e-12   1.380e-12
[Temperature Range]  25C   100C   -40C
[Voltage Range]  1.2   1.14   1.26
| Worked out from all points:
|   slope of the pulldown table from 0 to 0.18 V, typ, clamps not added: 21.7 ohm
|   slope of the pullup table from 0 to 0.18 V, typ, clamps not added: 21.7 ohm
|   GND clamp passes 1 mA (typ) near -0.37 V on its own axis
|   POWER clamp passes 1 mA (typ) near -0.44 V on its own axis
|   rising waveform, R_fixture 50, V_fixture 0: 20-80 % time 72.7ps typ, 77.5ps min, 81.8ps max; typ from 0 V to 0.834 V
|   rising waveform, R_fixture 50, V_fixture 1.2: 20-80 % time 75.7ps typ, 71.5ps min, 81.8ps max; typ from 0.369 V to 1.2 V
|   falling waveform, R_fixture 50, V_fixture 0: 20-80 % time 62.4ps typ, 66.6ps min, 64.1ps max; typ from 0.834 V to 0 V
|   falling waveform, R_fixture 50, V_fixture 1.2: 20-80 % time 71.8ps typ, 77.3ps min, 73.3ps max; typ from 1.2 V to 0.369 V
[GND Clamp]
| Voltage   I(typ)   I(min)   I(max)
-984.4mV  -27.36mA   -20.85mA   -36.63mA
-787.5mV  -17.26mA   -13.26mA   -22.85mA
-708.7mV  -13.22mA   -10.27mA   -17.58mA
-630mV    -9.442mA   -7.443mA   -12.61mA
-551.3mV  -6.071mA   -4.927mA   -8.091mA
-472.5mV  -3.303mA   -2.86mA    -4.278mA
-433.1mV  -2.213mA   -2.035mA   -2.745mA
-393.7mV  -1.354mA   -1.365mA   -1.538mA
-354.4mV  -738.1uA   -853.7uA   -711.7uA
-315mV    -352.4uA   -492.8uA   -262uA
-118.1mV  -2.32uA    -10.66uA   -418.9nA
2.4V      0A         0A         0A
[POWER Clamp]
| Voltage   I(typ)   I(min)   I(max)
-1.2V     44.33mA    37.1mA     61.33mA
-1.063V   34.96mA    28.78mA    48.71mA
-905.6mV  24.47mA    19.99mA    33.89mA
-787.5mV  17.03mA    14mA       23.06mA
-669.4mV  10.26mA    8.667mA    13.03mA
-590.6mV  6.299mA    5.605mA    7.313mA
-551.3mV  4.569mA    4.255mA    4.935mA
-472.5mV  1.839mA    2.031mA    1.558mA
-433.1mV  941.2uA    1.22mA     654.9uA
-354.4mV  127.4uA    354.9uA    47.34uA
-196.9mV  963.6nA    14.11uA    668.3nA
2.4V      0A         0A         0A
[Pullup]
| Voltage   I(typ)   I(min)   I(max)
-1.2V     29.74mA    26.52mA    27.07mA
-748.1mV  25.89mA    24.28mA    23.51mA
-551.3mV  22.77mA    21.32mA    20.71mA
-433.1mV  19.46mA    18.33mA    17.45mA
675mV     -30.18mA   -28.85mA   -26.5mA
1.012V    -43.93mA   -41.71mA   -38.14mA
1.239V    -51.93mA   -48.69mA   -44.31mA
1.673V    -61.62mA   -56.48mA   -50.82mA
2.184V    -67.25mA   -61.13mA   -54.64mA
2.303V    -70.33mA   -61.9mA    -55.32mA
2.342V    -68.54mA   -62.14mA   -55.53mA
2.4V      -68.87mA   -62.5mA    -55.84mA
[Pulldown]
| Voltage   I(typ)   I(min)   I(max)
-1.2V     -38.08mA   -35.14mA   -26.74mA
-1.103V   -36mA      -35.51mA   -25.37mA
-1.024V   -31.46mA   -34.8mA    -24.57mA
-984.4mV  -30.13mA   -34.05mA   -24.21mA
-590.6mV  -23.28mA   -24.78mA   -19.92mA
-393.7mV  -17.81mA   -18.44mA   -15.77mA
412.5mV   18.5mA     18.81mA    16.63mA
675mV     28.95mA    28.9mA     26.28mA
900mV     36.5mA     35.35mA    33.62mA
1.125V    41.62mA    38.37mA    39.45mA
1.397V    43.89mA    39.59mA    42.89mA
2.4V      46.61mA    41.81mA    45.82mA
[Ramp]
dV/dt_r   0.500394/72.7045p  0.469171/77.4569p  0.504338/81.8214p
dV/dt_f   0.498858/71.8315p  0.477191/77.2962p  0.50517/73.3419p
R_load = 50
[Rising Waveform]
R_fixture = 50
V_fixture = 0
V_fixture_min = 0
V_fixture_max = 0
| Time   V(typ)   V(min)   V(max)
0s        1.236uV    1.305uV    1.807uV
983ps     -399.8uV   -370.3uV   -9.133mV
1.139ns   -463.4uV   -429.3uV   714.9mV
1.289ns   -3.846mV   -486uV     823mV
1.353ns   257.7mV    -510.2uV   831.2mV
1.464ns   780.1mV    -552.2uV   836.6mV
1.69ns    828.4mV    6.986mV    839.4mV
1.826ns   831.7mV    667.7mV    839.8mV
2.017ns   832.8mV    771.7mV    839.8mV
10ns      834mV      782mV      840.6mV
[Rising Waveform]
R_fixture = 50
V_fixture = 1.2
V_fixture_min = 1.14
V_fixture_max = 1.26
| Time   V(typ)   V(min)   V(max)
0s        368.6mV    344.7mV    418.1mV
927ps     369.2mV    344.7mV    421.5mV
1.081ns   369.3mV    344.7mV    1.161V
1.289ns   580.6mV    344.7mV    1.252V
1.364ns   1.064V     344.7mV    1.255V
1.423ns   1.161V     344.7mV    1.257V
1.652ns   1.195V     367.5mV    1.259V
1.784ns   1.198V     1.053V     1.259V
1.955ns   1.199V     1.129V     1.259V
10ns      1.2V       1.14V      1.26V
[Falling Waveform]
R_fixture = 50
V_fixture = 0
V_fixture_min = 0
V_fixture_max = 0
| Time   V(typ)   V(min)   V(max)
0s        834mV      782mV      840.6mV
923ps     833.4mV    781.4mV    829.5mV
1.053ns   833.3mV    781.3mV    86.33mV
1.186ns   833.2mV    781.3mV    12.15mV
1.269ns   770.8mV    781.2mV    6.422mV
1.368ns   99.98mV    781.2mV    3.225mV
1.507ns   11.4mV     781.1mV    1.75mV
1.67ns    3.588mV    746.5mV    1.137mV
1.938ns   1.201mV    9.476mV    743.6uV
10ns      2.047uV    1.804uV    2.276uV
[Falling Waveform]
R_fixture = 50
V_fixture = 1.2
V_fixture_min = 1.14
V_fixture_max = 1.26
| Time   V(typ)   V(min)   V(max)
0s        1.2V       1.14V      1.26V
963ps     1.201V     1.14V      1.263V
1.091ns   1.201V     1.14V      552.4mV
1.261ns   1.206V     1.141V     428.8mV
1.397ns   524.2mV    1.141V     422.1mV
1.543ns   381.6mV    1.141V     420.2mV
1.698ns   372.6mV    1.116V     419.8mV
1.821ns   370.7mV    471mV      419.4mV
2.02ns    370mV      351.6mV    419mV
10ns      368.6mV    344.7mV    418mV
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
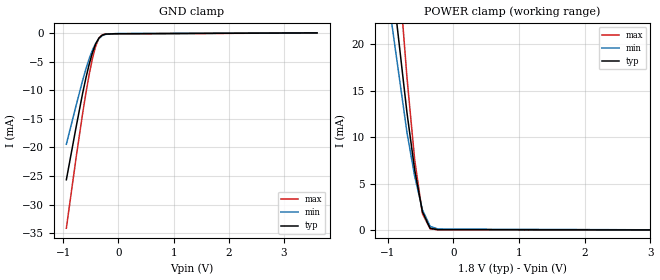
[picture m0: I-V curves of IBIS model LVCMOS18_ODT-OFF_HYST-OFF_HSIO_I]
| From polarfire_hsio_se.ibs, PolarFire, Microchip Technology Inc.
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|   Model LVCMOS18_ODT-OFF_HYST-OFF_HSIO_I
[Model]   LVCMOS18_ODT-OFF_HYST-OFF_HSIO_I
Model_type   Input
Vinl =   0.63
Vinh =   1.17
|   typ   min   max
C_comp_pullup   1.335e-12   1.335e-12   1.380e-12
C_comp_pulldown  1.335e-12   1.335e-12   1.380e-12
[Temperature Range]  25C   100C   -40C
[Voltage Range]  1.8   1.71   1.89
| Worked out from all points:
|   GND clamp passes 1 mA (typ) near -0.36 V on its own axis
|   POWER clamp passes 1 mA (typ) near -0.43 V on its own axis
[GND Clamp]
| Voltage   I(typ)   I(min)   I(max)
-945mV    -25.64mA   -19.44mA   -34.09mA
-767.8mV  -16.42mA   -12.66mA   -21.74mA
-649.7mV  -10.53mA   -8.28mA    -14.04mA
-590.6mV  -7.869mA   -6.289mA   -10.5mA
-531.6mV  -5.486mA   -4.51mA    -7.275mA
-472.5mV  -3.471mA   -3.004mA   -4.488mA
-413.4mV  -1.919mA   -1.821mA   -2.303mA
-354.4mV  -899.8uA   -991.2uA   -913.4uA
-295.3mV  -390.3uA   -497.2uA   -345.4uA
-236.2mV  -211.8uA   -259.6uA   -216.3uA
-59.06mV  -146uA     -125.3uA   -182.8uA
3.6V      0A         0A         0A
[POWER Clamp]
| Voltage   I(typ)   I(min)   I(max)
-1.8V     93.14mA    78.04mA    128.6mA
-1.654V   79.85mA    67.65mA    108.7mA
-1.536V   69.63mA    59.4mA     93.76mA
-1.417V   60.1mA     51.35mA    80.64mA
-1.358V   55.64mA    47.4mA     74.99mA
-1.004V   31.09mA    25.49mA    43.29mA
-708.7mV  12.66mA    10.53mA    16.47mA
-590.6mV  6.471mA    5.78mA     7.542mA
-472.5mV  1.945mA    2.169mA    1.748mA
-354.4mV  180.5uA    381.1uA    114.2uA
-236.2mV  28.78uA    101.7uA    30.8uA
3.6V      0A         0A         0A
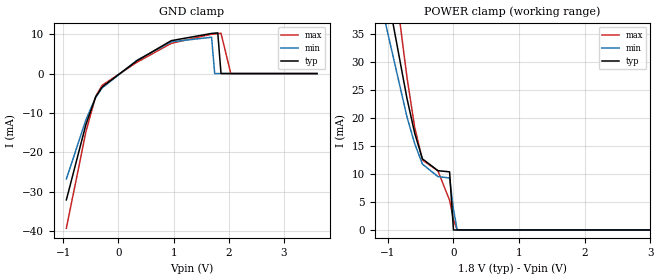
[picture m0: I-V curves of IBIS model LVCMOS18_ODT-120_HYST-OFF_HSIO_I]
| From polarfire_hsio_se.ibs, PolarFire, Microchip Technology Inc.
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|   Model LVCMOS18_ODT-120_HYST-OFF_HSIO_I
[Model]   LVCMOS18_ODT-120_HYST-OFF_HSIO_I
Model_type   Input
Vinl =   0.63
Vinh =   1.17
|   typ   min   max
C_comp_pullup   1.335e-12   1.335e-12   1.380e-12
C_comp_pulldown  1.335e-12   1.335e-12   1.380e-12
[Temperature Range]  25C   100C   -40C
[Voltage Range]  1.8   1.71   1.89
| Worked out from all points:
|   GND clamp passes 1 mA (typ) near -0.09 V on its own axis
|   POWER clamp passes 1 mA (typ) near -0.01 V on its own axis
[GND Clamp]
| Voltage   I(typ)   I(min)   I(max)
-945mV    -32.06mA   -26.76mA   -39.23mA
-590.6mV  -12.93mA   -11.73mA   -14.77mA
-413.4mV  -5.934mA   -6.03mA    -5.793mA
-295.3mV  -3.381mA   -3.62mA    -2.963mA
337.5mV   3.278mA    3.387mA    2.885mA
956.3mV   8.347mA    8.064mA    7.665mA
1.688V    10.18mA    9.212mA    9.985mA
1.744V    10.25mA    0A         10.06mA
1.8V      10.32mA    0A         10.14mA
1.859V    0A         0A         10.22mA
2.036V    0A         0A         0A
3.6V      0A         0A         0A
[POWER Clamp]
| Voltage   I(typ)   I(min)   I(max)
-1.8V     104.1mA    87.93mA    139.3mA
-1.595V   85.45mA    73.23mA    111.6mA
-1.417V   70.79mA    60.97mA    91.13mA
-1.063V   45.89mA    38.4mA     59.8mA
-708.7mV  23.56mA    20.24mA    27.35mA
-590.6mV  17.31mA    15.44mA    18.36mA
-472.5mV  12.71mA    11.77mA    12.5mA
-236.2mV  10.6mA     9.543mA    10.56mA
-59.06mV  10.39mA    9.295mA    5.305mA
0V        0A         3.708mA    1.824mA
56.25mV   0A         0A         0A
3.6V      0A         0A         0A
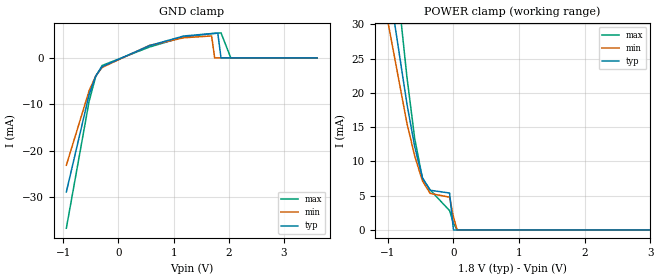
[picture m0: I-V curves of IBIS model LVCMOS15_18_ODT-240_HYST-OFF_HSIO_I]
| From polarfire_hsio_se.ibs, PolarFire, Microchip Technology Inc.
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|   Model LVCMOS15_18_ODT-240_HYST-OFF_HSIO_I
[Model]   LVCMOS15_18_ODT-240_HYST-OFF_HSIO_I
Model_type   Input
Vinl =   0.525
Vinh =   0.975
|   typ   min   max
C_comp_pullup   1.335e-12   1.335e-12   1.380e-12
C_comp_pulldown  1.335e-12   1.335e-12   1.380e-12
[Temperature Range]  25C   100C   -40C
[Voltage Range]  1.8   1.71   1.89
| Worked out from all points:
|   GND clamp passes 1 mA (typ) near -0.17 V on its own axis
|   POWER clamp passes 1 mA (typ) near -0.01 V on its own axis
[GND Clamp]
| Voltage   I(typ)   I(min)   I(max)
-945mV    -28.84mA   -23.1mA    -36.65mA
-531.6mV  -7.854mA   -7.038mA   -9.282mA
-413.4mV  -3.908mA   -3.911mA   -4.02mA
-295.3mV  -1.866mA   -2.042mA   -1.625mA
562.5mV   2.639mA    2.691mA    2.338mA
1.181V    4.709mA    4.329mA    4.509mA
1.688V    5.241mA    4.724mA    5.207mA
1.744V    5.292mA    0A         5.265mA
1.8V      5.343mA    0A         5.322mA
1.859V    0A         0A         5.382mA
2.036V    0A         0A         0A
3.6V      0A         0A         0A
[POWER Clamp]
| Voltage   I(typ)   I(min)   I(max)
-1.8V     98.61mA    82.97mA    134mA
-1.595V   80.06mA    68.36mA    106.4mA
-1.417V   65.46mA    56.15mA    85.95mA
-1.063V   40.65mA    33.67mA    54.7mA
-708.7mV  18.41mA    15.59mA    22.33mA
-590.6mV  12.18mA    10.81mA    13.37mA
-472.5mV  7.61mA     7.166mA    7.533mA
-354.4mV  5.792mA    5.333mA    5.837mA
-59.06mV  5.396mA    4.786mA    2.825mA
0V        0A         1.907mA    971.1uA
56.25mV   0A         0A         0A
3.6V      0A         0A         0A
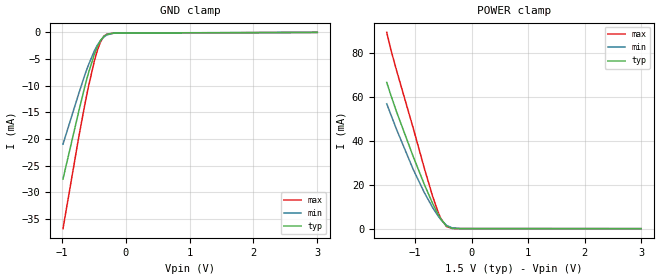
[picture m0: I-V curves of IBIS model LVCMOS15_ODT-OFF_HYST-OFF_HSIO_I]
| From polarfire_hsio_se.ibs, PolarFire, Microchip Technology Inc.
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|   Model LVCMOS15_ODT-OFF_HYST-OFF_HSIO_I
[Model]   LVCMOS15_ODT-OFF_HYST-OFF_HSIO_I
Model_type   Input
Vinl =   0.525
Vinh =   0.975
|   typ   min   max
C_comp_pullup   1.335e-12   1.335e-12   1.380e-12
C_comp_pulldown  1.335e-12   1.335e-12   1.380e-12
[Temperature Range]  25C   100C   -40C
[Voltage Range]  1.5   1.425   1.575
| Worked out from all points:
|   GND clamp passes 1 mA (typ) near -0.36 V on its own axis
|   POWER clamp passes 1 mA (typ) near -0.43 V on its own axis
[GND Clamp]
| Voltage   I(typ)   I(min)   I(max)
-984.4mV  -27.52mA   -20.97mA   -36.83mA
-738.3mV  -14.86mA   -11.51mA   -19.71mA
-639.8mV  -10.04mA   -7.906mA   -13.38mA
-590.6mV  -7.836mA   -6.26mA    -10.46mA
-492.2mV  -4.065mA   -3.445mA   -5.32mA
-443mV    -2.601mA   -2.343mA   -3.27mA
-393.7mV  -1.488mA   -1.478mA   -1.705mA
-344.5mV  -752.5uA   -861uA     -730.3uA
-295.3mV  -360.5uA   -471.5uA   -308.5uA
-196.9mV  -143.7uA   -162.8uA   -160.8uA
-49.22mV  -115.8uA   -98.92uA   -145.6uA
3V        0A         0A         0A
[POWER Clamp]
| Voltage   I(typ)   I(min)   I(max)
-1.5V     66.68mA    56.94mA    89.5mA
-1.427V   60.86mA    52mA       81.61mA
-1.329V   53.48mA    45.42mA    72.38mA
-1.034V   33.05mA    27.15mA    46.05mA
-836.7mV  20.27mA    16.53mA    27.7mA
-689.1mV  11.54mA    9.663mA    14.82mA
-590.6mV  6.461mA    5.759mA    7.506mA
-541.4mV  4.305mA    4.077mA    4.578mA
-443mV    1.22mA     1.505mA    953.6uA
-344.5mV  141uA      346.7uA    82.92uA
-196.9mV  21.95uA    39.89uA    24.88uA
3V        0A         0A         0A
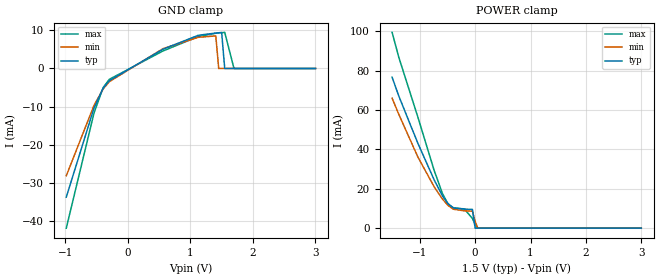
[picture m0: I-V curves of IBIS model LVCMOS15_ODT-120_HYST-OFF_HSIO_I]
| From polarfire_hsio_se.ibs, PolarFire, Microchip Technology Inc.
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|   Model LVCMOS15_ODT-120_HYST-OFF_HSIO_I
[Model]   LVCMOS15_ODT-120_HYST-OFF_HSIO_I
Model_type   Input
Vinl =   0.525
Vinh =   0.975
|   typ   min   max
C_comp_pullup   1.335e-12   1.335e-12   1.380e-12
C_comp_pulldown  1.335e-12   1.335e-12   1.380e-12
[Temperature Range]  25C   100C   -40C
[Voltage Range]  1.5   1.425   1.575
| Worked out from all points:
|   GND clamp passes 1 mA (typ) near -0.09 V on its own axis
|   POWER clamp passes 1 mA (typ) near -0.01 V on its own axis
[GND Clamp]
| Voltage   I(typ)   I(min)   I(max)
-984.4mV  -33.72mA   -28.14mA   -41.85mA
-541.4mV  -10.38mA   -9.671mA   -11.7mA
-393.7mV  -5.14mA    -5.341mA   -4.957mA
-295.3mV  -3.19mA    -3.457mA   -2.839mA
562.5mV   5.05mA     5.199mA    4.593mA
1.125V    8.688mA    8.165mA    8.349mA
1.406V    9.291mA    8.536mA    9.225mA
1.453V    9.357mA    0A         9.308mA
1.5V      9.42mA     0A         9.385mA
1.549V    0A         0A         9.461mA
1.697V    0A         0A         0A
3V        0A         0A         0A
[POWER Clamp]
| Voltage   I(typ)   I(min)   I(max)
-1.5V     76.62mA    65.99mA    99.39mA
-1.378V   66.99mA    57.71mA    86.65mA
-1.034V   43.03mA    36.07mA    56.32mA
-738.3mV  24.38mA    20.87mA    29.11mA
-590.6mV  16.41mA    14.76mA    17.59mA
-492.2mV  12.42mA    11.58mA    12.39mA
-393.7mV  10.29mA    9.618mA    10.25mA
-196.9mV  9.666mA    8.777mA    9.769mA
-49.22mV  9.484mA    8.609mA    4.912mA
0V        0A         3.435mA    1.688mA
46.88mV   0A         0A         0A
3V        0A         0A         0A
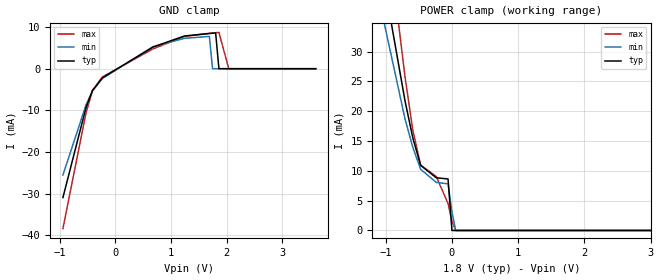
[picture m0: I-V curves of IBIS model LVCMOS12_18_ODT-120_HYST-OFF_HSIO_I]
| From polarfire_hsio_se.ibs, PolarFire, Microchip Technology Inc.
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|   Model LVCMOS12_18_ODT-120_HYST-OFF_HSIO_I
[Model]   LVCMOS12_18_ODT-120_HYST-OFF_HSIO_I
Model_type   Input
Vinl =   0.42
Vinh =   0.78
|   typ   min   max
C_comp_pullup   1.335e-12   1.335e-12   1.380e-12
C_comp_pulldown  1.335e-12   1.335e-12   1.380e-12
[Temperature Range]  25C   100C   -40C
[Voltage Range]  1.8   1.71   1.89
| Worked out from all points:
|   GND clamp passes 1 mA (typ) near -0.10 V on its own axis
|   POWER clamp passes 1 mA (typ) near -0.01 V on its own axis
[GND Clamp]
| Voltage   I(typ)   I(min)   I(max)
-945mV    -30.96mA   -25.56mA   -38.43mA
-531.6mV  -9.43mA    -8.757mA   -10.7mA
-413.4mV  -5.238mA   -5.339mA   -5.247mA
-236.2mV  -2.192mA   -2.357mA   -1.977mA
675mV     5.2mA      5.306mA    4.762mA
1.238V    7.862mA    7.3mA      7.733mA
1.688V    8.456mA    7.751mA    8.51mA
1.744V    8.519mA    0A         8.581mA
1.8V      8.58mA     0A         8.651mA
1.859V    0A         0A         8.723mA
2.036V    0A         0A         0A
3.6V      0A         0A         0A
[POWER Clamp]
| Voltage   I(typ)   I(min)   I(max)
-1.8V     102.2mA    86.31mA    137.6mA
-1.595V   83.57mA    71.65mA    110mA
-1.417V   68.93mA    59.4mA     89.53mA
-1.063V   44.06mA    36.86mA    58.23mA
-708.7mV  21.76mA    18.73mA    25.8mA
-590.6mV  15.52mA    13.94mA    16.82mA
-472.5mV  10.93mA    10.27mA    10.97mA
-236.2mV  8.84mA     8.06mA     9.046mA
-59.06mV  8.645mA    7.827mA    4.54mA
0V        0A         3.121mA    1.561mA
56.25mV   0A         0A         0A
3.6V      0A         0A         0A
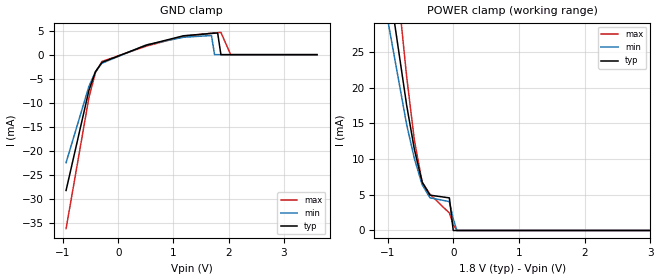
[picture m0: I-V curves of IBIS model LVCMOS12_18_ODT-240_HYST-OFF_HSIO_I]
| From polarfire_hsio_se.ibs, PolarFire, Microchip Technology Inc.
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|   Model LVCMOS12_18_ODT-240_HYST-OFF_HSIO_I
[Model]   LVCMOS12_18_ODT-240_HYST-OFF_HSIO_I
Model_type   Input
Vinl =   0.42
Vinh =   0.78
|   typ   min   max
C_comp_pullup   1.335e-12   1.335e-12   1.380e-12
C_comp_pulldown  1.335e-12   1.335e-12   1.380e-12
[Temperature Range]  25C   100C   -40C
[Voltage Range]  1.8   1.71   1.89
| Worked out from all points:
|   GND clamp passes 1 mA (typ) near -0.20 V on its own axis
|   POWER clamp passes 1 mA (typ) near -0.01 V on its own axis
[GND Clamp]
| Voltage   I(typ)   I(min)   I(max)
-945mV    -28.29mA   -22.5mA    -36.25mA
-531.6mV  -7.441mA   -6.619mA   -8.967mA
-413.4mV  -3.56mA    -3.563mA   -3.748mA
-295.3mV  -1.606mA   -1.783mA   -1.42mA
506.2mV   1.97mA     2.036mA    1.772mA
1.181V    3.933mA    3.627mA    3.834mA
1.688V    4.423mA    3.991mA    4.473mA
1.744V    4.471mA    0A         4.527mA
1.8V      4.518mA    0A         4.582mA
1.859V    0A         0A         4.639mA
2.036V    0A         0A         0A
3.6V      0A         0A         0A
[POWER Clamp]
| Voltage   I(typ)   I(min)   I(max)
-1.8V     97.7mA     82.16mA    133.2mA
-1.595V   79.17mA    67.56mA    105.6mA
-1.417V   64.58mA    55.36mA    85.15mA
-1.063V   39.77mA    32.9mA     53.91mA
-708.7mV  17.55mA    14.83mA    21.56mA
-590.6mV  11.33mA    10.06mA    12.6mA
-472.5mV  6.764mA    6.414mA    6.769mA
-354.4mV  4.951mA    4.585mA    5.077mA
-59.06mV  4.569mA    4.049mA    2.444mA
0V        0A         1.612mA    840uA
56.25mV   0A         0A         0A
3.6V      0A         0A         0A
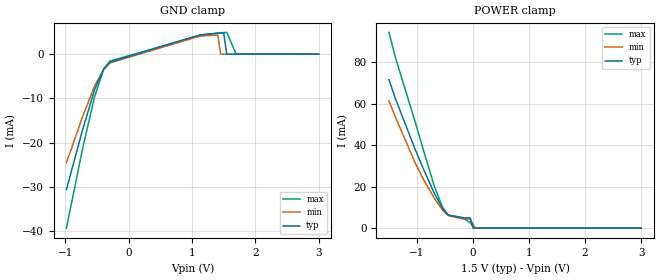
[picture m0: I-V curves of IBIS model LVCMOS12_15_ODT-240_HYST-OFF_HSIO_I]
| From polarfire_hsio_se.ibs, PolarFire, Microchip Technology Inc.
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|   Model LVCMOS12_15_ODT-240_HYST-OFF_HSIO_I
[Model]   LVCMOS12_15_ODT-240_HYST-OFF_HSIO_I
Model_type   Input
Vinl =   0.42
Vinh =   0.78
|   typ   min   max
C_comp_pullup   1.335e-12   1.335e-12   1.380e-12
C_comp_pulldown  1.335e-12   1.335e-12   1.380e-12
[Temperature Range]  25C   100C   -40C
[Voltage Range]  1.5   1.425   1.575
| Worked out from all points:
|   GND clamp passes 1 mA (typ) near -0.18 V on its own axis
|   POWER clamp passes 1 mA (typ) near -0.01 V on its own axis
[GND Clamp]
| Voltage   I(typ)   I(min)   I(max)
-984.4mV  -30.62mA   -24.55mA   -39.33mA
-738.3mV  -17.53mA   -14.48mA   -21.96mA
-541.4mV  -8.093mA   -7.208mA   -9.706mA
-393.7mV  -3.301mA   -3.4mA     -3.312mA
-295.3mV  -1.761mA   -1.953mA   -1.554mA
1.125V    4.376mA    4.101mA    4.247mA
1.406V    4.737mA    4.338mA    4.771mA
1.453V    4.782mA    0A         4.828mA
1.5V      4.826mA    0A         4.882mA
1.549V    0A         0A         4.936mA
1.697V    0A         0A         0A
3V        0A         0A         0A
[POWER Clamp]
| Voltage   I(typ)   I(min)   I(max)
-1.5V     71.65mA    61.45mA    94.5mA
-1.378V   62.05mA    53.19mA    81.78mA
-1.034V   38.16mA    31.63mA    51.52mA
-885.9mV  28.62mA    23.59mA    37.72mA
-689.1mV  16.76mA    14.32mA    20.24mA
-541.4mV  9.477mA    8.704mA    9.945mA
-443mV    6.353mA    6.099mA    6.281mA
-196.9mV  5.004mA    4.515mA    5.168mA
-49.22mV  4.871mA    4.389mA    2.586mA
0V        0A         1.749mA    888.9uA
46.88mV   0A         0A         0A
3V        0A         0A         0A
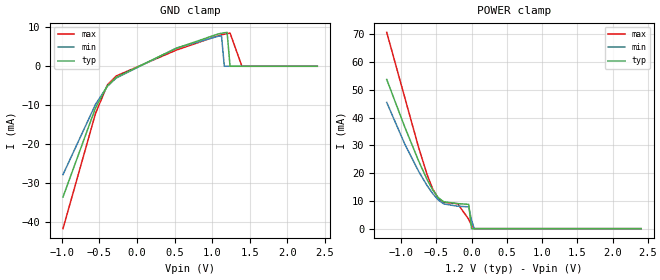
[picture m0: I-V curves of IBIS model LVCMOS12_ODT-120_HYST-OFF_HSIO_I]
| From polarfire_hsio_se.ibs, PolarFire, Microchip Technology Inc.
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|   Model LVCMOS12_ODT-120_HYST-OFF_HSIO_I
[Model]   LVCMOS12_ODT-120_HYST-OFF_HSIO_I
Model_type   Input
Vinl =   0.42
Vinh =   0.78
|   typ   min   max
C_comp_pullup   1.335e-12   1.335e-12   1.380e-12
C_comp_pulldown  1.335e-12   1.335e-12   1.380e-12
[Temperature Range]  25C   100C   -40C
[Voltage Range]  1.2   1.14   1.26
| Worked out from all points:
|   GND clamp passes 1 mA (typ) near -0.10 V on its own axis
|   POWER clamp passes 1 mA (typ) near -0.00 V on its own axis
[GND Clamp]
| Voltage   I(typ)   I(min)   I(max)
-984.4mV  -33.5mA    -27.76mA   -41.61mA
-551.3mV  -10.65mA   -9.753mA   -12.07mA
-393.7mV  -5.008mA   -5.134mA   -4.801mA
-275.6mV  -2.823mA   -3.01mA    -2.486mA
525mV     4.609mA    4.665mA    4.147mA
1.087V    8.318mA    7.72mA     7.873mA
1.125V    8.456mA    7.79mA     8.054mA
1.163V    8.575mA    0A         8.22mA
1.2V      8.676mA    0A         8.368mA
1.239V    0A         0A         8.504mA
1.397V    0A         0A         0A
2.4V      0A         0A         0A
[POWER Clamp]
| Voltage   I(typ)   I(min)   I(max)
-1.2V     53.78mA    45.51mA    70.75mA
-945mV    36.65mA    30.5mA     47.28mA
-748.1mV  24.37mA    20.64mA    29.23mA
-630mV    17.77mA    15.58mA    19.6mA
-551.3mV  14.05mA    12.69mA    14.41mA
-472.5mV  11.22mA    10.39mA    10.94mA
-393.7mV  9.684mA    8.926mA    9.488mA
-196.9mV  9.037mA    8.085mA    8.991mA
-39.38mV  8.766mA    7.876mA    3.386mA
0V        0A         3.14mA     1.164mA
37.5mV    0A         0A         0A
2.4V      0A         0A         0A
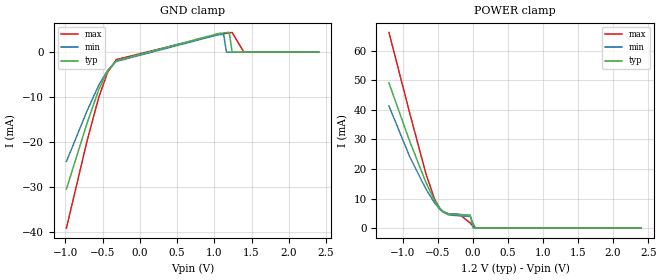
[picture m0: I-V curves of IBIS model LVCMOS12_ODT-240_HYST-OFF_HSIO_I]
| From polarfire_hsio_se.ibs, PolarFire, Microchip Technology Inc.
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|   Model LVCMOS12_ODT-240_HYST-OFF_HSIO_I
[Model]   LVCMOS12_ODT-240_HYST-OFF_HSIO_I
Model_type   Input
Vinl =   0.42
Vinh =   0.78
|   typ   min   max
C_comp_pullup   1.335e-12   1.335e-12   1.380e-12
C_comp_pulldown  1.335e-12   1.335e-12   1.380e-12
[Temperature Range]  25C   100C   -40C
[Voltage Range]  1.2   1.14   1.26
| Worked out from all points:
|   GND clamp passes 1 mA (typ) near -0.19 V on its own axis
|   POWER clamp passes 1 mA (typ) near -0.01 V on its own axis
[GND Clamp]
| Voltage   I(typ)   I(min)   I(max)
-984.4mV  -30.49mA   -24.35mA   -39.19mA
-708.7mV  -15.88mA   -13.13mA   -19.85mA
-551.3mV  -8.406mA   -7.382mA   -10.13mA
-433.1mV  -4.218mA   -4.106mA   -4.537mA
-315mV    -1.904mA   -2.083mA   -1.671mA
1.05V     4.104mA    3.848mA    3.895mA
1.125V    4.264mA    3.935mA    4.103mA
1.163V    4.329mA    0A         4.196mA
1.2V      4.386mA    0A         4.281mA
1.239V    0A         0A         4.361mA
1.397V    0A         0A         0A
2.4V      0A         0A         0A
[POWER Clamp]
| Voltage   I(typ)   I(min)   I(max)
-1.2V     49.08mA    41.32mA    66.15mA
-905.6mV  29.48mA    24.26mA    39.06mA
-669.4mV  15.29mA    13.1mA     18.16mA
-551.3mV  9.497mA    8.631mA    9.969mA
-472.5mV  6.698mA    6.351mA    6.517mA
-433.1mV  5.767mA    5.512mA    5.576mA
-354.4mV  4.883mA    4.528mA    4.889mA
-196.9mV  4.61mA     4.129mA    4.671mA
-39.38mV  4.439mA    3.987mA    1.752mA
0V        0A         1.589mA    602.4uA
37.5mV    0A         0A         0A
2.4V      0A         0A         0A
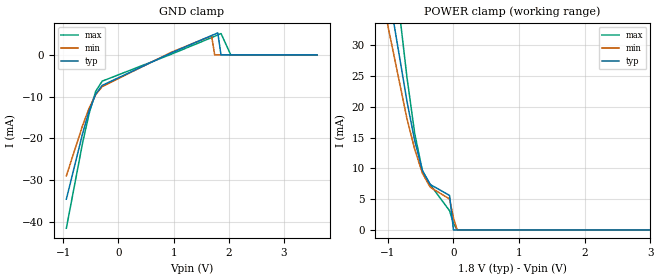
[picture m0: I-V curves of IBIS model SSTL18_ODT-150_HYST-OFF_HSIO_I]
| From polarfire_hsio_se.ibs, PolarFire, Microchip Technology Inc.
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|   Model SSTL18_ODT-150_HYST-OFF_HSIO_I
[Model]   SSTL18_ODT-150_HYST-OFF_HSIO_I
Model_type   Input
Vinl =   0.775
Vinh =   1.025
|   typ   min   max
C_comp_pullup   1.335e-12   1.335e-12   1.380e-12
C_comp_pulldown  1.335e-12   1.335e-12   1.380e-12
[Temperature Range]  25C   100C   -40C
[Voltage Range]  1.8   1.71   1.89
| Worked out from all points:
|   POWER clamp passes 1 mA (typ) near -0.01 V on its own axis
[GND Clamp]
| Voltage   I(typ)   I(min)   I(max)
-945mV    -34.59mA   -28.99mA   -41.54mA
-649.7mV  -18.81mA   -16.92mA   -21.04mA
-531.6mV  -13.42mA   -12.74mA   -14.04mA
-413.4mV  -9.422mA   -9.546mA   -8.743mA
-295.3mV  -7.318mA   -7.608mA   -6.303mA
956.3mV   464.5uA    614.9uA    150.7uA
1.688V    4.635mA    4.564mA    4.138mA
1.744V    4.95mA     0A         4.452mA
1.8V      5.266mA    0A         4.769mA
1.859V    0A         0A         5.104mA
2.036V    0A         0A         0A
3.6V      0A         0A         0A
[POWER Clamp]
| Voltage   I(typ)   I(min)   I(max)
-1.8V     101.4mA    85.38mA    136.8mA
-1.595V   83.08mA    70.97mA    109.5mA
-1.417V   68.53mA    58.88mA    89.12mA
-1.063V   43.44mA    36.46mA    57.37mA
-708.7mV  20.9mA     18.07mA    24.82mA
-590.6mV  14.5mA     13.12mA    15.69mA
-472.5mV  9.653mA    9.199mA    9.551mA
-354.4mV  7.385mA    6.946mA    7.371mA
-59.06mV  5.599mA    5.015mA    3.109mA
0V        0A         1.95mA     1.069mA
56.25mV   0A         0A         0A
3.6V      0A         0A         0A
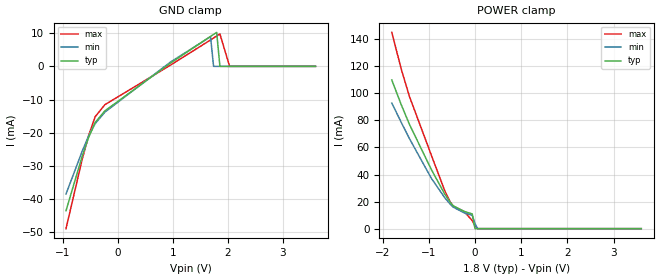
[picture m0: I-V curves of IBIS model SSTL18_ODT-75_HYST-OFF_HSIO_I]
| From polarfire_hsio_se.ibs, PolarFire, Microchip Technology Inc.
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|   Model SSTL18_ODT-75_HYST-OFF_HSIO_I
[Model]   SSTL18_ODT-75_HYST-OFF_HSIO_I
Model_type   Input
Vinl =   0.775
Vinh =   1.025
|   typ   min   max
C_comp_pullup   1.335e-12   1.335e-12   1.380e-12
C_comp_pulldown  1.335e-12   1.335e-12   1.380e-12
[Temperature Range]  25C   100C   -40C
[Voltage Range]  1.8   1.71   1.89
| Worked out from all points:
|   POWER clamp passes 1 mA (typ) near -0.01 V on its own axis
[GND Clamp]
| Voltage   I(typ)   I(min)   I(max)
-945mV    -43.56mA   -38.54mA   -48.97mA
-649.7mV  -27.1mA    -25.57mA   -28.04mA
-531.6mV  -21.38mA   -20.97mA   -20.8mA
-413.4mV  -16.94mA   -17.28mA   -15.18mA
-236.2mV  -13.42mA   -13.8mA    -11.56mA
956.3mV   969.6uA    1.279mA    350.4uA
1.688V    9.044mA    8.946mA    7.97mA
1.744V    9.643mA    0A         8.564mA
1.8V      10.25mA    0A         9.163mA
1.859V    0A         0A         9.798mA
2.036V    0A         0A         0A
3.6V      0A         0A         0A
[POWER Clamp]
| Voltage   I(typ)   I(min)   I(max)
-1.8V     109.8mA    92.76mA    145mA
-1.595V   91.49mA    78.46mA    117.8mA
-1.417V   76.95mA    66.44mA    97.52mA
-945mV    43.72mA    37.27mA    54.32mA
-649.7mV  25.25mA    22.63mA    27.62mA
-531.6mV  19.24mA    17.88mA    19.48mA
-472.5mV  16.91mA    15.92mA    16.72mA
-236.2mV  12.78mA    11.75mA    12.69mA
-59.06mV  10.88mA    9.812mA    5.951mA
0V        0A         3.817mA    2.046mA
56.25mV   0A         0A         0A
3.6V      0A         0A         0A
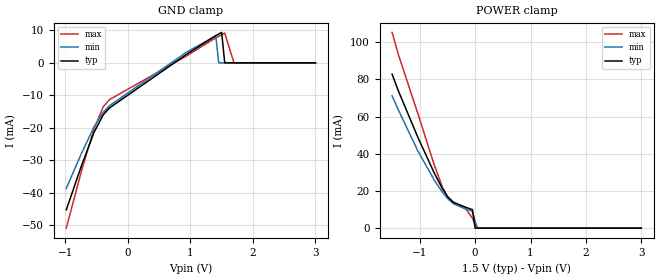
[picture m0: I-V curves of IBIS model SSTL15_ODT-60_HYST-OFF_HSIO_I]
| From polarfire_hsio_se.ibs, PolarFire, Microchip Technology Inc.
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|   Model SSTL15_ODT-60_HYST-OFF_HSIO_I
[Model]   SSTL15_ODT-60_HYST-OFF_HSIO_I
Model_type   Input
Vinl =   0.65
Vinh =   0.85
|   typ   min   max
C_comp_pullup   1.335e-12   1.335e-12   1.380e-12
C_comp_pulldown  1.335e-12   1.335e-12   1.380e-12
[Temperature Range]  25C   100C   -40C
[Voltage Range]  1.5   1.425   1.575
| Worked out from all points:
|   POWER clamp passes 1 mA (typ) near -0.00 V on its own axis
[GND Clamp]
| Voltage   I(typ)   I(min)   I(max)
-984.4mV  -45.24mA   -38.64mA   -50.87mA
-738.3mV  -31.48mA   -27.73mA   -33.07mA
-541.4mV  -21.42mA   -19.73mA   -20.39mA
-393.7mV  -15.99mA   -15.22mA   -13.53mA
-295.3mV  -13.9mA    -13.21mA   -11.33mA
937.5mV   2.604mA    3.27mA     2.113mA
1.406V    8.355mA    8.336mA    7.705mA
1.453V    8.866mA    0A         8.186mA
1.5V      9.377mA    0A         8.664mA
1.549V    0A         0A         9.166mA
1.697V    0A         0A         0A
3V        0A         0A         0A
[POWER Clamp]
| Voltage   I(typ)   I(min)   I(max)
-1.5V     82.79mA    71.14mA    105.3mA
-1.378V   73.18mA    63.01mA    92.52mA
-1.034V   48.8mA     41.49mA    61.56mA
-738.3mV  29.62mA    25.86mA    33.96mA
-590.6mV  21.23mA    19.33mA    22.06mA
-492.2mV  16.78mA    15.73mA    16.41mA
-393.7mV  13.96mA    13.15mA    13.58mA
-196.9mV  11.51mA    10.58mA    11.41mA
-49.22mV  9.913mA    9.041mA    5.416mA
0V        0A         3.529mA    1.862mA
46.88mV   0A         0A         0A
3V        0A         0A         0A
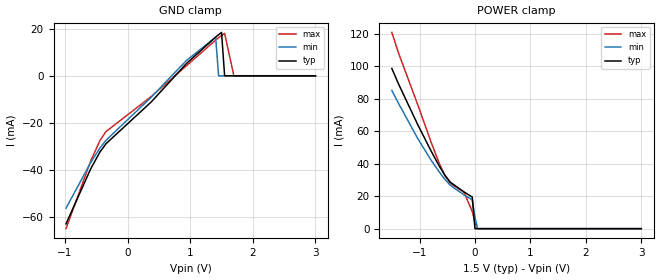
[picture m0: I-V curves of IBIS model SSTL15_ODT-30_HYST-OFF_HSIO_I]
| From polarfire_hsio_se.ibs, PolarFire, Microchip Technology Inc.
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|   Model SSTL15_ODT-30_HYST-OFF_HSIO_I
[Model]   SSTL15_ODT-30_HYST-OFF_HSIO_I
Model_type   Input
Vinl =   0.65
Vinh =   0.85
|   typ   min   max
C_comp_pullup   1.335e-12   1.335e-12   1.380e-12
C_comp_pulldown  1.335e-12   1.335e-12   1.380e-12
[Temperature Range]  25C   100C   -40C
[Voltage Range]  1.5   1.425   1.575
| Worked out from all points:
|   POWER clamp passes 1 mA (typ) near -0.00 V on its own axis
[GND Clamp]
| Voltage   I(typ)   I(min)   I(max)
-984.4mV  -62.93mA   -56.27mA   -64.95mA
-590.6mV  -39.57mA   -36.87mA   -36.2mA
-443mV    -32.4mA    -30.71mA   -27.59mA
-344.5mV  -28.83mA   -27.37mA   -23.66mA
375mV     -11.15mA   -9.131mA   -8.844mA
937.5mV   5.166mA    6.469mA    4.225mA
1.406V    16.46mA    16.42mA    15.2mA
1.453V    17.45mA    0A         16.14mA
1.5V      18.45mA    0A         17.07mA
1.549V    0A         0A         18.04mA
1.697V    0A         0A         0A
3V        0A         0A         0A
[POWER Clamp]
| Voltage   I(typ)   I(min)   I(max)
-1.5V     98.79mA    85.23mA    121mA
-1.378V   89.15mA    77.2mA     108.2mA
-1.034V   64.25mA    55.67mA    76.59mA
-787.5mV  47.61mA    42.03mA    52.97mA
-639.8mV  38.35mA    34.76mA    39.91mA
-541.4mV  32.91mA    30.4mA     32.72mA
-443mV    28.59mA    26.7mA     27.85mA
-196.9mV  22.61mA    20.8mA     22.4mA
-49.22mV  19.5mA     17.8mA     10.64mA
0V        0A         6.95mA     3.656mA
46.88mV   0A         0A         0A
3V        0A         0A         0A
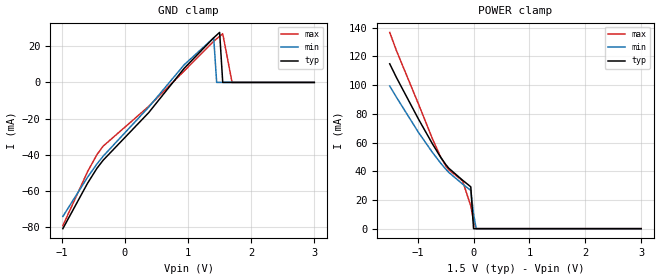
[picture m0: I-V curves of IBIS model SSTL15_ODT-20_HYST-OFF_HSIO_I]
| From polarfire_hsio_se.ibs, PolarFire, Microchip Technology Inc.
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|   Model SSTL15_ODT-20_HYST-OFF_HSIO_I
[Model]   SSTL15_ODT-20_HYST-OFF_HSIO_I
Model_type   Input
Vinl =   0.65
Vinh =   0.85
|   typ   min   max
C_comp_pullup   1.335e-12   1.335e-12   1.380e-12
C_comp_pulldown  1.335e-12   1.335e-12   1.380e-12
[Temperature Range]  25C   100C   -40C
[Voltage Range]  1.5   1.425   1.575
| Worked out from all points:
|   POWER clamp passes 1 mA (typ) near -0.00 V on its own axis
[GND Clamp]
| Voltage   I(typ)   I(min)   I(max)
-984.4mV  -80.65mA   -73.92mA   -78.99mA
-590.6mV  -55.45mA   -52.18mA   -49.06mA
-443mV    -47.3mA    -44.9mA    -39.74mA
-344.5mV  -42.86mA   -40.63mA   -35.11mA
375mV     -16.7mA    -13.67mA   -13.23mA
937.5mV   7.75mA     9.716mA    6.314mA
1.406V    24.62mA    24.59mA    22.68mA
1.453V    26.11mA    0A         24.07mA
1.5V      27.59mA    0A         25.45mA
1.549V    0A         0A         26.89mA
1.697V    0A         0A         0A
3V        0A         0A         0A
[POWER Clamp]
| Voltage   I(typ)   I(min)   I(max)
-1.5V     114.9mA    99.42mA    136.8mA
-1.378V   105.2mA    91.48mA    123.9mA
-984.4mV  76.29mA    67.02mA    86.76mA
-738.3mV  59.3mA     53.29mA    62.9mA
-590.6mV  49.89mA    45.79mA    50.1mA
-492.2mV  44.43mA    41.25mA    43.45mA
-443mV    42.12mA    39.2mA     41.02mA
-196.9mV  33.78mA    31.1mA     33.36mA
-49.22mV  29.15mA    26.65mA    15.85mA
0V        0A         10.4mA     5.447mA
46.88mV   0A         0A         0A
3V        0A         0A         0A
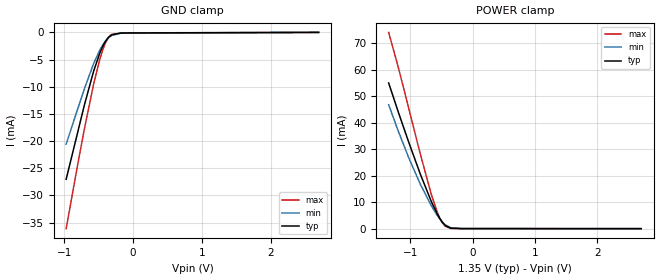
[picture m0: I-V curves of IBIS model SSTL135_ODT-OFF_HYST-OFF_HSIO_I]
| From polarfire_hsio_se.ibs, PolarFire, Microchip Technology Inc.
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|   Model SSTL135_ODT-OFF_HYST-OFF_HSIO_I
[Model]   SSTL135_ODT-OFF_HYST-OFF_HSIO_I
Model_type   Input
Vinl =   0.585
Vinh =   0.765
|   typ   min   max
C_comp_pullup   1.335e-12   1.335e-12   1.380e-12
C_comp_pulldown  1.335e-12   1.335e-12   1.380e-12
[Temperature Range]  25C   100C   -40C
[Voltage Range]  1.35   1.2825   1.4175
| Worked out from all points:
|   GND clamp passes 1 mA (typ) near -0.36 V on its own axis
|   POWER clamp passes 1 mA (typ) near -0.43 V on its own axis
[GND Clamp]
| Voltage   I(typ)   I(min)   I(max)
-974.5mV  -27.03mA   -20.56mA   -36.11mA
-797.3mV  -17.91mA   -13.76mA   -23.69mA
-708.7mV  -13.35mA   -10.38mA   -17.74mA
-575.9mV  -7.195mA   -5.779mA   -9.596mA
-487.3mV  -3.888mA   -3.311mA   -5.077mA
-443mV    -2.585mA   -2.329mA   -3.251mA
-398.7mV  -1.567mA   -1.54mA    -1.818mA
-354.4mV  -854.7uA   -952.2uA   -857.7uA
-310.1mV  -432.8uA   -554uA     -371.4uA
-177.2mV  -119.5uA   -129.4uA   -138.5uA
-44.3mV   -100.9uA   -85.88uA   -127.2uA
2.7V      0A         0A         0A
[POWER Clamp]
| Voltage   I(typ)   I(min)   I(max)
-1.35V    55.05mA    46.81mA    74.15mA
-1.196V   44.11mA    36.9mA     61.03mA
-1.019V   32.06mA    26.3mA     44.65mA
-841.6mV  20.57mA    16.77mA    28.14mA
-664.5mV  10.19mA    8.62mA     12.84mA
-575.9mV  5.775mA    5.222mA    6.544mA
-531.6mV  3.911mA    3.757mA    4.051mA
-487.3mV  2.366mA    2.498mA    2.157mA
-443mV    1.217mA    1.493mA    932.8uA
-354.4mV  176.9uA    353.7uA    98.72uA
-177.2mV  19.22uA    27.63uA    22.06uA
2.7V      0A         0A         0A
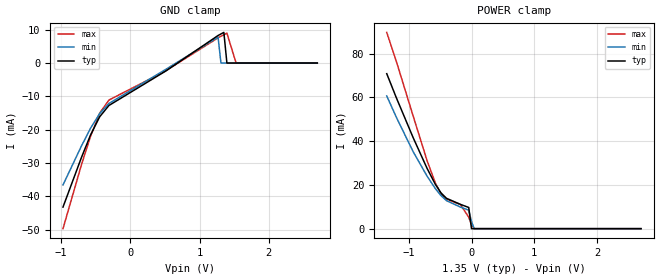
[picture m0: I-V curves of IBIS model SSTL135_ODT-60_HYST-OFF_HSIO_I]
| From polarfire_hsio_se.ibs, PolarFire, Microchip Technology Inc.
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|   Model SSTL135_ODT-60_HYST-OFF_HSIO_I
[Model]   SSTL135_ODT-60_HYST-OFF_HSIO_I
Model_type   Input
Vinl =   0.585
Vinh =   0.765
|   typ   min   max
C_comp_pullup   1.335e-12   1.335e-12   1.380e-12
C_comp_pulldown  1.335e-12   1.335e-12   1.380e-12
[Temperature Range]  25C   100C   -40C
[Voltage Range]  1.35   1.2825   1.4175
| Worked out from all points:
|   POWER clamp passes 1 mA (typ) near -0.00 V on its own axis
[GND Clamp]
| Voltage   I(typ)   I(min)   I(max)
-974.5mV  -43.26mA   -36.61mA   -49.74mA
-708.7mV  -28.42mA   -24.96mA   -30.62mA
-575.9mV  -21.58mA   -19.56mA   -21.99mA
-443mV    -16.1mA    -15.14mA   -14.99mA
-310.1mV  -12.74mA   -12.14mA   -11.12mA
506.2mV   -2.456mA   -1.971mA   -2.402mA
1.266V    8.254mA    7.797mA    7.564mA
1.308V    8.727mA    0A         8.037mA
1.35V     9.195mA    0A         8.497mA
1.394V    0A         0A         8.97mA
1.527V    0A         0A         0A
2.7V      0A         0A         0A
[POWER Clamp]
| Voltage   I(typ)   I(min)   I(max)
-1.35V    70.85mA    60.68mA    89.73mA
-1.196V   59.77mA    50.86mA    76.37mA
-930.2mV  41.66mA    35.24mA    51.57mA
-708.7mV  27.62mA    24.06mA    31.2mA
-575.9mV  20.28mA    18.32mA    20.87mA
-487.3mV  16.4mA     15.15mA    16.01mA
-398.7mV  13.87mA    12.81mA    13.48mA
-177.2mV  11.12mA    9.875mA    11.04mA
-44.3mV   9.682mA    8.453mA    5.258mA
0V        0A         3.3mA      1.807mA
42.19mV   0A         0A         0A
2.7V      0A         0A         0A
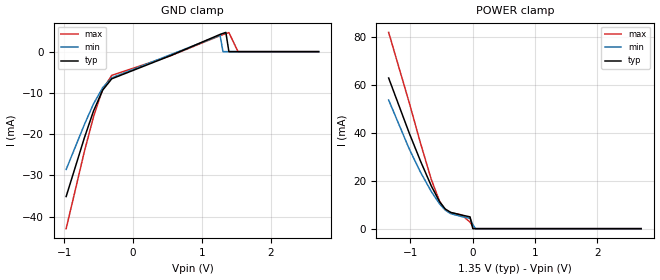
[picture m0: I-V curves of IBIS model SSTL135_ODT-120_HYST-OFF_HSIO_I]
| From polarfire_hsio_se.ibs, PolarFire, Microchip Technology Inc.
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|   Model SSTL135_ODT-120_HYST-OFF_HSIO_I
[Model]   SSTL135_ODT-120_HYST-OFF_HSIO_I
Model_type   Input
Vinl =   0.585
Vinh =   0.765
|   typ   min   max
C_comp_pullup   1.335e-12   1.335e-12   1.380e-12
C_comp_pulldown  1.335e-12   1.335e-12   1.380e-12
[Temperature Range]  25C   100C   -40C
[Voltage Range]  1.35   1.2825   1.4175
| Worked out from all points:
|   POWER clamp passes 1 mA (typ) near -0.01 V on its own axis
[GND Clamp]
| Voltage   I(typ)   I(min)   I(max)
-974.5mV  -35.14mA   -28.58mA   -42.93mA
-708.7mV  -20.87mA   -17.66mA   -24.18mA
-575.9mV  -14.38mA   -12.66mA   -15.79mA
-443mV    -9.331mA   -8.73mA    -9.118mA
-310.1mV  -6.579mA   -6.343mA   -5.736mA
548.4mV   -943.3uA   -710.7uA   -975.8uA
1.266V    4.181mA    3.947mA    3.885mA
1.308V    4.426mA    0A         4.134mA
1.35V     4.669mA    0A         4.376mA
1.394V    0A         0A         4.626mA
1.527V    0A         0A         0A
2.7V      0A         0A         0A
[POWER Clamp]
| Voltage   I(typ)   I(min)   I(max)
-1.35V    62.93mA    53.74mA    81.99mA
-1.019V   39.87mA    33.27mA    52.55mA
-841.6mV  28.38mA    23.71mA    35.93mA
-664.5mV  17.76mA    15.44mA    20.42mA
-531.6mV  11.2mA     10.31mA    11.36mA
-443mV    8.221mA    7.776mA    7.944mA
-354.4mV  6.785mA    6.272mA    6.711mA
-177.2mV  5.674mA    5.027mA    5.719mA
-44.3mV   4.922mA    4.286mA    2.72mA
0V        0A         1.672mA    935.1uA
42.19mV   0A         0A         0A
2.7V      0A         0A         0A
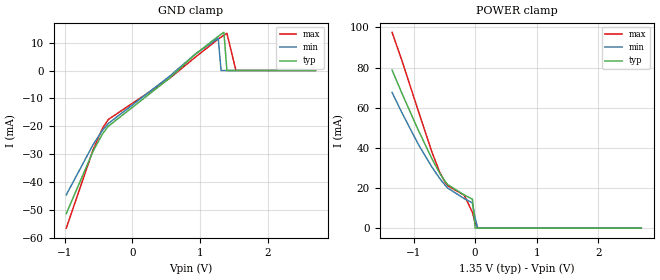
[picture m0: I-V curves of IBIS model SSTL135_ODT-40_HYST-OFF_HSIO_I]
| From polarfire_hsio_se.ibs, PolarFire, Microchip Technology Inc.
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|   Model SSTL135_ODT-40_HYST-OFF_HSIO_I
[Model]   SSTL135_ODT-40_HYST-OFF_HSIO_I
Model_type   Input
Vinl =   0.585
Vinh =   0.765
|   typ   min   max
C_comp_pullup   1.335e-12   1.335e-12   1.380e-12
C_comp_pulldown  1.335e-12   1.335e-12   1.380e-12
[Temperature Range]  25C   100C   -40C
[Voltage Range]  1.35   1.2825   1.4175
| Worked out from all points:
|   POWER clamp passes 1 mA (typ) near -0.00 V on its own axis
[GND Clamp]
| Voltage   I(typ)   I(min)   I(max)
-974.5mV  -51.38mA   -44.62mA   -56.57mA
-575.9mV  -28.78mA   -26.44mA   -28.21mA
-443mV    -22.86mA   -21.55mA   -20.88mA
-354.4mV  -19.99mA   -18.99mA   -17.56mA
548.4mV   -2.742mA   -2.059mA   -2.818mA
928.1mV   5.821mA    5.92mA     4.781mA
1.266V    12.29mA    11.62mA    11.28mA
1.308V    12.99mA    0A         11.99mA
1.35V     13.69mA    0A         12.67mA
1.394V    0A         0A         13.36mA
1.527V    0A         0A         0A
2.7V      0A         0A         0A
[POWER Clamp]
| Voltage   I(typ)   I(min)   I(max)
-1.35V    78.73mA    67.6mA     97.53mA
-1.196V   67.56mA    57.82mA    84mA
-930.2mV  49.22mA    42.12mA    58.98mA
-708.7mV  34.92mA    30.71mA    38.39mA
-575.9mV  27.34mA    24.74mA    27.84mA
-487.3mV  23.23mA    21.34mA    22.74mA
-443mV    21.63mA    19.91mA    21.05mA
-177.2mV  16.53mA    14.7mA     16.41mA
-44.3mV   14.41mA    12.6mA     7.822mA
0V        0A         4.919mA    2.689mA
42.19mV   0A         0A         0A
2.7V      0A         0A         0A
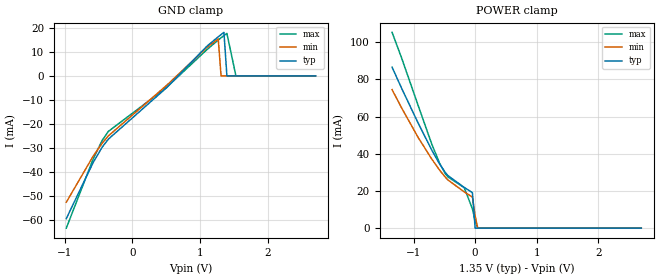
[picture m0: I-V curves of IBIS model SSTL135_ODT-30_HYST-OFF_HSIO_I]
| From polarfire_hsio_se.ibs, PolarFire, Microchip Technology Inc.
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|   Model SSTL135_ODT-30_HYST-OFF_HSIO_I
[Model]   SSTL135_ODT-30_HYST-OFF_HSIO_I
Model_type   Input
Vinl =   0.585
Vinh =   0.765
|   typ   min   max
C_comp_pullup   1.335e-12   1.335e-12   1.380e-12
C_comp_pulldown  1.335e-12   1.335e-12   1.380e-12
[Temperature Range]  25C   100C   -40C
[Voltage Range]  1.35   1.2825   1.4175
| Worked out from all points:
|   POWER clamp passes 1 mA (typ) near -0.00 V on its own axis
[GND Clamp]
| Voltage   I(typ)   I(min)   I(max)
-974.5mV  -59.47mA   -52.63mA   -63.42mA
-575.9mV  -35.95mA   -33.33mA   -34.44mA
-443mV    -29.6mA    -27.95mA   -26.77mA
-354.4mV  -26.35mA   -25mA      -23.13mA
506.2mV   -4.877mA   -3.916mA   -4.742mA
1.097V    12.33mA    11.81mA    10.89mA
1.266V    16.29mA    15.41mA    14.96mA
1.308V    17.22mA    0A         15.89mA
1.35V     18.14mA    0A         16.79mA
1.394V    0A         0A         17.71mA
1.527V    0A         0A         0A
2.7V      0A         0A         0A
[POWER Clamp]
| Voltage   I(typ)   I(min)   I(max)
-1.35V    86.56mA    74.48mA    105.3mA
-1.196V   75.3mA     64.73mA    91.58mA
-930.2mV  56.74mA    48.96mA    66.33mA
-708.7mV  42.18mA    37.32mA    45.51mA
-575.9mV  34.37mA    31.12mA    34.74mA
-487.3mV  30.02mA    27.5mA     29.41mA
-443mV    28.26mA    25.93mA    27.56mA
-177.2mV  21.9mA     19.49mA    21.72mA
-44.3mV   19.09mA    16.7mA     10.36mA
0V        0A         6.522mA    3.56mA
42.19mV   0A         0A         0A
2.7V      0A         0A         0A
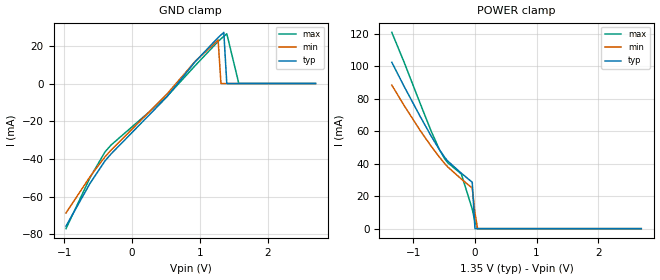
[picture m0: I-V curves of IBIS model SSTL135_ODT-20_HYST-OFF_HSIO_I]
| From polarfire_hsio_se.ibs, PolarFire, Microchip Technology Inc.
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|   Model SSTL135_ODT-20_HYST-OFF_HSIO_I
[Model]   SSTL135_ODT-20_HYST-OFF_HSIO_I
Model_type   Input
Vinl =   0.585
Vinh =   0.765
|   typ   min   max
C_comp_pullup   1.335e-12   1.335e-12   1.380e-12
C_comp_pulldown  1.335e-12   1.335e-12   1.380e-12
[Temperature Range]  25C   100C   -40C
[Voltage Range]  1.35   1.2825   1.4175
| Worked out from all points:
|   POWER clamp passes 1 mA (typ) near -0.00 V on its own axis
[GND Clamp]
| Voltage   I(typ)   I(min)   I(max)
-974.5mV  -75.69mA   -68.7mA    -77.05mA
-620.2mV  -52.99mA   -49.41mA   -49.94mA
-398.7mV  -41.01mA   -38.86mA   -36.23mA
-310.1mV  -37.36mA   -35.33mA   -32.63mA
506.2mV   -7.295mA   -5.867mA   -7.094mA
928.1mV   11.57mA    11.78mA    9.499mA
1.266V    24.39mA    23.08mA    22.34mA
1.308V    25.77mA    0A         23.71mA
1.35V     27.14mA    0A         25.05mA
1.394V    0A         0A         26.42mA
1.571V    0A         0A         0A
2.7V      0A         0A         0A
[POWER Clamp]
| Voltage   I(typ)   I(min)   I(max)
-1.35V    102.4mA    88.31mA    120.8mA
-1.152V   87.68mA    75.91mA    102.6mA
-885.9mV  68.81mA    60.2mA     76.72mA
-708.7mV  56.81mA    50.62mA    59.8mA
-575.9mV  48.52mA    43.95mA    48.59mA
-487.3mV  43.71mA    39.89mA    42.79mA
-443mV    41.65mA    38.04mA    40.63mA
-221.5mV  34.12mA    30.52mA    33.66mA
-44.3mV   28.56mA    25mA       12.08mA
0V        0A         9.761mA    4.152mA
42.19mV   0A         0A         0A
2.7V      0A         0A         0A
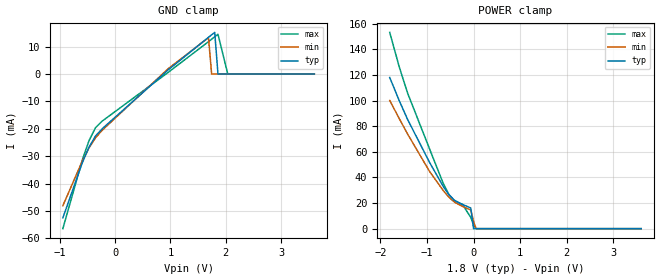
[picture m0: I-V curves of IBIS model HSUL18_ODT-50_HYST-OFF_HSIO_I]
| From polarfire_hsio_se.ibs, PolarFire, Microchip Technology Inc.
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|   Model HSUL18_ODT-50_HYST-OFF_HSIO_I
[Model]   HSUL18_ODT-50_HYST-OFF_HSIO_I
Model_type   Input
Vinl =   0.54
Vinh =   1.26
|   typ   min   max
C_comp_pullup   1.335e-12   1.335e-12   1.380e-12
C_comp_pulldown  1.335e-12   1.335e-12   1.380e-12
[Temperature Range]  25C   100C   -40C
[Voltage Range]  1.8   1.71   1.89
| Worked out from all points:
|   POWER clamp passes 1 mA (typ) near -0.00 V on its own axis
[GND Clamp]
| Voltage   I(typ)   I(min)   I(max)
-945mV    -52.51mA   -48.08mA   -56.44mA
-590.6mV  -32.24mA   -31.63mA   -31.19mA
-472.5mV  -26.71mA   -26.99mA   -24.35mA
-354.4mV  -22.62mA   -23.3mA    -19.58mA
-236.2mV  -20.03mA   -20.58mA   -17.23mA
956.3mV   1.457mA    1.895mA    551.4uA
1.688V    13.4mA     13.26mA    11.81mA
1.744V    14.29mA    0A         12.69mA
1.8V      15.18mA    0A         13.57mA
1.859V    0A         0A         14.5mA
2.036V    0A         0A         0A
3.6V      0A         0A         0A
[POWER Clamp]
| Voltage   I(typ)   I(min)   I(max)
-1.8V     118mA      100.1mA    153.2mA
-1.595V   99.86mA    85.87mA    126.2mA
-1.417V   85.32mA    73.93mA    105.9mA
-945mV    51.73mA    44.68mA    62.29mA
-649.7mV  32.89mA    29.69mA    35.25mA
-531.6mV  26.62mA    24.68mA    26.84mA
-413.4mV  22.21mA    20.79mA    21.92mA
-236.2mV  18.92mA    17.36mA    18.75mA
-59.06mV  16.11mA    14.54mA    8.799mA
0V        0A         5.655mA    3.025mA
56.25mV   0A         0A         0A
3.6V      0A         0A         0A
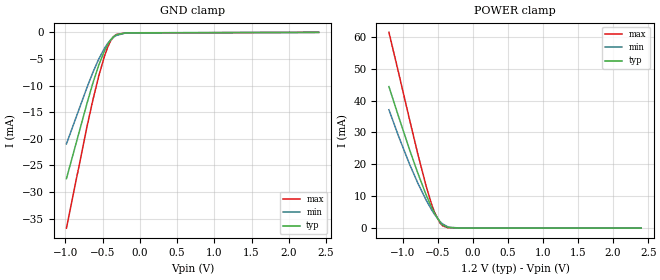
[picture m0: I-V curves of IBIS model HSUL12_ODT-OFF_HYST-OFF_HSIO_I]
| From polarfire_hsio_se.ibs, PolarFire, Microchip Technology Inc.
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|   Model HSUL12_ODT-OFF_HYST-OFF_HSIO_I
[Model]   HSUL12_ODT-OFF_HYST-OFF_HSIO_I
Model_type   Input
Vinl =   0.5
Vinh =   0.7
|   typ   min   max
C_comp_pullup   1.335e-12   1.335e-12   1.380e-12
C_comp_pulldown  1.335e-12   1.335e-12   1.380e-12
[Temperature Range]  25C   100C   -40C
[Voltage Range]  1.2   1.14   1.26
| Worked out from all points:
|   GND clamp passes 1 mA (typ) near -0.36 V on its own axis
|   POWER clamp passes 1 mA (typ) near -0.43 V on its own axis
[GND Clamp]
| Voltage   I(typ)   I(min)   I(max)
-984.4mV  -27.48mA   -20.95mA   -36.78mA
-708.7mV  -13.34mA   -10.36mA   -17.72mA
-630mV    -9.552mA   -7.537mA   -12.74mA
-551.3mV  -6.179mA   -5.019mA   -8.225mA
-472.5mV  -3.409mA   -2.949mA   -4.41mA
-433.1mV  -2.318mA   -2.123mA   -2.876mA
-393.7mV  -1.457mA   -1.452mA   -1.668mA
-354.4mV  -839.6uA   -939.1uA   -839.3uA
-315mV    -452.2uA   -576.7uA   -387.5uA
-196.9mV  -114.2uA   -137.4uA   -124.5uA
-39.38mV  -86.01uA   -72.88uA   -109uA
2.4V      0A         0A         0A
[POWER Clamp]
| Voltage   I(typ)   I(min)   I(max)
-1.2V     44.39mA    37.13mA    61.4mA
-1.063V   35.03mA    28.85mA    48.81mA
-905.6mV  24.61mA    20.06mA    34.04mA
-787.5mV  17.24mA    14.11mA    23.23mA
-669.4mV  10.45mA    8.813mA    13.21mA
-590.6mV  6.448mA    5.738mA    7.471mA
-551.3mV  4.699mA    4.375mA    5.072mA
-472.5mV  1.932mA    2.121mA    1.653mA
-433.1mV  1.018mA    1.297mA    730.7uA
-354.4mV  175.4uA    345.5uA    94.24uA
-196.9mV  21.05uA    35.36uA    23.97uA
2.4V      0A         0A         0A
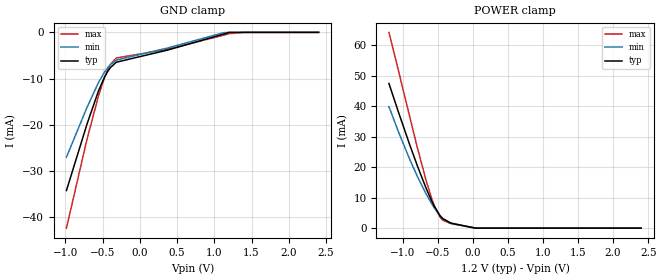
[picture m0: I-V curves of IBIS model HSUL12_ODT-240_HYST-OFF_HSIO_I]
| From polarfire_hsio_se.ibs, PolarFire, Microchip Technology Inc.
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|   Model HSUL12_ODT-240_HYST-OFF_HSIO_I
[Model]   HSUL12_ODT-240_HYST-OFF_HSIO_I
Model_type   Input
Vinl =   0.5
Vinh =   0.7
|   typ   min   max
C_comp_pullup   1.335e-12   1.335e-12   1.380e-12
C_comp_pulldown  1.335e-12   1.335e-12   1.380e-12
[Temperature Range]  25C   100C   -40C
[Voltage Range]  1.2   1.14   1.26
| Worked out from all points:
|   POWER clamp passes 1 mA (typ) near -0.20 V on its own axis
[GND Clamp]
| Voltage   I(typ)   I(min)   I(max)
-984.4mV  -34.26mA   -27.03mA   -42.4mA
-708.7mV  -19.88mA   -16.26mA   -23.17mA
-551.3mV  -12.55mA   -10.76mA   -13.59mA
-472.5mV  -9.682mA   -8.596mA   -9.721mA
-433.1mV  -8.533mA   -7.719mA   -8.154mA
-393.7mV  -7.61mA    -6.993mA   -6.909mA
-315mV    -6.464mA   -5.994mA   -5.545mA
375mV     -3.824mA   -3.375mA   -3.648mA
1.125V    -374.2uA   -70uA      -612.9uA
1.2V      486.4nA    0A         -274uA
1.397V    0A         0A         0A
2.4V      0A         0A         0A
[POWER Clamp]
| Voltage   I(typ)   I(min)   I(max)
-1.2V     47.38mA    39.79mA    64.13mA
-1.063V   37.94mA    31.5mA     51.49mA
-905.6mV  27.45mA    22.65mA    36.68mA
-787.5mV  20mA       16.63mA    25.78mA
-669.4mV  13.06mA    11.23mA    15.64mA
-590.6mV  8.929mA    8.031mA    9.783mA
-551.3mV  7.099mA    6.592mA    7.309mA
-472.5mV  4.126mA    4.152mA    3.688mA
-433.1mV  3.081mA    3.211mA    2.634mA
-315mV    1.626mA    1.635mA    1.464mA
37.5mV    0A         0A         0A
2.4V      0A         0A         0A
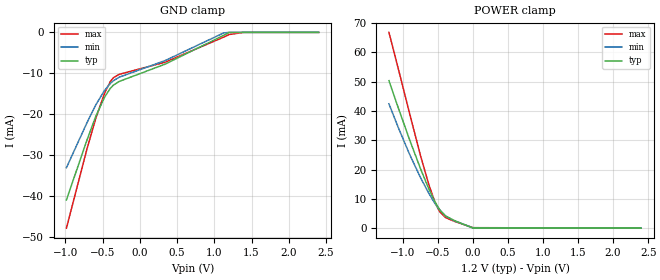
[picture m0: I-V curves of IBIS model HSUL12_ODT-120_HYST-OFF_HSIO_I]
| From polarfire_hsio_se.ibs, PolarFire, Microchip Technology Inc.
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|   Model HSUL12_ODT-120_HYST-OFF_HSIO_I
[Model]   HSUL12_ODT-120_HYST-OFF_HSIO_I
Model_type   Input
Vinl =   0.5
Vinh =   0.7
|   typ   min   max
C_comp_pullup   1.335e-12   1.335e-12   1.380e-12
C_comp_pulldown  1.335e-12   1.335e-12   1.380e-12
[Temperature Range]  25C   100C   -40C
[Voltage Range]  1.2   1.14   1.26
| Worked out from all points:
|   POWER clamp passes 1 mA (typ) near -0.10 V on its own axis
[GND Clamp]
| Voltage   I(typ)   I(min)   I(max)
-984.4mV  -40.98mA   -33.11mA   -47.89mA
-708.7mV  -26.34mA   -22.1mA    -28.5mA
-590.6mV  -20.55mA   -17.74mA   -21.04mA
-472.5mV  -15.85mA   -14.18mA   -14.87mA
-393.7mV  -13.65mA   -12.46mA   -11.98mA
-354.4mV  -12.9mA    -11.83mA   -11.08mA
-275.6mV  -12mA      -10.96mA   -10.26mA
337.5mV   -7.787mA   -6.919mA   -7.313mA
1.125V    -722uA     -136.9uA   -1.167mA
1.2V      473.9nA    0A         -521.3uA
1.397V    0A         0A         0A
2.4V      0A         0A         0A
[POWER Clamp]
| Voltage   I(typ)   I(min)   I(max)
-1.2V     50.35mA    42.44mA    66.84mA
-1.063V   40.82mA    34.14mA    54.11mA
-905.6mV  30.21mA    25.22mA    39.19mA
-748.1mV  20.21mA    17.19mA    24.65mA
-630mV    13.36mA    11.86mA    14.81mA
-551.3mV  9.384mA    8.731mA    9.394mA
-511.9mV  7.673mA    7.342mA    7.246mA
-472.5mV  6.208mA    6.105mA    5.572mA
-393.7mV  4.164mA    4.194mA    3.631mA
-275.6mV  2.681mA    2.599mA    2.41mA
0V        0A         83.48uA    156.6uA
2.4V      0A         0A         0A
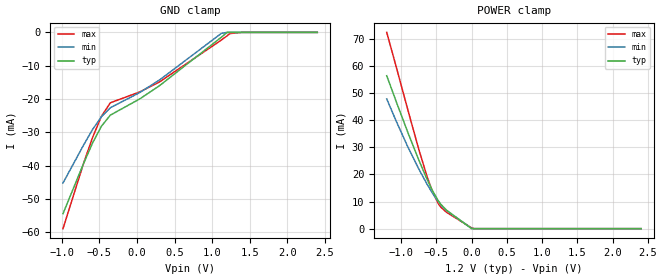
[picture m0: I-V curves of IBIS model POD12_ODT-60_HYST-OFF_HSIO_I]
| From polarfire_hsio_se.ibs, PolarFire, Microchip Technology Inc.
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|   Model POD12_ODT-60_HYST-OFF_HSIO_I
[Model]   POD12_ODT-60_HYST-OFF_HSIO_I
Model_type   Input
Vinl =   0.76
Vinh =   0.92
|   typ   min   max
C_comp_pullup   1.335e-12   1.335e-12   1.380e-12
C_comp_pulldown  1.335e-12   1.335e-12   1.380e-12
[Temperature Range]  25C   100C   -40C
[Voltage Range]  1.2   1.14   1.26
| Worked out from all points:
|   POWER clamp passes 1 mA (typ) near -0.05 V on its own axis
[GND Clamp]
| Voltage   I(typ)   I(min)   I(max)
-984.4mV  -54.44mA   -45.23mA   -58.93mA
-708.7mV  -39.27mA   -33.76mA   -39.19mA
-590.6mV  -33.2mA    -29.15mA   -31.55mA
-472.5mV  -28.17mA   -25.31mA   -25.17mA
-354.4mV  -24.84mA   -22.62mA   -21.14mA
37.5mV    -19.97mA   -18.05mA   -17.87mA
300mV     -16mA      -14.29mA   -14.87mA
1.125V    -1.416mA   -270.5uA   -2.271mA
1.2V      471.4nA    0A         -1.014mA
1.239V    0A         0A         -349.2uA
1.397V    0A         0A         0A
2.4V      0A         0A         0A
[POWER Clamp]
| Voltage   I(typ)   I(min)   I(max)
-1.2V     56.3mA     47.75mA    72.27mA
-1.063V   46.58mA    39.41mA    59.32mA
-905.6mV  35.72mA    30.36mA    44.17mA
-748.1mV  25.4mA     22.05mA    29.37mA
-630mV    18.22mA    16.41mA    19.24mA
-551.3mV  13.94mA    13mA       13.55mA
-472.5mV  10.36mA    10mA       9.326mA
-433.1mV  8.93mA     8.719mA    7.888mA
-354.4mV  6.816mA    6.637mA    6.04mA
0V        0A         163.6uA    304uA
37.5mV    0A         0A         0A
2.4V      0A         0A         0A
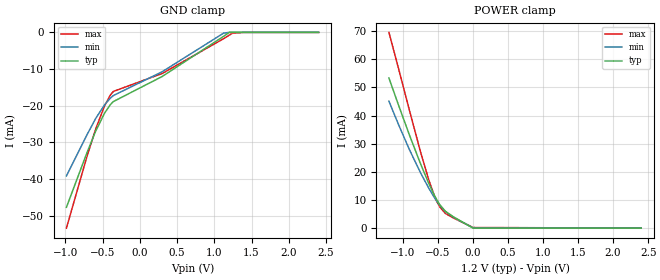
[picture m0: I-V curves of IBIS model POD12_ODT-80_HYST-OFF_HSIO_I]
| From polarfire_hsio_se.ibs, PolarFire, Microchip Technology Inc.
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|   Model POD12_ODT-80_HYST-OFF_HSIO_I
[Model]   POD12_ODT-80_HYST-OFF_HSIO_I
Model_type   Input
Vinl =   0.76
Vinh =   0.92
|   typ   min   max
C_comp_pullup   1.335e-12   1.335e-12   1.380e-12
C_comp_pulldown  1.335e-12   1.335e-12   1.380e-12
[Temperature Range]  25C   100C   -40C
[Voltage Range]  1.2   1.14   1.26
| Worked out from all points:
|   POWER clamp passes 1 mA (typ) near -0.07 V on its own axis
[GND Clamp]
| Voltage   I(typ)   I(min)   I(max)
-984.4mV  -47.72mA   -39.18mA   -53.41mA
-708.7mV  -32.82mA   -27.94mA   -33.84mA
-590.6mV  -26.88mA   -23.45mA   -26.29mA
-472.5mV  -22.02mA   -19.75mA   -20.02mA
-393.7mV  -19.69mA   -17.92mA   -17.06mA
-354.4mV  -18.87mA   -17.23mA   -16.11mA
300mV     -12.04mA   -10.75mA   -11.22mA
1.125V    -1.069mA   -203.7uA   -1.72mA
1.2V      471.4nA    0A         -768.1uA
1.239V    0A         0A         -264.5uA
1.397V    0A         0A         0A
2.4V      0A         0A         0A
[POWER Clamp]
| Voltage   I(typ)   I(min)   I(max)
-1.2V     53.33mA    45.1mA     69.55mA
-1.063V   43.7mA     36.78mA    56.71mA
-905.6mV  32.96mA    27.79mA    41.68mA
-748.1mV  22.81mA    19.62mA    27.01mA
-630mV    15.79mA    14.14mA    17.03mA
-551.3mV  11.66mA    10.86mA    11.47mA
-511.9mV  9.86mA     9.39mA     9.234mA
-472.5mV  8.286mA    8.055mA    7.45mA
-393.7mV  5.963mA    5.897mA    5.238mA
-275.6mV  3.957mA    3.821mA    3.542mA
0V        0A         123.6uA    230.5uA
2.4V      0A         0A         0A
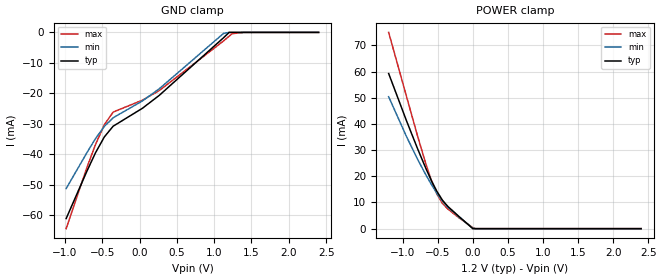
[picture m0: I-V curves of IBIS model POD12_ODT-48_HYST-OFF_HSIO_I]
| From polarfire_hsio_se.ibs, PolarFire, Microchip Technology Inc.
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|   Model POD12_ODT-48_HYST-OFF_HSIO_I
[Model]   POD12_ODT-48_HYST-OFF_HSIO_I
Model_type   Input
Vinl =   0.76
Vinh =   0.92
|   typ   min   max
C_comp_pullup   1.335e-12   1.335e-12   1.380e-12
C_comp_pulldown  1.335e-12   1.335e-12   1.380e-12
[Temperature Range]  25C   100C   -40C
[Voltage Range]  1.2   1.14   1.26
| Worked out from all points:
|   POWER clamp passes 1 mA (typ) near -0.04 V on its own axis
[GND Clamp]
| Voltage   I(typ)   I(min)   I(max)
-984.4mV  -61.14mA   -51.29mA   -64.44mA
-708.7mV  -45.71mA   -39.6mA    -44.53mA
-590.6mV  -39.51mA   -34.86mA   -36.8mA
-472.5mV  -34.32mA   -30.88mA   -30.31mA
-354.4mV  -30.8mA    -28.02mA   -26.16mA
37.5mV    -24.92mA   -22.52mA   -22.26mA
262.5mV   -20.7mA    -18.54mA   -19.12mA
1.125V    -1.763mA   -337.2uA   -2.822mA
1.2V      472.4nA    0A         -1.26mA
1.239V    0A         0A         -434uA
1.397V    0A         0A         0A
2.4V      0A         0A         0A
[POWER Clamp]
| Voltage   I(typ)   I(min)   I(max)
-1.2V     59.28mA    50.4mA     74.98mA
-945mV    41.17mA    35.15mA    50.47mA
-787.5mV  30.55mA    26.51mA    35.37mA
-669.4mV  23.02mA    20.56mA    24.73mA
-590.6mV  18.37mA    16.87mA    18.4mA
-511.9mV  14.23mA    13.48mA    13.2mA
-433.1mV  10.88mA    10.55mA    9.633mA
-354.4mV  8.448mA    8.191mA    7.487mA
-196.9mV  4.646mA    4.456mA    4.145mA
0V        0A         203.7uA    377.6uA
37.5mV    0A         0A         0A
2.4V      0A         0A         0A
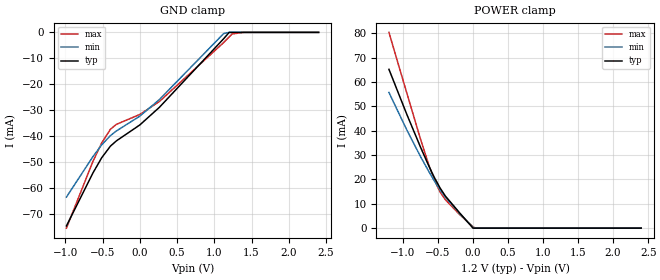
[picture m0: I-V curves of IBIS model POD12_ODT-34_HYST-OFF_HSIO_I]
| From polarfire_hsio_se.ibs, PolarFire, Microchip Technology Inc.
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|   Model POD12_ODT-34_HYST-OFF_HSIO_I
[Model]   POD12_ODT-34_HYST-OFF_HSIO_I
Model_type   Input
Vinl =   0.76
Vinh =   0.92
|   typ   min   max
C_comp_pullup   1.335e-12   1.335e-12   1.380e-12
C_comp_pulldown  1.335e-12   1.335e-12   1.380e-12
[Temperature Range]  25C   100C   -40C
[Voltage Range]  1.2   1.14   1.26
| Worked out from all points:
|   POWER clamp passes 1 mA (typ) near -0.03 V on its own axis
[GND Clamp]
| Voltage   I(typ)   I(min)   I(max)
-984.4mV  -74.59mA   -63.47mA   -75.44mA
-630mV    -54.24mA   -47.93mA   -49.81mA
-511.9mV  -48.34mA   -43.37mA   -42.64mA
-393.7mV  -43.83mA   -39.77mA   -37.33mA
-315mV    -41.83mA   -38.01mA   -35.46mA
0V        -35.68mA   -32.29mA   -31.64mA
262.5mV   -28.9mA    -25.9mA    -26.66mA
1.125V    -2.456mA   -470.6uA   -3.926mA
1.2V      476.1nA    0A         -1.753mA
1.239V    0A         0A         -603.6uA
1.397V    0A         0A         0A
2.4V      0A         0A         0A
[POWER Clamp]
| Voltage   I(typ)   I(min)   I(max)
-1.2V     65.23mA    55.71mA    80.39mA
-945mV    46.73mA    40.33mA    55.5mA
-748.1mV  33.17mA    29.33mA    36.43mA
-630mV    25.5mA     23.23mA    25.88mA
-551.3mV  20.77mA    19.39mA    19.77mA
-472.5mV  16.59mA    15.85mA    14.95mA
-393.7mV  13.15mA    12.7mA     11.65mA
-196.9mV  6.469mA    6.205mA    5.76mA
0V        0A         283.8uA    524.8uA
37.5mV    0A         0A         0A
2.4V      0A         0A         0A
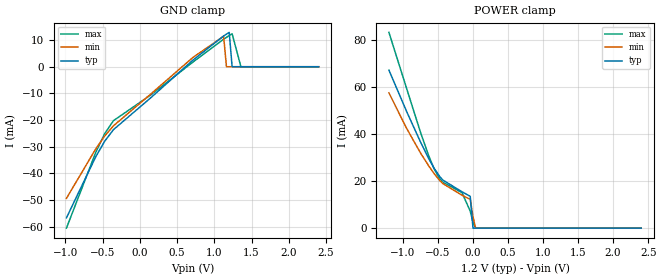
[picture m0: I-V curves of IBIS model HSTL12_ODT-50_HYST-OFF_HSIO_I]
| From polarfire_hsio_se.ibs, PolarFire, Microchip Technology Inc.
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|   Model HSTL12_ODT-50_HYST-OFF_HSIO_I
[Model]   HSTL12_ODT-50_HYST-OFF_HSIO_I
Model_type   Input
Vinl =   0.5
Vinh =   0.7
|   typ   min   max
C_comp_pullup   1.335e-12   1.335e-12   1.380e-12
C_comp_pulldown  1.335e-12   1.335e-12   1.380e-12
[Temperature Range]  25C   100C   -40C
[Voltage Range]  1.2   1.14   1.26
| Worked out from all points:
|   POWER clamp passes 1 mA (typ) near -0.00 V on its own axis
[GND Clamp]
| Voltage   I(typ)   I(min)   I(max)
-984.4mV  -56.7mA    -49.38mA   -60.55mA
-590.6mV  -33.76mA   -30.81mA   -32.11mA
-472.5mV  -28mA      -26.05mA   -25.16mA
-354.4mV  -23.63mA   -22.19mA   -20.26mA
150mV     -11.57mA   -10.18mA   -10.52mA
712.5mV   2.471mA    3.478mA    1.744mA
1.125V    11.54mA    11.42mA    10.33mA
1.163V    12.23mA    0A         11.02mA
1.2V      12.89mA    0A         11.69mA
1.239V    0A         0A         12.37mA
1.357V    0A         0A         0A
2.4V      0A         0A         0A
[POWER Clamp]
| Voltage   I(typ)   I(min)   I(max)
-1.2V     67.33mA    57.64mA    83.43mA
-945mV    49.54mA    42.38mA    59.29mA
-748.1mV  36.63mA    31.98mA    40.72mA
-630mV    29.52mA    26.43mA    30.65mA
-551.3mV  25.33mA    23.1mA     25.03mA
-472.5mV  21.88mA    20.23mA    20.94mA
-433.1mV  20.54mA    19.03mA    19.6mA
-157.5mV  15.49mA    14.04mA    15.13mA
-39.38mV  13.56mA    12.26mA    7.236mA
0V        0A         4.801mA    2.488mA
37.5mV    0A         0A         0A
2.4V      0A         0A         0A
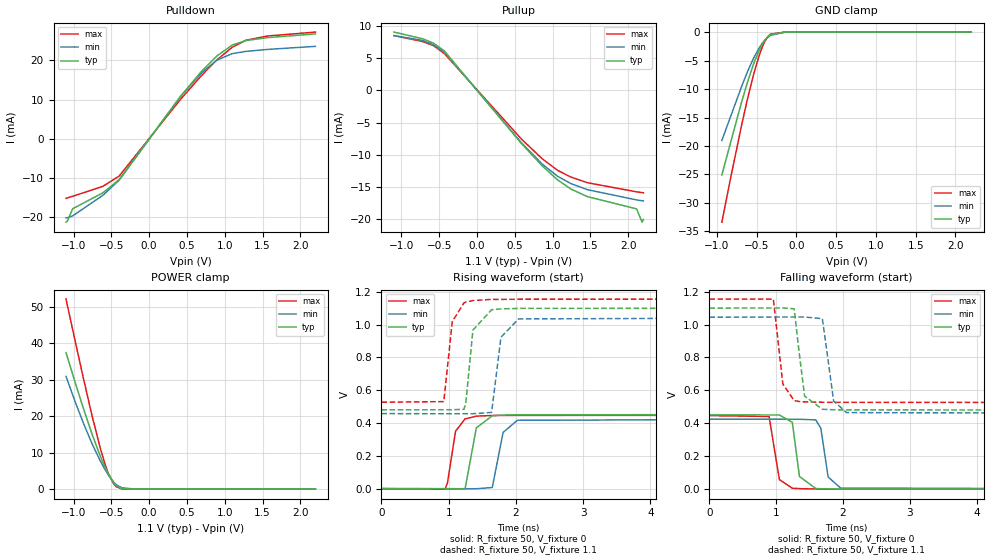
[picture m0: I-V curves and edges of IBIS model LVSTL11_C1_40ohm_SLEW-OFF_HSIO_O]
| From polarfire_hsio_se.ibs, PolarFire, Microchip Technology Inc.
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|   Model LVSTL11_C1_40ohm_SLEW-OFF_HSIO_O
[Model]   LVSTL11_C1_40ohm_SLEW-OFF_HSIO_O
Model_type   Output
Polarity   Non-Inverting
Enable   Active-High
Vmeas =   0.55
Cref =   5p
Rref =   50
Vref =   0.55
|   typ   min   max
C_comp_pullup   1.335e-12   1.335e-12   1.380e-12
C_comp_pulldown  1.335e-12   1.335e-12   1.380e-12
[Temperature Range]  25C   100C   -40C
[Voltage Range]  1.1   1.045   1.155
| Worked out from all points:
|   slope of the pulldown table from 0 to 0.165 V, typ, clamps not added: 37.2 ohm
|   slope of the pullup table from 0 to 0.165 V, typ, clamps not added: 69.1 ohm
|   GND clamp passes 1 mA (typ) near -0.37 V on its own axis
|   POWER clamp passes 1 mA (typ) near -0.44 V on its own axis
|   rising waveform, R_fixture 50, V_fixture 0: 20-80 % time 103ps typ, 115ps min, 109ps max; typ from 0 V to 0.451 V
|   rising waveform, R_fixture 50, V_fixture 1.1: 20-80 % time 92.6ps typ, 101ps min, 91.8ps max; typ from 0.48 V to 1.1 V
|   falling waveform, R_fixture 50, V_fixture 0: 20-80 % time 82.4ps typ, 89.2ps min, 79.3ps max; typ from 0.451 V to 0 V
|   falling waveform, R_fixture 50, V_fixture 1.1: 20-80 % time 92ps typ, 101ps min, 89.6ps max; typ from 1.1 V to 0.48 V
[GND Clamp]
| Voltage   I(typ)   I(min)   I(max)
-938.4mV  -25.11mA   -19.03mA   -33.38mA
-830.2mV  -19.49mA   -14.91mA   -25.78mA
-685.8mV  -12.09mA   -9.417mA   -16.09mA
-613.6mV  -8.697mA   -6.887mA   -11.62mA
-541.4mV  -5.686mA   -4.64mA    -7.568mA
-469.2mV  -3.203mA   -2.785mA   -4.138mA
-433.1mV  -2.213mA   -2.034mA   -2.744mA
-397mV    -1.416mA   -1.414mA   -1.624mA
-360.9mV  -823.7uA   -927.9uA   -821.7uA
-324.8mV  -429.2uA   -569.8uA   -343.3uA
-144.4mV  -4.828uA   -19.16uA   -973.1nA
2.2V      0A         0A         0A
[POWER Clamp]
| Voltage   I(typ)   I(min)   I(max)
-1.1V     37.46mA    30.95mA    52.16mA
-974.5mV  29mA       23.73mA    40.25mA
-866.2mV  21.91mA    17.93mA    30.08mA
-758mV    15.25mA    12.59mA    20.36mA
-649.7mV  9.216mA    7.857mA    11.48mA
-577.5mV  5.7mA      5.137mA    6.467mA
-541.4mV  4.17mA     3.936mA    4.395mA
-469.2mV  1.751mA    1.95mA     1.452mA
-433.1mV  941.2uA    1.216mA    645.5uA
-360.9mV  155.7uA    378.3uA    59.24uA
-180.5mV  709.2nA    8.113uA    497.5nA
2.2V      0A         0A         0A
[Pullup]
| Voltage   I(typ)   I(min)   I(max)
-1.1V     9.05mA     8.508mA    8.503mA
-721.9mV  8.022mA    7.768mA    7.593mA
-577.5mV  7.331mA    7.09mA     6.957mA
-433.1mV  6.131mA    5.968mA    5.73mA
584.4mV   -8.191mA   -8.065mA   -7.5mA
859.4mV   -11.66mA   -11.38mA   -10.57mA
1.066V    -13.87mA   -13.31mA   -12.39mA
1.244V    -15.3mA    -14.45mA   -13.44mA
1.461V    -16.46mA   -15.38mA   -14.3mA
2.111V    -18.36mA   -16.97mA   -15.72mA
2.183V    -20.42mA   -17.1mA    -15.83mA
2.2V      -20mA      -17.13mA   -15.86mA
[Pulldown]
| Voltage   I(typ)   I(min)   I(max)
-1.1V     -21.3mA    -20.2mA    -15.22mA
-1.083V   -21.05mA   -20.17mA   -15.1mA
-1.011V   -17.86mA   -19.69mA   -14.68mA
-613.6mV  -13.82mA   -14.46mA   -12.16mA
-397mV    -10.43mA   -10.58mA   -9.529mA
412.5mV   10.76mA    10.72mA    9.993mA
687.5mV   17.1mA     16.71mA    16.05mA
893.8mV   21.1mA     20.05mA    20.09mA
1.1V      23.93mA    21.74mA    23.37mA
1.28V     25.07mA    22.3mA     25.16mA
1.569V    25.83mA    22.81mA    26.23mA
2.2V      26.77mA    23.59mA    27.23mA
[Ramp]
dV/dt_r   0.270859/0.103376n  0.255302/0.11487n  0.26816/0.108886n
dV/dt_f   0.371862/92.0312p  0.352825/0.101495n  0.377161/89.5589p
R_load = 50
[Rising Waveform]
R_fixture = 50
V_fixture = 0
V_fixture_min = 0
V_fixture_max = 0
| Time   V(typ)   V(min)   V(max)
0s        1.098uV    1.292uV    1.603uV
946ps     -530.9uV   -473.5uV   -3.335mV
982ps     -551.1uV   -491.5uV   35.18mV
1.102ns   -618.6uV   -551.8uV   349.7mV
1.243ns   -2.719mV   -622.5uV   424.7mV
1.411ns   370.4mV    -706.8uV   441.6mV
1.648ns   443.9mV    6.697mV    445.5mV
1.809ns   448.2mV    342.2mV    446mV
2.021ns   450.2mV    416.7mV    446.3mV
10ns      451.4mV    425.5mV    446.9mV
[Rising Waveform]
R_fixture = 50
V_fixture = 1.1
V_fixture_min = 1.045
V_fixture_max = 1.155
| Time   V(typ)   V(min)   V(max)
0s        480.2mV    456.9mV    526.4mV
927ps     480.7mV    456.4mV    530.1mV
1.053ns   480.7mV    456.3mV    1.017V
1.227ns   483.2mV    456.2mV    1.132V
1.254ns   520mV      456.2mV    1.136V
1.36ns    965.5mV    456.1mV    1.146V
1.638ns   1.09V      464.4mV    1.153V
1.777ns   1.095V     922.8mV    1.153V
2.04ns    1.098V     1.034V     1.154V
10ns      1.1V       1.045V     1.155V
[Falling Waveform]
R_fixture = 50
V_fixture = 0
V_fixture_min = 0
V_fixture_max = 0
| Time   V(typ)   V(min)   V(max)
0s        451.4mV    425.5mV    446.9mV
894ps     450.9mV    425.1mV    441.6mV
1.048ns   450.8mV    425mV      58.44mV
1.242ns   406mV      424.9mV    5.683mV
1.349ns   76.84mV    424.8mV    3.231mV
1.593ns   3.979mV    420.8mV    1.095mV
1.669ns   2.595mV    370.5mV    964.5uV
1.778ns   1.644mV    73.97mV    777.8uV
1.966ns   1.029mV    6.538mV    455.7uV
10ns      2.55uV     2.406uV    2.536uV
[Falling Waveform]
R_fixture = 50
V_fixture = 1.1
V_fixture_min = 1.045
V_fixture_max = 1.155
| Time   V(typ)   V(min)   V(max)
0s        1.1V       1.045V     1.155V
958ps     1.101V     1.046V     1.155V
1.1ns     1.101V     1.046V     638.8mV
1.27ns    1.096V     1.046V     538.1mV
1.344ns   830.9mV    1.046V     532.8mV
1.426ns   565.4mV    1.046V     530.2mV
1.692ns   485.2mV    1.036V     528mV
1.861ns   482.4mV    535.4mV    527.7mV
2.054ns   481.6mV    465.1mV    527.5mV
10ns      480.2mV    456.9mV    526.4mV
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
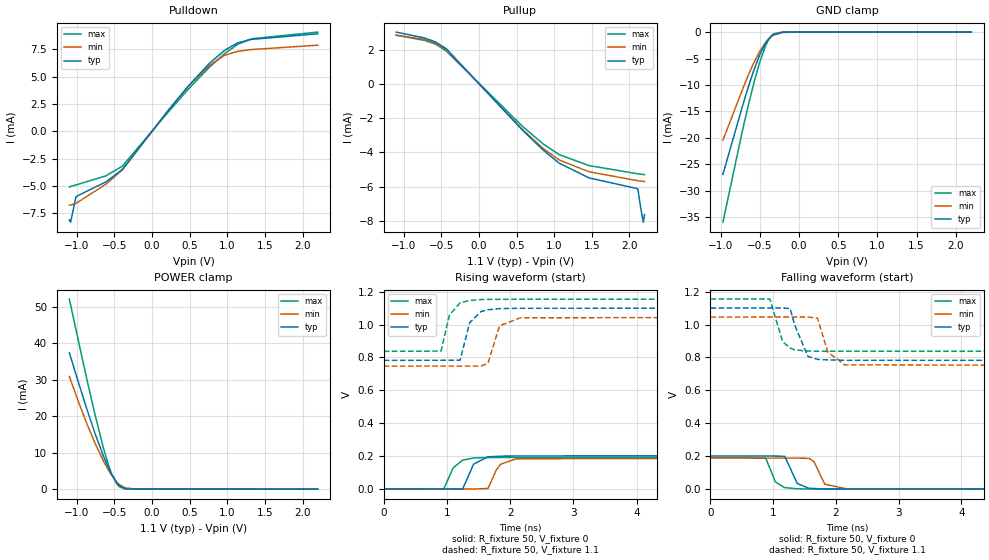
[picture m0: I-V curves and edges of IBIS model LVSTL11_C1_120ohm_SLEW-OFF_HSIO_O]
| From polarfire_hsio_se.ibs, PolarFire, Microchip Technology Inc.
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|   Model LVSTL11_C1_120ohm_SLEW-OFF_HSIO_O
[Model]   LVSTL11_C1_120ohm_SLEW-OFF_HSIO_O
Model_type   Output
Polarity   Non-Inverting
Enable   Active-High
Vmeas =   0.55
Cref =   5p
Rref =   50
Vref =   0.55
|   typ   min   max
C_comp_pullup   1.335e-12   1.335e-12   1.380e-12
C_comp_pulldown  1.335e-12   1.335e-12   1.380e-12
[Temperature Range]  25C   100C   -40C
[Voltage Range]  1.1   1.045   1.155
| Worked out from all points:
|   slope of the pulldown table from 0 to 0.165 V, typ, clamps not added: 111 ohm
|   slope of the pullup table from 0 to 0.165 V, typ, clamps not added: 207 ohm
|   GND clamp passes 1 mA (typ) near -0.37 V on its own axis
|   POWER clamp passes 1 mA (typ) near -0.44 V on its own axis
|   rising waveform, R_fixture 50, V_fixture 0: 20-80 % time 147ps typ, 154ps min, 148ps max; typ from 0 V to 0.202 V
|   rising waveform, R_fixture 50, V_fixture 1.1: 20-80 % time 132ps typ, 145ps min, 129ps max; typ from 0.782 V to 1.1 V
|   falling waveform, R_fixture 50, V_fixture 0: 20-80 % time 116ps typ, 132ps min, 111ps max; typ from 0.202 V to 0 V
|   falling waveform, R_fixture 50, V_fixture 1.1: 20-80 % time 142ps typ, 156ps min, 136ps max; typ from 1.1 V to 0.782 V
[GND Clamp]
| Voltage   I(typ)   I(min)   I(max)
-974.5mV  -26.89mA   -20.44mA   -35.93mA
-721.9mV  -13.88mA   -10.75mA   -18.43mA
-649.7mV  -10.35mA   -8.123mA   -13.81mA
-577.5mV  -7.136mA   -5.721mA   -9.53mA
-505.3mV  -4.368mA   -3.657mA   -5.76mA
-433.1mV  -2.213mA   -2.034mA   -2.744mA
-397mV    -1.416mA   -1.414mA   -1.625mA
-360.9mV  -823.7uA   -927.9uA   -821.7uA
-324.8mV  -429.2uA   -569.8uA   -343.3uA
-216.6mV  -34.07uA   -87.33uA   -11.46uA
-36.09mV  -193.3nA   -1.231uA   -49.27nA
2.2V      0A         0A         0A
[POWER Clamp]
| Voltage   I(typ)   I(min)   I(max)
-1.1V     37.46mA    30.95mA    52.16mA
-974.5mV  29mA       23.73mA    40.25mA
-866.2mV  21.91mA    17.93mA    30.08mA
-758mV    15.25mA    12.59mA    20.36mA
-649.7mV  9.216mA    7.857mA    11.48mA
-577.5mV  5.7mA      5.137mA    6.467mA
-541.4mV  4.17mA     3.936mA    4.395mA
-469.2mV  1.751mA    1.95mA     1.452mA
-433.1mV  941.2uA    1.216mA    645.5uA
-360.9mV  155.7uA    378.3uA    59.24uA
-216.6mV  1.401uA    23.09uA    544.6nA
2.2V      0A         0A         0A
[Pullup]
| Voltage   I(typ)   I(min)   I(max)
-1.1V     3.016mA    2.835mA    2.835mA
-721.9mV  2.674mA    2.589mA    2.532mA
-577.5mV  2.443mA    2.363mA    2.32mA
-433.1mV  2.044mA    1.99mA     1.911mA
584.4mV   -2.73mA    -2.689mA   -2.501mA
859.4mV   -3.887mA   -3.793mA   -3.526mA
1.066V    -4.625mA   -4.439mA   -4.13mA
1.461V    -5.486mA   -5.127mA   -4.768mA
2.111V    -6.116mA   -5.651mA   -5.248mA
2.147V    -7.184mA   -5.671mA   -5.268mA
2.183V    -8.069mA   -5.69mA    -5.287mA
2.2V      -7.626mA   -5.7mA     -5.296mA
[Pulldown]
| Voltage   I(typ)   I(min)   I(max)
-1.1V     -8.078mA   -6.736mA   -5.075mA
-1.083V   -8.295mA   -6.729mA   -5.036mA
-1.011V   -5.956mA   -6.57mA    -4.894mA
-613.6mV  -4.612mA   -4.825mA   -4.057mA
-397mV    -3.484mA   -3.533mA   -3.182mA
206.2mV   1.846mA    1.855mA    1.705mA
481.3mV   4.15mA     4.12mA     3.863mA
756.2mV   6.185mA    6.003mA    5.831mA
962.5mV   7.411mA    6.954mA    7.107mA
1.136V    8.087mA    7.31mA     7.95mA
1.317V    8.403mA    7.475mA    8.46mA
2.2V      8.921mA    7.878mA    9.073mA
[Ramp]
dV/dt_r   0.12108/0.147369n  0.113388/0.153931n  0.115569/0.14775n
dV/dt_f   0.190645/0.141654n  0.178508/0.155726n  0.190666/0.135613n
R_load = 50
[Rising Waveform]
R_fixture = 50
V_fixture = 0
V_fixture_min = 0
V_fixture_max = 0
| Time   V(typ)   V(min)   V(max)
0s        950nV      1.406uV    1.427uV
948ps     -586.9uV   -108.8uV   -1.196mV
1.098ns   -679.9uV   -126.3uV   127.8mV
1.248ns   -886.2uV   -143.7uV   175.4mV
1.422ns   150.8mV    -164uV     188.3mV
1.65ns    195.6mV    3.042mV    191.5mV
1.782ns   198mV      116.5mV    191.6mV
1.847ns   199.1mV    149.9mV    191.7mV
2.093ns   201mV      183.6mV    191.9mV
10ns      201.8mV    189mV      192.6mV
[Rising Waveform]
R_fixture = 50
V_fixture = 1.1
V_fixture_min = 1.045
V_fixture_max = 1.155
| Time   V(typ)   V(min)   V(max)
0s        782.2mV    747.4mV    837.2mV
907ps     782.9mV    747.4mV    838.6mV
1.04ns    783mV      747.4mV    1.058V
1.208ns   783.1mV    747.4mV    1.132V
1.359ns   1.01V      747.4mV    1.146V
1.537ns   1.079V     747.4mV    1.152V
1.648ns   1.09V      763.7mV    1.153V
1.832ns   1.097V     992.2mV    1.153V
2.161ns   1.099V     1.041V     1.154V
10ns      1.1V       1.045V     1.155V
[Falling Waveform]
R_fixture = 50
V_fixture = 0
V_fixture_min = 0
V_fixture_max = 0
| Time   V(typ)   V(min)   V(max)
0s        201.8mV    189mV      192.6mV
879ps     201.2mV    188.7mV    190.3mV
1.036ns   201.1mV    188.6mV    43.78mV
1.185ns   199.4mV    188.5mV    9.313mV
1.384ns   34.3mV     188.5mV    2.336mV
1.573ns   5.421mV    187.1mV    817.5uV
1.651ns   3.855mV    166.9mV    809.9uV
1.822ns   1.059mV    30.23mV    793.3uV
2.179ns   798.5uV    1.307mV    758.7uV
10ns      1.156uV    2.15uV     692.6nV
[Falling Waveform]
R_fixture = 50
V_fixture = 1.1
V_fixture_min = 1.045
V_fixture_max = 1.155
| Time   V(typ)   V(min)   V(max)
0s        1.1V       1.045V     1.155V
947ps     1.101V     1.046V     1.155V
1.152ns   1.101V     1.046V     894.9mV
1.271ns   1.097V     1.046V     857.7mV
1.344ns   995.6mV    1.046V     845.6mV
1.554ns   806.6mV    1.046V     839.6mV
1.706ns   788.8mV    1.039V     838.3mV
1.87ns    785.3mV    833.2mV    838.2mV
2.141ns   783.2mV    755.3mV    838mV
10ns      782.2mV    747.4mV    837.2mV
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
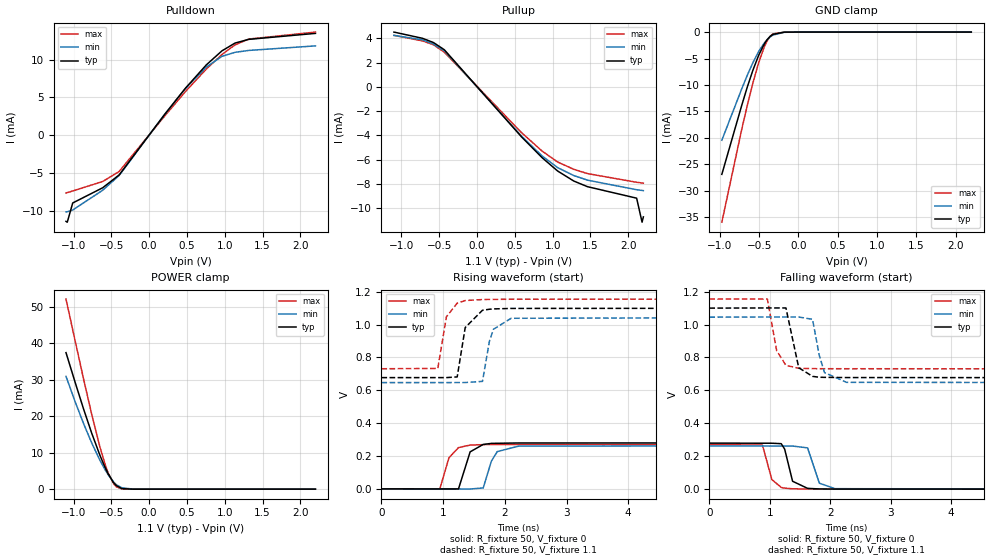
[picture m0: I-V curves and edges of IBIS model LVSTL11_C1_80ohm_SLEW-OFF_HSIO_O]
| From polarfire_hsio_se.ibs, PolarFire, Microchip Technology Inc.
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|   Model LVSTL11_C1_80ohm_SLEW-OFF_HSIO_O
[Model]   LVSTL11_C1_80ohm_SLEW-OFF_HSIO_O
Model_type   Output
Polarity   Non-Inverting
Enable   Active-High
Vmeas =   0.55
Cref =   5p
Rref =   50
Vref =   0.55
|   typ   min   max
C_comp_pullup   1.335e-12   1.335e-12   1.380e-12
C_comp_pulldown  1.335e-12   1.335e-12   1.380e-12
[Temperature Range]  25C   100C   -40C
[Voltage Range]  1.1   1.045   1.155
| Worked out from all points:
|   slope of the pulldown table from 0 to 0.165 V, typ, clamps not added: 74.1 ohm
|   slope of the pullup table from 0 to 0.165 V, typ, clamps not added: 138 ohm
|   GND clamp passes 1 mA (typ) near -0.37 V on its own axis
|   POWER clamp passes 1 mA (typ) near -0.44 V on its own axis
|   rising waveform, R_fixture 50, V_fixture 0: 20-80 % time 132ps typ, 143ps min, 131ps max; typ from 0 V to 0.28 V
|   rising waveform, R_fixture 50, V_fixture 1.1: 20-80 % time 120ps typ, 131ps min, 117ps max; typ from 0.677 V to 1.1 V
|   falling waveform, R_fixture 50, V_fixture 0: 20-80 % time 106ps typ, 117ps min, 102ps max; typ from 0.28 V to 0 V
|   falling waveform, R_fixture 50, V_fixture 1.1: 20-80 % time 125ps typ, 137ps min, 124ps max; typ from 1.1 V to 0.677 V
[GND Clamp]
| Voltage   I(typ)   I(min)   I(max)
-974.5mV  -26.89mA   -20.44mA   -35.93mA
-721.9mV  -13.88mA   -10.75mA   -18.43mA
-649.7mV  -10.35mA   -8.123mA   -13.81mA
-577.5mV  -7.136mA   -5.721mA   -9.53mA
-505.3mV  -4.368mA   -3.657mA   -5.76mA
-433.1mV  -2.213mA   -2.034mA   -2.744mA
-397mV    -1.416mA   -1.414mA   -1.625mA
-360.9mV  -823.7uA   -927.9uA   -821.7uA
-324.8mV  -429.2uA   -569.8uA   -343.3uA
-180.5mV  -13.02uA   -41.71uA   -3.341uA
-36.09mV  -193.3nA   -1.231uA   -49.27nA
2.2V      0A         0A         0A
[POWER Clamp]
| Voltage   I(typ)   I(min)   I(max)
-1.1V     37.46mA    30.95mA    52.16mA
-974.5mV  29mA       23.73mA    40.25mA
-866.2mV  21.91mA    17.93mA    30.08mA
-758mV    15.25mA    12.59mA    20.36mA
-649.7mV  9.216mA    7.857mA    11.48mA
-577.5mV  5.7mA      5.137mA    6.467mA
-541.4mV  4.17mA     3.936mA    4.395mA
-469.2mV  1.751mA    1.95mA     1.452mA
-433.1mV  941.2uA    1.216mA    645.5uA
-360.9mV  155.7uA    378.3uA    59.24uA
-216.6mV  1.401uA    23.09uA    544.6nA
2.2V      0A         0A         0A
[Pullup]
| Voltage   I(typ)   I(min)   I(max)
-1.1V     4.524mA    4.253mA    4.252mA
-721.9mV  4.011mA    3.884mA    3.797mA
-577.5mV  3.665mA    3.545mA    3.479mA
-433.1mV  3.066mA    2.985mA    2.866mA
584.4mV   -4.096mA   -4.034mA   -3.751mA
859.4mV   -5.831mA   -5.69mA    -5.289mA
1.066V    -6.938mA   -6.658mA   -6.195mA
1.28V     -7.766mA   -7.314mA   -6.799mA
1.461V    -8.231mA   -7.691mA   -7.151mA
2.111V    -9.178mA   -8.482mA   -7.867mA
2.183V    -11.16mA   -8.542mA   -7.925mA
2.2V      -10.72mA   -8.556mA   -7.938mA
[Pulldown]
| Voltage   I(typ)   I(min)   I(max)
-1.1V     -11.35mA   -10.1mA    -7.614mA
-1.083V   -11.46mA   -10.09mA   -7.557mA
-1.011V   -8.923mA   -9.854mA   -7.343mA
-613.6mV  -6.915mA   -7.239mA   -6.087mA
-397mV    -5.224mA   -5.3mA     -4.77mA
206.2mV   2.77mA     2.783mA    2.555mA
481.3mV   6.229mA    6.178mA    5.79mA
756.2mV   9.29mA     9.001mA    8.741mA
962.5mV   11.14mA    10.42mA    10.66mA
1.136V    12.17mA    10.95mA    11.93mA
1.317V    12.66mA    11.2mA     12.7mA
2.2V      13.45mA    11.8mA     13.62mA
[Ramp]
dV/dt_r   0.16784/0.132399n  0.157575/0.143053n  0.162365/0.131335n
dV/dt_f   0.253774/0.124643n  0.238971/0.137326n  0.254448/0.124146n
R_load = 50
[Rising Waveform]
R_fixture = 50
V_fixture = 0
V_fixture_min = 0
V_fixture_max = 0
| Time   V(typ)   V(min)   V(max)
0s        1.002uV    1.365uV    1.487uV
945ps     -503.1uV   -567uV     -1.918mV
1.094ns   -582.5uV   -656.6uV   189mV
1.249ns   -413.7uV   -749.8uV   251.1mV
1.438ns   225.3mV    -863.5uV   266.4mV
1.65ns    270.3mV    5.44mV     269mV
1.782ns   276.7mV    168.3mV    269.6mV
1.877ns   277.3mV    226.7mV    269.6mV
2.224ns   279.2mV    260mV      269.9mV
10ns      279.7mV    262.6mV    270.6mV
[Rising Waveform]
R_fixture = 50
V_fixture = 1.1
V_fixture_min = 1.045
V_fixture_max = 1.155
| Time   V(typ)   V(min)   V(max)
0s        677mV      646.7mV    730.9mV
914ps     677mV      646.8mV    732.8mV
1.053ns   677mV      646.8mV    1.047V
1.228ns   681.2mV    646.9mV    1.13V
1.358ns   981.7mV    646.9mV    1.146V
1.638ns   1.087V     654.1mV    1.152V
1.75ns    1.093V     897.7mV    1.153V
1.815ns   1.095V     971mV      1.153V
2.102ns   1.098V     1.038V     1.154V
10ns      1.1V       1.045V     1.155V
[Falling Waveform]
R_fixture = 50
V_fixture = 0
V_fixture_min = 0
V_fixture_max = 0
| Time   V(typ)   V(min)   V(max)
0s        279.7mV    262.6mV    270.6mV
878ps     279.2mV    262.2mV    268.1mV
1.034ns   279.1mV    262.1mV    58.45mV
1.189ns   276.4mV    262mV      10.53mV
1.246ns   243.2mV    262mV      6.186mV
1.377ns   48.04mV    262mV      2.328mV
1.625ns   4.822mV    250.8mV    854.6uV
1.82ns    1.306mV    36.48mV    834.8uV
2.079ns   583uV      2.871mV    808.4uV
10ns      1.853uV    1.872uV    1.574uV
[Falling Waveform]
R_fixture = 50
V_fixture = 1.1
V_fixture_min = 1.045
V_fixture_max = 1.155
| Time   V(typ)   V(min)   V(max)
0s        1.1V       1.045V     1.155V
960ps     1.101V     1.046V     1.155V
1.113ns   1.101V     1.046V     842.2mV
1.267ns   1.101V     1.046V     752.2mV
1.479ns   737.7mV    1.046V     734.3mV
1.707ns   685.4mV    1.032V     732.4mV
1.817ns   679.9mV    815.4mV    731.9mV
1.905ns   679.3mV    708.5mV    731.9mV
2.27ns    678.1mV    649mV      731.7mV
10ns      677mV      646.7mV    730.9mV
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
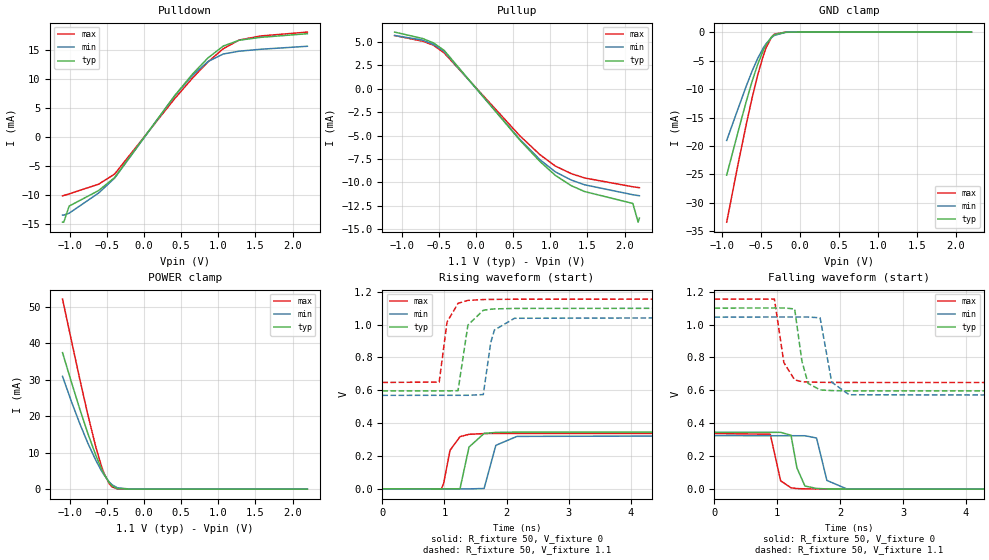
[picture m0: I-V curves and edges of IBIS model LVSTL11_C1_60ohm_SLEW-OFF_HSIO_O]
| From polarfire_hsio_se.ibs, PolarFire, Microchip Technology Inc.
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|   Model LVSTL11_C1_60ohm_SLEW-OFF_HSIO_O
[Model]   LVSTL11_C1_60ohm_SLEW-OFF_HSIO_O
Model_type   Output
Polarity   Non-Inverting
Enable   Active-High
Vmeas =   0.55
Cref =   5p
Rref =   50
Vref =   0.55
|   typ   min   max
C_comp_pullup   1.335e-12   1.335e-12   1.380e-12
C_comp_pulldown  1.335e-12   1.335e-12   1.380e-12
[Temperature Range]  25C   100C   -40C
[Voltage Range]  1.1   1.045   1.155
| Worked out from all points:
|   slope of the pulldown table from 0 to 0.165 V, typ, clamps not added: 55.7 ohm
|   slope of the pullup table from 0 to 0.165 V, typ, clamps not added: 104 ohm
|   GND clamp passes 1 mA (typ) near -0.37 V on its own axis
|   POWER clamp passes 1 mA (typ) near -0.44 V on its own axis
|   rising waveform, R_fixture 50, V_fixture 0: 20-80 % time 123ps typ, 132ps min, 125ps max; typ from 0 V to 0.346 V
|   rising waveform, R_fixture 50, V_fixture 1.1: 20-80 % time 109ps typ, 120ps min, 107ps max; typ from 0.596 V to 1.1 V
|   falling waveform, R_fixture 50, V_fixture 0: 20-80 % time 99.3ps typ, 103ps min, 92.5ps max; typ from 0.346 V to 0 V
|   falling waveform, R_fixture 50, V_fixture 1.1: 20-80 % time 110ps typ, 120ps min, 110ps max; typ from 1.1 V to 0.596 V
[GND Clamp]
| Voltage   I(typ)   I(min)   I(max)
-938.4mV  -25.11mA   -19.03mA   -33.38mA
-794.1mV  -17.59mA   -13.51mA   -23.29mA
-685.8mV  -12.09mA   -9.417mA   -16.09mA
-613.6mV  -8.697mA   -6.887mA   -11.62mA
-541.4mV  -5.686mA   -4.64mA    -7.568mA
-469.2mV  -3.203mA   -2.785mA   -4.138mA
-433.1mV  -2.213mA   -2.034mA   -2.744mA
-360.9mV  -823.7uA   -927.9uA   -821.7uA
-324.8mV  -429.2uA   -569.8uA   -343.3uA
-180.5mV  -13.02uA   -41.71uA   -3.341uA
-36.09mV  -193.3nA   -1.231uA   -49.27nA
2.2V      0A         0A         0A
[POWER Clamp]
| Voltage   I(typ)   I(min)   I(max)
-1.1V     37.46mA    30.95mA    52.16mA
-974.5mV  29mA       23.73mA    40.25mA
-866.2mV  21.91mA    17.93mA    30.08mA
-758mV    15.25mA    12.59mA    20.36mA
-649.7mV  9.216mA    7.857mA    11.48mA
-577.5mV  5.7mA      5.137mA    6.467mA
-541.4mV  4.17mA     3.936mA    4.395mA
-469.2mV  1.751mA    1.95mA     1.452mA
-433.1mV  941.2uA    1.216mA    645.5uA
-360.9mV  155.7uA    378.3uA    59.24uA
-180.5mV  709.2nA    8.113uA    497.5nA
2.2V      0A         0A         0A
[Pullup]
| Voltage   I(typ)   I(min)   I(max)
-1.1V     6.034mA    5.673mA    5.668mA
-721.9mV  5.349mA    5.179mA    5.062mA
-577.5mV  4.888mA    4.727mA    4.638mA
-433.1mV  4.088mA    3.979mA    3.82mA
584.4mV   -5.46mA    -5.376mA   -5mA
859.4mV   -7.774mA   -7.584mA   -7.05mA
1.066V    -9.249mA   -8.876mA   -8.258mA
1.28V     -10.35mA   -9.751mA   -9.064mA
1.461V    -10.98mA   -10.26mA   -9.534mA
2.111V    -12.25mA   -11.32mA   -10.47mA
2.183V    -14.25mA   -11.41mA   -10.55mA
2.2V      -13.81mA   -11.43mA   -10.57mA
[Pulldown]
| Voltage   I(typ)   I(min)   I(max)
-1.1V     -14.68mA   -13.46mA   -10.15mA
-1.083V   -14.67mA   -13.45mA   -10.07mA
-1.011V   -11.9mA    -13.13mA   -9.789mA
-613.6mV  -9.217mA   -9.644mA   -8.115mA
-397mV    -6.961mA   -7.058mA   -6.36mA
412.5mV   7.183mA    7.15mA     6.671mA
653.1mV   10.92mA    10.69mA    10.23mA
859.4mV   13.68mA    13.06mA    12.99mA
1.066V    15.74mA    14.37mA    15.28mA
1.28V     16.75mA    14.86mA    16.78mA
1.569V    17.25mA    15.19mA    17.49mA
2.2V      17.88mA    15.71mA    18.16mA
[Ramp]
dV/dt_r   0.207508/0.122557n  0.195146/0.131692n  0.202688/0.124552n
dV/dt_f   0.302261/0.109747n  0.285692/0.120315n  0.304541/0.110466n
R_load = 50
[Rising Waveform]
R_fixture = 50
V_fixture = 0
V_fixture_min = 0
V_fixture_max = 0
| Time   V(typ)   V(min)   V(max)
0s        1.042uV    1.335uV    1.535uV
949ps     -575.6uV   -480.8uV   -2.362mV
988ps     -599.3uV   -500.7uV   34.7mV
1.09ns    -661.3uV   -552.5uV   234.2mV
1.251ns   412.8uV    -634.3uV   317.4mV
1.396ns   254mV      -708uV     331.5mV
1.639ns   337.1mV    1.812mV    336.1mV
1.828ns   343.2mV    264.6mV    336.8mV
2.169ns   344.9mV    319mV      337.1mV
10ns      345.8mV    325.2mV    337.8mV
[Rising Waveform]
R_fixture = 50
V_fixture = 1.1
V_fixture_min = 1.045
V_fixture_max = 1.155
| Time   V(typ)   V(min)   V(max)
0s        596.2mV    568.8mV    647.4mV
915ps     596.2mV    569.1mV    649.6mV
1.042ns   596.1mV    569.1mV    1.015V
1.219ns   597.3mV    569.1mV    1.129V
1.378ns   996.3mV    569.2mV    1.147V
1.626ns   1.087V     573.5mV    1.152V
1.745ns   1.093V     888.9mV    1.153V
1.805ns   1.095V     966.4mV    1.153V
2.128ns   1.098V     1.038V     1.154V
10ns      1.1V       1.045V     1.155V
[Falling Waveform]
R_fixture = 50
V_fixture = 0
V_fixture_min = 0
V_fixture_max = 0
| Time   V(typ)   V(min)   V(max)
0s        345.8mV    325.2mV    337.8mV
888ps     345.2mV    324.8mV    333.9mV
1.053ns   345.1mV    324.8mV    50.84mV
1.218ns   327.6mV    324.7mV    8.349mV
1.312ns   129.2mV    324.6mV    3.499mV
1.439ns   19.25mV    324.6mV    2.086mV
1.624ns   4.419mV    310.7mV    800.5uV
1.789ns   1.465mV    53.02mV    784.7uV
2.1ns     503.7uV    2.399mV    755.1uV
10ns      2.034uV    2.566uV    1.55uV
[Falling Waveform]
R_fixture = 50
V_fixture = 1.1
V_fixture_min = 1.045
V_fixture_max = 1.155
| Time   V(typ)   V(min)   V(max)
0s        1.1V       1.045V     1.155V
954ps     1.101V     1.046V     1.155V
1.104ns   1.101V     1.046V     769.2mV
1.276ns   1.095V     1.046V     664mV
1.391ns   778.6mV    1.046V     653.1mV
1.489ns   642.9mV    1.046V     651.1mV
1.681ns   603.2mV    1.041V     649.1mV
1.865ns   599mV      650.4mV    648.7mV
2.142ns   597.5mV    573.6mV    648.3mV
10ns      596.2mV    568.8mV    647.4mV
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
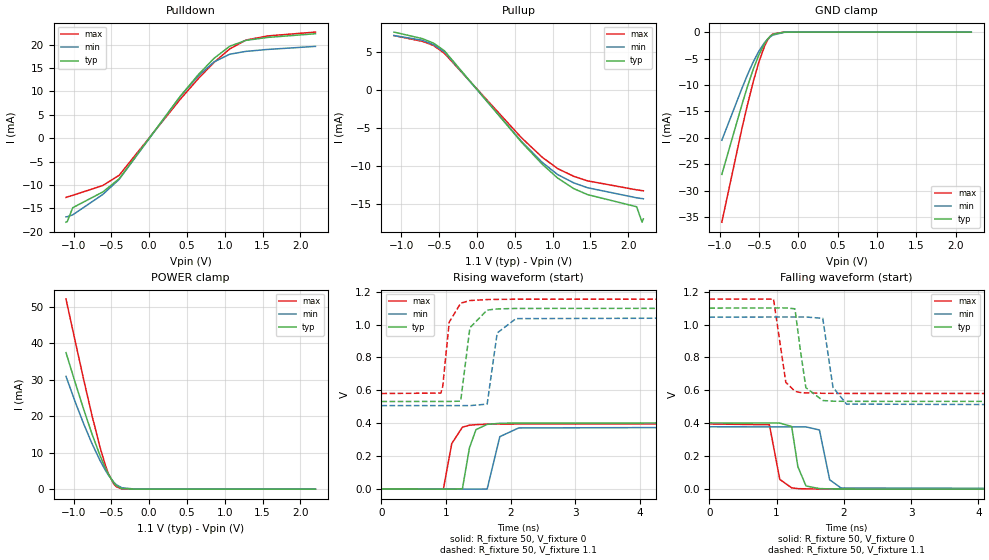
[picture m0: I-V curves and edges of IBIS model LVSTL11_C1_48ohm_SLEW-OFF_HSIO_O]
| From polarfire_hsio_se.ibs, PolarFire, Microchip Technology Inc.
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|   Model LVSTL11_C1_48ohm_SLEW-OFF_HSIO_O
[Model]   LVSTL11_C1_48ohm_SLEW-OFF_HSIO_O
Model_type   Output
Polarity   Non-Inverting
Enable   Active-High
Vmeas =   0.55
Cref =   5p
Rref =   50
Vref =   0.55
|   typ   min   max
C_comp_pullup   1.335e-12   1.335e-12   1.380e-12
C_comp_pulldown  1.335e-12   1.335e-12   1.380e-12
[Temperature Range]  25C   100C   -40C
[Voltage Range]  1.1   1.045   1.155
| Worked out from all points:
|   slope of the pulldown table from 0 to 0.165 V, typ, clamps not added: 44.6 ohm
|   slope of the pullup table from 0 to 0.165 V, typ, clamps not added: 83 ohm
|   GND clamp passes 1 mA (typ) near -0.37 V on its own axis
|   POWER clamp passes 1 mA (typ) near -0.44 V on its own axis
|   rising waveform, R_fixture 50, V_fixture 0: 20-80 % time 115ps typ, 123ps min, 117ps max; typ from 0 V to 0.402 V
|   rising waveform, R_fixture 50, V_fixture 1.1: 20-80 % time 101ps typ, 109ps min, 101ps max; typ from 0.532 V to 1.1 V
|   falling waveform, R_fixture 50, V_fixture 0: 20-80 % time 90.4ps typ, 94.8ps min, 85.1ps max; typ from 0.402 V to 0 V
|   falling waveform, R_fixture 50, V_fixture 1.1: 20-80 % time 100ps typ, 108ps min, 100ps max; typ from 1.1 V to 0.532 V
[GND Clamp]
| Voltage   I(typ)   I(min)   I(max)
-974.5mV  -26.89mA   -20.44mA   -35.93mA
-721.9mV  -13.88mA   -10.75mA   -18.43mA
-649.7mV  -10.35mA   -8.123mA   -13.81mA
-577.5mV  -7.136mA   -5.721mA   -9.53mA
-505.3mV  -4.368mA   -3.657mA   -5.76mA
-433.1mV  -2.213mA   -2.034mA   -2.744mA
-397mV    -1.416mA   -1.414mA   -1.624mA
-360.9mV  -823.7uA   -927.9uA   -821.7uA
-324.8mV  -429.2uA   -569.8uA   -343.3uA
-180.5mV  -13.02uA   -41.71uA   -3.341uA
-36.09mV  -193.3nA   -1.231uA   -49.27nA
2.2V      0A         0A         0A
[POWER Clamp]
| Voltage   I(typ)   I(min)   I(max)
-1.1V     37.46mA    30.95mA    52.16mA
-974.5mV  29mA       23.73mA    40.25mA
-866.2mV  21.91mA    17.93mA    30.08mA
-758mV    15.25mA    12.59mA    20.36mA
-649.7mV  9.216mA    7.857mA    11.48mA
-577.5mV  5.7mA      5.137mA    6.467mA
-541.4mV  4.17mA     3.936mA    4.395mA
-469.2mV  1.751mA    1.95mA     1.452mA
-433.1mV  941.2uA    1.216mA    645.5uA
-360.9mV  155.7uA    378.3uA    59.24uA
-180.5mV  709.2nA    8.113uA    497.5nA
2.2V      0A         0A         0A
[Pullup]
| Voltage   I(typ)   I(min)   I(max)
-1.1V     7.542mA    7.09mA     7.086mA
-721.9mV  6.685mA    6.474mA    6.328mA
-577.5mV  6.109mA    5.909mA    5.798mA
-433.1mV  5.109mA    4.974mA    4.775mA
584.4mV   -6.824mA   -6.722mA   -6.25mA
859.4mV   -9.715mA   -9.482mA   -8.813mA
1.066V    -11.56mA   -11.1mA    -10.32mA
1.28V     -12.94mA   -12.19mA   -11.33mA
1.461V    -13.72mA   -12.82mA   -11.92mA
2.111V    -15.31mA   -14.14mA   -13.1mA
2.183V    -17.33mA   -14.24mA   -13.2mA
2.2V      -16.9mA    -14.27mA   -13.22mA
[Pulldown]
| Voltage   I(typ)   I(min)   I(max)
-1.1V     -17.98mA   -16.83mA   -12.68mA
-1.083V   -17.85mA   -16.81mA   -12.59mA
-1.011V   -14.88mA   -16.41mA   -12.23mA
-613.6mV  -11.52mA   -12.05mA   -10.14mA
-397mV    -8.698mA   -8.82mA    -7.945mA
412.5mV   8.974mA    8.934mA    8.333mA
653.1mV   13.64mA    13.36mA    12.79mA
859.4mV   17.09mA    16.32mA    16.22mA
1.066V    19.66mA    17.96mA    19.09mA
1.28V     20.92mA    18.56mA    20.98mA
1.569V    21.55mA    18.98mA    21.87mA
2.2V      22.34mA    19.63mA    22.69mA
[Ramp]
dV/dt_r   0.241495/0.114792n  0.227468/0.123448n  0.237658/0.117201n
dV/dt_f   0.340749/0.100179n  0.322803/0.107912n  0.344543/0.100141n
R_load = 50
[Rising Waveform]
R_fixture = 50
V_fixture = 0
V_fixture_min = 0
V_fixture_max = 0
| Time   V(typ)   V(min)   V(max)
0s        1.073uV    1.311uV    1.572uV
958ps     -676.6uV   -573.4uV   -929.3uV
1.088ns   -768.5uV   -651.4uV   276.2mV
1.253ns   1.344mV    -750.4uV   376.2mV
1.362ns   250.7mV    -815.8uV   388.1mV
1.463ns   361.1mV    -876.4uV   391.2mV
1.636ns   393mV      4.017uV    394.3mV
1.832ns   399.5mV    318.4mV    395.1mV
2.123ns   401.5mV    371.4mV    395.2mV
10ns      402.5mV    379.1mV    396.1mV
[Rising Waveform]
R_fixture = 50
V_fixture = 1.1
V_fixture_min = 1.045
V_fixture_max = 1.155
| Time   V(typ)   V(min)   V(max)
0s        532.1mV    507mV      580.8mV
919ps     532.3mV    507mV      583.3mV
948ps     532.3mV    507mV      622.4mV
1.049ns   532.3mV    507mV      1.015V
1.226ns   534.4mV    507mV      1.13V
1.369ns   980.7mV    507mV      1.146V
1.636ns   1.088V     516.2mV    1.152V
1.791ns   1.095V     948.7mV    1.153V
2.081ns   1.098V     1.036V     1.154V
10ns      1.1V       1.045V     1.155V
[Falling Waveform]
R_fixture = 50
V_fixture = 0
V_fixture_min = 0
V_fixture_max = 0
| Time   V(typ)   V(min)   V(max)
0s        402.5mV    379.1mV    396.1mV
893ps     401.9mV    378.6mV    391.4mV
1.047ns   401.8mV    378.5mV    59.41mV
1.224ns   380.5mV    378.4mV    8.11mV
1.316ns   136.8mV    378.4mV    3.171mV
1.437ns   19.43mV    378.3mV    2.064mV
1.637ns   3.638mV    359.6mV    714.6uV
1.789ns   1.741mV    57.02mV    701.6uV
1.958ns   605.2uV    7.22mV     687.2uV
10ns      3.949uV    2.48uV     2.433uV
[Falling Waveform]
R_fixture = 50
V_fixture = 1.1
V_fixture_min = 1.045
V_fixture_max = 1.155
| Time   V(typ)   V(min)   V(max)
0s        1.1V       1.045V     1.155V
954ps     1.101V     1.046V     1.155V
1.137ns   1.101V     1.046V     649.1mV
1.273ns   1.096V     1.046V     594.6mV
1.349ns   857.3mV    1.046V     587.6mV
1.435ns   616.8mV    1.046V     584.9mV
1.686ns   538.8mV    1.038V     582.5mV
1.838ns   534.5mV    618.9mV    582.1mV
2.04ns    533.6mV    516.8mV    581.7mV
10ns      532.1mV    507mV      580.7mV
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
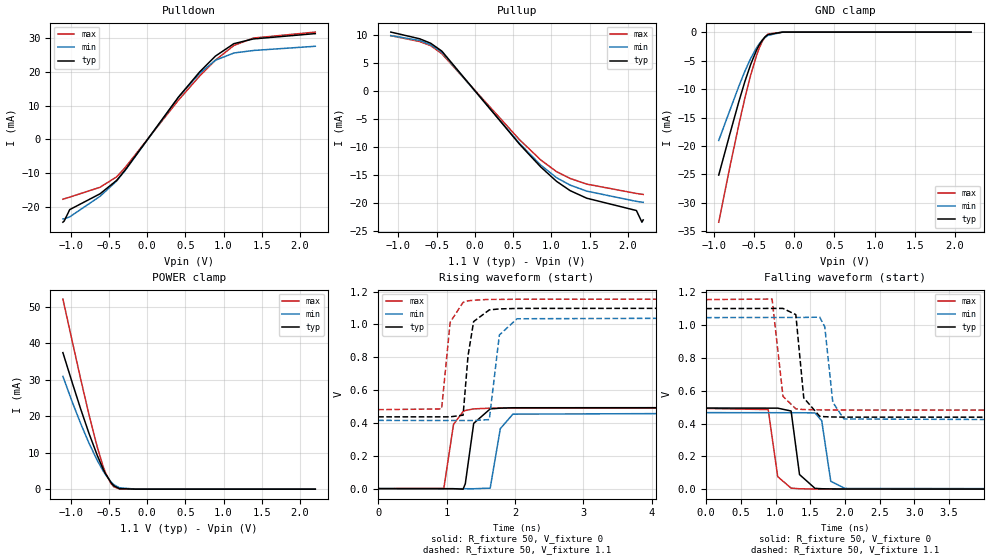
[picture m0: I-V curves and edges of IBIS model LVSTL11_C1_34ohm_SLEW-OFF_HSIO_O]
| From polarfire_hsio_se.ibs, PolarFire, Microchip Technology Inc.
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|   Model LVSTL11_C1_34ohm_SLEW-OFF_HSIO_O
[Model]   LVSTL11_C1_34ohm_SLEW-OFF_HSIO_O
Model_type   Output
Polarity   Non-Inverting
Enable   Active-High
Vmeas =   0.55
Cref =   5p
Rref =   50
Vref =   0.55
|   typ   min   max
C_comp_pullup   1.335e-12   1.335e-12   1.380e-12
C_comp_pulldown  1.335e-12   1.335e-12   1.380e-12
[Temperature Range]  25C   100C   -40C
[Voltage Range]  1.1   1.045   1.155
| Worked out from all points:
|   slope of the pulldown table from 0 to 0.165 V, typ, clamps not added: 31.9 ohm
|   slope of the pullup table from 0 to 0.165 V, typ, clamps not added: 59.2 ohm
|   GND clamp passes 1 mA (typ) near -0.37 V on its own axis
|   POWER clamp passes 1 mA (typ) near -0.44 V on its own axis
|   rising waveform, R_fixture 50, V_fixture 0: 20-80 % time 96.7ps typ, 107ps min, 102ps max; typ from 0 V to 0.494 V
|   rising waveform, R_fixture 50, V_fixture 1.1: 20-80 % time 85.7ps typ, 93.9ps min, 86.3ps max; typ from 0.437 V to 1.1 V
|   falling waveform, R_fixture 50, V_fixture 0: 20-80 % time 78.2ps typ, 79.3ps min, 75.9ps max; typ from 0.494 V to 0 V
|   falling waveform, R_fixture 50, V_fixture 1.1: 20-80 % time 84.4ps typ, 91.2ps min, 84ps max; typ from 1.1 V to 0.437 V
[GND Clamp]
| Voltage   I(typ)   I(min)   I(max)
-938.4mV  -25.11mA   -19.03mA   -33.38mA
-794.1mV  -17.59mA   -13.51mA   -23.29mA
-685.8mV  -12.09mA   -9.417mA   -16.09mA
-613.6mV  -8.697mA   -6.887mA   -11.62mA
-541.4mV  -5.686mA   -4.64mA    -7.568mA
-469.2mV  -3.203mA   -2.785mA   -4.138mA
-433.1mV  -2.213mA   -2.034mA   -2.744mA
-397mV    -1.416mA   -1.414mA   -1.624mA
-360.9mV  -823.7uA   -927.9uA   -821.7uA
-324.8mV  -429.2uA   -569.8uA   -343.3uA
-144.4mV  -4.828uA   -19.16uA   -973.1nA
2.2V      0A         0A         0A
[POWER Clamp]
| Voltage   I(typ)   I(min)   I(max)
-1.1V     37.46mA    30.95mA    52.16mA
-974.5mV  29mA       23.73mA    40.25mA
-866.2mV  21.91mA    17.93mA    30.08mA
-758mV    15.25mA    12.59mA    20.36mA
-649.7mV  9.216mA    7.857mA    11.48mA
-577.5mV  5.7mA      5.137mA    6.467mA
-541.4mV  4.17mA     3.936mA    4.395mA
-469.2mV  1.751mA    1.95mA     1.452mA
-433.1mV  941.2uA    1.216mA    645.5uA
-360.9mV  155.7uA    378.3uA    59.24uA
-144.4mV  523.4nA    3.131uA    465.7nA
2.2V      0A         0A         0A
[Pullup]
| Voltage   I(typ)   I(min)   I(max)
-1.1V     10.56mA    9.925mA    9.924mA
-721.9mV  9.359mA    9.062mA    8.862mA
-577.5mV  8.552mA    8.271mA    8.118mA
-433.1mV  7.152mA    6.963mA    6.685mA
584.4mV   -9.554mA   -9.409mA   -8.749mA
859.4mV   -13.6mA    -13.27mA   -12.34mA
1.066V    -16.18mA   -15.53mA   -14.45mA
1.244V    -17.85mA   -16.86mA   -15.67mA
1.461V    -19.21mA   -17.94mA   -16.68mA
2.111V    -21.42mA   -19.78mA   -18.36mA
2.183V    -23.51mA   -19.92mA   -18.5mA
2.2V      -23.1mA    -19.95mA   -18.53mA
[Pulldown]
| Voltage   I(typ)   I(min)   I(max)
-1.1V     -24.54mA   -23.56mA   -17.75mA
-1.083V   -24.2mA    -23.53mA   -17.61mA
-1.011V   -20.82mA   -22.97mA   -17.12mA
-613.6mV  -16.12mA   -16.86mA   -14.19mA
-397mV    -12.16mA   -12.34mA   -11.11mA
-288.8mV  -9.186mA   -9.291mA   -8.44mA
412.5mV   12.55mA    12.51mA    11.65mA
687.5mV   19.95mA    19.5mA     18.72mA
893.8mV   24.63mA    23.41mA    23.43mA
1.136V    28.33mA    25.56mA    27.79mA
1.389V    29.72mA    26.3mA     29.98mA
2.2V      31.3mA     27.55mA    31.75mA
[Ramp]
dV/dt_r   0.296469/96.7202p  0.27969/0.10669n  0.294944/0.101606n
dV/dt_f   0.397607/84.398p  0.377631/91.2414p  0.404344/84.0227p
R_load = 50
[Rising Waveform]
R_fixture = 50
V_fixture = 0
V_fixture_min = 0
V_fixture_max = 0
| Time   V(typ)   V(min)   V(max)
0s        1.119uV    1.276uV    1.628uV
959ps     -567uV     -597.1uV   739uV
1.101ns   -651.1uV   -685.7uV   391.3mV
1.241ns   -3.457mV   -773.1uV   469.6mV
1.273ns   28.99mV    -793.1uV   476mV
1.396ns   397.6mV    -869.8uV   485.8mV
1.637ns   485.6mV    2.916mV    490.1mV
1.785ns   490.4mV    365.4mV    490.5mV
1.969ns   492.7mV    453.7mV    490.9mV
10ns      494.1mV    466.2mV    491.6mV
[Rising Waveform]
R_fixture = 50
V_fixture = 1.1
V_fixture_min = 1.045
V_fixture_max = 1.155
| Time   V(typ)   V(min)   V(max)
0s        437.3mV    415.6mV    481.1mV
927ps     437.2mV    415mV      485.4mV
1.052ns   437.2mV    415mV      1.014V
1.241ns   447.5mV    414.8mV    1.135V
1.313ns   809.4mV    414.8mV    1.144V
1.395ns   1.018V     414.8mV    1.148V
1.624ns   1.089V     420.7mV    1.153V
1.771ns   1.095V     936mV      1.153V
2.029ns   1.098V     1.035V     1.154V
10ns      1.1V       1.045V     1.155V
[Falling Waveform]
R_fixture = 50
V_fixture = 0
V_fixture_min = 0
V_fixture_max = 0
| Time   V(typ)   V(min)   V(max)
0s        494.1mV    466.2mV    491.6mV
894ps     493.6mV    465.8mV    484.8mV
1.031ns   493.5mV    465.7mV    76.07mV
1.224ns   476.1mV    465.6mV    6.306mV
1.345ns   89.12mV    465.6mV    2.557mV
1.568ns   4.983mV    464.5mV    977.4uV
1.665ns   2.646mV    416.2mV    966.2uV
1.795ns   1.477mV    48.04mV    951.1uV
1.999ns   987.3uV    4.551mV    927.5uV
10ns      2.578uV    2.76uV     1.765uV
[Falling Waveform]
R_fixture = 50
V_fixture = 1.1
V_fixture_min = 1.045
V_fixture_max = 1.155
| Time   V(typ)   V(min)   V(max)
0s        1.1V       1.045V     1.155V
950ps     1.101V     1.046V     1.158V
1.107ns   1.101V     1.046V     565.5mV
1.292ns   1.063V     1.046V     489.2mV
1.406ns   556mV      1.046V     485mV
1.636ns   443.9mV    1.048V     482.9mV
1.709ns   441.4mV    988.2mV    482.7mV
1.824ns   439.7mV    529.5mV    482.3mV
1.985ns   438.8mV    427.5mV    482.1mV
10ns      437.3mV    415.6mV    481.1mV
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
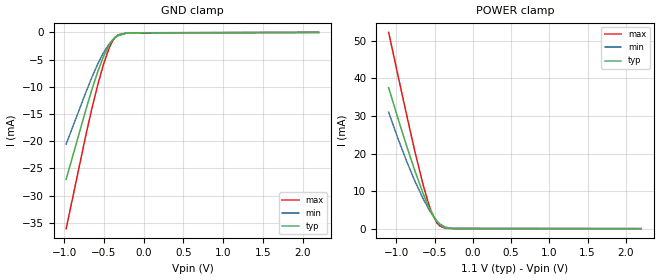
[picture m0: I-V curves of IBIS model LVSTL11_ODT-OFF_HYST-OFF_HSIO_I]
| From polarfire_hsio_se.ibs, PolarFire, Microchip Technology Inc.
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|   Model LVSTL11_ODT-OFF_HYST-OFF_HSIO_I
[Model]   LVSTL11_ODT-OFF_HYST-OFF_HSIO_I
Model_type   Input
Vinl =   0.083
Vinh =   0.283
|   typ   min   max
C_comp_pullup   1.335e-12   1.335e-12   1.380e-12
C_comp_pulldown  1.335e-12   1.335e-12   1.380e-12
[Temperature Range]  25C   100C   -40C
[Voltage Range]  1.1   1.045   1.155
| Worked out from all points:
|   GND clamp passes 1 mA (typ) near -0.37 V on its own axis
|   POWER clamp passes 1 mA (typ) near -0.43 V on its own axis
[GND Clamp]
| Voltage   I(typ)   I(min)   I(max)
-974.5mV  -27mA      -20.53mA   -36.07mA
-721.9mV  -13.98mA   -10.84mA   -18.56mA
-649.7mV  -10.45mA   -8.209mA   -13.93mA
-577.5mV  -7.235mA   -5.805mA   -9.653mA
-505.3mV  -4.465mA   -3.738mA   -5.881mA
-433.1mV  -2.307mA   -2.114mA   -2.863mA
-397mV    -1.509mA   -1.493mA   -1.742mA
-360.9mV  -915.6uA   -1.005mA   -937.5uA
-324.8mV  -519.5uA   -645.2uA   -457.2uA
-216.6mV  -119.1uA   -158.3uA   -119.2uA
-36.09mV  -76.1uA    -64.2uA    -96.84uA
2.2V      0A         0A         0A
[POWER Clamp]
| Voltage   I(typ)   I(min)   I(max)
-1.1V     37.54mA    31.01mA    52.27mA
-974.5mV  29.1mA     23.8mA     40.47mA
-866.2mV  22.09mA    18.01mA    30.39mA
-758mV    15.47mA    12.71mA    20.62mA
-649.7mV  9.39mA     8mA        11.67mA
-577.5mV  5.839mA    5.262mA    6.617mA
-541.4mV  4.291mA    4.048mA    4.524mA
-469.2mV  1.84mA     2.037mA    1.543mA
-433.1mV  1.016mA    1.29mA     719.5uA
-360.9mV  204.5uA    386.4uA    107uA
-252.7mV  30.1uA     57.26uA    30.59uA
2.2V      0A         0A         0A
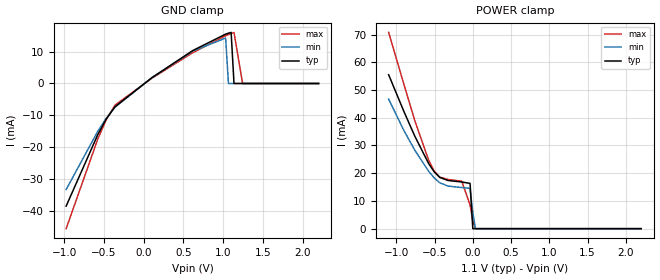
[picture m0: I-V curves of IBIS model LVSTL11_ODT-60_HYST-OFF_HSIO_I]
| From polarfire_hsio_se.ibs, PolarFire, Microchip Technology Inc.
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|   Model LVSTL11_ODT-60_HYST-OFF_HSIO_I
[Model]   LVSTL11_ODT-60_HYST-OFF_HSIO_I
Model_type   Input
Vinl =   0.083
Vinh =   0.283
|   typ   min   max
C_comp_pullup   1.335e-12   1.335e-12   1.380e-12
C_comp_pulldown  1.335e-12   1.335e-12   1.380e-12
[Temperature Range]  25C   100C   -40C
[Voltage Range]  1.1   1.045   1.155
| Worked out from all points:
|   GND clamp passes 1 mA (typ) near -0.05 V on its own axis
|   POWER clamp passes 1 mA (typ) near -0.00 V on its own axis
[GND Clamp]
| Voltage   I(typ)   I(min)   I(max)
-974.5mV  -38.61mA   -33.39mA   -45.71mA
-577.5mV  -16.14mA   -15.07mA   -17.53mA
-469.2mV  -11.14mA   -10.89mA   -11.33mA
-360.9mV  -7.336mA   -7.501mA   -6.821mA
103.1mV   1.814mA    1.837mA    1.656mA
618.8mV   10.39mA    10.22mA    9.718mA
1.031V    15.55mA    14.31mA    15.05mA
1.066V    15.84mA    0A         15.41mA
1.1V      16.09mA    0A         15.74mA
1.136V    0A         0A         16.07mA
1.244V    0A         0A         0A
2.2V      0A         0A         0A
[POWER Clamp]
| Voltage   I(typ)   I(min)   I(max)
-1.1V     55.49mA    46.7mA     70.76mA
-902.3mV  42.36mA    35.47mA    52.19mA
-758mV    33.33mA    28.27mA    38.92mA
-577.5mV  23.49mA    20.7mA     24.71mA
-505.3mV  20.5mA     18.32mA    20.81mA
-433.1mV  18.48mA    16.57mA    18.61mA
-324.8mV  17.37mA    15.35mA    17.73mA
-144.4mV  16.82mA    14.82mA    17.11mA
-36.09mV  16.32mA    14.51mA    8.554mA
0V        0A         5.784mA    2.94mA
34.38mV   0A         0A         0A
2.2V      0A         0A         0A
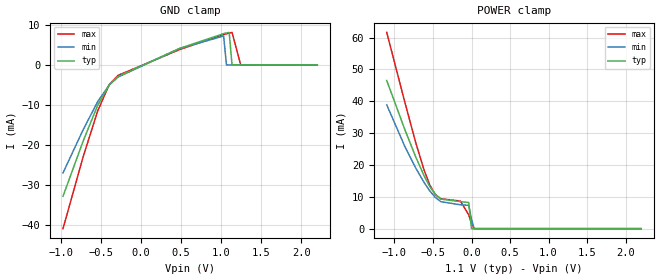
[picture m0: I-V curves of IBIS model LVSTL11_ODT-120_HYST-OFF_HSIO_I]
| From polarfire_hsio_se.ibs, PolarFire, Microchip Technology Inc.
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|   Model LVSTL11_ODT-120_HYST-OFF_HSIO_I
[Model]   LVSTL11_ODT-120_HYST-OFF_HSIO_I
Model_type   Input
Vinl =   0.083
Vinh =   0.283
|   typ   min   max
C_comp_pullup   1.335e-12   1.335e-12   1.380e-12
C_comp_pulldown  1.335e-12   1.335e-12   1.380e-12
[Temperature Range]  25C   100C   -40C
[Voltage Range]  1.1   1.045   1.155
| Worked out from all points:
|   GND clamp passes 1 mA (typ) near -0.10 V on its own axis
|   POWER clamp passes 1 mA (typ) near -0.00 V on its own axis
[GND Clamp]
| Voltage   I(typ)   I(min)   I(max)
-974.5mV  -32.8mA    -26.96mA   -40.88mA
-721.9mV  -18.97mA   -16.15mA   -22.88mA
-541.4mV  -10.07mA   -9.162mA   -11.5mA
-397mV    -4.975mA   -5.012mA   -4.9mA
-288.8mV  -2.903mA   -3.047mA   -2.626mA
481.3mV   4.118mA    4.095mA    3.823mA
1.031V    7.814mA    7.214mA    7.586mA
1.066V    7.963mA    0A         7.772mA
1.1V      8.095mA    0A         7.947mA
1.136V    0A         0A         8.117mA
1.244V    0A         0A         0A
2.2V      0A         0A         0A
[POWER Clamp]
| Voltage   I(typ)   I(min)   I(max)
-1.1V     46.53mA    38.89mA    61.65mA
-866.2mV  31.19mA    25.87mA    39.81mA
-721.9mV  22.4mA     18.96mA    26.85mA
-613.6mV  16.52mA    14.44mA    18.29mA
-541.4mV  13.21mA    11.86mA    13.74mA
-469.2mV  10.71mA    9.81mA     10.7mA
-397mV    9.293mA    8.467mA    9.376mA
-144.4mV  8.487mA    7.498mA    8.675mA
-36.09mV  8.216mA    7.324mA    4.334mA
0V        0A         2.917mA    1.49mA
34.38mV   0A         0A         0A
2.2V      0A         0A         0A
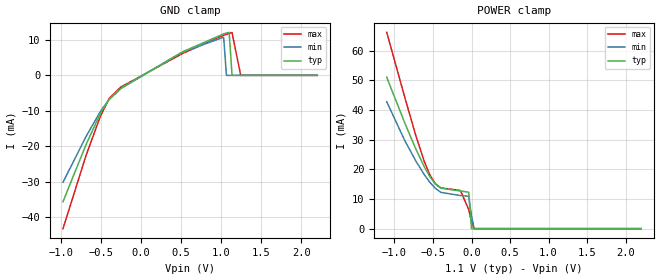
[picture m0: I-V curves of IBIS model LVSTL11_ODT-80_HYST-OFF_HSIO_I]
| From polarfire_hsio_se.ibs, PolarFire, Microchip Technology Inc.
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|   Model LVSTL11_ODT-80_HYST-OFF_HSIO_I
[Model]   LVSTL11_ODT-80_HYST-OFF_HSIO_I
Model_type   Input
Vinl =   0.083
Vinh =   0.283
|   typ   min   max
C_comp_pullup   1.335e-12   1.335e-12   1.380e-12
C_comp_pulldown  1.335e-12   1.335e-12   1.380e-12
[Temperature Range]  25C   100C   -40C
[Voltage Range]  1.1   1.045   1.155
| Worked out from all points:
|   GND clamp passes 1 mA (typ) near -0.07 V on its own axis
|   POWER clamp passes 1 mA (typ) near -0.00 V on its own axis
[GND Clamp]
| Voltage   I(typ)   I(min)   I(max)
-974.5mV  -35.7mA    -30.18mA   -43.3mA
-685.8mV  -19.49mA   -17.24mA   -22.57mA
-505.3mV  -10.64mA   -10.1mA    -11.41mA
-397mV    -6.716mA   -6.779mA   -6.488mA
-252.7mV  -3.623mA   -3.744mA   -3.304mA
515.6mV   6.608mA    6.547mA    6.139mA
1.031V    11.71mA    10.77mA    11.32mA
1.066V    11.93mA    0A         11.59mA
1.1V      12.13mA    0A         11.85mA
1.136V    0A         0A         12.09mA
1.244V    0A         0A         0A
2.2V      0A         0A         0A
[POWER Clamp]
| Voltage   I(typ)   I(min)   I(max)
-1.1V     51.06mA    42.81mA    66.21mA
-866.2mV  35.67mA    29.74mA    44.32mA
-721.9mV  26.84mA    22.8mA     31.32mA
-613.6mV  20.93mA    18.26mA    22.73mA
-541.4mV  17.6mA     15.67mA    18.16mA
-469.2mV  15.08mA    13.59mA    15.1mA
-397mV    13.64mA    12.23mA    13.75mA
-144.4mV  12.7mA     11.17mA    12.89mA
-36.09mV  12.3mA     10.93mA    6.446mA
0V        0A         4.354mA    2.216mA
34.38mV   0A         0A         0A
2.2V      0A         0A         0A
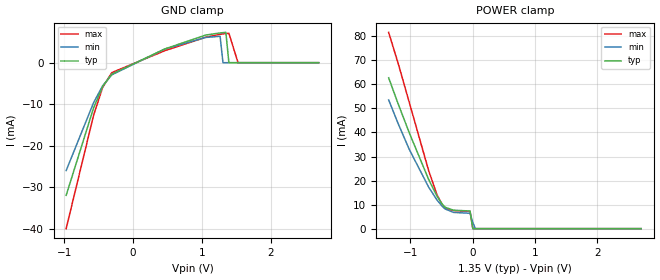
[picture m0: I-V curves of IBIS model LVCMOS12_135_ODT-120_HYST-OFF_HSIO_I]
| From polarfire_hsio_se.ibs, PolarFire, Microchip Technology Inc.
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|   LVCMOS12_135_ODT-120_HYST-OFF_HSIO_I
[Model]   LVCMOS12_135_ODT-120_HYST-OFF_HSIO_I
Model_type  Input
Vinl =   0.42
Vinh =   0.78
|   typ   min   max
C_comp_pullup   1.335e-12   1.335e-12   1.380e-12
C_comp_pulldown  1.335e-12   1.335e-12   1.380e-12
[Temperature Range]   25   100   -40
[Voltage Range]   1.35   1.2825   1.4175
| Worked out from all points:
|   GND clamp passes 1 mA (typ) near -0.12 V on its own axis
|   POWER clamp passes 1 mA (typ) near -0.01 V on its own axis
[GND Clamp]
| Voltage   I(typ)   I(min)   I(max)
-974.5mV  -31.9mA    -25.95mA   -39.91mA
-575.9mV  -10.91mA   -9.645mA   -12.69mA
-443mV    -5.731mA   -5.539mA   -5.929mA
-310.1mV  -2.766mA   -2.916mA   -2.383mA
464.1mV   3.319mA    3.3mA      2.897mA
1.055V    6.631mA    6.062mA    6.104mA
1.266V    7.156mA    6.344mA    6.823mA
1.308V    7.221mA    0A         6.917mA
1.35V     7.281mA    0A         6.998mA
1.394V    0A         0A         7.074mA
1.527V    0A         0A         0A
2.7V      0A         0A         0A
[POWER Clamp]
| Voltage   I(typ)   I(min)   I(max)
-1.35V    62.72mA    53.53mA    81.6mA
-1.196V   51.79mA    43.57mA    68.59mA
-1.019V   39.84mA    32.95mA    52.47mA
-708.7mV  20.47mA    17.28mA    24.15mA
-575.9mV  13.54mA    11.96mA    14.2mA
-487.3mV  10.09mA    9.199mA    9.765mA
-443mV    8.914mA    8.173mA    8.516mA
-310.1mV  7.672mA    6.755mA    7.521mA
-44.3mV   7.339mA    6.405mA    7.176mA
0V        0A         2.555mA    0A
42.19mV   0A         0A         0A
2.7V      0A         0A         0A
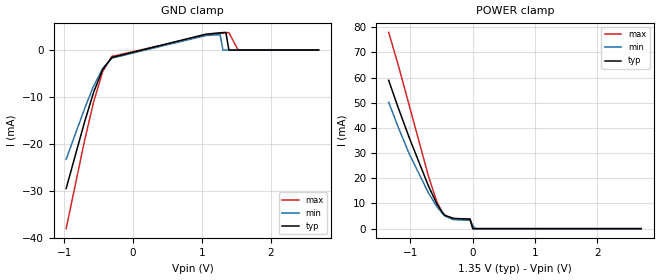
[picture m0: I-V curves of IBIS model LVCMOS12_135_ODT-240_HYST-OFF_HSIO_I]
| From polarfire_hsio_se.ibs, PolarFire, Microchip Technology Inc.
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|   LVCMOS12_135_ODT-240_HYST-OFF_HSIO_I
[Model]   LVCMOS12_135_ODT-240_HYST-OFF_HSIO_I
Model_type  Input
Vinl =   0.42
Vinh =   0.78
|   typ   min   max
C_comp_pullup   1.335e-12   1.335e-12   1.380e-12
C_comp_pulldown  1.335e-12   1.335e-12   1.380e-12
[Temperature Range]   25   100   -40
[Voltage Range]   1.35   1.2825   1.4175
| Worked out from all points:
|   GND clamp passes 1 mA (typ) near -0.22 V on its own axis
|   POWER clamp passes 1 mA (typ) near -0.01 V on its own axis
[GND Clamp]
| Voltage   I(typ)   I(min)   I(max)
-974.5mV  -29.46mA   -23.25mA   -38mA
-708.7mV  -15.41mA   -12.57mA   -19.42mA
-575.9mV  -9.042mA   -7.706mA   -11.13mA
-443mV    -4.146mA   -3.927mA   -4.576mA
-310.1mV  -1.587mA   -1.727mA   -1.363mA
1.055V    3.357mA    3.081mA    3.116mA
1.266V    3.667mA    3.262mA    3.538mA
1.308V    3.71mA     0A         3.598mA
1.35V     3.75mA     0A         3.652mA
1.394V    0A         0A         3.704mA
1.527V    0A         0A         0A
2.7V      0A         0A         0A
[POWER Clamp]
| Voltage   I(typ)   I(min)   I(max)
-1.35V    58.9mA     50.21mA    77.94mA
-1.196V   47.99mA    40.27mA    64.95mA
-1.019V   36.07mA    29.67mA    48.85mA
-708.7mV  16.76mA    14.05mA    20.59mA
-575.9mV  9.86mA     8.752mA    10.66mA
-487.3mV  6.422mA    6.004mA    6.249mA
-443mV    5.257mA    4.986mA    5.008mA
-310.1mV  4.044mA    3.592mA    4.043mA
-44.3mV   3.79mA     3.305mA    3.777mA
0V        0A         1.317mA    0A
42.19mV   0A         0A         0A
2.7V      0A         0A         0A
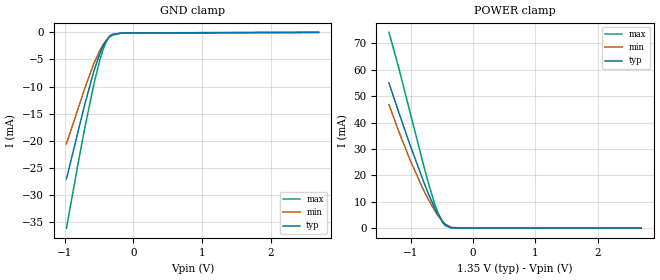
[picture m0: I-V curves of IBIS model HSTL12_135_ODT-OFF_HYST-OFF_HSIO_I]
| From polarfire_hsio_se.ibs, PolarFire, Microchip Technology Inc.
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|   HSTL12_135_ODT-OFF_HYST-OFF_HSIO_I
[Model]   HSTL12_135_ODT-OFF_HYST-OFF_HSIO_I
Model_type  Input
Vinl =   0.5
Vinh =   0.7
|   typ   min   max
C_comp_pullup   1.335e-12   1.335e-12   1.380e-12
C_comp_pulldown  1.335e-12   1.335e-12   1.380e-12
[Temperature Range]   25   100   -40
[Voltage Range]   1.35   1.2825   1.4175
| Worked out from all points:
|   GND clamp passes 1 mA (typ) near -0.36 V on its own axis
|   POWER clamp passes 1 mA (typ) near -0.43 V on its own axis
[GND Clamp]
| Voltage   I(typ)   I(min)   I(max)
-974.5mV  -27.04mA   -20.56mA   -36.11mA
-797.3mV  -17.91mA   -13.76mA   -23.69mA
-708.7mV  -13.35mA   -10.38mA   -17.74mA
-575.9mV  -7.195mA   -5.779mA   -9.596mA
-487.3mV  -3.888mA   -3.311mA   -5.077mA
-443mV    -2.585mA   -2.329mA   -3.251mA
-398.7mV  -1.567mA   -1.541mA   -1.818mA
-354.4mV  -854.8uA   -952.3uA   -857.8uA
-310.1mV  -432.9uA   -554.1uA   -371.5uA
-177.2mV  -119.7uA   -129.6uA   -138.6uA
-44.3mV   -101uA     -86.04uA   -127.4uA
2.7V      0A         0A         0A
[POWER Clamp]
| Voltage   I(typ)   I(min)   I(max)
-1.35V    55.02mA    46.81mA    74.15mA
-1.196V   44.11mA    36.89mA    61.02mA
-1.019V   32.06mA    26.28mA    44.65mA
-797.3mV  17.84mA    14.59mA    24.13mA
-708.7mV  12.63mA    10.5mA     16.43mA
-620.2mV  7.886mA    6.852mA    9.514mA
-575.9mV  5.774mA    5.221mA    6.543mA
-487.3mV  2.365mA    2.497mA    2.156mA
-443mV    1.216mA    1.492mA    931.9uA
-354.4mV  176.1uA    353uA      97.79uA
-177.2mV  18.34uA    20.85uA    21.14uA
2.7V      0A         0A         0A
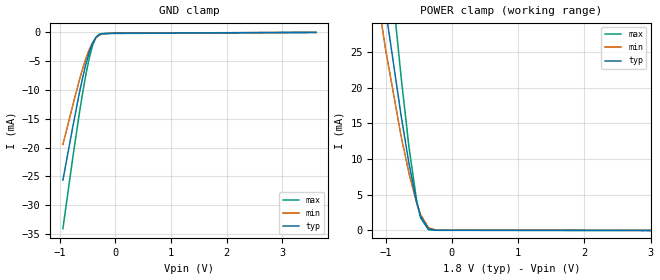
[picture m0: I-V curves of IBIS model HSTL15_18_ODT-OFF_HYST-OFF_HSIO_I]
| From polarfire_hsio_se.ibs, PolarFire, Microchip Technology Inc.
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|   HSTL15_18_ODT-OFF_HYST-OFF_HSIO_I
[Model]   HSTL15_18_ODT-OFF_HYST-OFF_HSIO_I
Model_type  Input
Vinl =   0.65
Vinh =   0.85
|   typ   min   max
C_comp_pullup   1.335e-12   1.335e-12   1.380e-12
C_comp_pulldown  1.335e-12   1.335e-12   1.380e-12
[Temperature Range]   25   100   -40
[Voltage Range]   1.8   1.71   1.89
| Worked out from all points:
|   GND clamp passes 1 mA (typ) near -0.36 V on its own axis
|   POWER clamp passes 1 mA (typ) near -0.43 V on its own axis
[GND Clamp]
| Voltage   I(typ)   I(min)   I(max)
-945mV    -25.65mA   -19.45mA   -34.09mA
-767.8mV  -16.42mA   -12.66mA   -21.74mA
-649.7mV  -10.53mA   -8.28mA    -14.04mA
-590.6mV  -7.869mA   -6.289mA   -10.5mA
-531.6mV  -5.486mA   -4.511mA   -7.275mA
-472.5mV  -3.472mA   -3.004mA   -4.488mA
-413.4mV  -1.919mA   -1.821mA   -2.303mA
-354.4mV  -899.9uA   -991.4uA   -913.6uA
-295.3mV  -390.4uA   -497.3uA   -345.5uA
-236.2mV  -212uA     -259.7uA   -216.5uA
-59.06mV  -146.2uA   -125.5uA   -183uA
3.6V      0A         0A         0A
[POWER Clamp]
| Voltage   I(typ)   I(min)   I(max)
-1.8V     93.12mA    78.03mA    128.6mA
-1.536V   69.62mA    59.4mA     93.76mA
-1.417V   60.1mA     51.33mA    80.63mA
-1.358V   55.64mA    47.38mA    74.98mA
-1.004V   31.09mA    25.46mA    43.28mA
-767.8mV  16.09mA    13.21mA    21.53mA
-649.7mV  9.421mA    8.046mA    11.74mA
-531.6mV  3.923mA    3.789mA    4.118mA
-472.5mV  1.944mA    2.168mA    1.747mA
-354.4mV  179.4uA    380.1uA    112.9uA
-236.2mV  27.5uA     43.98uA    29.45uA
3.6V      0A         0A         0A
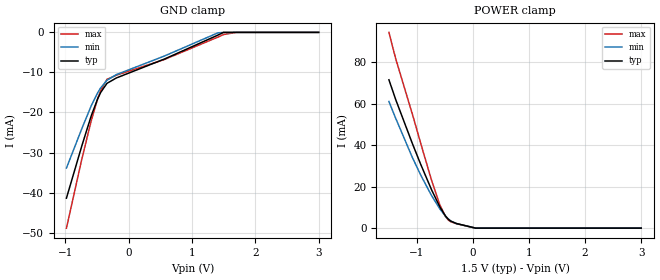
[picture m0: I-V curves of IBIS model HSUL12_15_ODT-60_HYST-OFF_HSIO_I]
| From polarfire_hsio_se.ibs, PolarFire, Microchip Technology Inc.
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|   HSUL12_15_ODT-60_HYST-OFF_HSIO_I
[Model]   HSUL12_15_ODT-60_HYST-OFF_HSIO_I
Model_type  Input
Vinl =   0.5
Vinh =   0.7
|   typ   min   max
C_comp_pullup   1.335e-12   1.335e-12   1.380e-12
C_comp_pulldown  1.335e-12   1.335e-12   1.380e-12
[Temperature Range]   25   100   -40
[Voltage Range]   1.5   1.425   1.575
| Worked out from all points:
|   POWER clamp passes 1 mA (typ) near -0.13 V on its own axis
[GND Clamp]
| Voltage   I(typ)   I(min)   I(max)
-984.4mV  -41.39mA   -33.88mA   -48.87mA
-738.3mV  -28.18mA   -23.92mA   -31.42mA
-590.6mV  -20.74mA   -18.26mA   -21.95mA
-492.2mV  -16.64mA   -15.13mA   -16.65mA
-443mV    -14.99mA   -13.84mA   -14.5mA
-344.5mV  -12.73mA   -11.96mA   -11.72mA
-196.9mV  -11.39mA   -10.55mA   -10.7mA
562.5mV   -6.665mA   -5.911mA   -6.782mA
1.406V    -697.8uA   -133.4uA   -1.199mA
1.5V      161.2nA    0A         -535.3uA
1.697V    0A         0A         0A
3V        0A         0A         0A
[POWER Clamp]
| Voltage   I(typ)   I(min)   I(max)
-1.5V     71.51mA    61.05mA    94.38mA
-1.378V   61.89mA    52.85mA    81.56mA
-1.083V   40.87mA    34.15mA    55.06mA
-935.2mV  30.89mA    25.69mA    41.09mA
-738.3mV  18.42mA    15.64mA    22.93mA
-590.6mV  10.18mA    9.248mA    11.16mA
-492.2mV  5.894mA    5.796mA    5.647mA
-443mV    4.354mA    4.449mA    3.993mA
-393.7mV  3.306mA    3.421mA    3.035mA
-295.3mV  2.228mA    2.189mA    2.121mA
46.88mV   0A         0A         0A
3V        0A         0A         0A
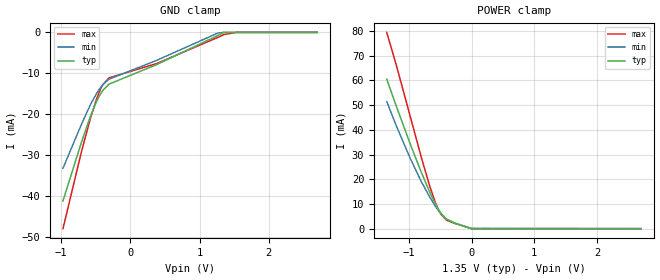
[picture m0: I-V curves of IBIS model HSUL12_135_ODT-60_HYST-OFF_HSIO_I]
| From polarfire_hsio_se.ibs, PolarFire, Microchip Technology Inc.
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|   HSUL12_135_ODT-60_HYST-OFF_HSIO_I
[Model]   HSUL12_135_ODT-60_HYST-OFF_HSIO_I
Model_type  Input
Vinl =   0.5
Vinh =   0.7
|   typ   min   max
C_comp_pullup   1.335e-12   1.335e-12   1.380e-12
C_comp_pulldown  1.335e-12   1.335e-12   1.380e-12
[Temperature Range]   25   100   -40
[Voltage Range]   1.35   1.2825   1.4175
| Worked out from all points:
|   POWER clamp passes 1 mA (typ) near -0.12 V on its own axis
[GND Clamp]
| Voltage   I(typ)   I(min)   I(max)
-974.5mV  -41.09mA   -33.12mA   -47.87mA
-708.7mV  -26.85mA   -22.46mA   -29.15mA
-575.9mV  -20.35mA   -17.54mA   -20.83mA
-487.3mV  -16.77mA   -14.82mA   -16.17mA
-443mV    -15.31mA   -13.69mA   -14.26mA
-398.7mV  -14.13mA   -12.75mA   -12.74mA
-310.1mV  -12.62mA   -11.42mA   -11.09mA
379.7mV   -7.853mA   -6.814mA   -7.591mA
1.266V    -723.6uA   -133.9uA   -1.2mA
1.35V     140.4nA    0A         -536.3uA
1.527V    0A         0A         0A
2.7V      0A         0A         0A
[POWER Clamp]
| Voltage   I(typ)   I(min)   I(max)
-1.35V    60.51mA    51.43mA    79.43mA
-1.196V   49.44mA    41.53mA    66.02mA
-974.5mV  34.18mA    28.34mA    45.3mA
-797.3mV  22.68mA    18.94mA    28.68mA
-664.5mV  14.72mA    12.73mA    17.13mA
-575.9mV  10.03mA    9.076mA    10.57mA
-531.6mV  7.991mA    7.453mA    7.908mA
-487.3mV  6.239mA    6.011mA    5.805mA
-398.7mV  3.838mA    3.822mA    3.417mA
-265.8mV  2.299mA    2.16mA     2.121mA
0V        0A         81.37uA    0A
2.7V      0A         0A         0A
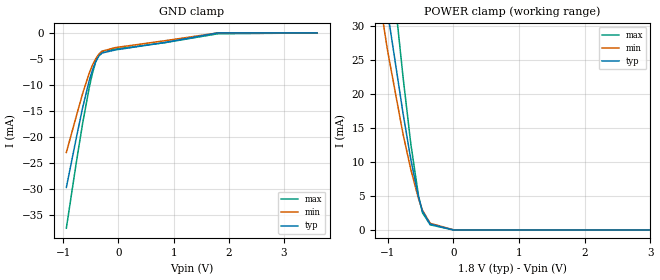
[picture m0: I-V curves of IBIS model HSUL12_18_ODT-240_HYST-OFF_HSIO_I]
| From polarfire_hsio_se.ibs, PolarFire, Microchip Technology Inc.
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|   HSUL12_18_ODT-240_HYST-OFF_HSIO_I
[Model]   HSUL12_18_ODT-240_HYST-OFF_HSIO_I
Model_type  Input
Vinl =   0.5
Vinh =   0.7
|   typ   min   max
C_comp_pullup   1.335e-12   1.335e-12   1.380e-12
C_comp_pulldown  1.335e-12   1.335e-12   1.380e-12
[Temperature Range]   25   100   -40
[Voltage Range]   1.8   1.71   1.89
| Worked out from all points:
|   POWER clamp passes 1 mA (typ) near -0.37 V on its own axis
[GND Clamp]
| Voltage   I(typ)   I(min)   I(max)
-945mV    -29.69mA   -22.97mA   -37.51mA
-767.8mV  -20.34mA   -16.11mA   -25.1mA
-649.7mV  -14.36mA   -11.64mA   -17.36mA
-531.6mV  -9.216mA   -7.768mA   -10.58mA
-472.5mV  -7.145mA   -6.206mA   -7.773mA
-413.4mV  -5.529mA   -4.963mA   -5.557mA
-354.4mV  -4.441mA   -4.069mA   -4.128mA
-295.3mV  -3.856mA   -3.505mA   -3.513mA
-59.06mV  -3.284mA   -2.83mA    -3.117mA
843.8mV   -1.839mA   -1.5mA     -1.873mA
1.8V      228.7nA    0A         -173.6uA
3.6V      0A         0A         0A
[POWER Clamp]
| Voltage   I(typ)   I(min)   I(max)
-1.8V     94.25mA    78.93mA    129.7mA
-1.536V   70.77mA    60.33mA    94.85mA
-1.417V   61.24mA    52.27mA    81.71mA
-1.358V   56.77mA    48.32mA    76.04mA
-1.004V   32.13mA    26.37mA    44.26mA
-767.8mV  17.12mA    14.09mA    22.48mA
-649.7mV  10.39mA    8.897mA    12.66mA
-531.6mV  4.821mA    4.572mA    4.969mA
-472.5mV  2.788mA    2.903mA    2.546mA
-354.4mV  862.3uA    977.9uA    754.2uA
0V        0A         25.47uA    0A
3.6V      0A         0A         0A
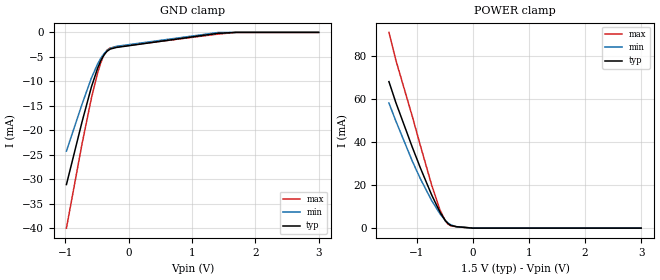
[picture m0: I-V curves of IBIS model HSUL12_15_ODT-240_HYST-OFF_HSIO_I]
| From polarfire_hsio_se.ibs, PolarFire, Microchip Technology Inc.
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|   HSUL12_15_ODT-240_HYST-OFF_HSIO_I
[Model]   HSUL12_15_ODT-240_HYST-OFF_HSIO_I
Model_type  Input
Vinl =   0.5
Vinh =   0.7
|   typ   min   max
C_comp_pullup   1.335e-12   1.335e-12   1.380e-12
C_comp_pulldown  1.335e-12   1.335e-12   1.380e-12
[Temperature Range]   25   100   -40
[Voltage Range]   1.5   1.425   1.575
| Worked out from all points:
|   POWER clamp passes 1 mA (typ) near -0.36 V on its own axis
[GND Clamp]
| Voltage   I(typ)   I(min)   I(max)
-984.4mV  -31.05mA   -24.23mA   -39.94mA
-738.3mV  -18.28mA   -14.67mA   -22.76mA
-590.6mV  -11.17mA   -9.338mA   -13.47mA
-492.2mV  -7.324mA   -6.449mA   -8.312mA
-443mV    -5.819mA   -5.305mA   -6.243mA
-393.7mV  -4.659mA   -4.395mA   -4.654mA
-344.5mV  -3.872mA   -3.727mA   -3.649mA
-295.3mV  -3.423mA   -3.282mA   -3.194mA
-196.9mV  -3.081mA   -2.852mA   -2.967mA
1.406V    -200.8uA   -37.03uA   -354.8uA
1.697V    0A         0A         0A
3V        0A         0A         0A
[POWER Clamp]
| Voltage   I(typ)   I(min)   I(max)
-1.5V     67.89mA    57.97mA    90.72mA
-1.378V   58.3mA     49.73mA    77.97mA
-1.083V   37.5mA     31.04mA    51.77mA
-935.2mV  27.65mA    22.67mA    37.92mA
-738.3mV  15.42mA    12.82mA    20.01mA
-590.6mV  7.461mA    6.682mA    8.504mA
-492.2mV  3.44mA     3.481mA    3.274mA
-443mV    2.078mA    2.295mA    1.809mA
-393.7mV  1.242mA    1.456mA    1.07mA
-295.3mV  661.3uA    680.9uA    638.2uA
0V        0A         23.33uA    0A
3V        0A         0A         0A
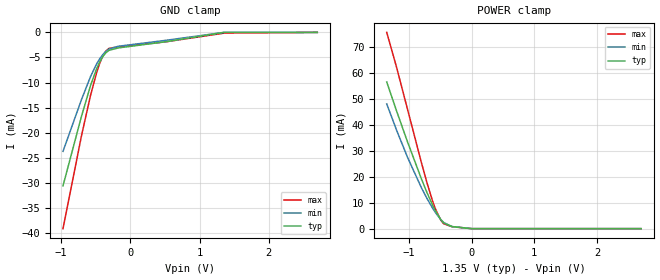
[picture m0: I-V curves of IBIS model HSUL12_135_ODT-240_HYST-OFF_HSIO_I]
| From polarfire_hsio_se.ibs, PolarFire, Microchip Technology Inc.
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|   HSUL12_135_ODT-240_HYST-OFF_HSIO_I
[Model]   HSUL12_135_ODT-240_HYST-OFF_HSIO_I
Model_type  Input
Vinl =   0.5
Vinh =   0.7
|   typ   min   max
C_comp_pullup   1.335e-12   1.335e-12   1.380e-12
C_comp_pulldown  1.335e-12   1.335e-12   1.380e-12
[Temperature Range]   25   100   -40
[Voltage Range]   1.35   1.2825   1.4175
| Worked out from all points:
|   POWER clamp passes 1 mA (typ) near -0.35 V on its own axis
[GND Clamp]
| Voltage   I(typ)   I(min)   I(max)
-974.5mV  -30.6mA    -23.72mA   -39.13mA
-708.7mV  -16.8mA    -13.45mA   -20.69mA
-575.9mV  -10.57mA   -8.78mA    -12.52mA
-487.3mV  -7.203mA   -6.253mA   -7.979mA
-443mV    -5.865mA   -5.239mA   -6.137mA
-398.7mV  -4.807mA   -4.414mA   -4.684mA
-354.4mV  -4.052mA   -3.786mA   -3.701mA
-310.1mV  -3.582mA   -3.344mA   -3.189mA
-177.2mV  -3.101mA   -2.765mA   -2.857mA
506.2mV   -1.872mA   -1.589mA   -1.889mA
1.35V     145.8nA    0A         -156uA
2.7V      0A         0A         0A
[POWER Clamp]
| Voltage   I(typ)   I(min)   I(max)
-1.35V    56.4mA     47.96mA    75.47mA
-1.196V   45.44mA    38.05mA    62.28mA
-1.019V   33.35mA    27.43mA    45.9mA
-797.3mV  19.11mA    15.7mA     25.34mA
-708.7mV  13.86mA    11.6mA     17.61mA
-620.2mV  9.059mA    7.901mA    10.64mA
-575.9mV  6.912mA    6.238mA    7.643mA
-487.3mV  3.41mA     3.43mA     3.165mA
-443mV    2.199mA    2.37mA     1.879mA
-310.1mV  791.9uA    802.8uA    735.2uA
0V        0A         22.98uA    0A
2.7V      0A         0A         0A
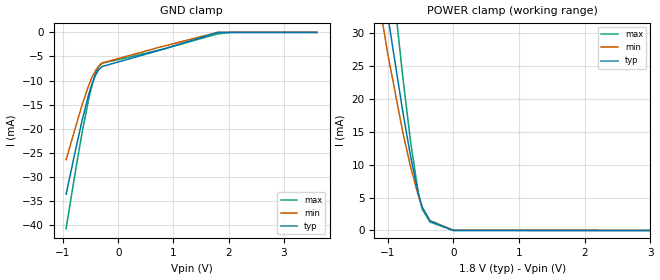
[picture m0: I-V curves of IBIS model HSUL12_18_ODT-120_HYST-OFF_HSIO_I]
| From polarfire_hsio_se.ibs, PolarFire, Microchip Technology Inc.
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|   HSUL12_18_ODT-120_HYST-OFF_HSIO_I
[Model]   HSUL12_18_ODT-120_HYST-OFF_HSIO_I
Model_type  Input
Vinl =   0.5
Vinh =   0.7
|   typ   min   max
C_comp_pullup   1.335e-12   1.335e-12   1.380e-12
C_comp_pulldown  1.335e-12   1.335e-12   1.380e-12
[Temperature Range]   25   100   -40
[Voltage Range]   1.8   1.71   1.89
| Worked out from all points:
|   POWER clamp passes 1 mA (typ) near -0.26 V on its own axis
[GND Clamp]
| Voltage   I(typ)   I(min)   I(max)
-945mV    -33.61mA   -26.44mA   -40.74mA
-767.8mV  -24.12mA   -19.45mA   -28.26mA
-649.7mV  -18.03mA   -14.87mA   -20.48mA
-531.6mV  -12.75mA   -10.88mA   -13.64mA
-472.5mV  -10.61mA   -9.256mA   -10.79mA
-413.4mV  -8.925mA   -7.947mA   -8.539mA
-354.4mV  -7.761mA   -6.983mA   -7.067mA
-295.3mV  -7.099mA   -6.347mA   -6.405mA
787.5mV   -3.578mA   -2.956mA   -3.552mA
1.8V      218.7nA    0A         -309.1uA
2.036V    0A         0A         0A
3.6V      0A         0A         0A
[POWER Clamp]
| Voltage   I(typ)   I(min)   I(max)
-1.8V     95.37mA    79.82mA    130.7mA
-1.536V   71.92mA    61.25mA    95.94mA
-1.417V   62.37mA    53.2mA     82.79mA
-1.358V   57.9mA     49.25mA    77.11mA
-1.004V   33.18mA    27.28mA    45.26mA
-767.8mV  18.09mA    14.95mA    23.39mA
-649.7mV  11.3mA     9.701mA    13.5mA
-531.6mV  5.634mA    5.295mA    5.722mA
-472.5mV  3.54mA     3.573mA    3.238mA
-354.4mV  1.451mA    1.509mA    1.288mA
0V        0A         45.96uA    0A
3.6V      0A         0A         0A
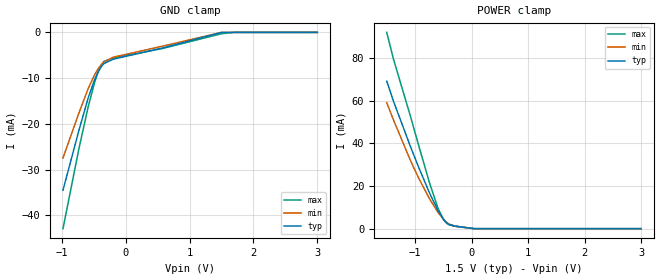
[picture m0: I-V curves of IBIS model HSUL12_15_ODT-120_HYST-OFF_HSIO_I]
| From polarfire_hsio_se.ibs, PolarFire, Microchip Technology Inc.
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|   HSUL12_15_ODT-120_HYST-OFF_HSIO_I
[Model]   HSUL12_15_ODT-120_HYST-OFF_HSIO_I
Model_type  Input
Vinl =   0.5
Vinh =   0.7
|   typ   min   max
C_comp_pullup   1.335e-12   1.335e-12   1.380e-12
C_comp_pulldown  1.335e-12   1.335e-12   1.380e-12
[Temperature Range]   25   100   -40
[Voltage Range]   1.5   1.425   1.575
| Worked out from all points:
|   POWER clamp passes 1 mA (typ) near -0.25 V on its own axis
[GND Clamp]
| Voltage   I(typ)   I(min)   I(max)
-984.4mV  -34.51mA   -27.46mA   -42.92mA
-738.3mV  -21.6mA    -17.76mA   -25.65mA
-590.6mV  -14.37mA   -12.32mA   -16.31mA
-492.2mV  -10.45mA   -9.349mA   -11.11mA
-443mV    -8.891mA   -8.158mA   -9.011mA
-393.7mV  -7.679mA   -7.199mA   -7.393mA
-344.5mV  -6.837mA   -6.478mA   -6.358mA
-196.9mV  -5.862mA   -5.425mA   -5.564mA
562.5mV   -3.462mA   -3.052mA   -3.566mA
1.5V      160.9nA    0A         -286.2uA
1.697V    0A         0A         0A
3V        0A         0A         0A
[POWER Clamp]
| Voltage   I(typ)   I(min)   I(max)
-1.5V     69.1mA     58.99mA    91.94mA
-1.378V   59.5mA     50.77mA    79.17mA
-1.083V   38.63mA    32.08mA    52.88mA
-935.2mV  28.75mA    23.68mA    39.01mA
-738.3mV  16.44mA    13.77mA    21.01mA
-590.6mV  8.382mA    7.546mA    9.406mA
-492.2mV  4.268mA    4.26mA     4.08mA
-443mV    2.846mA    3.02mA     2.55mA
-393.7mV  1.938mA    2.116mA    1.737mA
-295.3mV  1.189mA    1.188mA    1.141mA
46.88mV   0A         0A         0A
3V        0A         0A         0A
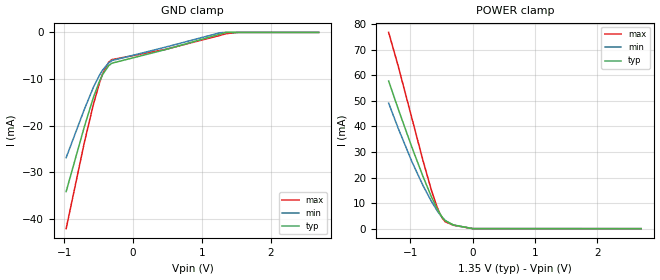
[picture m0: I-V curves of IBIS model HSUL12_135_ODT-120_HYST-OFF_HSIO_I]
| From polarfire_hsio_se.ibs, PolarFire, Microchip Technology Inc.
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|   HSUL12_135_ODT-120_HYST-OFF_HSIO_I
[Model]   HSUL12_135_ODT-120_HYST-OFF_HSIO_I
Model_type  Input
Vinl =   0.5
Vinh =   0.7
|   typ   min   max
C_comp_pullup   1.335e-12   1.335e-12   1.380e-12
C_comp_pulldown  1.335e-12   1.335e-12   1.380e-12
[Temperature Range]   25   100   -40
[Voltage Range]   1.35   1.2825   1.4175
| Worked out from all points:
|   POWER clamp passes 1 mA (typ) near -0.22 V on its own axis
[GND Clamp]
| Voltage   I(typ)   I(min)   I(max)
-974.5mV  -34.11mA   -26.85mA   -42.06mA
-708.7mV  -20.16mA   -16.45mA   -23.53mA
-575.9mV  -13.84mA   -11.7mA    -15.31mA
-487.3mV  -10.4mA    -9.108mA   -10.73mA
-443mV    -9.022mA   -8.058mA   -8.864mA
-354.4mV  -7.121mA   -6.527mA   -6.377mA
-310.1mV  -6.603mA   -6.041mA   -5.836mA
464.1mV   -3.716mA   -3.188mA   -3.669mA
1.266V    -378.1uA   -69.19uA   -635.6uA
1.35V     139.9nA    0A         -284.2uA
1.527V    0A         0A         0A
2.7V      0A         0A         0A
[POWER Clamp]
| Voltage   I(typ)   I(min)   I(max)
-1.35V    57.77mA    49.12mA    76.79mA
-1.196V   46.78mA    39.21mA    63.54mA
-974.5mV  31.67mA    26.08mA    42.95mA
-797.3mV  20.32mA    16.78mA    26.47mA
-664.5mV  12.51mA    10.71mA    15.06mA
-575.9mV  7.961mA    7.19mA     8.635mA
-531.6mV  6.01mA     5.646mA    6.056mA
-487.3mV  4.361mA    4.295mA    4.058mA
-443mV    3.087mA    3.181mA    2.706mA
-310.1mV  1.434mA    1.398mA    1.325mA
0V        0A         42.52uA    0A
2.7V      0A         0A         0A
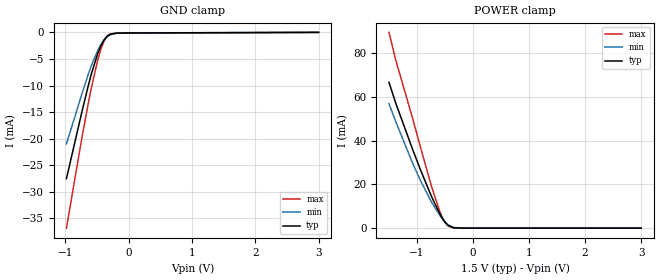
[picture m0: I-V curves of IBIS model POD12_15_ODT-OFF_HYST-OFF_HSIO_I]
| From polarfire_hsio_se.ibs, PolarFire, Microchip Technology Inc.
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|   POD12_15_ODT-OFF_HYST-OFF_HSIO_I
[Model]   POD12_15_ODT-OFF_HYST-OFF_HSIO_I
Model_type  Input
Vinl =   0.76
Vinh =   0.92
|   typ   min   max
C_comp_pullup   1.335e-12   1.335e-12   1.380e-12
C_comp_pulldown  1.335e-12   1.335e-12   1.380e-12
[Temperature Range]   25   100   -40
[Voltage Range]   1.5   1.425   1.575
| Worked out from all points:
|   GND clamp passes 1 mA (typ) near -0.36 V on its own axis
|   POWER clamp passes 1 mA (typ) near -0.43 V on its own axis
[GND Clamp]
| Voltage   I(typ)   I(min)   I(max)
-984.4mV  -27.52mA   -20.98mA   -36.83mA
-738.3mV  -14.86mA   -11.51mA   -19.71mA
-639.8mV  -10.04mA   -7.906mA   -13.38mA
-590.6mV  -7.836mA   -6.26mA    -10.46mA
-492.2mV  -4.065mA   -3.445mA   -5.32mA
-443mV    -2.601mA   -2.343mA   -3.27mA
-393.7mV  -1.488mA   -1.479mA   -1.705mA
-344.5mV  -752.6uA   -861.2uA   -730.4uA
-295.3mV  -360.6uA   -471.6uA   -308.6uA
-196.9mV  -143.8uA   -162.9uA   -160.9uA
-49.22mV  -116uA     -99.1uA    -145.8uA
3V        0A         0A         0A
[POWER Clamp]
| Voltage   I(typ)   I(min)   I(max)
-1.5V     66.68mA    56.94mA    89.5mA
-1.378V   57.1mA     48.68mA    76.77mA
-1.083V   36.37mA    30mA       50.67mA
-935.2mV  26.53mA    21.65mA    36.81mA
-738.3mV  14.34mA    11.83mA    18.94mA
-590.6mV  6.46mA     5.758mA    7.505mA
-541.4mV  4.304mA    4.076mA    4.577mA
-492.2mV  2.523mA    2.637mA    2.357mA
-443mV    1.219mA    1.504mA    952.6uA
-344.5mV  140.1uA    299.1uA    81.87uA
-196.9mV  20.92uA    25.77uA    23.8uA
3V        0A         0A         0A
